###############################################################
#  Generated by:      Cadence Innovus 21.14-s109_1
#  OS:                Linux x86_64(Host ID caen-vnc-mi14.engin.umich.edu)
#  Generated on:      Mon Apr  3 20:47:09 2023
#  Design:            PE_POOL
#  Command:           write_lef_abstract /afs/umich.edu/class/eecs627/w23/groups/group4/CNN_LSTM/CNN_POOL_ReLU/apr/PE_POOL/data/PE_POOL.lef -specifyTopLayer 4 -stripePin -PGpinLayers 4
###############################################################

VERSION 5.8 ;

BUSBITCHARS "[]" ;
DIVIDERCHAR "/" ;

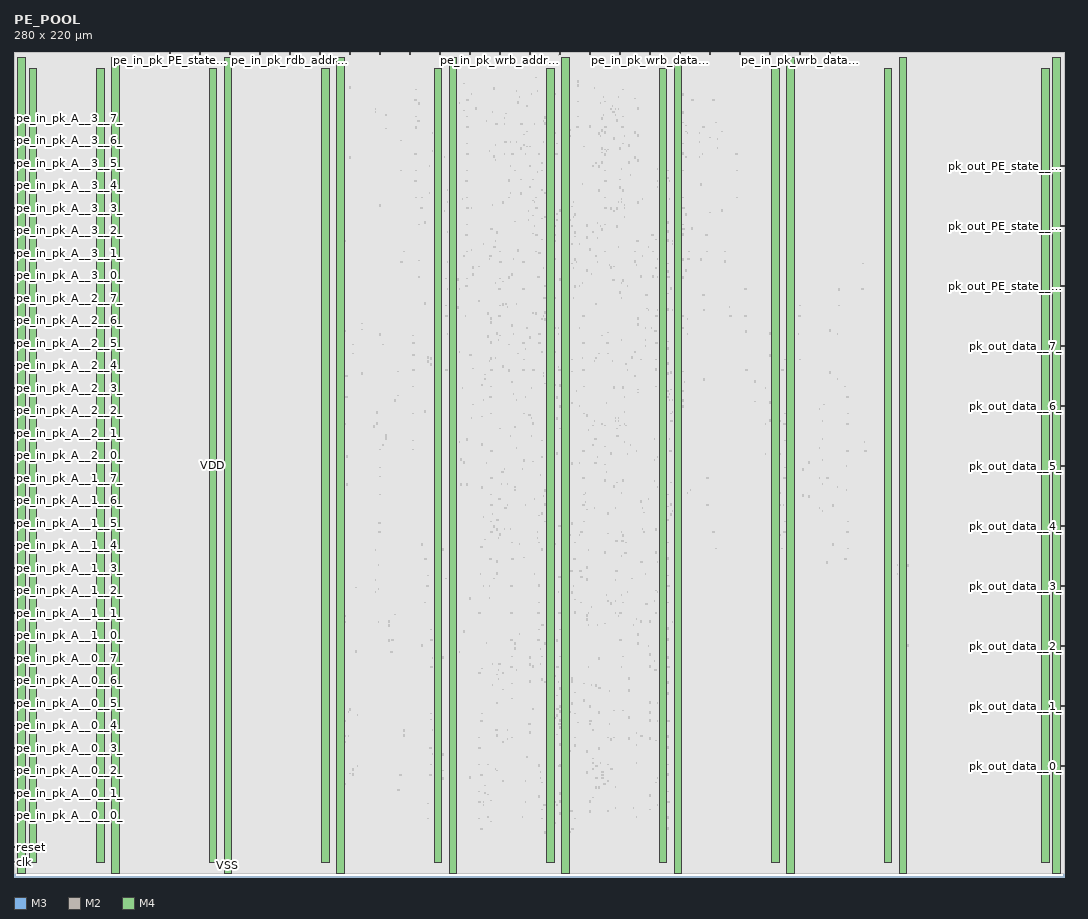
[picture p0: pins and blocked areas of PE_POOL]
MACRO PE_POOL
  CLASS BLOCK ;
  SIZE 280.000000 BY 220.000000 ;
  FOREIGN PE_POOL 0.000000 0.000000 ;
  ORIGIN 0 0 ;
  SYMMETRY X Y R90 ;
  PIN clk
    DIRECTION INPUT ;
    USE SIGNAL ;
    ANTENNAPARTIALMETALAREA 1.82 LAYER M3  ;
    ANTENNAPARTIALMETALSIDEAREA 0.0182 LAYER M3  ;
    ANTENNAPARTIALCUTAREA 0.08 LAYER V3  ;
    ANTENNAPARTIALMETALAREA 1.16 LAYER M4  ;
    ANTENNAPARTIALMETALSIDEAREA 0.012 LAYER M4  ;
    ANTENNAMODEL OXIDE1 ;
    ANTENNAGATEAREA 0.8352 LAYER M4  ;
    ANTENNAMAXAREACAR 2.23946 LAYER M4  ;
    ANTENNAMAXSIDEAREACAR 0.023683 LAYER M4  ;
    ANTENNAMAXCUTCAR 0.287356 LAYER V4  ;
    PORT
      LAYER M3 ;
        RECT 0.000000 3.900000 0.600000 4.100000 ;
    END
  END clk
  PIN reset
    DIRECTION INPUT ;
    USE SIGNAL ;
    ANTENNAPARTIALMETALAREA 1.46 LAYER M3  ;
    ANTENNAPARTIALMETALSIDEAREA 0.015 LAYER M3  ;
    ANTENNAMODEL OXIDE1 ;
    ANTENNAGATEAREA 0.408 LAYER M3  ;
    ANTENNAMAXAREACAR 7.22574 LAYER M3  ;
    ANTENNAMAXSIDEAREACAR 0.0705392 LAYER M3  ;
    ANTENNAMAXCUTCAR 0.392157 LAYER V3  ;
    PORT
      LAYER M3 ;
        RECT 0.000000 7.900000 0.600000 8.100000 ;
    END
  END reset
  PIN pe_in_pk_A__3__7_
    DIRECTION INPUT ;
    USE SIGNAL ;
    ANTENNAPARTIALMETALAREA 1.74 LAYER M3  ;
    ANTENNAPARTIALMETALSIDEAREA 0.0174 LAYER M3  ;
    ANTENNAMODEL OXIDE1 ;
    ANTENNAGATEAREA 0.0624 LAYER M3  ;
    ANTENNAMAXAREACAR 36.0897 LAYER M3  ;
    ANTENNAMAXSIDEAREACAR 0.367949 LAYER M3  ;
    ANTENNAMAXCUTCAR 1.92308 LAYER V3  ;
    PORT
      LAYER M3 ;
        RECT 0.000000 202.300000 0.600000 202.500000 ;
    END
  END pe_in_pk_A__3__7_
  PIN pe_in_pk_A__3__6_
    DIRECTION INPUT ;
    USE SIGNAL ;
    ANTENNAPARTIALMETALAREA 1.66 LAYER M3  ;
    ANTENNAPARTIALMETALSIDEAREA 0.0166 LAYER M3  ;
    ANTENNAMODEL OXIDE1 ;
    ANTENNAGATEAREA 0.0624 LAYER M3  ;
    ANTENNAMAXAREACAR 39.9359 LAYER M3  ;
    ANTENNAMAXSIDEAREACAR 0.40641 LAYER M3  ;
    ANTENNAMAXCUTCAR 1.92308 LAYER V3  ;
    PORT
      LAYER M3 ;
        RECT 0.000000 196.300000 0.600000 196.500000 ;
    END
  END pe_in_pk_A__3__6_
  PIN pe_in_pk_A__3__5_
    DIRECTION INPUT ;
    USE SIGNAL ;
    ANTENNAPARTIALMETALAREA 1.9 LAYER M3  ;
    ANTENNAPARTIALMETALSIDEAREA 0.019 LAYER M3  ;
    ANTENNAPARTIALCUTAREA 0.08 LAYER V3  ;
    ANTENNAPARTIALMETALAREA 1.32 LAYER M4  ;
    ANTENNAPARTIALMETALSIDEAREA 0.0136 LAYER M4  ;
    ANTENNAMODEL OXIDE1 ;
    ANTENNAGATEAREA 0.0624 LAYER M4  ;
    ANTENNAMAXAREACAR 27.4359 LAYER M4  ;
    ANTENNAMAXSIDEAREACAR 0.294231 LAYER M4  ;
    ANTENNAMAXCUTCAR 3.20513 LAYER V4  ;
    PORT
      LAYER M3 ;
        RECT 0.000000 190.300000 0.600000 190.500000 ;
    END
  END pe_in_pk_A__3__5_
  PIN pe_in_pk_A__3__4_
    DIRECTION INPUT ;
    USE SIGNAL ;
    ANTENNAPARTIALMETALAREA 2.02 LAYER M3  ;
    ANTENNAPARTIALMETALSIDEAREA 0.0206 LAYER M3  ;
    ANTENNAMODEL OXIDE1 ;
    ANTENNAGATEAREA 0.0624 LAYER M3  ;
    ANTENNAMAXAREACAR 38.0128 LAYER M3  ;
    ANTENNAMAXSIDEAREACAR 0.39359 LAYER M3  ;
    ANTENNAMAXCUTCAR 1.92308 LAYER V3  ;
    PORT
      LAYER M3 ;
        RECT 0.000000 184.300000 0.600000 184.500000 ;
    END
  END pe_in_pk_A__3__4_
  PIN pe_in_pk_A__3__3_
    DIRECTION INPUT ;
    USE SIGNAL ;
    ANTENNAPARTIALMETALAREA 1.66 LAYER M3  ;
    ANTENNAPARTIALMETALSIDEAREA 0.0166 LAYER M3  ;
    ANTENNAMODEL OXIDE1 ;
    ANTENNAGATEAREA 0.0624 LAYER M3  ;
    ANTENNAMAXAREACAR 51.4744 LAYER M3  ;
    ANTENNAMAXSIDEAREACAR 0.521795 LAYER M3  ;
    ANTENNAMAXCUTCAR 1.92308 LAYER V3  ;
    PORT
      LAYER M3 ;
        RECT 0.000000 178.300000 0.600000 178.500000 ;
    END
  END pe_in_pk_A__3__3_
  PIN pe_in_pk_A__3__2_
    DIRECTION INPUT ;
    USE SIGNAL ;
    ANTENNAPARTIALMETALAREA 1.82 LAYER M3  ;
    ANTENNAPARTIALMETALSIDEAREA 0.0182 LAYER M3  ;
    ANTENNAMODEL OXIDE1 ;
    ANTENNAGATEAREA 0.0624 LAYER M3  ;
    ANTENNAMAXAREACAR 50.1923 LAYER M3  ;
    ANTENNAMAXSIDEAREACAR 0.508974 LAYER M3  ;
    ANTENNAMAXCUTCAR 1.92308 LAYER V3  ;
    PORT
      LAYER M3 ;
        RECT 0.000000 172.300000 0.600000 172.500000 ;
    END
  END pe_in_pk_A__3__2_
  PIN pe_in_pk_A__3__1_
    DIRECTION INPUT ;
    USE SIGNAL ;
    ANTENNAPARTIALMETALAREA 2.38 LAYER M3  ;
    ANTENNAPARTIALMETALSIDEAREA 0.0238 LAYER M3  ;
    ANTENNAMODEL OXIDE1 ;
    ANTENNAGATEAREA 0.0624 LAYER M3  ;
    ANTENNAMAXAREACAR 68.141 LAYER M3  ;
    ANTENNAMAXSIDEAREACAR 0.688462 LAYER M3  ;
    ANTENNAMAXCUTCAR 1.92308 LAYER V3  ;
    PORT
      LAYER M3 ;
        RECT 0.000000 166.300000 0.600000 166.500000 ;
    END
  END pe_in_pk_A__3__1_
  PIN pe_in_pk_A__3__0_
    DIRECTION INPUT ;
    USE SIGNAL ;
    ANTENNAPARTIALMETALAREA 1.9 LAYER M3  ;
    ANTENNAPARTIALMETALSIDEAREA 0.019 LAYER M3  ;
    ANTENNAMODEL OXIDE1 ;
    ANTENNAGATEAREA 0.0624 LAYER M3  ;
    ANTENNAMAXAREACAR 79.6795 LAYER M3  ;
    ANTENNAMAXSIDEAREACAR 0.803846 LAYER M3  ;
    ANTENNAMAXCUTCAR 1.92308 LAYER V3  ;
    PORT
      LAYER M3 ;
        RECT 0.000000 160.300000 0.600000 160.500000 ;
    END
  END pe_in_pk_A__3__0_
  PIN pe_in_pk_A__2__7_
    DIRECTION INPUT ;
    USE SIGNAL ;
    ANTENNAPARTIALMETALAREA 1.5 LAYER M3  ;
    ANTENNAPARTIALMETALSIDEAREA 0.015 LAYER M3  ;
    ANTENNAMODEL OXIDE1 ;
    ANTENNAGATEAREA 0.0624 LAYER M3  ;
    ANTENNAMAXAREACAR 55.3205 LAYER M3  ;
    ANTENNAMAXSIDEAREACAR 0.560256 LAYER M3  ;
    ANTENNAMAXCUTCAR 1.92308 LAYER V3  ;
    PORT
      LAYER M3 ;
        RECT 0.000000 154.300000 0.600000 154.500000 ;
    END
  END pe_in_pk_A__2__7_
  PIN pe_in_pk_A__2__6_
    DIRECTION INPUT ;
    USE SIGNAL ;
    ANTENNAPARTIALMETALAREA 1.58 LAYER M3  ;
    ANTENNAPARTIALMETALSIDEAREA 0.0158 LAYER M3  ;
    ANTENNAMODEL OXIDE1 ;
    ANTENNAGATEAREA 0.0624 LAYER M3  ;
    ANTENNAMAXAREACAR 43.7821 LAYER M3  ;
    ANTENNAMAXSIDEAREACAR 0.444872 LAYER M3  ;
    ANTENNAMAXCUTCAR 1.92308 LAYER V3  ;
    PORT
      LAYER M3 ;
        RECT 0.000000 148.300000 0.600000 148.500000 ;
    END
  END pe_in_pk_A__2__6_
  PIN pe_in_pk_A__2__5_
    DIRECTION INPUT ;
    USE SIGNAL ;
    ANTENNAPARTIALMETALAREA 2.34 LAYER M3  ;
    ANTENNAPARTIALMETALSIDEAREA 0.0238 LAYER M3  ;
    ANTENNAMODEL OXIDE1 ;
    ANTENNAGATEAREA 0.0624 LAYER M3  ;
    ANTENNAMAXAREACAR 45.7051 LAYER M3  ;
    ANTENNAMAXSIDEAREACAR 0.470513 LAYER M3  ;
    ANTENNAMAXCUTCAR 1.92308 LAYER V3  ;
    PORT
      LAYER M3 ;
        RECT 0.000000 142.300000 0.600000 142.500000 ;
    END
  END pe_in_pk_A__2__5_
  PIN pe_in_pk_A__2__4_
    DIRECTION INPUT ;
    USE SIGNAL ;
    ANTENNAPARTIALMETALAREA 2.06 LAYER M3  ;
    ANTENNAPARTIALMETALSIDEAREA 0.0206 LAYER M3  ;
    ANTENNAMODEL OXIDE1 ;
    ANTENNAGATEAREA 0.0624 LAYER M3  ;
    ANTENNAMAXAREACAR 43.7821 LAYER M3  ;
    ANTENNAMAXSIDEAREACAR 0.444872 LAYER M3  ;
    ANTENNAMAXCUTCAR 1.92308 LAYER V3  ;
    PORT
      LAYER M3 ;
        RECT 0.000000 136.300000 0.600000 136.500000 ;
    END
  END pe_in_pk_A__2__4_
  PIN pe_in_pk_A__2__3_
    DIRECTION INPUT ;
    USE SIGNAL ;
    ANTENNAPARTIALMETALAREA 2.06 LAYER M3  ;
    ANTENNAPARTIALMETALSIDEAREA 0.0206 LAYER M3  ;
    ANTENNAMODEL OXIDE1 ;
    ANTENNAGATEAREA 0.0624 LAYER M3  ;
    ANTENNAMAXAREACAR 48.9103 LAYER M3  ;
    ANTENNAMAXSIDEAREACAR 0.496154 LAYER M3  ;
    ANTENNAMAXCUTCAR 1.92308 LAYER V3  ;
    PORT
      LAYER M3 ;
        RECT 0.000000 130.300000 0.600000 130.500000 ;
    END
  END pe_in_pk_A__2__3_
  PIN pe_in_pk_A__2__2_
    DIRECTION INPUT ;
    USE SIGNAL ;
    ANTENNAPARTIALMETALAREA 1.82 LAYER M3  ;
    ANTENNAPARTIALMETALSIDEAREA 0.0182 LAYER M3  ;
    ANTENNAMODEL OXIDE1 ;
    ANTENNAGATEAREA 0.0624 LAYER M3  ;
    ANTENNAMAXAREACAR 33.5256 LAYER M3  ;
    ANTENNAMAXSIDEAREACAR 0.342308 LAYER M3  ;
    ANTENNAMAXCUTCAR 1.92308 LAYER V3  ;
    PORT
      LAYER M3 ;
        RECT 0.000000 124.300000 0.600000 124.500000 ;
    END
  END pe_in_pk_A__2__2_
  PIN pe_in_pk_A__2__1_
    DIRECTION INPUT ;
    USE SIGNAL ;
    ANTENNAPARTIALMETALAREA 1.82 LAYER M3  ;
    ANTENNAPARTIALMETALSIDEAREA 0.0182 LAYER M3  ;
    ANTENNAMODEL OXIDE1 ;
    ANTENNAGATEAREA 0.0624 LAYER M3  ;
    ANTENNAMAXAREACAR 38.6538 LAYER M3  ;
    ANTENNAMAXSIDEAREACAR 0.39359 LAYER M3  ;
    ANTENNAMAXCUTCAR 1.92308 LAYER V3  ;
    PORT
      LAYER M3 ;
        RECT 0.000000 118.300000 0.600000 118.500000 ;
    END
  END pe_in_pk_A__2__1_
  PIN pe_in_pk_A__2__0_
    DIRECTION INPUT ;
    USE SIGNAL ;
    ANTENNAPARTIALMETALAREA 1.9 LAYER M3  ;
    ANTENNAPARTIALMETALSIDEAREA 0.019 LAYER M3  ;
    ANTENNAMODEL OXIDE1 ;
    ANTENNAGATEAREA 0.0624 LAYER M3  ;
    ANTENNAMAXAREACAR 36.0897 LAYER M3  ;
    ANTENNAMAXSIDEAREACAR 0.367949 LAYER M3  ;
    ANTENNAMAXCUTCAR 1.92308 LAYER V3  ;
    PORT
      LAYER M3 ;
        RECT 0.000000 112.300000 0.600000 112.500000 ;
    END
  END pe_in_pk_A__2__0_
  PIN pe_in_pk_A__1__7_
    DIRECTION INPUT ;
    USE SIGNAL ;
    ANTENNAPARTIALMETALAREA 1.82 LAYER M3  ;
    ANTENNAPARTIALMETALSIDEAREA 0.0182 LAYER M3  ;
    ANTENNAMODEL OXIDE1 ;
    ANTENNAGATEAREA 0.0624 LAYER M3  ;
    ANTENNAMAXAREACAR 36.0897 LAYER M3  ;
    ANTENNAMAXSIDEAREACAR 0.367949 LAYER M3  ;
    ANTENNAMAXCUTCAR 1.92308 LAYER V3  ;
    PORT
      LAYER M3 ;
        RECT 0.000000 106.300000 0.600000 106.500000 ;
    END
  END pe_in_pk_A__1__7_
  PIN pe_in_pk_A__1__6_
    DIRECTION INPUT ;
    USE SIGNAL ;
    ANTENNAPARTIALMETALAREA 1.9 LAYER M3  ;
    ANTENNAPARTIALMETALSIDEAREA 0.019 LAYER M3  ;
    ANTENNAMODEL OXIDE1 ;
    ANTENNAGATEAREA 0.0624 LAYER M3  ;
    ANTENNAMAXAREACAR 39.9359 LAYER M3  ;
    ANTENNAMAXSIDEAREACAR 0.40641 LAYER M3  ;
    ANTENNAMAXCUTCAR 1.92308 LAYER V3  ;
    PORT
      LAYER M3 ;
        RECT 0.000000 100.300000 0.600000 100.500000 ;
    END
  END pe_in_pk_A__1__6_
  PIN pe_in_pk_A__1__5_
    DIRECTION INPUT ;
    USE SIGNAL ;
    ANTENNAPARTIALMETALAREA 1.58 LAYER M3  ;
    ANTENNAPARTIALMETALSIDEAREA 0.0158 LAYER M3  ;
    ANTENNAMODEL OXIDE1 ;
    ANTENNAGATEAREA 0.0624 LAYER M3  ;
    ANTENNAMAXAREACAR 33.5256 LAYER M3  ;
    ANTENNAMAXSIDEAREACAR 0.342308 LAYER M3  ;
    ANTENNAMAXCUTCAR 1.92308 LAYER V3  ;
    PORT
      LAYER M3 ;
        RECT 0.000000 94.300000 0.600000 94.500000 ;
    END
  END pe_in_pk_A__1__5_
  PIN pe_in_pk_A__1__4_
    DIRECTION INPUT ;
    USE SIGNAL ;
    ANTENNAPARTIALMETALAREA 2.06 LAYER M3  ;
    ANTENNAPARTIALMETALSIDEAREA 0.0206 LAYER M3  ;
    ANTENNAMODEL OXIDE1 ;
    ANTENNAGATEAREA 0.0624 LAYER M3  ;
    ANTENNAMAXAREACAR 59.1667 LAYER M3  ;
    ANTENNAMAXSIDEAREACAR 0.598718 LAYER M3  ;
    ANTENNAMAXCUTCAR 1.92308 LAYER V3  ;
    PORT
      LAYER M3 ;
        RECT 0.000000 88.300000 0.600000 88.500000 ;
    END
  END pe_in_pk_A__1__4_
  PIN pe_in_pk_A__1__3_
    DIRECTION INPUT ;
    USE SIGNAL ;
    ANTENNAPARTIALMETALAREA 1.5 LAYER M3  ;
    ANTENNAPARTIALMETALSIDEAREA 0.015 LAYER M3  ;
    ANTENNAMODEL OXIDE1 ;
    ANTENNAGATEAREA 0.0624 LAYER M3  ;
    ANTENNAMAXAREACAR 30.9615 LAYER M3  ;
    ANTENNAMAXSIDEAREACAR 0.316667 LAYER M3  ;
    ANTENNAMAXCUTCAR 1.92308 LAYER V3  ;
    PORT
      LAYER M3 ;
        RECT 0.000000 82.300000 0.600000 82.500000 ;
    END
  END pe_in_pk_A__1__3_
  PIN pe_in_pk_A__1__2_
    DIRECTION INPUT ;
    USE SIGNAL ;
    ANTENNAPARTIALMETALAREA 1.42 LAYER M3  ;
    ANTENNAPARTIALMETALSIDEAREA 0.0142 LAYER M3  ;
    ANTENNAMODEL OXIDE1 ;
    ANTENNAGATEAREA 0.0624 LAYER M3  ;
    ANTENNAMAXAREACAR 57.8846 LAYER M3  ;
    ANTENNAMAXSIDEAREACAR 0.585897 LAYER M3  ;
    ANTENNAMAXCUTCAR 1.92308 LAYER V3  ;
    PORT
      LAYER M3 ;
        RECT 0.000000 76.300000 0.600000 76.500000 ;
    END
  END pe_in_pk_A__1__2_
  PIN pe_in_pk_A__1__1_
    DIRECTION INPUT ;
    USE SIGNAL ;
    ANTENNAPARTIALMETALAREA 1.42 LAYER M3  ;
    ANTENNAPARTIALMETALSIDEAREA 0.0142 LAYER M3  ;
    ANTENNAMODEL OXIDE1 ;
    ANTENNAGATEAREA 0.0624 LAYER M3  ;
    ANTENNAMAXAREACAR 52.7564 LAYER M3  ;
    ANTENNAMAXSIDEAREACAR 0.534615 LAYER M3  ;
    ANTENNAMAXCUTCAR 1.92308 LAYER V3  ;
    PORT
      LAYER M3 ;
        RECT 0.000000 70.300000 0.600000 70.500000 ;
    END
  END pe_in_pk_A__1__1_
  PIN pe_in_pk_A__1__0_
    DIRECTION INPUT ;
    USE SIGNAL ;
    ANTENNAPARTIALMETALAREA 0.7 LAYER M3  ;
    ANTENNAPARTIALMETALSIDEAREA 0.007 LAYER M3  ;
    ANTENNAPARTIALCUTAREA 0.08 LAYER V3  ;
    ANTENNAPARTIALMETALAREA 1.88 LAYER M4  ;
    ANTENNAPARTIALMETALSIDEAREA 0.0192 LAYER M4  ;
    ANTENNAMODEL OXIDE1 ;
    ANTENNAGATEAREA 0.0624 LAYER M4  ;
    ANTENNAMAXAREACAR 51.7949 LAYER M4  ;
    ANTENNAMAXSIDEAREACAR 0.537821 LAYER M4  ;
    ANTENNAMAXCUTCAR 3.20513 LAYER V4  ;
    PORT
      LAYER M3 ;
        RECT 0.000000 64.300000 0.600000 64.500000 ;
    END
  END pe_in_pk_A__1__0_
  PIN pe_in_pk_A__0__7_
    DIRECTION INPUT ;
    USE SIGNAL ;
    ANTENNAPARTIALMETALAREA 2.02 LAYER M3  ;
    ANTENNAPARTIALMETALSIDEAREA 0.0206 LAYER M3  ;
    ANTENNAMODEL OXIDE1 ;
    ANTENNAGATEAREA 0.0624 LAYER M3  ;
    ANTENNAMAXAREACAR 43.141 LAYER M3  ;
    ANTENNAMAXSIDEAREACAR 0.444872 LAYER M3  ;
    ANTENNAMAXCUTCAR 1.92308 LAYER V3  ;
    PORT
      LAYER M3 ;
        RECT 0.000000 58.300000 0.600000 58.500000 ;
    END
  END pe_in_pk_A__0__7_
  PIN pe_in_pk_A__0__6_
    DIRECTION INPUT ;
    USE SIGNAL ;
    ANTENNAPARTIALMETALAREA 1.98 LAYER M3  ;
    ANTENNAPARTIALMETALSIDEAREA 0.0198 LAYER M3  ;
    ANTENNAMODEL OXIDE1 ;
    ANTENNAGATEAREA 0.0624 LAYER M3  ;
    ANTENNAMAXAREACAR 51.4744 LAYER M3  ;
    ANTENNAMAXSIDEAREACAR 0.521795 LAYER M3  ;
    ANTENNAMAXCUTCAR 1.92308 LAYER V3  ;
    PORT
      LAYER M3 ;
        RECT 0.000000 52.300000 0.600000 52.500000 ;
    END
  END pe_in_pk_A__0__6_
  PIN pe_in_pk_A__0__5_
    DIRECTION INPUT ;
    USE SIGNAL ;
    ANTENNAPARTIALMETALAREA 1.74 LAYER M3  ;
    ANTENNAPARTIALMETALSIDEAREA 0.0174 LAYER M3  ;
    ANTENNAMODEL OXIDE1 ;
    ANTENNAGATEAREA 0.0624 LAYER M3  ;
    ANTENNAMAXAREACAR 34.8077 LAYER M3  ;
    ANTENNAMAXSIDEAREACAR 0.355128 LAYER M3  ;
    ANTENNAMAXCUTCAR 1.92308 LAYER V3  ;
    PORT
      LAYER M3 ;
        RECT 0.000000 46.300000 0.600000 46.500000 ;
    END
  END pe_in_pk_A__0__5_
  PIN pe_in_pk_A__0__4_
    DIRECTION INPUT ;
    USE SIGNAL ;
    ANTENNAPARTIALMETALAREA 1.74 LAYER M3  ;
    ANTENNAPARTIALMETALSIDEAREA 0.0174 LAYER M3  ;
    ANTENNAMODEL OXIDE1 ;
    ANTENNAGATEAREA 0.0624 LAYER M3  ;
    ANTENNAMAXAREACAR 38.6538 LAYER M3  ;
    ANTENNAMAXSIDEAREACAR 0.39359 LAYER M3  ;
    ANTENNAMAXCUTCAR 1.92308 LAYER V3  ;
    PORT
      LAYER M3 ;
        RECT 0.000000 40.300000 0.600000 40.500000 ;
    END
  END pe_in_pk_A__0__4_
  PIN pe_in_pk_A__0__3_
    DIRECTION INPUT ;
    USE SIGNAL ;
    ANTENNAPARTIALMETALAREA 1.74 LAYER M3  ;
    ANTENNAPARTIALMETALSIDEAREA 0.0174 LAYER M3  ;
    ANTENNAMODEL OXIDE1 ;
    ANTENNAGATEAREA 0.0624 LAYER M3  ;
    ANTENNAMAXAREACAR 33.5256 LAYER M3  ;
    ANTENNAMAXSIDEAREACAR 0.342308 LAYER M3  ;
    ANTENNAMAXCUTCAR 1.92308 LAYER V3  ;
    PORT
      LAYER M3 ;
        RECT 0.000000 34.300000 0.600000 34.500000 ;
    END
  END pe_in_pk_A__0__3_
  PIN pe_in_pk_A__0__2_
    DIRECTION INPUT ;
    USE SIGNAL ;
    ANTENNAPARTIALMETALAREA 1.74 LAYER M3  ;
    ANTENNAPARTIALMETALSIDEAREA 0.0174 LAYER M3  ;
    ANTENNAMODEL OXIDE1 ;
    ANTENNAGATEAREA 0.0624 LAYER M3  ;
    ANTENNAMAXAREACAR 37.3718 LAYER M3  ;
    ANTENNAMAXSIDEAREACAR 0.380769 LAYER M3  ;
    ANTENNAMAXCUTCAR 1.92308 LAYER V3  ;
    PORT
      LAYER M3 ;
        RECT 0.000000 28.300000 0.600000 28.500000 ;
    END
  END pe_in_pk_A__0__2_
  PIN pe_in_pk_A__0__1_
    DIRECTION INPUT ;
    USE SIGNAL ;
    ANTENNAPARTIALMETALAREA 1.74 LAYER M3  ;
    ANTENNAPARTIALMETALSIDEAREA 0.0174 LAYER M3  ;
    ANTENNAMODEL OXIDE1 ;
    ANTENNAGATEAREA 0.0624 LAYER M3  ;
    ANTENNAMAXAREACAR 34.8077 LAYER M3  ;
    ANTENNAMAXSIDEAREACAR 0.355128 LAYER M3  ;
    ANTENNAMAXCUTCAR 1.92308 LAYER V3  ;
    PORT
      LAYER M3 ;
        RECT 0.000000 22.300000 0.600000 22.500000 ;
    END
  END pe_in_pk_A__0__1_
  PIN pe_in_pk_A__0__0_
    DIRECTION INPUT ;
    USE SIGNAL ;
    ANTENNAPARTIALMETALAREA 1.66 LAYER M3  ;
    ANTENNAPARTIALMETALSIDEAREA 0.0166 LAYER M3  ;
    ANTENNAMODEL OXIDE1 ;
    ANTENNAGATEAREA 0.0624 LAYER M3  ;
    ANTENNAMAXAREACAR 30.9615 LAYER M3  ;
    ANTENNAMAXSIDEAREACAR 0.316667 LAYER M3  ;
    ANTENNAMAXCUTCAR 1.92308 LAYER V3  ;
    PORT
      LAYER M3 ;
        RECT 0.000000 16.300000 0.600000 16.500000 ;
    END
  END pe_in_pk_A__0__0_
  PIN pe_in_pk_PE_state__2_
    DIRECTION INPUT ;
    USE SIGNAL ;
    ANTENNAPARTIALMETALAREA 0.06 LAYER M2  ;
    ANTENNAPARTIALMETALSIDEAREA 0.0006 LAYER M2  ;
    ANTENNAPARTIALCUTAREA 0.04 LAYER V2  ;
    ANTENNAPARTIALMETALAREA 3.64 LAYER M3  ;
    ANTENNAPARTIALMETALSIDEAREA 0.0368 LAYER M3  ;
    ANTENNAMODEL OXIDE1 ;
    ANTENNAGATEAREA 0.0624 LAYER M3  ;
    ANTENNAMAXAREACAR 89.6154 LAYER M3  ;
    ANTENNAMAXSIDEAREACAR 0.909615 LAYER M3  ;
    ANTENNAMAXCUTCAR 1.92308 LAYER V3  ;
    PORT
      LAYER M2 ;
        RECT 57.500000 219.400000 57.700000 220.000000 ;
    END
  END pe_in_pk_PE_state__2_
  PIN pe_in_pk_PE_state__1_
    DIRECTION INPUT ;
    USE SIGNAL ;
    ANTENNAPARTIALMETALAREA 1.34 LAYER M2  ;
    ANTENNAPARTIALMETALSIDEAREA 0.0134 LAYER M2  ;
    ANTENNAPARTIALCUTAREA 0.08 LAYER V2  ;
    ANTENNAPARTIALMETALAREA 3.88 LAYER M3  ;
    ANTENNAPARTIALMETALSIDEAREA 0.0392 LAYER M3  ;
    ANTENNAMODEL OXIDE1 ;
    ANTENNAGATEAREA 0.0624 LAYER M3  ;
    ANTENNAMAXAREACAR 72.9487 LAYER M3  ;
    ANTENNAMAXSIDEAREACAR 0.742949 LAYER M3  ;
    ANTENNAMAXCUTCAR 1.92308 LAYER V3  ;
    PORT
      LAYER M2 ;
        RECT 49.500000 219.400000 49.700000 220.000000 ;
    END
  END pe_in_pk_PE_state__1_
  PIN pe_in_pk_PE_state__0_
    DIRECTION INPUT ;
    USE SIGNAL ;
    ANTENNAPARTIALMETALAREA 0.16 LAYER M2  ;
    ANTENNAPARTIALMETALSIDEAREA 0.0016 LAYER M2  ;
    ANTENNAPARTIALCUTAREA 0.08 LAYER V2  ;
    ANTENNAPARTIALMETALAREA 5.8 LAYER M3  ;
    ANTENNAPARTIALMETALSIDEAREA 0.0584 LAYER M3  ;
    ANTENNAMODEL OXIDE1 ;
    ANTENNAGATEAREA 0.0624 LAYER M3  ;
    ANTENNAMAXAREACAR 140.897 LAYER M3  ;
    ANTENNAMAXSIDEAREACAR 1.42244 LAYER M3  ;
    ANTENNAMAXCUTCAR 1.92308 LAYER V3  ;
    PORT
      LAYER M2 ;
        RECT 41.500000 219.400000 41.700000 220.000000 ;
    END
  END pe_in_pk_PE_state__0_
  PIN pe_in_pk_wrb_data__7_
    DIRECTION INPUT ;
    USE SIGNAL ;
    ANTENNAPARTIALMETALAREA 1.34 LAYER M2  ;
    ANTENNAPARTIALMETALSIDEAREA 0.0134 LAYER M2  ;
    ANTENNAPARTIALCUTAREA 0.08 LAYER V2  ;
    ANTENNAPARTIALMETALAREA 4.92 LAYER M3  ;
    ANTENNAPARTIALMETALSIDEAREA 0.0496 LAYER M3  ;
    ANTENNAMODEL OXIDE1 ;
    ANTENNAGATEAREA 0.0624 LAYER M3  ;
    ANTENNAMAXAREACAR 89.6154 LAYER M3  ;
    ANTENNAMAXSIDEAREACAR 0.909615 LAYER M3  ;
    ANTENNAMAXCUTCAR 1.92308 LAYER V3  ;
    PORT
      LAYER M2 ;
        RECT 217.500000 219.400000 217.700000 220.000000 ;
    END
  END pe_in_pk_wrb_data__7_
  PIN pe_in_pk_wrb_data__6_
    DIRECTION INPUT ;
    USE SIGNAL ;
    ANTENNAPARTIALMETALAREA 1.9 LAYER M2  ;
    ANTENNAPARTIALMETALSIDEAREA 0.019 LAYER M2  ;
    ANTENNAPARTIALCUTAREA 0.08 LAYER V2  ;
    ANTENNAPARTIALMETALAREA 3.56 LAYER M3  ;
    ANTENNAPARTIALMETALSIDEAREA 0.036 LAYER M3  ;
    ANTENNAMODEL OXIDE1 ;
    ANTENNAGATEAREA 0.0624 LAYER M3  ;
    ANTENNAMAXAREACAR 61.4103 LAYER M3  ;
    ANTENNAMAXSIDEAREACAR 0.627564 LAYER M3  ;
    ANTENNAMAXCUTCAR 1.92308 LAYER V3  ;
    PORT
      LAYER M2 ;
        RECT 209.500000 219.400000 209.700000 220.000000 ;
    END
  END pe_in_pk_wrb_data__6_
  PIN pe_in_pk_wrb_data__5_
    DIRECTION INPUT ;
    USE SIGNAL ;
    ANTENNAPARTIALMETALAREA 1.5 LAYER M2  ;
    ANTENNAPARTIALMETALSIDEAREA 0.015 LAYER M2  ;
    ANTENNAPARTIALCUTAREA 0.08 LAYER V2  ;
    ANTENNAPARTIALMETALAREA 1.24 LAYER M3  ;
    ANTENNAPARTIALMETALSIDEAREA 0.0128 LAYER M3  ;
    ANTENNAMODEL OXIDE1 ;
    ANTENNAGATEAREA 0.0624 LAYER M3  ;
    ANTENNAMAXAREACAR 28.0769 LAYER M3  ;
    ANTENNAMAXSIDEAREACAR 0.294231 LAYER M3  ;
    ANTENNAMAXCUTCAR 1.92308 LAYER V3  ;
    PORT
      LAYER M2 ;
        RECT 201.500000 219.400000 201.700000 220.000000 ;
    END
  END pe_in_pk_wrb_data__5_
  PIN pe_in_pk_wrb_data__4_
    DIRECTION INPUT ;
    USE SIGNAL ;
    ANTENNAPARTIALMETALAREA 1.5 LAYER M2  ;
    ANTENNAPARTIALMETALSIDEAREA 0.015 LAYER M2  ;
    ANTENNAPARTIALCUTAREA 0.08 LAYER V2  ;
    ANTENNAPARTIALMETALAREA 0.84 LAYER M3  ;
    ANTENNAPARTIALMETALSIDEAREA 0.0088 LAYER M3  ;
    ANTENNAMODEL OXIDE1 ;
    ANTENNAGATEAREA 0.2472 LAYER M3  ;
    ANTENNAMAXAREACAR 5.6699 LAYER M3  ;
    ANTENNAMAXSIDEAREACAR 0.0606796 LAYER M3  ;
    ANTENNAMAXCUTCAR 0.485437 LAYER V3  ;
    PORT
      LAYER M2 ;
        RECT 193.500000 219.400000 193.700000 220.000000 ;
    END
  END pe_in_pk_wrb_data__4_
  PIN pe_in_pk_wrb_data__3_
    DIRECTION INPUT ;
    USE SIGNAL ;
    ANTENNAPARTIALMETALAREA 1.42 LAYER M2  ;
    ANTENNAPARTIALMETALSIDEAREA 0.0142 LAYER M2  ;
    ANTENNAPARTIALCUTAREA 0.08 LAYER V2  ;
    ANTENNAPARTIALMETALAREA 1.4 LAYER M3  ;
    ANTENNAPARTIALMETALSIDEAREA 0.0144 LAYER M3  ;
    ANTENNAMODEL OXIDE1 ;
    ANTENNAGATEAREA 0.0624 LAYER M3  ;
    ANTENNAMAXAREACAR 31.9231 LAYER M3  ;
    ANTENNAMAXSIDEAREACAR 0.332692 LAYER M3  ;
    ANTENNAMAXCUTCAR 1.92308 LAYER V3  ;
    PORT
      LAYER M2 ;
        RECT 185.500000 219.400000 185.700000 220.000000 ;
    END
  END pe_in_pk_wrb_data__3_
  PIN pe_in_pk_wrb_data__2_
    DIRECTION INPUT ;
    USE SIGNAL ;
    ANTENNAPARTIALMETALAREA 0.06 LAYER M2  ;
    ANTENNAPARTIALMETALSIDEAREA 0.0006 LAYER M2  ;
    ANTENNAPARTIALCUTAREA 0.04 LAYER V2  ;
    ANTENNAPARTIALMETALAREA 2.2 LAYER M3  ;
    ANTENNAPARTIALMETALSIDEAREA 0.0224 LAYER M3  ;
    ANTENNAMODEL OXIDE1 ;
    ANTENNAGATEAREA 0.1272 LAYER M3  ;
    ANTENNAMAXAREACAR 33.0818 LAYER M3  ;
    ANTENNAMAXSIDEAREACAR 0.337107 LAYER M3  ;
    ANTENNAMAXCUTCAR 1.25786 LAYER V3  ;
    PORT
      LAYER M2 ;
        RECT 177.500000 219.400000 177.700000 220.000000 ;
    END
  END pe_in_pk_wrb_data__2_
  PIN pe_in_pk_wrb_data__1_
    DIRECTION INPUT ;
    USE SIGNAL ;
    ANTENNAPARTIALMETALAREA 1.5 LAYER M2  ;
    ANTENNAPARTIALMETALSIDEAREA 0.015 LAYER M2  ;
    ANTENNAPARTIALCUTAREA 0.08 LAYER V2  ;
    ANTENNAPARTIALMETALAREA 1.16 LAYER M3  ;
    ANTENNAPARTIALMETALSIDEAREA 0.012 LAYER M3  ;
    ANTENNAMODEL OXIDE1 ;
    ANTENNAGATEAREA 0.0624 LAYER M3  ;
    ANTENNAMAXAREACAR 43.4615 LAYER M3  ;
    ANTENNAMAXSIDEAREACAR 0.448077 LAYER M3  ;
    ANTENNAMAXCUTCAR 1.92308 LAYER V3  ;
    PORT
      LAYER M2 ;
        RECT 169.500000 219.400000 169.700000 220.000000 ;
    END
  END pe_in_pk_wrb_data__1_
  PIN pe_in_pk_wrb_data__0_
    DIRECTION INPUT ;
    USE SIGNAL ;
    ANTENNAPARTIALMETALAREA 1.5 LAYER M2  ;
    ANTENNAPARTIALMETALSIDEAREA 0.015 LAYER M2  ;
    ANTENNAPARTIALCUTAREA 0.08 LAYER V2  ;
    ANTENNAPARTIALMETALAREA 2.44 LAYER M3  ;
    ANTENNAPARTIALMETALSIDEAREA 0.0248 LAYER M3  ;
    ANTENNAPARTIALCUTAREA 0.08 LAYER V3  ;
    ANTENNAPARTIALMETALAREA 0.36 LAYER M4  ;
    ANTENNAPARTIALMETALSIDEAREA 0.004 LAYER M4  ;
    ANTENNAMODEL OXIDE1 ;
    ANTENNAGATEAREA 0.0624 LAYER M4  ;
    ANTENNAMAXAREACAR 24.8718 LAYER M4  ;
    ANTENNAMAXSIDEAREACAR 0.26859 LAYER M4  ;
    ANTENNAMAXCUTCAR 3.20513 LAYER V4  ;
    PORT
      LAYER M2 ;
        RECT 161.500000 219.400000 161.700000 220.000000 ;
    END
  END pe_in_pk_wrb_data__0_
  PIN pe_in_pk_wrb_addr__3_
    DIRECTION INPUT ;
    USE SIGNAL ;
    ANTENNAPARTIALMETALAREA 0.16 LAYER M2  ;
    ANTENNAPARTIALMETALSIDEAREA 0.0016 LAYER M2  ;
    ANTENNAPARTIALCUTAREA 0.08 LAYER V2  ;
    ANTENNAPARTIALMETALAREA 3.84 LAYER M3  ;
    ANTENNAPARTIALMETALSIDEAREA 0.0392 LAYER M3  ;
    ANTENNAMODEL OXIDE1 ;
    ANTENNAGATEAREA 0.564 LAYER M3  ;
    ANTENNAMAXAREACAR 15.4918 LAYER M3  ;
    ANTENNAMAXSIDEAREACAR 0.155261 LAYER M3  ;
    ANTENNAMAXCUTCAR 0.454545 LAYER V3  ;
    PORT
      LAYER M2 ;
        RECT 153.500000 219.400000 153.700000 220.000000 ;
    END
  END pe_in_pk_wrb_addr__3_
  PIN pe_in_pk_wrb_addr__2_
    DIRECTION INPUT ;
    USE SIGNAL ;
    ANTENNAPARTIALMETALAREA 0.06 LAYER M2  ;
    ANTENNAPARTIALMETALSIDEAREA 0.0006 LAYER M2  ;
    ANTENNAPARTIALCUTAREA 0.04 LAYER V2  ;
    ANTENNAPARTIALMETALAREA 2.92 LAYER M3  ;
    ANTENNAPARTIALMETALSIDEAREA 0.0296 LAYER M3  ;
    ANTENNAMODEL OXIDE1 ;
    ANTENNAGATEAREA 0.396 LAYER M3  ;
    ANTENNAMAXAREACAR 12.6061 LAYER M3  ;
    ANTENNAMAXSIDEAREACAR 0.128081 LAYER M3  ;
    ANTENNAPARTIALCUTAREA 0.04 LAYER V3  ;
    ANTENNAMAXCUTCAR 0.30303 LAYER V3  ;
    ANTENNAPARTIALMETALAREA 9.68 LAYER M4  ;
    ANTENNAPARTIALMETALSIDEAREA 0.0976 LAYER M4  ;
    ANTENNAGATEAREA 1.3896 LAYER M4  ;
    ANTENNAMAXAREACAR 19.5721 LAYER M4  ;
    ANTENNAMAXSIDEAREACAR 0.204819 LAYER M4  ;
    ANTENNAMAXCUTCAR 2.41667 LAYER V4  ;
    PORT
      LAYER M2 ;
        RECT 145.500000 219.400000 145.700000 220.000000 ;
    END
  END pe_in_pk_wrb_addr__2_
  PIN pe_in_pk_wrb_addr__1_
    DIRECTION INPUT ;
    USE SIGNAL ;
    ANTENNAPARTIALMETALAREA 0.06 LAYER M2  ;
    ANTENNAPARTIALMETALSIDEAREA 0.0006 LAYER M2  ;
    ANTENNAPARTIALCUTAREA 0.04 LAYER V2  ;
    ANTENNAPARTIALMETALAREA 2.08 LAYER M3  ;
    ANTENNAPARTIALMETALSIDEAREA 0.0216 LAYER M3  ;
    ANTENNAMODEL OXIDE1 ;
    ANTENNAGATEAREA 0.396 LAYER M3  ;
    ANTENNAMAXAREACAR 12.2343 LAYER M3  ;
    ANTENNAMAXSIDEAREACAR 0.128283 LAYER M3  ;
    ANTENNAPARTIALCUTAREA 0.04 LAYER V3  ;
    ANTENNAMAXCUTCAR 0.40404 LAYER V3  ;
    ANTENNAPARTIALMETALAREA 6.6 LAYER M4  ;
    ANTENNAPARTIALMETALSIDEAREA 0.0664 LAYER M4  ;
    ANTENNAGATEAREA 1.1496 LAYER M4  ;
    ANTENNAMAXAREACAR 17.9755 LAYER M4  ;
    ANTENNAMAXSIDEAREACAR 0.186042 LAYER M4  ;
    ANTENNAMAXCUTCAR 0.543275 LAYER V4  ;
    PORT
      LAYER M2 ;
        RECT 137.500000 219.400000 137.700000 220.000000 ;
    END
  END pe_in_pk_wrb_addr__1_
  PIN pe_in_pk_wrb_addr__0_
    DIRECTION INPUT ;
    USE SIGNAL ;
    ANTENNAPARTIALCUTAREA 0.04 LAYER V2  ;
    ANTENNAPARTIALMETALAREA 0.96 LAYER M3  ;
    ANTENNAPARTIALMETALSIDEAREA 0.0104 LAYER M3  ;
    ANTENNAMODEL OXIDE1 ;
    ANTENNAGATEAREA 0.396 LAYER M3  ;
    ANTENNAMAXAREACAR 8.57374 LAYER M3  ;
    ANTENNAMAXSIDEAREACAR 0.090101 LAYER M3  ;
    ANTENNAPARTIALCUTAREA 0.04 LAYER V3  ;
    ANTENNAMAXCUTCAR 0.40404 LAYER V3  ;
    ANTENNAPARTIALMETALAREA 7.56 LAYER M4  ;
    ANTENNAPARTIALMETALSIDEAREA 0.0768 LAYER M4  ;
    ANTENNAGATEAREA 1.1496 LAYER M4  ;
    ANTENNAMAXAREACAR 15.1499 LAYER M4  ;
    ANTENNAMAXSIDEAREACAR 0.156907 LAYER M4  ;
    ANTENNAMAXCUTCAR 1.22549 LAYER V4  ;
    PORT
      LAYER M2 ;
        RECT 129.500000 219.400000 129.700000 220.000000 ;
    END
  END pe_in_pk_wrb_addr__0_
  PIN pe_in_pk_wrb__3_
    DIRECTION INPUT ;
    USE SIGNAL ;
    ANTENNAPARTIALMETALAREA 1.74 LAYER M2  ;
    ANTENNAPARTIALMETALSIDEAREA 0.0174 LAYER M2  ;
    ANTENNAMODEL OXIDE1 ;
    ANTENNAGATEAREA 0.2952 LAYER M2  ;
    ANTENNAMAXAREACAR 6.28455 LAYER M2  ;
    ANTENNAMAXSIDEAREACAR 0.0635501 LAYER M2  ;
    ANTENNAMAXCUTCAR 0.135501 LAYER V2  ;
    PORT
      LAYER M2 ;
        RECT 121.500000 219.400000 121.700000 220.000000 ;
    END
  END pe_in_pk_wrb__3_
  PIN pe_in_pk_wrb__2_
    DIRECTION INPUT ;
    USE SIGNAL ;
    ANTENNAPARTIALMETALAREA 1.58 LAYER M2  ;
    ANTENNAPARTIALMETALSIDEAREA 0.0158 LAYER M2  ;
    ANTENNAPARTIALCUTAREA 0.04 LAYER V2  ;
    ANTENNAPARTIALMETALAREA 1 LAYER M3  ;
    ANTENNAPARTIALMETALSIDEAREA 0.0104 LAYER M3  ;
    ANTENNAMODEL OXIDE1 ;
    ANTENNAGATEAREA 0.5928 LAYER M3  ;
    ANTENNAMAXAREACAR 3.05938 LAYER M3  ;
    ANTENNAMAXSIDEAREACAR 0.0318826 LAYER M3  ;
    ANTENNAMAXCUTCAR 0.134953 LAYER V3  ;
    PORT
      LAYER M2 ;
        RECT 113.500000 219.400000 113.700000 220.000000 ;
    END
  END pe_in_pk_wrb__2_
  PIN pe_in_pk_wrb__1_
    DIRECTION INPUT ;
    USE SIGNAL ;
    ANTENNAPARTIALMETALAREA 1.26 LAYER M2  ;
    ANTENNAPARTIALMETALSIDEAREA 0.0126 LAYER M2  ;
    ANTENNAPARTIALCUTAREA 0.04 LAYER V2  ;
    ANTENNAPARTIALMETALAREA 3.88 LAYER M3  ;
    ANTENNAPARTIALMETALSIDEAREA 0.0392 LAYER M3  ;
    ANTENNAMODEL OXIDE1 ;
    ANTENNAGATEAREA 0.5928 LAYER M3  ;
    ANTENNAMAXAREACAR 8.45749 LAYER M3  ;
    ANTENNAMAXSIDEAREACAR 0.0858637 LAYER M3  ;
    ANTENNAMAXCUTCAR 0.134953 LAYER V3  ;
    PORT
      LAYER M2 ;
        RECT 105.500000 219.400000 105.700000 220.000000 ;
    END
  END pe_in_pk_wrb__1_
  PIN pe_in_pk_wrb__0_
    DIRECTION INPUT ;
    USE SIGNAL ;
    ANTENNAPARTIALMETALAREA 1.42 LAYER M2  ;
    ANTENNAPARTIALMETALSIDEAREA 0.0142 LAYER M2  ;
    ANTENNAPARTIALCUTAREA 0.08 LAYER V2  ;
    ANTENNAPARTIALMETALAREA 6.12 LAYER M3  ;
    ANTENNAPARTIALMETALSIDEAREA 0.0616 LAYER M3  ;
    ANTENNAMODEL OXIDE1 ;
    ANTENNAGATEAREA 0.2952 LAYER M3  ;
    ANTENNAMAXAREACAR 22.6125 LAYER M3  ;
    ANTENNAMAXSIDEAREACAR 0.229539 LAYER M3  ;
    ANTENNAMAXCUTCAR 0.406504 LAYER V3  ;
    PORT
      LAYER M2 ;
        RECT 97.500000 219.400000 97.700000 220.000000 ;
    END
  END pe_in_pk_wrb__0_
  PIN pe_in_pk_rdb_addr__3_
    DIRECTION INPUT ;
    USE SIGNAL ;
    ANTENNAPARTIALMETALAREA 1.82 LAYER M2  ;
    ANTENNAPARTIALMETALSIDEAREA 0.0182 LAYER M2  ;
    ANTENNAPARTIALCUTAREA 0.08 LAYER V2  ;
    ANTENNAPARTIALMETALAREA 0.12 LAYER M3  ;
    ANTENNAPARTIALMETALSIDEAREA 0.0016 LAYER M3  ;
    ANTENNAPARTIALCUTAREA 0.08 LAYER V3  ;
    ANTENNAPARTIALMETALAREA 6.8 LAYER M4  ;
    ANTENNAPARTIALMETALSIDEAREA 0.0688 LAYER M4  ;
    ANTENNAMODEL OXIDE1 ;
    ANTENNAGATEAREA 0.3192 LAYER M4  ;
    ANTENNAMAXAREACAR 57.1186 LAYER M4  ;
    ANTENNAMAXSIDEAREACAR 0.579385 LAYER M4  ;
    ANTENNAMAXCUTCAR 1.79487 LAYER V4  ;
    PORT
      LAYER M2 ;
        RECT 89.500000 219.400000 89.700000 220.000000 ;
    END
  END pe_in_pk_rdb_addr__3_
  PIN pe_in_pk_rdb_addr__2_
    DIRECTION INPUT ;
    USE SIGNAL ;
    ANTENNAPARTIALMETALAREA 2.22 LAYER M2  ;
    ANTENNAPARTIALMETALSIDEAREA 0.0222 LAYER M2  ;
    ANTENNAPARTIALCUTAREA 0.08 LAYER V2  ;
    ANTENNAPARTIALMETALAREA 0.76 LAYER M3  ;
    ANTENNAPARTIALMETALSIDEAREA 0.008 LAYER M3  ;
    ANTENNAMODEL OXIDE1 ;
    ANTENNAGATEAREA 0.8352 LAYER M3  ;
    ANTENNAMAXAREACAR 2.57471 LAYER M3  ;
    ANTENNAMAXSIDEAREACAR 0.0265565 LAYER M3  ;
    ANTENNAMAXCUTCAR 0.191571 LAYER V3  ;
    PORT
      LAYER M2 ;
        RECT 81.500000 219.400000 81.700000 220.000000 ;
    END
  END pe_in_pk_rdb_addr__2_
  PIN pe_in_pk_rdb_addr__1_
    DIRECTION INPUT ;
    USE SIGNAL ;
    ANTENNAPARTIALMETALAREA 2.62 LAYER M2  ;
    ANTENNAPARTIALMETALSIDEAREA 0.0262 LAYER M2  ;
    ANTENNAPARTIALCUTAREA 0.08 LAYER V2  ;
    ANTENNAPARTIALMETALAREA 0.36 LAYER M3  ;
    ANTENNAPARTIALMETALSIDEAREA 0.004 LAYER M3  ;
    ANTENNAMODEL OXIDE1 ;
    ANTENNAGATEAREA 0.4176 LAYER M3  ;
    ANTENNAMAXAREACAR 1.60249 LAYER M3  ;
    ANTENNAMAXSIDEAREACAR 0.0185345 LAYER M3  ;
    ANTENNAMAXCUTCAR 0.287356 LAYER V3  ;
    PORT
      LAYER M2 ;
        RECT 73.500000 219.400000 73.700000 220.000000 ;
    END
  END pe_in_pk_rdb_addr__1_
  PIN pe_in_pk_rdb_addr__0_
    DIRECTION INPUT ;
    USE SIGNAL ;
    ANTENNAPARTIALMETALAREA 1.86 LAYER M2  ;
    ANTENNAPARTIALMETALSIDEAREA 0.019 LAYER M2  ;
    ANTENNAMODEL OXIDE1 ;
    ANTENNAGATEAREA 0.6312 LAYER M2  ;
    ANTENNAMAXAREACAR 3.18124 LAYER M2  ;
    ANTENNAMAXSIDEAREACAR 0.0325412 LAYER M2  ;
    ANTENNAMAXCUTCAR 0.0633714 LAYER V2  ;
    PORT
      LAYER M2 ;
        RECT 65.500000 219.400000 65.700000 220.000000 ;
    END
  END pe_in_pk_rdb_addr__0_
  PIN pk_out_PE_state__2_
    DIRECTION OUTPUT ;
    USE SIGNAL ;
    ANTENNADIFFAREA 2.014 LAYER M3  ;
    ANTENNAPARTIALMETALAREA 9.9 LAYER M3  ;
    ANTENNAPARTIALMETALSIDEAREA 0.099 LAYER M3  ;
    PORT
      LAYER M3 ;
        RECT 279.400000 189.500000 280.000000 189.700000 ;
    END
  END pk_out_PE_state__2_
  PIN pk_out_PE_state__1_
    DIRECTION OUTPUT ;
    USE SIGNAL ;
    ANTENNADIFFAREA 2.014 LAYER M3  ;
    ANTENNAPARTIALMETALAREA 9.74 LAYER M3  ;
    ANTENNAPARTIALMETALSIDEAREA 0.0974 LAYER M3  ;
    PORT
      LAYER M3 ;
        RECT 279.400000 173.500000 280.000000 173.700000 ;
    END
  END pk_out_PE_state__1_
  PIN pk_out_PE_state__0_
    DIRECTION OUTPUT ;
    USE SIGNAL ;
    ANTENNADIFFAREA 2.014 LAYER M3  ;
    ANTENNAPARTIALMETALAREA 9.82 LAYER M3  ;
    ANTENNAPARTIALMETALSIDEAREA 0.0982 LAYER M3  ;
    PORT
      LAYER M3 ;
        RECT 279.400000 157.500000 280.000000 157.700000 ;
    END
  END pk_out_PE_state__0_
  PIN pk_out_data__7_
    DIRECTION OUTPUT ;
    USE SIGNAL ;
    PORT
      LAYER M3 ;
        RECT 279.400000 141.500000 280.000000 141.700000 ;
    END
  END pk_out_data__7_
  PIN pk_out_data__6_
    DIRECTION OUTPUT ;
    USE SIGNAL ;
    ANTENNADIFFAREA 1.76 LAYER M3  ;
    ANTENNAPARTIALMETALAREA 8.06 LAYER M3  ;
    ANTENNAPARTIALMETALSIDEAREA 0.0806 LAYER M3  ;
    PORT
      LAYER M3 ;
        RECT 279.400000 125.500000 280.000000 125.700000 ;
    END
  END pk_out_data__6_
  PIN pk_out_data__5_
    DIRECTION OUTPUT ;
    USE SIGNAL ;
    ANTENNADIFFAREA 1.76 LAYER M3  ;
    ANTENNAPARTIALMETALAREA 7.98 LAYER M3  ;
    ANTENNAPARTIALMETALSIDEAREA 0.0798 LAYER M3  ;
    PORT
      LAYER M3 ;
        RECT 279.400000 109.500000 280.000000 109.700000 ;
    END
  END pk_out_data__5_
  PIN pk_out_data__4_
    DIRECTION OUTPUT ;
    USE SIGNAL ;
    ANTENNADIFFAREA 1.76 LAYER M3  ;
    ANTENNAPARTIALMETALAREA 7.98 LAYER M3  ;
    ANTENNAPARTIALMETALSIDEAREA 0.0798 LAYER M3  ;
    PORT
      LAYER M3 ;
        RECT 279.400000 93.500000 280.000000 93.700000 ;
    END
  END pk_out_data__4_
  PIN pk_out_data__3_
    DIRECTION OUTPUT ;
    USE SIGNAL ;
    ANTENNADIFFAREA 1.76 LAYER M3  ;
    ANTENNAPARTIALMETALAREA 8.3 LAYER M3  ;
    ANTENNAPARTIALMETALSIDEAREA 0.083 LAYER M3  ;
    PORT
      LAYER M3 ;
        RECT 279.400000 77.500000 280.000000 77.700000 ;
    END
  END pk_out_data__3_
  PIN pk_out_data__2_
    DIRECTION OUTPUT ;
    USE SIGNAL ;
    ANTENNAPARTIALMETALAREA 8.3 LAYER M3  ;
    ANTENNAPARTIALMETALSIDEAREA 0.083 LAYER M3  ;
    ANTENNAPARTIALCUTAREA 0.08 LAYER V3  ;
    ANTENNADIFFAREA 1.76 LAYER M4  ;
    ANTENNAPARTIALMETALAREA 4.36 LAYER M4  ;
    ANTENNAPARTIALMETALSIDEAREA 0.044 LAYER M4  ;
    PORT
      LAYER M3 ;
        RECT 279.400000 61.500000 280.000000 61.700000 ;
    END
  END pk_out_data__2_
  PIN pk_out_data__1_
    DIRECTION OUTPUT ;
    USE SIGNAL ;
    ANTENNADIFFAREA 1.76 LAYER M3  ;
    ANTENNAPARTIALMETALAREA 8.66 LAYER M3  ;
    ANTENNAPARTIALMETALSIDEAREA 0.087 LAYER M3  ;
    PORT
      LAYER M3 ;
        RECT 279.400000 45.500000 280.000000 45.700000 ;
    END
  END pk_out_data__1_
  PIN pk_out_data__0_
    DIRECTION OUTPUT ;
    USE SIGNAL ;
    ANTENNADIFFAREA 1.76 LAYER M3  ;
    ANTENNAPARTIALMETALAREA 9.16 LAYER M3  ;
    ANTENNAPARTIALMETALSIDEAREA 0.092 LAYER M3  ;
    PORT
      LAYER M3 ;
        RECT 279.400000 29.500000 280.000000 29.700000 ;
    END
  END pk_out_data__0_
  PIN VSS
    DIRECTION INOUT ;
    USE GROUND ;

# P/G power stripe data as pin
    PORT
      LAYER M4 ;
        RECT 56.000000 1.000000 58.000000 218.600000 ;
        RECT 26.000000 1.000000 28.000000 218.600000 ;
        RECT 1.000000 1.000000 3.000000 218.600000 ;
        RECT 116.000000 1.000000 118.000000 218.600000 ;
        RECT 86.000000 1.000000 88.000000 218.600000 ;
        RECT 206.000000 1.000000 208.000000 218.600000 ;
        RECT 176.000000 1.000000 178.000000 218.600000 ;
        RECT 146.000000 1.000000 148.000000 218.600000 ;
        RECT 236.000000 1.000000 238.000000 218.600000 ;
        RECT 277.000000 1.000000 279.000000 218.600000 ;
    END
# end of P/G power stripe data as pin

  END VSS
  PIN VDD
    DIRECTION INOUT ;
    USE POWER ;

# P/G power stripe data as pin
    PORT
      LAYER M4 ;
        RECT 52.000000 4.000000 54.000000 215.600000 ;
        RECT 22.000000 4.000000 24.000000 215.600000 ;
        RECT 4.000000 4.000000 6.000000 215.600000 ;
        RECT 112.000000 4.000000 114.000000 215.600000 ;
        RECT 82.000000 4.000000 84.000000 215.600000 ;
        RECT 202.000000 4.000000 204.000000 215.600000 ;
        RECT 172.000000 4.000000 174.000000 215.600000 ;
        RECT 142.000000 4.000000 144.000000 215.600000 ;
        RECT 232.000000 4.000000 234.000000 215.600000 ;
        RECT 274.000000 4.000000 276.000000 215.600000 ;
    END
# end of P/G power stripe data as pin

  END VDD
  OBS
    LAYER M1 ;
      RECT 1 10.32 279 10.88 ;
      RECT 1 17.52 279 18.08 ;
      RECT 1 24.72 279 25.28 ;
      RECT 1 31.92 279 32.48 ;
      RECT 1 39.12 279 39.68 ;
      RECT 1 46.32 279 46.88 ;
      RECT 1 53.52 279 54.08 ;
      RECT 1 60.72 279 61.28 ;
      RECT 1 67.92 279 68.48 ;
      RECT 1 75.12 279 75.68 ;
      RECT 1 82.32 279 82.88 ;
      RECT 1 89.52 279 90.08 ;
      RECT 1 96.72 279 97.28 ;
      RECT 1 103.92 279 104.48 ;
      RECT 1 111.12 279 111.68 ;
      RECT 1 118.32 279 118.88 ;
      RECT 1 125.52 279 126.08 ;
      RECT 1 132.72 279 133.28 ;
      RECT 1 139.92 279 140.48 ;
      RECT 1 147.12 279 147.68 ;
      RECT 1 154.32 279 154.88 ;
      RECT 1 161.52 279 162.08 ;
      RECT 1 168.72 279 169.28 ;
      RECT 1 175.92 279 176.48 ;
      RECT 1 183.12 279 183.68 ;
      RECT 1 190.32 279 190.88 ;
      RECT 1 197.52 279 198.08 ;
      RECT 1 204.72 279 205.28 ;
      RECT 1 211.92 279 212.48 ;
    LAYER M1 SPACING 0.16 ;
      RECT 0 1 280 220 ;
    LAYER V1 SPACING 0.2 ;
      RECT 0 1 280 220 ;
    LAYER M2 ;
      RECT 153.5 219.4 153.7 220 ;
      RECT 152.7 219.5 153.7 219.7 ;
      RECT 70.3 219.5 70.9 219.7 ;
      RECT 70.3 206.3 70.5 219.7 ;
      RECT 41.5 219.4 41.7 220 ;
      RECT 41.5 219.5 42.5 219.7 ;
      RECT 279.5 29.9 279.7 64.9 ;
      RECT 277 1 279 218.6 ;
      RECT 275.2 1.92 276.2 3.4 ;
      RECT 273.8 1.92 274.8 3.4 ;
      RECT 272.4 1.92 273.4 3.4 ;
      RECT 271 1.92 272 3.4 ;
      RECT 269.6 1.92 270.6 3.4 ;
      RECT 268.2 1.92 269.2 3.4 ;
      RECT 266.8 1.92 267.8 3.4 ;
      RECT 265.4 1.92 266.4 3.4 ;
      RECT 264 1.92 265 3.4 ;
      RECT 262.6 1.92 263.6 3.4 ;
      RECT 261.2 1.92 262.2 3.4 ;
      RECT 259.8 1.92 260.8 3.4 ;
      RECT 258.4 1.92 259.4 3.4 ;
      RECT 257 1.92 258 3.4 ;
      RECT 255.6 1.92 256.6 3.4 ;
      RECT 254.2 1.92 255.2 3.4 ;
      RECT 252.8 1.92 253.8 3.4 ;
      RECT 251.4 1.92 252.4 3.4 ;
      RECT 248.6 1.92 249.6 3.4 ;
      RECT 247.2 1.92 248.2 3.4 ;
      RECT 245.8 1.92 246.8 3.4 ;
      RECT 244.4 1.92 245.4 3.4 ;
      RECT 243 1.92 244 3.4 ;
      RECT 241.6 1.92 242.6 3.4 ;
      RECT 240.2 1.92 241.2 3.4 ;
      RECT 238.8 1.92 239.8 3.4 ;
      RECT 237.4 1.92 238.4 3.4 ;
      RECT 234.6 1.92 235.6 3.4 ;
      RECT 233.2 1.92 234.2 3.4 ;
      RECT 231.8 1.92 232.8 3.4 ;
      RECT 230.4 1.92 231.4 3.4 ;
      RECT 229 1.92 230 3.4 ;
      RECT 227.6 1.92 228.6 3.4 ;
      RECT 226.2 1.92 227.2 3.4 ;
      RECT 224.8 1.92 225.8 3.4 ;
      RECT 223.4 1.92 224.4 3.4 ;
      RECT 222 1.92 223 3.4 ;
      RECT 220.6 1.92 221.6 3.4 ;
      RECT 219.2 1.92 220.2 3.4 ;
      RECT 217.8 1.92 218.8 3.4 ;
      RECT 217.5 212.7 217.7 220 ;
      RECT 216.4 1.92 217.4 3.4 ;
      RECT 215 1.92 216 3.4 ;
      RECT 213.6 1.92 214.6 3.4 ;
      RECT 212.2 1.92 213.2 3.4 ;
      RECT 210.8 1.92 211.8 3.4 ;
      RECT 209.4 1.92 210.4 3.4 ;
      RECT 209.5 210.7 209.7 220 ;
      RECT 206.6 1.92 207.6 3.4 ;
      RECT 205.2 1.92 206.2 3.4 ;
      RECT 203.8 1.92 204.8 3.4 ;
      RECT 202.4 1.92 203.4 3.4 ;
      RECT 201 1.92 202 3.4 ;
      RECT 201.5 211.9 201.7 220 ;
      RECT 199.6 1.92 200.6 3.4 ;
      RECT 198.2 1.92 199.2 3.4 ;
      RECT 196.8 1.92 197.8 3.4 ;
      RECT 195.4 1.92 196.4 3.4 ;
      RECT 194 1.92 195 3.4 ;
      RECT 193.5 212.3 193.7 220 ;
      RECT 192.6 1.92 193.6 3.4 ;
      RECT 191.2 1.92 192.2 3.4 ;
      RECT 189.8 1.92 190.8 3.4 ;
      RECT 188.4 1.92 189.4 3.4 ;
      RECT 187 1.92 188 3.4 ;
      RECT 185.6 1.92 186.6 3.4 ;
      RECT 185.5 212.3 185.7 220 ;
      RECT 184.2 1.92 185.2 3.4 ;
      RECT 182.8 1.92 183.8 3.4 ;
      RECT 181.4 1.92 182.4 3.4 ;
      RECT 180 1.92 181 3.4 ;
      RECT 178.6 1.92 179.6 3.4 ;
      RECT 177.2 1.92 178.2 3.4 ;
      RECT 177.5 219.1 177.7 220 ;
      RECT 175.8 1.92 176.8 3.4 ;
      RECT 174.4 1.92 175.4 3.4 ;
      RECT 173 1.92 174 3.4 ;
      RECT 171.6 1.92 172.6 3.4 ;
      RECT 170.2 1.92 171.2 3.4 ;
      RECT 168.8 1.92 169.8 3.4 ;
      RECT 169.5 211.9 169.7 220 ;
      RECT 167.4 1.92 168.4 3.4 ;
      RECT 167.1 211.5 167.3 219.7 ;
      RECT 166 1.92 167 3.4 ;
      RECT 164.6 1.92 165.6 3.4 ;
      RECT 163.2 1.92 164.2 3.4 ;
      RECT 161.8 1.92 162.8 3.4 ;
      RECT 161.5 211.9 161.7 220 ;
      RECT 160.4 1.92 161.4 3.4 ;
      RECT 159 1.92 160 3.4 ;
      RECT 157.6 1.92 158.6 3.4 ;
      RECT 156.2 1.92 157.2 3.4 ;
      RECT 154.8 1.92 155.8 3.4 ;
      RECT 153.4 1.92 154.4 3.4 ;
      RECT 152 1.92 153 3.4 ;
      RECT 150.6 1.92 151.6 3.4 ;
      RECT 149.2 1.92 150.2 3.4 ;
      RECT 146.4 1.92 147.4 3.4 ;
      RECT 145 1.92 146 3.4 ;
      RECT 145.5 219.1 145.7 220 ;
      RECT 143.6 1.92 144.6 3.4 ;
      RECT 142.2 1.92 143.2 3.4 ;
      RECT 140.8 1.92 141.8 3.4 ;
      RECT 139.4 1.92 140.4 3.4 ;
      RECT 139.1 210.7 139.3 219.7 ;
      RECT 138 1.92 139 3.4 ;
      RECT 137.5 219.1 137.7 220 ;
      RECT 136.6 1.92 137.6 3.4 ;
      RECT 135.2 1.92 136.2 3.4 ;
      RECT 133.8 1.92 134.8 3.4 ;
      RECT 132.4 1.92 133.4 3.4 ;
      RECT 132.7 210.3 132.9 219.3 ;
      RECT 131 1.92 132 3.4 ;
      RECT 131.5 210.3 131.7 219.7 ;
      RECT 130.7 210.7 130.9 219.7 ;
      RECT 129.6 1.92 130.6 3.4 ;
      RECT 129.5 219.4 129.7 220 ;
      RECT 128.2 1.92 129.2 3.4 ;
      RECT 126.8 1.92 127.8 3.4 ;
      RECT 125.4 1.92 126.4 3.4 ;
      RECT 124 1.92 125 3.4 ;
      RECT 122.6 1.92 123.6 3.4 ;
      RECT 121.2 1.92 122.2 3.4 ;
      RECT 121.5 210.7 121.7 220 ;
      RECT 119.8 1.92 120.8 3.4 ;
      RECT 118.4 1.92 119.4 3.4 ;
      RECT 117 1.92 118 3.4 ;
      RECT 115.6 1.92 116.6 3.4 ;
      RECT 114.2 1.92 115.2 3.4 ;
      RECT 112.8 1.92 113.8 3.4 ;
      RECT 113.5 211.5 113.7 220 ;
      RECT 111.4 1.92 112.4 3.4 ;
      RECT 110 1.92 111 3.4 ;
      RECT 108.6 1.92 109.6 3.4 ;
      RECT 107.2 1.92 108.2 3.4 ;
      RECT 105.8 1.92 106.8 3.4 ;
      RECT 105.5 213.1 105.7 220 ;
      RECT 104.4 1.92 105.4 3.4 ;
      RECT 103 1.92 104 3.4 ;
      RECT 101.6 1.92 102.6 3.4 ;
      RECT 100.2 1.92 101.2 3.4 ;
      RECT 98.8 1.92 99.8 3.4 ;
      RECT 97.5 212.7 97.7 220 ;
      RECT 96 1.92 97 3.4 ;
      RECT 94.6 1.92 95.6 3.4 ;
      RECT 93.2 1.92 94.2 3.4 ;
      RECT 91.8 1.92 92.8 3.4 ;
      RECT 90.4 1.92 91.4 3.4 ;
      RECT 89 1.92 90 3.4 ;
      RECT 89.5 210.3 89.7 220 ;
      RECT 87.6 1.92 88.6 3.4 ;
      RECT 86.2 1.92 87.2 3.4 ;
      RECT 84.8 1.92 85.8 3.4 ;
      RECT 83.4 1.92 84.4 3.4 ;
      RECT 82 1.92 83 3.4 ;
      RECT 81.5 208.3 81.7 220 ;
      RECT 80.6 1.92 81.6 3.4 ;
      RECT 79.2 1.92 80.2 3.4 ;
      RECT 77.8 1.92 78.8 3.4 ;
      RECT 75 1.92 76 3.4 ;
      RECT 75.1 210.7 75.3 219.7 ;
      RECT 73.6 1.92 74.6 3.4 ;
      RECT 73.5 206.7 73.7 220 ;
      RECT 72.2 1.92 73.2 3.4 ;
      RECT 70.8 1.92 71.8 3.4 ;
      RECT 69.4 1.92 70.4 3.4 ;
      RECT 68 1.92 69 3.4 ;
      RECT 66.6 1.92 67.6 3.4 ;
      RECT 65.2 1.92 66.2 3.4 ;
      RECT 65.5 214.7 65.7 220 ;
      RECT 63.8 1.92 64.8 3.4 ;
      RECT 62.4 1.92 63.4 3.4 ;
      RECT 61 1.92 62 3.4 ;
      RECT 59.6 1.92 60.6 3.4 ;
      RECT 58.2 1.92 59.2 3.4 ;
      RECT 56.8 1.92 57.8 3.4 ;
      RECT 57.5 219.1 57.7 220 ;
      RECT 55.4 1.92 56.4 3.4 ;
      RECT 54 1.92 55 3.4 ;
      RECT 52.6 1.92 53.6 3.4 ;
      RECT 51.2 1.92 52.2 3.4 ;
      RECT 49.8 1.92 50.8 3.4 ;
      RECT 49.5 213.1 49.7 220 ;
      RECT 48.4 1.92 49.4 3.4 ;
      RECT 47 1.92 48 3.4 ;
      RECT 45.6 1.92 46.6 3.4 ;
      RECT 44.2 1.92 45.2 3.4 ;
      RECT 42.8 1.92 43.8 3.4 ;
      RECT 41.4 1.92 42.4 3.4 ;
      RECT 40 1.92 41 3.4 ;
      RECT 38.6 1.92 39.6 3.4 ;
      RECT 37.2 1.92 38.2 3.4 ;
      RECT 35.8 1.92 36.8 3.4 ;
      RECT 34.4 1.92 35.4 3.4 ;
      RECT 33 1.92 34 3.4 ;
      RECT 31.6 1.92 32.6 3.4 ;
      RECT 30.2 1.92 31.2 3.4 ;
      RECT 28.8 1.92 29.8 3.4 ;
      RECT 27.4 1.92 28.4 3.4 ;
      RECT 26 1.92 27 3.4 ;
      RECT 24.6 1.92 25.6 3.4 ;
      RECT 23.2 1.92 24.2 3.4 ;
      RECT 21.8 1.92 22.8 3.4 ;
      RECT 20.4 1.92 21.4 3.4 ;
      RECT 19 1.92 20 3.4 ;
      RECT 17.6 1.92 18.6 3.4 ;
      RECT 16.2 1.92 17.2 3.4 ;
      RECT 14.8 1.92 15.8 3.4 ;
      RECT 13.4 1.92 14.4 3.4 ;
      RECT 12 1.92 13 3.4 ;
      RECT 10.6 1.92 11.6 3.4 ;
      RECT 9.2 1.92 10.2 3.4 ;
      RECT 7.8 1.92 8.8 3.4 ;
      RECT 6.4 1.92 7.4 3.4 ;
      RECT 5 1.92 6 3.4 ;
      RECT 3.6 1.92 4.6 3.4 ;
      RECT 1 1 3 218.6 ;
    LAYER M2 SPACING 0.2 ;
      RECT 0 1 280 220 ;
    LAYER V2 SPACING 0.2 ;
      RECT 0 1 280 220 ;
    LAYER M3 ;
      RECT 279.5 29.5 279.7 30.5 ;
      RECT 279.4 29.5 280 29.7 ;
      RECT 279.5 64.3 279.7 64.9 ;
      RECT 235.5 64.3 279.7 64.5 ;
      RECT 167.1 219.1 167.3 219.7 ;
      RECT 167.1 219.1 177.7 219.3 ;
      RECT 131.5 219.5 138.1 219.7 ;
      RECT 137.9 219.1 138.1 219.7 ;
      RECT 137.9 219.1 145.7 219.3 ;
      RECT 75.1 219.1 75.3 219.7 ;
      RECT 57.5 219.1 75.3 219.3 ;
      RECT 273.1 45.5 280 45.7 ;
      RECT 238.3 61.5 280 61.7 ;
      RECT 238.3 77.5 280 77.7 ;
      RECT 239.9 93.5 280 93.7 ;
      RECT 239.5 109.5 280 109.7 ;
      RECT 239.5 125.5 280 125.7 ;
      RECT 278.4 141.5 280 141.7 ;
      RECT 230.7 157.5 280 157.7 ;
      RECT 231.1 173.5 280 173.7 ;
      RECT 230.3 189.5 280 189.7 ;
      RECT 1 1 279 3 ;
      RECT 1 216.6 279 218.6 ;
      RECT 139.1 219.5 153.3 219.7 ;
      RECT 132.7 219.1 137.7 219.3 ;
      RECT 129.5 219.5 130.9 219.7 ;
      RECT 41.9 219.5 70.9 219.7 ;
      RECT 0 166.3 12.1 166.5 ;
      RECT 0 88.3 10.5 88.5 ;
      RECT 0 130.3 10.5 130.5 ;
      RECT 0 136.3 10.5 136.5 ;
      RECT 0 52.3 10.1 52.5 ;
      RECT 0 112.3 10.1 112.5 ;
      RECT 0 100.3 9.7 100.5 ;
      RECT 0 124.3 9.7 124.5 ;
      RECT 0 160.3 9.7 160.5 ;
      RECT 0 190.3 9.7 190.5 ;
      RECT 0 106.3 9.3 106.5 ;
      RECT 0 118.3 9.3 118.5 ;
      RECT 0 172.3 9.3 172.5 ;
      RECT 0 16.3 8.9 16.5 ;
      RECT 0 22.3 8.9 22.5 ;
      RECT 0 28.3 8.9 28.5 ;
      RECT 0 34.3 8.9 34.5 ;
      RECT 0 40.3 8.9 40.5 ;
      RECT 0 46.3 8.9 46.5 ;
      RECT 0 202.3 8.9 202.5 ;
      RECT 0 142.3 8.5 142.5 ;
      RECT 0 178.3 8.5 178.5 ;
      RECT 0 196.3 8.5 196.5 ;
      RECT 0 94.3 8.1 94.5 ;
      RECT 0 148.3 8.1 148.5 ;
      RECT 0 82.3 7.7 82.5 ;
      RECT 0 154.3 7.7 154.5 ;
      RECT 0 7.9 7.3 8.1 ;
      RECT 0 70.3 7.3 70.5 ;
      RECT 0 76.3 7.3 76.5 ;
      RECT 0 58.3 6.5 58.5 ;
      RECT 0 64.3 3.7 64.5 ;
      RECT 0 184.3 3.7 184.5 ;
      RECT 0 3.9 2.1 4.1 ;
    LAYER M3 SPACING 0.2 ;
      RECT 0 1 280 220 ;
    LAYER V3 ;
      RECT 279.2 141.5 279.4 141.7 ;
      RECT 278.8 1 279 1.2 ;
      RECT 278.8 1.6 279 1.8 ;
      RECT 278.8 2.2 279 2.4 ;
      RECT 278.8 2.8 279 3 ;
      RECT 278.8 141.5 279 141.7 ;
      RECT 278.8 216.6 279 216.8 ;
      RECT 278.8 217.2 279 217.4 ;
      RECT 278.8 217.8 279 218 ;
      RECT 278.8 218.4 279 218.6 ;
      RECT 278.4 141.5 278.6 141.7 ;
      RECT 278.2 1 278.4 1.2 ;
      RECT 278.2 1.6 278.4 1.8 ;
      RECT 278.2 2.2 278.4 2.4 ;
      RECT 278.2 2.8 278.4 3 ;
      RECT 278.2 216.6 278.4 216.8 ;
      RECT 278.2 217.2 278.4 217.4 ;
      RECT 278.2 217.8 278.4 218 ;
      RECT 278.2 218.4 278.4 218.6 ;
      RECT 277.6 1 277.8 1.2 ;
      RECT 277.6 1.6 277.8 1.8 ;
      RECT 277.6 2.2 277.8 2.4 ;
      RECT 277.6 2.8 277.8 3 ;
      RECT 277.6 216.6 277.8 216.8 ;
      RECT 277.6 217.2 277.8 217.4 ;
      RECT 277.6 217.8 277.8 218 ;
      RECT 277.6 218.4 277.8 218.6 ;
      RECT 277 1 277.2 1.2 ;
      RECT 277 1.6 277.2 1.8 ;
      RECT 277 2.2 277.2 2.4 ;
      RECT 277 2.8 277.2 3 ;
      RECT 277 216.6 277.2 216.8 ;
      RECT 277 217.2 277.2 217.4 ;
      RECT 277 217.8 277.2 218 ;
      RECT 277 218.4 277.2 218.6 ;
      RECT 275.8 4 276 4.2 ;
      RECT 275.8 4.6 276 4.8 ;
      RECT 275.8 5.2 276 5.4 ;
      RECT 275.8 5.8 276 6 ;
      RECT 275.8 213.6 276 213.8 ;
      RECT 275.8 214.2 276 214.4 ;
      RECT 275.8 214.8 276 215 ;
      RECT 275.8 215.4 276 215.6 ;
      RECT 275.2 4 275.4 4.2 ;
      RECT 275.2 4.6 275.4 4.8 ;
      RECT 275.2 5.2 275.4 5.4 ;
      RECT 275.2 5.8 275.4 6 ;
      RECT 275.2 213.6 275.4 213.8 ;
      RECT 275.2 214.2 275.4 214.4 ;
      RECT 275.2 214.8 275.4 215 ;
      RECT 275.2 215.4 275.4 215.6 ;
      RECT 274.6 4 274.8 4.2 ;
      RECT 274.6 4.6 274.8 4.8 ;
      RECT 274.6 5.2 274.8 5.4 ;
      RECT 274.6 5.8 274.8 6 ;
      RECT 274.6 213.6 274.8 213.8 ;
      RECT 274.6 214.2 274.8 214.4 ;
      RECT 274.6 214.8 274.8 215 ;
      RECT 274.6 215.4 274.8 215.6 ;
      RECT 274 4 274.2 4.2 ;
      RECT 274 4.6 274.2 4.8 ;
      RECT 274 5.2 274.2 5.4 ;
      RECT 274 5.8 274.2 6 ;
      RECT 274 213.6 274.2 213.8 ;
      RECT 274 214.2 274.2 214.4 ;
      RECT 274 214.8 274.2 215 ;
      RECT 274 215.4 274.2 215.6 ;
      RECT 238.3 61.5 238.5 61.7 ;
      RECT 238.3 61.9 238.5 62.1 ;
      RECT 238.3 82.7 238.5 82.9 ;
      RECT 238.3 83.1 238.5 83.3 ;
      RECT 237.8 1 238 1.2 ;
      RECT 237.8 1.6 238 1.8 ;
      RECT 237.8 2.2 238 2.4 ;
      RECT 237.8 2.8 238 3 ;
      RECT 237.8 10.5 238 10.7 ;
      RECT 237.8 17.7 238 17.9 ;
      RECT 237.8 24.9 238 25.1 ;
      RECT 237.8 32.1 238 32.3 ;
      RECT 237.8 39.3 238 39.5 ;
      RECT 237.8 46.5 238 46.7 ;
      RECT 237.8 53.7 238 53.9 ;
      RECT 237.8 60.9 238 61.1 ;
      RECT 237.8 68.1 238 68.3 ;
      RECT 237.8 75.3 238 75.5 ;
      RECT 237.8 82.5 238 82.7 ;
      RECT 237.8 89.7 238 89.9 ;
      RECT 237.8 96.9 238 97.1 ;
      RECT 237.8 104.1 238 104.3 ;
      RECT 237.8 111.3 238 111.5 ;
      RECT 237.8 118.5 238 118.7 ;
      RECT 237.8 125.7 238 125.9 ;
      RECT 237.8 132.9 238 133.1 ;
      RECT 237.8 140.1 238 140.3 ;
      RECT 237.8 147.3 238 147.5 ;
      RECT 237.8 154.5 238 154.7 ;
      RECT 237.8 161.7 238 161.9 ;
      RECT 237.8 168.9 238 169.1 ;
      RECT 237.8 176.1 238 176.3 ;
      RECT 237.8 183.3 238 183.5 ;
      RECT 237.8 190.5 238 190.7 ;
      RECT 237.8 197.7 238 197.9 ;
      RECT 237.8 204.9 238 205.1 ;
      RECT 237.8 212.1 238 212.3 ;
      RECT 237.8 216.6 238 216.8 ;
      RECT 237.8 217.2 238 217.4 ;
      RECT 237.8 217.8 238 218 ;
      RECT 237.8 218.4 238 218.6 ;
      RECT 237.2 1 237.4 1.2 ;
      RECT 237.2 1.6 237.4 1.8 ;
      RECT 237.2 2.2 237.4 2.4 ;
      RECT 237.2 2.8 237.4 3 ;
      RECT 237.2 10.5 237.4 10.7 ;
      RECT 237.2 17.7 237.4 17.9 ;
      RECT 237.2 24.9 237.4 25.1 ;
      RECT 237.2 32.1 237.4 32.3 ;
      RECT 237.2 39.3 237.4 39.5 ;
      RECT 237.2 46.5 237.4 46.7 ;
      RECT 237.2 53.7 237.4 53.9 ;
      RECT 237.2 60.9 237.4 61.1 ;
      RECT 237.2 68.1 237.4 68.3 ;
      RECT 237.2 75.3 237.4 75.5 ;
      RECT 237.2 82.5 237.4 82.7 ;
      RECT 237.2 89.7 237.4 89.9 ;
      RECT 237.2 96.9 237.4 97.1 ;
      RECT 237.2 104.1 237.4 104.3 ;
      RECT 237.2 111.3 237.4 111.5 ;
      RECT 237.2 118.5 237.4 118.7 ;
      RECT 237.2 125.7 237.4 125.9 ;
      RECT 237.2 132.9 237.4 133.1 ;
      RECT 237.2 140.1 237.4 140.3 ;
      RECT 237.2 147.3 237.4 147.5 ;
      RECT 237.2 154.5 237.4 154.7 ;
      RECT 237.2 161.7 237.4 161.9 ;
      RECT 237.2 168.9 237.4 169.1 ;
      RECT 237.2 176.1 237.4 176.3 ;
      RECT 237.2 183.3 237.4 183.5 ;
      RECT 237.2 190.5 237.4 190.7 ;
      RECT 237.2 197.7 237.4 197.9 ;
      RECT 237.2 204.9 237.4 205.1 ;
      RECT 237.2 212.1 237.4 212.3 ;
      RECT 237.2 216.6 237.4 216.8 ;
      RECT 237.2 217.2 237.4 217.4 ;
      RECT 237.2 217.8 237.4 218 ;
      RECT 237.2 218.4 237.4 218.6 ;
      RECT 236.6 1 236.8 1.2 ;
      RECT 236.6 1.6 236.8 1.8 ;
      RECT 236.6 2.2 236.8 2.4 ;
      RECT 236.6 2.8 236.8 3 ;
      RECT 236.6 10.5 236.8 10.7 ;
      RECT 236.6 17.7 236.8 17.9 ;
      RECT 236.6 24.9 236.8 25.1 ;
      RECT 236.6 32.1 236.8 32.3 ;
      RECT 236.6 39.3 236.8 39.5 ;
      RECT 236.6 46.5 236.8 46.7 ;
      RECT 236.6 53.7 236.8 53.9 ;
      RECT 236.6 60.9 236.8 61.1 ;
      RECT 236.6 68.1 236.8 68.3 ;
      RECT 236.6 75.3 236.8 75.5 ;
      RECT 236.6 82.5 236.8 82.7 ;
      RECT 236.6 89.7 236.8 89.9 ;
      RECT 236.6 96.9 236.8 97.1 ;
      RECT 236.6 104.1 236.8 104.3 ;
      RECT 236.6 111.3 236.8 111.5 ;
      RECT 236.6 118.5 236.8 118.7 ;
      RECT 236.6 125.7 236.8 125.9 ;
      RECT 236.6 132.9 236.8 133.1 ;
      RECT 236.6 140.1 236.8 140.3 ;
      RECT 236.6 147.3 236.8 147.5 ;
      RECT 236.6 154.5 236.8 154.7 ;
      RECT 236.6 161.7 236.8 161.9 ;
      RECT 236.6 168.9 236.8 169.1 ;
      RECT 236.6 176.1 236.8 176.3 ;
      RECT 236.6 183.3 236.8 183.5 ;
      RECT 236.6 190.5 236.8 190.7 ;
      RECT 236.6 197.7 236.8 197.9 ;
      RECT 236.6 204.9 236.8 205.1 ;
      RECT 236.6 212.1 236.8 212.3 ;
      RECT 236.6 216.6 236.8 216.8 ;
      RECT 236.6 217.2 236.8 217.4 ;
      RECT 236.6 217.8 236.8 218 ;
      RECT 236.6 218.4 236.8 218.6 ;
      RECT 236 1 236.2 1.2 ;
      RECT 236 1.6 236.2 1.8 ;
      RECT 236 2.2 236.2 2.4 ;
      RECT 236 2.8 236.2 3 ;
      RECT 236 10.5 236.2 10.7 ;
      RECT 236 17.7 236.2 17.9 ;
      RECT 236 24.9 236.2 25.1 ;
      RECT 236 32.1 236.2 32.3 ;
      RECT 236 39.3 236.2 39.5 ;
      RECT 236 46.5 236.2 46.7 ;
      RECT 236 53.7 236.2 53.9 ;
      RECT 236 60.9 236.2 61.1 ;
      RECT 236 68.1 236.2 68.3 ;
      RECT 236 75.3 236.2 75.5 ;
      RECT 236 82.5 236.2 82.7 ;
      RECT 236 89.7 236.2 89.9 ;
      RECT 236 96.9 236.2 97.1 ;
      RECT 236 104.1 236.2 104.3 ;
      RECT 236 111.3 236.2 111.5 ;
      RECT 236 118.5 236.2 118.7 ;
      RECT 236 125.7 236.2 125.9 ;
      RECT 236 132.9 236.2 133.1 ;
      RECT 236 140.1 236.2 140.3 ;
      RECT 236 147.3 236.2 147.5 ;
      RECT 236 154.5 236.2 154.7 ;
      RECT 236 161.7 236.2 161.9 ;
      RECT 236 168.9 236.2 169.1 ;
      RECT 236 176.1 236.2 176.3 ;
      RECT 236 183.3 236.2 183.5 ;
      RECT 236 190.5 236.2 190.7 ;
      RECT 236 197.7 236.2 197.9 ;
      RECT 236 204.9 236.2 205.1 ;
      RECT 236 212.1 236.2 212.3 ;
      RECT 236 216.6 236.2 216.8 ;
      RECT 236 217.2 236.2 217.4 ;
      RECT 236 217.8 236.2 218 ;
      RECT 236 218.4 236.2 218.6 ;
      RECT 235.5 80.7 235.7 80.9 ;
      RECT 235.5 81.1 235.7 81.3 ;
      RECT 235.5 82.7 235.7 82.9 ;
      RECT 235.5 83.1 235.7 83.3 ;
      RECT 233.8 4 234 4.2 ;
      RECT 233.8 4.6 234 4.8 ;
      RECT 233.8 5.2 234 5.4 ;
      RECT 233.8 5.8 234 6 ;
      RECT 233.8 6.9 234 7.1 ;
      RECT 233.8 14.1 234 14.3 ;
      RECT 233.8 21.3 234 21.5 ;
      RECT 233.8 28.5 234 28.7 ;
      RECT 233.8 35.7 234 35.9 ;
      RECT 233.8 42.9 234 43.1 ;
      RECT 233.8 50.1 234 50.3 ;
      RECT 233.8 57.3 234 57.5 ;
      RECT 233.8 64.5 234 64.7 ;
      RECT 233.8 71.7 234 71.9 ;
      RECT 233.8 78.9 234 79.1 ;
      RECT 233.8 86.1 234 86.3 ;
      RECT 233.8 93.3 234 93.5 ;
      RECT 233.8 100.5 234 100.7 ;
      RECT 233.8 107.7 234 107.9 ;
      RECT 233.8 114.9 234 115.1 ;
      RECT 233.8 122.1 234 122.3 ;
      RECT 233.8 129.3 234 129.5 ;
      RECT 233.8 136.5 234 136.7 ;
      RECT 233.8 143.7 234 143.9 ;
      RECT 233.8 150.9 234 151.1 ;
      RECT 233.8 158.1 234 158.3 ;
      RECT 233.8 165.3 234 165.5 ;
      RECT 233.8 172.5 234 172.7 ;
      RECT 233.8 179.7 234 179.9 ;
      RECT 233.8 186.9 234 187.1 ;
      RECT 233.8 194.1 234 194.3 ;
      RECT 233.8 201.3 234 201.5 ;
      RECT 233.8 208.5 234 208.7 ;
      RECT 233.8 213.6 234 213.8 ;
      RECT 233.8 214.2 234 214.4 ;
      RECT 233.8 214.8 234 215 ;
      RECT 233.8 215.4 234 215.6 ;
      RECT 233.2 4 233.4 4.2 ;
      RECT 233.2 4.6 233.4 4.8 ;
      RECT 233.2 5.2 233.4 5.4 ;
      RECT 233.2 5.8 233.4 6 ;
      RECT 233.2 6.9 233.4 7.1 ;
      RECT 233.2 14.1 233.4 14.3 ;
      RECT 233.2 21.3 233.4 21.5 ;
      RECT 233.2 28.5 233.4 28.7 ;
      RECT 233.2 35.7 233.4 35.9 ;
      RECT 233.2 42.9 233.4 43.1 ;
      RECT 233.2 50.1 233.4 50.3 ;
      RECT 233.2 57.3 233.4 57.5 ;
      RECT 233.2 64.5 233.4 64.7 ;
      RECT 233.2 71.7 233.4 71.9 ;
      RECT 233.2 78.9 233.4 79.1 ;
      RECT 233.2 86.1 233.4 86.3 ;
      RECT 233.2 93.3 233.4 93.5 ;
      RECT 233.2 100.5 233.4 100.7 ;
      RECT 233.2 107.7 233.4 107.9 ;
      RECT 233.2 114.9 233.4 115.1 ;
      RECT 233.2 122.1 233.4 122.3 ;
      RECT 233.2 129.3 233.4 129.5 ;
      RECT 233.2 136.5 233.4 136.7 ;
      RECT 233.2 143.7 233.4 143.9 ;
      RECT 233.2 150.9 233.4 151.1 ;
      RECT 233.2 158.1 233.4 158.3 ;
      RECT 233.2 165.3 233.4 165.5 ;
      RECT 233.2 172.5 233.4 172.7 ;
      RECT 233.2 179.7 233.4 179.9 ;
      RECT 233.2 186.9 233.4 187.1 ;
      RECT 233.2 194.1 233.4 194.3 ;
      RECT 233.2 201.3 233.4 201.5 ;
      RECT 233.2 208.5 233.4 208.7 ;
      RECT 233.2 213.6 233.4 213.8 ;
      RECT 233.2 214.2 233.4 214.4 ;
      RECT 233.2 214.8 233.4 215 ;
      RECT 233.2 215.4 233.4 215.6 ;
      RECT 232.6 4 232.8 4.2 ;
      RECT 232.6 4.6 232.8 4.8 ;
      RECT 232.6 5.2 232.8 5.4 ;
      RECT 232.6 5.8 232.8 6 ;
      RECT 232.6 6.9 232.8 7.1 ;
      RECT 232.6 14.1 232.8 14.3 ;
      RECT 232.6 21.3 232.8 21.5 ;
      RECT 232.6 28.5 232.8 28.7 ;
      RECT 232.6 35.7 232.8 35.9 ;
      RECT 232.6 42.9 232.8 43.1 ;
      RECT 232.6 50.1 232.8 50.3 ;
      RECT 232.6 57.3 232.8 57.5 ;
      RECT 232.6 64.5 232.8 64.7 ;
      RECT 232.6 71.7 232.8 71.9 ;
      RECT 232.6 78.9 232.8 79.1 ;
      RECT 232.6 86.1 232.8 86.3 ;
      RECT 232.6 93.3 232.8 93.5 ;
      RECT 232.6 100.5 232.8 100.7 ;
      RECT 232.6 107.7 232.8 107.9 ;
      RECT 232.6 114.9 232.8 115.1 ;
      RECT 232.6 122.1 232.8 122.3 ;
      RECT 232.6 129.3 232.8 129.5 ;
      RECT 232.6 136.5 232.8 136.7 ;
      RECT 232.6 143.7 232.8 143.9 ;
      RECT 232.6 150.9 232.8 151.1 ;
      RECT 232.6 158.1 232.8 158.3 ;
      RECT 232.6 165.3 232.8 165.5 ;
      RECT 232.6 172.5 232.8 172.7 ;
      RECT 232.6 179.7 232.8 179.9 ;
      RECT 232.6 186.9 232.8 187.1 ;
      RECT 232.6 194.1 232.8 194.3 ;
      RECT 232.6 201.3 232.8 201.5 ;
      RECT 232.6 208.5 232.8 208.7 ;
      RECT 232.6 213.6 232.8 213.8 ;
      RECT 232.6 214.2 232.8 214.4 ;
      RECT 232.6 214.8 232.8 215 ;
      RECT 232.6 215.4 232.8 215.6 ;
      RECT 232 4 232.2 4.2 ;
      RECT 232 4.6 232.2 4.8 ;
      RECT 232 5.2 232.2 5.4 ;
      RECT 232 5.8 232.2 6 ;
      RECT 232 6.9 232.2 7.1 ;
      RECT 232 14.1 232.2 14.3 ;
      RECT 232 21.3 232.2 21.5 ;
      RECT 232 28.5 232.2 28.7 ;
      RECT 232 35.7 232.2 35.9 ;
      RECT 232 42.9 232.2 43.1 ;
      RECT 232 50.1 232.2 50.3 ;
      RECT 232 57.3 232.2 57.5 ;
      RECT 232 64.5 232.2 64.7 ;
      RECT 232 71.7 232.2 71.9 ;
      RECT 232 78.9 232.2 79.1 ;
      RECT 232 86.1 232.2 86.3 ;
      RECT 232 93.3 232.2 93.5 ;
      RECT 232 100.5 232.2 100.7 ;
      RECT 232 107.7 232.2 107.9 ;
      RECT 232 114.9 232.2 115.1 ;
      RECT 232 122.1 232.2 122.3 ;
      RECT 232 129.3 232.2 129.5 ;
      RECT 232 136.5 232.2 136.7 ;
      RECT 232 143.7 232.2 143.9 ;
      RECT 232 150.9 232.2 151.1 ;
      RECT 232 158.1 232.2 158.3 ;
      RECT 232 165.3 232.2 165.5 ;
      RECT 232 172.5 232.2 172.7 ;
      RECT 232 179.7 232.2 179.9 ;
      RECT 232 186.9 232.2 187.1 ;
      RECT 232 194.1 232.2 194.3 ;
      RECT 232 201.3 232.2 201.5 ;
      RECT 232 208.5 232.2 208.7 ;
      RECT 232 213.6 232.2 213.8 ;
      RECT 232 214.2 232.2 214.4 ;
      RECT 232 214.8 232.2 215 ;
      RECT 232 215.4 232.2 215.6 ;
      RECT 227.1 113.5 227.3 113.7 ;
      RECT 226.7 113.5 226.9 113.7 ;
      RECT 226.7 115.9 226.9 116.1 ;
      RECT 226.7 116.3 226.9 116.5 ;
      RECT 226.7 163.5 226.9 163.7 ;
      RECT 226.3 156.7 226.5 156.9 ;
      RECT 226.3 163.5 226.5 163.7 ;
      RECT 225.9 156.7 226.1 156.9 ;
      RECT 222.3 87.5 222.5 87.7 ;
      RECT 222.3 91.9 222.5 92.1 ;
      RECT 222.3 94.7 222.5 94.9 ;
      RECT 222.3 113.5 222.5 113.7 ;
      RECT 222.3 120.7 222.5 120.9 ;
      RECT 222.3 123.5 222.5 123.7 ;
      RECT 222.3 127.9 222.5 128.1 ;
      RECT 221.9 84.7 222.1 84.9 ;
      RECT 221.9 87.5 222.1 87.7 ;
      RECT 221.9 91.9 222.1 92.1 ;
      RECT 221.9 94.7 222.1 94.9 ;
      RECT 221.9 102.7 222.1 102.9 ;
      RECT 221.9 103.1 222.1 103.3 ;
      RECT 221.9 109.1 222.1 109.3 ;
      RECT 221.9 109.5 222.1 109.7 ;
      RECT 221.9 113.5 222.1 113.7 ;
      RECT 221.9 120.7 222.1 120.9 ;
      RECT 221.9 123.5 222.1 123.7 ;
      RECT 221.9 127.9 222.1 128.1 ;
      RECT 221.9 130.7 222.1 130.9 ;
      RECT 221.5 84.7 221.7 84.9 ;
      RECT 221.5 130.7 221.7 130.9 ;
      RECT 219.9 152.3 220.1 152.5 ;
      RECT 219.9 156.3 220.1 156.5 ;
      RECT 219.9 156.7 220.1 156.9 ;
      RECT 219.5 103.9 219.7 104.1 ;
      RECT 219.5 114.7 219.7 114.9 ;
      RECT 219.5 132.3 219.7 132.5 ;
      RECT 219.5 132.7 219.7 132.9 ;
      RECT 219.5 144.3 219.7 144.5 ;
      RECT 219.5 144.7 219.7 144.9 ;
      RECT 219.5 152.3 219.7 152.5 ;
      RECT 218.3 88.3 218.5 88.5 ;
      RECT 218.3 88.7 218.5 88.9 ;
      RECT 218.3 98.7 218.5 98.9 ;
      RECT 218.3 99.1 218.5 99.3 ;
      RECT 217.5 134.3 217.7 134.5 ;
      RECT 217.5 134.7 217.7 134.9 ;
      RECT 217.5 145.5 217.7 145.7 ;
      RECT 217.5 145.9 217.7 146.1 ;
      RECT 217.1 106.3 217.3 106.5 ;
      RECT 216.7 83.5 216.9 83.7 ;
      RECT 216.7 83.9 216.9 84.1 ;
      RECT 216.7 106.3 216.9 106.5 ;
      RECT 215.9 125.9 216.1 126.1 ;
      RECT 215.5 97.1 215.7 97.3 ;
      RECT 215.5 97.5 215.7 97.7 ;
      RECT 215.5 104.7 215.7 104.9 ;
      RECT 215.5 105.1 215.7 105.3 ;
      RECT 215.5 110.7 215.7 110.9 ;
      RECT 215.5 111.1 215.7 111.3 ;
      RECT 215.5 116.3 215.7 116.5 ;
      RECT 215.5 116.7 215.7 116.9 ;
      RECT 215.5 121.5 215.7 121.7 ;
      RECT 215.5 121.9 215.7 122.1 ;
      RECT 215.5 125.9 215.7 126.1 ;
      RECT 214.7 97.9 214.9 98.1 ;
      RECT 214.7 98.3 214.9 98.5 ;
      RECT 214.7 106.3 214.9 106.5 ;
      RECT 214.7 106.7 214.9 106.9 ;
      RECT 214.7 114.3 214.9 114.5 ;
      RECT 214.7 114.7 214.9 114.9 ;
      RECT 214.7 124.7 214.9 124.9 ;
      RECT 214.7 125.1 214.9 125.3 ;
      RECT 211.9 101.1 212.1 101.3 ;
      RECT 211.9 101.5 212.1 101.7 ;
      RECT 211.9 110.3 212.1 110.5 ;
      RECT 211.9 110.7 212.1 110.9 ;
      RECT 210.3 101.5 210.5 101.7 ;
      RECT 210.3 101.9 210.5 102.1 ;
      RECT 210.3 108.3 210.5 108.5 ;
      RECT 210.3 108.7 210.5 108.9 ;
      RECT 209.5 137.9 209.7 138.1 ;
      RECT 209.5 149.5 209.7 149.7 ;
      RECT 209.5 152.3 209.7 152.5 ;
      RECT 209.1 137.9 209.3 138.1 ;
      RECT 209.1 144.7 209.3 144.9 ;
      RECT 209.1 145.1 209.3 145.3 ;
      RECT 209.1 149.5 209.3 149.7 ;
      RECT 209.1 152.3 209.3 152.5 ;
      RECT 207.8 1 208 1.2 ;
      RECT 207.8 1.6 208 1.8 ;
      RECT 207.8 2.2 208 2.4 ;
      RECT 207.8 2.8 208 3 ;
      RECT 207.8 10.5 208 10.7 ;
      RECT 207.8 17.7 208 17.9 ;
      RECT 207.8 24.9 208 25.1 ;
      RECT 207.8 32.1 208 32.3 ;
      RECT 207.8 39.3 208 39.5 ;
      RECT 207.8 46.5 208 46.7 ;
      RECT 207.8 53.7 208 53.9 ;
      RECT 207.8 60.9 208 61.1 ;
      RECT 207.8 68.1 208 68.3 ;
      RECT 207.8 75.3 208 75.5 ;
      RECT 207.8 82.5 208 82.7 ;
      RECT 207.8 89.7 208 89.9 ;
      RECT 207.8 96.9 208 97.1 ;
      RECT 207.8 104.1 208 104.3 ;
      RECT 207.8 111.3 208 111.5 ;
      RECT 207.8 118.5 208 118.7 ;
      RECT 207.8 125.7 208 125.9 ;
      RECT 207.8 132.9 208 133.1 ;
      RECT 207.8 140.1 208 140.3 ;
      RECT 207.8 147.3 208 147.5 ;
      RECT 207.8 154.5 208 154.7 ;
      RECT 207.8 161.7 208 161.9 ;
      RECT 207.8 168.9 208 169.1 ;
      RECT 207.8 176.1 208 176.3 ;
      RECT 207.8 183.3 208 183.5 ;
      RECT 207.8 190.5 208 190.7 ;
      RECT 207.8 197.7 208 197.9 ;
      RECT 207.8 204.9 208 205.1 ;
      RECT 207.8 212.1 208 212.3 ;
      RECT 207.8 216.6 208 216.8 ;
      RECT 207.8 217.2 208 217.4 ;
      RECT 207.8 217.8 208 218 ;
      RECT 207.8 218.4 208 218.6 ;
      RECT 207.2 1 207.4 1.2 ;
      RECT 207.2 1.6 207.4 1.8 ;
      RECT 207.2 2.2 207.4 2.4 ;
      RECT 207.2 2.8 207.4 3 ;
      RECT 207.2 10.5 207.4 10.7 ;
      RECT 207.2 17.7 207.4 17.9 ;
      RECT 207.2 24.9 207.4 25.1 ;
      RECT 207.2 32.1 207.4 32.3 ;
      RECT 207.2 39.3 207.4 39.5 ;
      RECT 207.2 46.5 207.4 46.7 ;
      RECT 207.2 53.7 207.4 53.9 ;
      RECT 207.2 60.9 207.4 61.1 ;
      RECT 207.2 68.1 207.4 68.3 ;
      RECT 207.2 75.3 207.4 75.5 ;
      RECT 207.2 82.5 207.4 82.7 ;
      RECT 207.2 89.7 207.4 89.9 ;
      RECT 207.2 96.9 207.4 97.1 ;
      RECT 207.2 104.1 207.4 104.3 ;
      RECT 207.2 111.3 207.4 111.5 ;
      RECT 207.2 118.5 207.4 118.7 ;
      RECT 207.2 125.7 207.4 125.9 ;
      RECT 207.2 132.9 207.4 133.1 ;
      RECT 207.2 140.1 207.4 140.3 ;
      RECT 207.2 147.3 207.4 147.5 ;
      RECT 207.2 154.5 207.4 154.7 ;
      RECT 207.2 161.7 207.4 161.9 ;
      RECT 207.2 168.9 207.4 169.1 ;
      RECT 207.2 176.1 207.4 176.3 ;
      RECT 207.2 183.3 207.4 183.5 ;
      RECT 207.2 190.5 207.4 190.7 ;
      RECT 207.2 197.7 207.4 197.9 ;
      RECT 207.2 204.9 207.4 205.1 ;
      RECT 207.2 212.1 207.4 212.3 ;
      RECT 207.2 216.6 207.4 216.8 ;
      RECT 207.2 217.2 207.4 217.4 ;
      RECT 207.2 217.8 207.4 218 ;
      RECT 207.2 218.4 207.4 218.6 ;
      RECT 206.6 1 206.8 1.2 ;
      RECT 206.6 1.6 206.8 1.8 ;
      RECT 206.6 2.2 206.8 2.4 ;
      RECT 206.6 2.8 206.8 3 ;
      RECT 206.6 10.5 206.8 10.7 ;
      RECT 206.6 17.7 206.8 17.9 ;
      RECT 206.6 24.9 206.8 25.1 ;
      RECT 206.6 32.1 206.8 32.3 ;
      RECT 206.6 39.3 206.8 39.5 ;
      RECT 206.6 46.5 206.8 46.7 ;
      RECT 206.6 53.7 206.8 53.9 ;
      RECT 206.6 60.9 206.8 61.1 ;
      RECT 206.6 68.1 206.8 68.3 ;
      RECT 206.6 75.3 206.8 75.5 ;
      RECT 206.6 82.5 206.8 82.7 ;
      RECT 206.6 89.7 206.8 89.9 ;
      RECT 206.6 96.9 206.8 97.1 ;
      RECT 206.6 104.1 206.8 104.3 ;
      RECT 206.6 111.3 206.8 111.5 ;
      RECT 206.6 118.5 206.8 118.7 ;
      RECT 206.6 125.7 206.8 125.9 ;
      RECT 206.6 132.9 206.8 133.1 ;
      RECT 206.6 140.1 206.8 140.3 ;
      RECT 206.6 147.3 206.8 147.5 ;
      RECT 206.6 154.5 206.8 154.7 ;
      RECT 206.6 161.7 206.8 161.9 ;
      RECT 206.6 168.9 206.8 169.1 ;
      RECT 206.6 176.1 206.8 176.3 ;
      RECT 206.6 183.3 206.8 183.5 ;
      RECT 206.6 190.5 206.8 190.7 ;
      RECT 206.6 197.7 206.8 197.9 ;
      RECT 206.6 204.9 206.8 205.1 ;
      RECT 206.6 212.1 206.8 212.3 ;
      RECT 206.6 216.6 206.8 216.8 ;
      RECT 206.6 217.2 206.8 217.4 ;
      RECT 206.6 217.8 206.8 218 ;
      RECT 206.6 218.4 206.8 218.6 ;
      RECT 206 1 206.2 1.2 ;
      RECT 206 1.6 206.2 1.8 ;
      RECT 206 2.2 206.2 2.4 ;
      RECT 206 2.8 206.2 3 ;
      RECT 206 10.5 206.2 10.7 ;
      RECT 206 17.7 206.2 17.9 ;
      RECT 206 24.9 206.2 25.1 ;
      RECT 206 32.1 206.2 32.3 ;
      RECT 206 39.3 206.2 39.5 ;
      RECT 206 46.5 206.2 46.7 ;
      RECT 206 53.7 206.2 53.9 ;
      RECT 206 60.9 206.2 61.1 ;
      RECT 206 68.1 206.2 68.3 ;
      RECT 206 75.3 206.2 75.5 ;
      RECT 206 82.5 206.2 82.7 ;
      RECT 206 89.7 206.2 89.9 ;
      RECT 206 96.9 206.2 97.1 ;
      RECT 206 104.1 206.2 104.3 ;
      RECT 206 111.3 206.2 111.5 ;
      RECT 206 118.5 206.2 118.7 ;
      RECT 206 125.7 206.2 125.9 ;
      RECT 206 132.9 206.2 133.1 ;
      RECT 206 140.1 206.2 140.3 ;
      RECT 206 147.3 206.2 147.5 ;
      RECT 206 154.5 206.2 154.7 ;
      RECT 206 161.7 206.2 161.9 ;
      RECT 206 168.9 206.2 169.1 ;
      RECT 206 176.1 206.2 176.3 ;
      RECT 206 183.3 206.2 183.5 ;
      RECT 206 190.5 206.2 190.7 ;
      RECT 206 197.7 206.2 197.9 ;
      RECT 206 204.9 206.2 205.1 ;
      RECT 206 212.1 206.2 212.3 ;
      RECT 206 216.6 206.2 216.8 ;
      RECT 206 217.2 206.2 217.4 ;
      RECT 206 217.8 206.2 218 ;
      RECT 206 218.4 206.2 218.6 ;
      RECT 205.5 91.9 205.7 92.1 ;
      RECT 205.5 94.7 205.7 94.9 ;
      RECT 205.5 106.3 205.7 106.5 ;
      RECT 205.5 109.1 205.7 109.3 ;
      RECT 205.5 116.3 205.7 116.5 ;
      RECT 205.5 120.7 205.7 120.9 ;
      RECT 205.5 123.5 205.7 123.7 ;
      RECT 205.5 137.9 205.7 138.1 ;
      RECT 205.1 87.5 205.3 87.7 ;
      RECT 205.1 91.9 205.3 92.1 ;
      RECT 205.1 94.7 205.3 94.9 ;
      RECT 205.1 99.1 205.3 99.3 ;
      RECT 205.1 99.5 205.3 99.7 ;
      RECT 205.1 106.3 205.3 106.5 ;
      RECT 205.1 109.1 205.3 109.3 ;
      RECT 205.1 116.3 205.3 116.5 ;
      RECT 205.1 120.7 205.3 120.9 ;
      RECT 205.1 123.5 205.3 123.7 ;
      RECT 205.1 135.1 205.3 135.3 ;
      RECT 205.1 137.9 205.3 138.1 ;
      RECT 204.7 87.5 204.9 87.7 ;
      RECT 204.7 135.1 204.9 135.3 ;
      RECT 204.3 91.1 204.5 91.3 ;
      RECT 204.3 91.5 204.5 91.7 ;
      RECT 204.3 98.7 204.5 98.9 ;
      RECT 204.3 99.1 204.5 99.3 ;
      RECT 204.3 102.3 204.5 102.5 ;
      RECT 204.3 102.7 204.5 102.9 ;
      RECT 204.3 112.7 204.5 112.9 ;
      RECT 204.3 113.1 204.5 113.3 ;
      RECT 204.3 121.1 204.5 121.3 ;
      RECT 204.3 121.5 204.5 121.7 ;
      RECT 203.8 4 204 4.2 ;
      RECT 203.8 4.6 204 4.8 ;
      RECT 203.8 5.2 204 5.4 ;
      RECT 203.8 5.8 204 6 ;
      RECT 203.8 6.9 204 7.1 ;
      RECT 203.8 14.1 204 14.3 ;
      RECT 203.8 21.3 204 21.5 ;
      RECT 203.8 28.5 204 28.7 ;
      RECT 203.8 35.7 204 35.9 ;
      RECT 203.8 42.9 204 43.1 ;
      RECT 203.8 50.1 204 50.3 ;
      RECT 203.8 57.3 204 57.5 ;
      RECT 203.8 64.5 204 64.7 ;
      RECT 203.8 71.7 204 71.9 ;
      RECT 203.8 78.9 204 79.1 ;
      RECT 203.8 86.1 204 86.3 ;
      RECT 203.8 93.3 204 93.5 ;
      RECT 203.8 100.5 204 100.7 ;
      RECT 203.8 107.7 204 107.9 ;
      RECT 203.8 114.9 204 115.1 ;
      RECT 203.8 122.1 204 122.3 ;
      RECT 203.8 129.3 204 129.5 ;
      RECT 203.8 136.5 204 136.7 ;
      RECT 203.8 143.7 204 143.9 ;
      RECT 203.8 150.9 204 151.1 ;
      RECT 203.8 158.1 204 158.3 ;
      RECT 203.8 165.3 204 165.5 ;
      RECT 203.8 172.5 204 172.7 ;
      RECT 203.8 179.7 204 179.9 ;
      RECT 203.8 186.9 204 187.1 ;
      RECT 203.8 194.1 204 194.3 ;
      RECT 203.8 201.3 204 201.5 ;
      RECT 203.8 208.5 204 208.7 ;
      RECT 203.8 213.6 204 213.8 ;
      RECT 203.8 214.2 204 214.4 ;
      RECT 203.8 214.8 204 215 ;
      RECT 203.8 215.4 204 215.6 ;
      RECT 203.2 4 203.4 4.2 ;
      RECT 203.2 4.6 203.4 4.8 ;
      RECT 203.2 5.2 203.4 5.4 ;
      RECT 203.2 5.8 203.4 6 ;
      RECT 203.2 6.9 203.4 7.1 ;
      RECT 203.2 14.1 203.4 14.3 ;
      RECT 203.2 21.3 203.4 21.5 ;
      RECT 203.2 28.5 203.4 28.7 ;
      RECT 203.2 35.7 203.4 35.9 ;
      RECT 203.2 42.9 203.4 43.1 ;
      RECT 203.2 50.1 203.4 50.3 ;
      RECT 203.2 57.3 203.4 57.5 ;
      RECT 203.2 64.5 203.4 64.7 ;
      RECT 203.2 71.7 203.4 71.9 ;
      RECT 203.2 78.9 203.4 79.1 ;
      RECT 203.2 86.1 203.4 86.3 ;
      RECT 203.2 93.3 203.4 93.5 ;
      RECT 203.2 100.5 203.4 100.7 ;
      RECT 203.2 107.7 203.4 107.9 ;
      RECT 203.2 114.9 203.4 115.1 ;
      RECT 203.2 122.1 203.4 122.3 ;
      RECT 203.2 129.3 203.4 129.5 ;
      RECT 203.2 136.5 203.4 136.7 ;
      RECT 203.2 143.7 203.4 143.9 ;
      RECT 203.2 150.9 203.4 151.1 ;
      RECT 203.2 158.1 203.4 158.3 ;
      RECT 203.2 165.3 203.4 165.5 ;
      RECT 203.2 172.5 203.4 172.7 ;
      RECT 203.2 179.7 203.4 179.9 ;
      RECT 203.2 186.9 203.4 187.1 ;
      RECT 203.2 194.1 203.4 194.3 ;
      RECT 203.2 201.3 203.4 201.5 ;
      RECT 203.2 208.5 203.4 208.7 ;
      RECT 203.2 213.6 203.4 213.8 ;
      RECT 203.2 214.2 203.4 214.4 ;
      RECT 203.2 214.8 203.4 215 ;
      RECT 203.2 215.4 203.4 215.6 ;
      RECT 202.6 4 202.8 4.2 ;
      RECT 202.6 4.6 202.8 4.8 ;
      RECT 202.6 5.2 202.8 5.4 ;
      RECT 202.6 5.8 202.8 6 ;
      RECT 202.6 6.9 202.8 7.1 ;
      RECT 202.6 14.1 202.8 14.3 ;
      RECT 202.6 21.3 202.8 21.5 ;
      RECT 202.6 28.5 202.8 28.7 ;
      RECT 202.6 35.7 202.8 35.9 ;
      RECT 202.6 42.9 202.8 43.1 ;
      RECT 202.6 50.1 202.8 50.3 ;
      RECT 202.6 57.3 202.8 57.5 ;
      RECT 202.6 64.5 202.8 64.7 ;
      RECT 202.6 71.7 202.8 71.9 ;
      RECT 202.6 78.9 202.8 79.1 ;
      RECT 202.6 86.1 202.8 86.3 ;
      RECT 202.6 93.3 202.8 93.5 ;
      RECT 202.6 100.5 202.8 100.7 ;
      RECT 202.6 107.7 202.8 107.9 ;
      RECT 202.6 114.9 202.8 115.1 ;
      RECT 202.6 122.1 202.8 122.3 ;
      RECT 202.6 129.3 202.8 129.5 ;
      RECT 202.6 136.5 202.8 136.7 ;
      RECT 202.6 143.7 202.8 143.9 ;
      RECT 202.6 150.9 202.8 151.1 ;
      RECT 202.6 158.1 202.8 158.3 ;
      RECT 202.6 165.3 202.8 165.5 ;
      RECT 202.6 172.5 202.8 172.7 ;
      RECT 202.6 179.7 202.8 179.9 ;
      RECT 202.6 186.9 202.8 187.1 ;
      RECT 202.6 194.1 202.8 194.3 ;
      RECT 202.6 201.3 202.8 201.5 ;
      RECT 202.6 208.5 202.8 208.7 ;
      RECT 202.6 213.6 202.8 213.8 ;
      RECT 202.6 214.2 202.8 214.4 ;
      RECT 202.6 214.8 202.8 215 ;
      RECT 202.6 215.4 202.8 215.6 ;
      RECT 202 4 202.2 4.2 ;
      RECT 202 4.6 202.2 4.8 ;
      RECT 202 5.2 202.2 5.4 ;
      RECT 202 5.8 202.2 6 ;
      RECT 202 6.9 202.2 7.1 ;
      RECT 202 14.1 202.2 14.3 ;
      RECT 202 21.3 202.2 21.5 ;
      RECT 202 28.5 202.2 28.7 ;
      RECT 202 35.7 202.2 35.9 ;
      RECT 202 42.9 202.2 43.1 ;
      RECT 202 50.1 202.2 50.3 ;
      RECT 202 57.3 202.2 57.5 ;
      RECT 202 64.5 202.2 64.7 ;
      RECT 202 71.7 202.2 71.9 ;
      RECT 202 78.9 202.2 79.1 ;
      RECT 202 86.1 202.2 86.3 ;
      RECT 202 93.3 202.2 93.5 ;
      RECT 202 100.5 202.2 100.7 ;
      RECT 202 107.7 202.2 107.9 ;
      RECT 202 114.9 202.2 115.1 ;
      RECT 202 122.1 202.2 122.3 ;
      RECT 202 129.3 202.2 129.5 ;
      RECT 202 136.5 202.2 136.7 ;
      RECT 202 143.7 202.2 143.9 ;
      RECT 202 150.9 202.2 151.1 ;
      RECT 202 158.1 202.2 158.3 ;
      RECT 202 165.3 202.2 165.5 ;
      RECT 202 172.5 202.2 172.7 ;
      RECT 202 179.7 202.2 179.9 ;
      RECT 202 186.9 202.2 187.1 ;
      RECT 202 194.1 202.2 194.3 ;
      RECT 202 201.3 202.2 201.5 ;
      RECT 202 208.5 202.2 208.7 ;
      RECT 202 213.6 202.2 213.8 ;
      RECT 202 214.2 202.2 214.4 ;
      RECT 202 214.8 202.2 215 ;
      RECT 202 215.4 202.2 215.6 ;
      RECT 201.5 121.5 201.7 121.7 ;
      RECT 201.5 121.9 201.7 122.1 ;
      RECT 201.5 126.3 201.7 126.5 ;
      RECT 201.5 126.7 201.7 126.9 ;
      RECT 201.5 138.7 201.7 138.9 ;
      RECT 201.5 139.1 201.7 139.3 ;
      RECT 201.5 144.7 201.7 144.9 ;
      RECT 201.5 145.1 201.7 145.3 ;
      RECT 200.3 112.7 200.5 112.9 ;
      RECT 200.3 113.1 200.5 113.3 ;
      RECT 200.3 120.7 200.5 120.9 ;
      RECT 200.3 121.1 200.5 121.3 ;
      RECT 200.3 130.3 200.5 130.5 ;
      RECT 200.3 130.7 200.5 130.9 ;
      RECT 197.9 126.7 198.1 126.9 ;
      RECT 197.5 126.7 197.7 126.9 ;
      RECT 197.5 131.9 197.7 132.1 ;
      RECT 197.5 132.3 197.7 132.5 ;
      RECT 195.5 135.1 195.7 135.3 ;
      RECT 195.1 135.1 195.3 135.3 ;
      RECT 195.1 145.1 195.3 145.3 ;
      RECT 195.1 145.5 195.3 145.7 ;
      RECT 195.1 149.5 195.3 149.7 ;
      RECT 195.1 156.7 195.3 156.9 ;
      RECT 194.7 149.5 194.9 149.7 ;
      RECT 194.7 156.7 194.9 156.9 ;
      RECT 193.1 181.1 193.3 181.3 ;
      RECT 192.7 181.1 192.9 181.3 ;
      RECT 192.7 188.3 192.9 188.5 ;
      RECT 192.7 192.7 192.9 192.9 ;
      RECT 192.3 188.3 192.5 188.5 ;
      RECT 192.3 192.7 192.5 192.9 ;
      RECT 191.1 149.5 191.3 149.7 ;
      RECT 190.7 149.5 190.9 149.7 ;
      RECT 190.7 151.9 190.9 152.1 ;
      RECT 190.7 152.3 190.9 152.5 ;
      RECT 189.9 166.7 190.1 166.9 ;
      RECT 189.5 163.9 189.7 164.1 ;
      RECT 189.5 164.3 189.7 164.5 ;
      RECT 189.5 166.7 189.7 166.9 ;
      RECT 189.1 198.7 189.3 198.9 ;
      RECT 188.7 177.5 188.9 177.7 ;
      RECT 188.7 177.9 188.9 178.1 ;
      RECT 188.7 198.7 188.9 198.9 ;
      RECT 187.5 193.9 187.7 194.1 ;
      RECT 187.5 194.3 187.7 194.5 ;
      RECT 187.5 196.3 187.7 196.5 ;
      RECT 187.5 196.7 187.7 196.9 ;
      RECT 187.1 87.5 187.3 87.7 ;
      RECT 187.1 201.1 187.3 201.3 ;
      RECT 186.7 87.5 186.9 87.7 ;
      RECT 186.7 91.9 186.9 92.1 ;
      RECT 186.7 201.1 186.9 201.3 ;
      RECT 186.7 207.1 186.9 207.3 ;
      RECT 186.3 91.9 186.5 92.1 ;
      RECT 186.3 207.1 186.5 207.3 ;
      RECT 185.5 177.1 185.7 177.3 ;
      RECT 185.5 197.1 185.7 197.3 ;
      RECT 185.1 99.1 185.3 99.3 ;
      RECT 185.1 106.3 185.3 106.5 ;
      RECT 185.1 166.7 185.3 166.9 ;
      RECT 184.7 99.1 184.9 99.3 ;
      RECT 184.7 106.3 184.9 106.5 ;
      RECT 184.7 166.7 184.9 166.9 ;
      RECT 184.7 171.1 184.9 171.3 ;
      RECT 184.3 171.1 184.5 171.3 ;
      RECT 183.9 132.3 184.1 132.5 ;
      RECT 183.9 132.7 184.1 132.9 ;
      RECT 183.9 151.1 184.1 151.3 ;
      RECT 183.9 155.1 184.1 155.3 ;
      RECT 183.9 199.9 184.1 200.1 ;
      RECT 183.5 155.1 183.7 155.3 ;
      RECT 183.5 192.3 183.7 192.5 ;
      RECT 183.5 192.7 183.7 192.9 ;
      RECT 183.5 199.9 183.7 200.1 ;
      RECT 183.1 164.3 183.3 164.5 ;
      RECT 183.1 164.7 183.3 164.9 ;
      RECT 183.1 184.3 183.3 184.5 ;
      RECT 183.1 184.7 183.3 184.9 ;
      RECT 182.7 181.1 182.9 181.3 ;
      RECT 182.7 191.9 182.9 192.1 ;
      RECT 182.7 195.5 182.9 195.7 ;
      RECT 182.7 195.9 182.9 196.1 ;
      RECT 182.7 198.3 182.9 198.5 ;
      RECT 182.7 198.7 182.9 198.9 ;
      RECT 181.9 145.9 182.1 146.1 ;
      RECT 181.9 171.5 182.1 171.7 ;
      RECT 181.1 207.1 181.3 207.3 ;
      RECT 180.7 172.7 180.9 172.9 ;
      RECT 180.7 173.1 180.9 173.3 ;
      RECT 180.7 207.1 180.9 207.3 ;
      RECT 180.3 102.7 180.5 102.9 ;
      RECT 180.3 103.1 180.5 103.3 ;
      RECT 180.3 166.7 180.5 166.9 ;
      RECT 179.9 164.7 180.1 164.9 ;
      RECT 179.9 166.7 180.1 166.9 ;
      RECT 179.5 102.3 179.7 102.5 ;
      RECT 179.5 102.7 179.7 102.9 ;
      RECT 179.5 144.3 179.7 144.5 ;
      RECT 179.5 144.7 179.7 144.9 ;
      RECT 179.5 148.3 179.7 148.5 ;
      RECT 179.5 148.7 179.7 148.9 ;
      RECT 179.5 164.7 179.7 164.9 ;
      RECT 179.5 198.3 179.7 198.5 ;
      RECT 179.5 205.1 179.7 205.3 ;
      RECT 179.1 161.5 179.3 161.7 ;
      RECT 179.1 161.9 179.3 162.1 ;
      RECT 179.1 176.3 179.3 176.5 ;
      RECT 179.1 176.7 179.3 176.9 ;
      RECT 179.1 191.9 179.3 192.1 ;
      RECT 179.1 198.7 179.3 198.9 ;
      RECT 179.1 200.3 179.3 200.5 ;
      RECT 178.7 131.5 178.9 131.7 ;
      RECT 178.7 131.9 178.9 132.1 ;
      RECT 178.7 172.7 178.9 172.9 ;
      RECT 178.7 173.9 178.9 174.1 ;
      RECT 178.7 178.3 178.9 178.5 ;
      RECT 178.7 181.1 178.9 181.3 ;
      RECT 178.7 188.3 178.9 188.5 ;
      RECT 178.7 195.5 178.9 195.7 ;
      RECT 178.7 201.1 178.9 201.3 ;
      RECT 178.3 125.1 178.5 125.3 ;
      RECT 178.3 125.5 178.5 125.7 ;
      RECT 178.3 126.7 178.5 126.9 ;
      RECT 178.3 127.1 178.5 127.3 ;
      RECT 178.3 129.5 178.5 129.7 ;
      RECT 178.3 134.7 178.5 134.9 ;
      RECT 178.3 146.3 178.5 146.5 ;
      RECT 178.3 149.5 178.5 149.7 ;
      RECT 178.3 159.5 178.5 159.7 ;
      RECT 178.3 159.9 178.5 160.1 ;
      RECT 178.3 164.3 178.5 164.5 ;
      RECT 178.3 164.7 178.5 164.9 ;
      RECT 178.3 171.1 178.5 171.3 ;
      RECT 178.3 171.5 178.5 171.7 ;
      RECT 178.3 172.7 178.5 172.9 ;
      RECT 178.3 173.9 178.5 174.1 ;
      RECT 178.3 178.3 178.5 178.5 ;
      RECT 178.3 181.1 178.5 181.3 ;
      RECT 178.3 188.3 178.5 188.5 ;
      RECT 178.3 192.7 178.5 192.9 ;
      RECT 178.3 193.1 178.5 193.3 ;
      RECT 178.3 195.5 178.5 195.7 ;
      RECT 178.3 201.1 178.5 201.3 ;
      RECT 178.3 203.5 178.5 203.7 ;
      RECT 178.3 203.9 178.5 204.1 ;
      RECT 178.3 208.3 178.5 208.5 ;
      RECT 178.3 208.7 178.5 208.9 ;
      RECT 177.8 1 178 1.2 ;
      RECT 177.8 1.6 178 1.8 ;
      RECT 177.8 2.2 178 2.4 ;
      RECT 177.8 2.8 178 3 ;
      RECT 177.8 10.5 178 10.7 ;
      RECT 177.8 17.7 178 17.9 ;
      RECT 177.8 24.9 178 25.1 ;
      RECT 177.8 32.1 178 32.3 ;
      RECT 177.8 39.3 178 39.5 ;
      RECT 177.8 46.5 178 46.7 ;
      RECT 177.8 53.7 178 53.9 ;
      RECT 177.8 60.9 178 61.1 ;
      RECT 177.8 68.1 178 68.3 ;
      RECT 177.8 75.3 178 75.5 ;
      RECT 177.8 82.5 178 82.7 ;
      RECT 177.8 89.7 178 89.9 ;
      RECT 177.8 96.9 178 97.1 ;
      RECT 177.8 104.1 178 104.3 ;
      RECT 177.8 111.3 178 111.5 ;
      RECT 177.8 118.5 178 118.7 ;
      RECT 177.8 125.7 178 125.9 ;
      RECT 177.8 132.9 178 133.1 ;
      RECT 177.8 140.1 178 140.3 ;
      RECT 177.8 147.3 178 147.5 ;
      RECT 177.8 154.5 178 154.7 ;
      RECT 177.8 161.7 178 161.9 ;
      RECT 177.8 168.9 178 169.1 ;
      RECT 177.8 176.1 178 176.3 ;
      RECT 177.8 183.3 178 183.5 ;
      RECT 177.8 190.5 178 190.7 ;
      RECT 177.8 197.7 178 197.9 ;
      RECT 177.8 204.9 178 205.1 ;
      RECT 177.8 212.1 178 212.3 ;
      RECT 177.8 216.6 178 216.8 ;
      RECT 177.8 217.2 178 217.4 ;
      RECT 177.8 217.8 178 218 ;
      RECT 177.8 218.4 178 218.6 ;
      RECT 177.2 1 177.4 1.2 ;
      RECT 177.2 1.6 177.4 1.8 ;
      RECT 177.2 2.2 177.4 2.4 ;
      RECT 177.2 2.8 177.4 3 ;
      RECT 177.2 10.5 177.4 10.7 ;
      RECT 177.2 17.7 177.4 17.9 ;
      RECT 177.2 24.9 177.4 25.1 ;
      RECT 177.2 32.1 177.4 32.3 ;
      RECT 177.2 39.3 177.4 39.5 ;
      RECT 177.2 46.5 177.4 46.7 ;
      RECT 177.2 53.7 177.4 53.9 ;
      RECT 177.2 60.9 177.4 61.1 ;
      RECT 177.2 68.1 177.4 68.3 ;
      RECT 177.2 75.3 177.4 75.5 ;
      RECT 177.2 82.5 177.4 82.7 ;
      RECT 177.2 89.7 177.4 89.9 ;
      RECT 177.2 96.9 177.4 97.1 ;
      RECT 177.2 104.1 177.4 104.3 ;
      RECT 177.2 111.3 177.4 111.5 ;
      RECT 177.2 118.5 177.4 118.7 ;
      RECT 177.2 125.7 177.4 125.9 ;
      RECT 177.2 132.9 177.4 133.1 ;
      RECT 177.2 140.1 177.4 140.3 ;
      RECT 177.2 147.3 177.4 147.5 ;
      RECT 177.2 154.5 177.4 154.7 ;
      RECT 177.2 161.7 177.4 161.9 ;
      RECT 177.2 168.9 177.4 169.1 ;
      RECT 177.2 176.1 177.4 176.3 ;
      RECT 177.2 183.3 177.4 183.5 ;
      RECT 177.2 190.5 177.4 190.7 ;
      RECT 177.2 197.7 177.4 197.9 ;
      RECT 177.2 204.9 177.4 205.1 ;
      RECT 177.2 212.1 177.4 212.3 ;
      RECT 177.2 216.6 177.4 216.8 ;
      RECT 177.2 217.2 177.4 217.4 ;
      RECT 177.2 217.8 177.4 218 ;
      RECT 177.2 218.4 177.4 218.6 ;
      RECT 176.6 1 176.8 1.2 ;
      RECT 176.6 1.6 176.8 1.8 ;
      RECT 176.6 2.2 176.8 2.4 ;
      RECT 176.6 2.8 176.8 3 ;
      RECT 176.6 10.5 176.8 10.7 ;
      RECT 176.6 17.7 176.8 17.9 ;
      RECT 176.6 24.9 176.8 25.1 ;
      RECT 176.6 32.1 176.8 32.3 ;
      RECT 176.6 39.3 176.8 39.5 ;
      RECT 176.6 46.5 176.8 46.7 ;
      RECT 176.6 53.7 176.8 53.9 ;
      RECT 176.6 60.9 176.8 61.1 ;
      RECT 176.6 68.1 176.8 68.3 ;
      RECT 176.6 75.3 176.8 75.5 ;
      RECT 176.6 82.5 176.8 82.7 ;
      RECT 176.6 89.7 176.8 89.9 ;
      RECT 176.6 96.9 176.8 97.1 ;
      RECT 176.6 104.1 176.8 104.3 ;
      RECT 176.6 111.3 176.8 111.5 ;
      RECT 176.6 118.5 176.8 118.7 ;
      RECT 176.6 125.7 176.8 125.9 ;
      RECT 176.6 132.9 176.8 133.1 ;
      RECT 176.6 140.1 176.8 140.3 ;
      RECT 176.6 147.3 176.8 147.5 ;
      RECT 176.6 154.5 176.8 154.7 ;
      RECT 176.6 161.7 176.8 161.9 ;
      RECT 176.6 168.9 176.8 169.1 ;
      RECT 176.6 176.1 176.8 176.3 ;
      RECT 176.6 183.3 176.8 183.5 ;
      RECT 176.6 190.5 176.8 190.7 ;
      RECT 176.6 197.7 176.8 197.9 ;
      RECT 176.6 204.9 176.8 205.1 ;
      RECT 176.6 212.1 176.8 212.3 ;
      RECT 176.6 216.6 176.8 216.8 ;
      RECT 176.6 217.2 176.8 217.4 ;
      RECT 176.6 217.8 176.8 218 ;
      RECT 176.6 218.4 176.8 218.6 ;
      RECT 176 1 176.2 1.2 ;
      RECT 176 1.6 176.2 1.8 ;
      RECT 176 2.2 176.2 2.4 ;
      RECT 176 2.8 176.2 3 ;
      RECT 176 10.5 176.2 10.7 ;
      RECT 176 17.7 176.2 17.9 ;
      RECT 176 24.9 176.2 25.1 ;
      RECT 176 32.1 176.2 32.3 ;
      RECT 176 39.3 176.2 39.5 ;
      RECT 176 46.5 176.2 46.7 ;
      RECT 176 53.7 176.2 53.9 ;
      RECT 176 60.9 176.2 61.1 ;
      RECT 176 68.1 176.2 68.3 ;
      RECT 176 75.3 176.2 75.5 ;
      RECT 176 82.5 176.2 82.7 ;
      RECT 176 89.7 176.2 89.9 ;
      RECT 176 96.9 176.2 97.1 ;
      RECT 176 104.1 176.2 104.3 ;
      RECT 176 111.3 176.2 111.5 ;
      RECT 176 118.5 176.2 118.7 ;
      RECT 176 125.7 176.2 125.9 ;
      RECT 176 132.9 176.2 133.1 ;
      RECT 176 140.1 176.2 140.3 ;
      RECT 176 147.3 176.2 147.5 ;
      RECT 176 154.5 176.2 154.7 ;
      RECT 176 161.7 176.2 161.9 ;
      RECT 176 168.9 176.2 169.1 ;
      RECT 176 176.1 176.2 176.3 ;
      RECT 176 183.3 176.2 183.5 ;
      RECT 176 190.5 176.2 190.7 ;
      RECT 176 197.7 176.2 197.9 ;
      RECT 176 204.9 176.2 205.1 ;
      RECT 176 212.1 176.2 212.3 ;
      RECT 176 216.6 176.2 216.8 ;
      RECT 176 217.2 176.2 217.4 ;
      RECT 176 217.8 176.2 218 ;
      RECT 176 218.4 176.2 218.6 ;
      RECT 175.5 67.9 175.7 68.1 ;
      RECT 175.5 68.3 175.7 68.5 ;
      RECT 175.5 97.5 175.7 97.7 ;
      RECT 175.5 97.9 175.7 98.1 ;
      RECT 175.5 105.1 175.7 105.3 ;
      RECT 175.5 121.5 175.7 121.7 ;
      RECT 175.5 123.9 175.7 124.1 ;
      RECT 175.5 124.3 175.7 124.5 ;
      RECT 175.5 126.7 175.7 126.9 ;
      RECT 175.5 127.1 175.7 127.3 ;
      RECT 175.5 129.9 175.7 130.1 ;
      RECT 175.5 151.1 175.7 151.3 ;
      RECT 175.5 151.5 175.7 151.7 ;
      RECT 175.5 168.3 175.7 168.5 ;
      RECT 175.5 168.7 175.7 168.9 ;
      RECT 175.5 169.1 175.7 169.3 ;
      RECT 175.5 169.5 175.7 169.7 ;
      RECT 175.1 96.3 175.3 96.5 ;
      RECT 175.1 96.7 175.3 96.9 ;
      RECT 175.1 99.1 175.3 99.3 ;
      RECT 175.1 99.5 175.3 99.7 ;
      RECT 175.1 105.1 175.3 105.3 ;
      RECT 175.1 113.5 175.3 113.7 ;
      RECT 175.1 121.5 175.3 121.7 ;
      RECT 175.1 123.5 175.3 123.7 ;
      RECT 175.1 129.9 175.3 130.1 ;
      RECT 175.1 134.3 175.3 134.5 ;
      RECT 175.1 134.7 175.3 134.9 ;
      RECT 175.1 156.7 175.3 156.9 ;
      RECT 175.1 157.1 175.3 157.3 ;
      RECT 174.7 19.9 174.9 20.1 ;
      RECT 174.7 22.7 174.9 22.9 ;
      RECT 174.7 29.9 174.9 30.1 ;
      RECT 174.7 41.5 174.9 41.7 ;
      RECT 174.7 55.9 174.9 56.1 ;
      RECT 174.7 73.1 174.9 73.3 ;
      RECT 174.7 77.5 174.9 77.7 ;
      RECT 174.7 80.3 174.9 80.5 ;
      RECT 174.7 81.1 174.9 81.3 ;
      RECT 174.7 113.5 174.9 113.7 ;
      RECT 174.7 116.3 174.9 116.5 ;
      RECT 174.7 116.7 174.9 116.9 ;
      RECT 174.7 123.5 174.9 123.7 ;
      RECT 174.7 126.7 174.9 126.9 ;
      RECT 174.7 127.1 174.9 127.3 ;
      RECT 174.7 128.3 174.9 128.5 ;
      RECT 174.7 128.7 174.9 128.9 ;
      RECT 174.7 142.7 174.9 142.9 ;
      RECT 174.7 155.5 174.9 155.7 ;
      RECT 174.7 159.9 174.9 160.1 ;
      RECT 174.7 163.5 174.9 163.7 ;
      RECT 174.7 180.3 174.9 180.5 ;
      RECT 174.7 180.7 174.9 180.9 ;
      RECT 174.7 185.5 174.9 185.7 ;
      RECT 174.7 185.9 174.9 186.1 ;
      RECT 174.3 12.7 174.5 12.9 ;
      RECT 174.3 13.1 174.5 13.3 ;
      RECT 174.3 15.5 174.5 15.7 ;
      RECT 174.3 15.9 174.5 16.1 ;
      RECT 174.3 19.9 174.5 20.1 ;
      RECT 174.3 22.7 174.5 22.9 ;
      RECT 174.3 27.1 174.5 27.3 ;
      RECT 174.3 27.5 174.5 27.7 ;
      RECT 174.3 29.9 174.5 30.1 ;
      RECT 174.3 34.3 174.5 34.5 ;
      RECT 174.3 34.7 174.5 34.9 ;
      RECT 174.3 37.1 174.5 37.3 ;
      RECT 174.3 37.5 174.5 37.7 ;
      RECT 174.3 41.5 174.5 41.7 ;
      RECT 174.3 48.7 174.5 48.9 ;
      RECT 174.3 49.1 174.5 49.3 ;
      RECT 174.3 51.5 174.5 51.7 ;
      RECT 174.3 51.9 174.5 52.1 ;
      RECT 174.3 55.9 174.5 56.1 ;
      RECT 174.3 58.3 174.5 58.5 ;
      RECT 174.3 58.7 174.5 58.9 ;
      RECT 174.3 63.1 174.5 63.3 ;
      RECT 174.3 63.5 174.5 63.7 ;
      RECT 174.3 65.9 174.5 66.1 ;
      RECT 174.3 66.3 174.5 66.5 ;
      RECT 174.3 73.1 174.5 73.3 ;
      RECT 174.3 77.5 174.5 77.7 ;
      RECT 174.3 80.3 174.5 80.5 ;
      RECT 174.3 84.7 174.5 84.9 ;
      RECT 174.3 85.1 174.5 85.3 ;
      RECT 174.3 89.1 174.5 89.3 ;
      RECT 174.3 95.1 174.5 95.3 ;
      RECT 174.3 98.7 174.5 98.9 ;
      RECT 174.3 101.9 174.5 102.1 ;
      RECT 174.3 127.9 174.5 128.1 ;
      RECT 174.3 129.5 174.5 129.7 ;
      RECT 174.3 133.9 174.5 134.1 ;
      RECT 174.3 134.3 174.5 134.5 ;
      RECT 174.3 136.7 174.5 136.9 ;
      RECT 174.3 137.1 174.5 137.3 ;
      RECT 174.3 140.7 174.5 140.9 ;
      RECT 174.3 141.1 174.5 141.3 ;
      RECT 174.3 142.7 174.5 142.9 ;
      RECT 174.3 151.1 174.5 151.3 ;
      RECT 174.3 151.5 174.5 151.7 ;
      RECT 174.3 155.5 174.5 155.7 ;
      RECT 174.3 159.9 174.5 160.1 ;
      RECT 174.3 161.1 174.5 161.3 ;
      RECT 174.3 161.5 174.5 161.7 ;
      RECT 174.3 163.5 174.5 163.7 ;
      RECT 174.3 169.5 174.5 169.7 ;
      RECT 174.3 169.9 174.5 170.1 ;
      RECT 174.3 171.9 174.5 172.1 ;
      RECT 174.3 172.3 174.5 172.5 ;
      RECT 174.3 174.3 174.5 174.5 ;
      RECT 174.3 174.7 174.5 174.9 ;
      RECT 174.3 186.3 174.5 186.5 ;
      RECT 174.3 188.3 174.5 188.5 ;
      RECT 173.8 4 174 4.2 ;
      RECT 173.8 4.6 174 4.8 ;
      RECT 173.8 5.2 174 5.4 ;
      RECT 173.8 5.8 174 6 ;
      RECT 173.8 6.9 174 7.1 ;
      RECT 173.8 14.1 174 14.3 ;
      RECT 173.8 21.3 174 21.5 ;
      RECT 173.8 28.5 174 28.7 ;
      RECT 173.8 35.7 174 35.9 ;
      RECT 173.8 42.9 174 43.1 ;
      RECT 173.8 50.1 174 50.3 ;
      RECT 173.8 57.3 174 57.5 ;
      RECT 173.8 64.5 174 64.7 ;
      RECT 173.8 71.7 174 71.9 ;
      RECT 173.8 78.9 174 79.1 ;
      RECT 173.8 86.1 174 86.3 ;
      RECT 173.8 93.3 174 93.5 ;
      RECT 173.8 100.5 174 100.7 ;
      RECT 173.8 107.7 174 107.9 ;
      RECT 173.8 114.9 174 115.1 ;
      RECT 173.8 122.1 174 122.3 ;
      RECT 173.8 129.3 174 129.5 ;
      RECT 173.8 136.5 174 136.7 ;
      RECT 173.8 143.7 174 143.9 ;
      RECT 173.8 150.9 174 151.1 ;
      RECT 173.8 158.1 174 158.3 ;
      RECT 173.8 165.3 174 165.5 ;
      RECT 173.8 172.5 174 172.7 ;
      RECT 173.8 179.7 174 179.9 ;
      RECT 173.8 186.9 174 187.1 ;
      RECT 173.8 194.1 174 194.3 ;
      RECT 173.8 201.3 174 201.5 ;
      RECT 173.8 208.5 174 208.7 ;
      RECT 173.8 213.6 174 213.8 ;
      RECT 173.8 214.2 174 214.4 ;
      RECT 173.8 214.8 174 215 ;
      RECT 173.8 215.4 174 215.6 ;
      RECT 173.2 4 173.4 4.2 ;
      RECT 173.2 4.6 173.4 4.8 ;
      RECT 173.2 5.2 173.4 5.4 ;
      RECT 173.2 5.8 173.4 6 ;
      RECT 173.2 6.9 173.4 7.1 ;
      RECT 173.2 14.1 173.4 14.3 ;
      RECT 173.2 21.3 173.4 21.5 ;
      RECT 173.2 28.5 173.4 28.7 ;
      RECT 173.2 35.7 173.4 35.9 ;
      RECT 173.2 42.9 173.4 43.1 ;
      RECT 173.2 50.1 173.4 50.3 ;
      RECT 173.2 57.3 173.4 57.5 ;
      RECT 173.2 64.5 173.4 64.7 ;
      RECT 173.2 71.7 173.4 71.9 ;
      RECT 173.2 78.9 173.4 79.1 ;
      RECT 173.2 86.1 173.4 86.3 ;
      RECT 173.2 93.3 173.4 93.5 ;
      RECT 173.2 100.5 173.4 100.7 ;
      RECT 173.2 107.7 173.4 107.9 ;
      RECT 173.2 114.9 173.4 115.1 ;
      RECT 173.2 122.1 173.4 122.3 ;
      RECT 173.2 129.3 173.4 129.5 ;
      RECT 173.2 136.5 173.4 136.7 ;
      RECT 173.2 143.7 173.4 143.9 ;
      RECT 173.2 150.9 173.4 151.1 ;
      RECT 173.2 158.1 173.4 158.3 ;
      RECT 173.2 165.3 173.4 165.5 ;
      RECT 173.2 172.5 173.4 172.7 ;
      RECT 173.2 179.7 173.4 179.9 ;
      RECT 173.2 186.9 173.4 187.1 ;
      RECT 173.2 194.1 173.4 194.3 ;
      RECT 173.2 201.3 173.4 201.5 ;
      RECT 173.2 208.5 173.4 208.7 ;
      RECT 173.2 213.6 173.4 213.8 ;
      RECT 173.2 214.2 173.4 214.4 ;
      RECT 173.2 214.8 173.4 215 ;
      RECT 173.2 215.4 173.4 215.6 ;
      RECT 172.6 4 172.8 4.2 ;
      RECT 172.6 4.6 172.8 4.8 ;
      RECT 172.6 5.2 172.8 5.4 ;
      RECT 172.6 5.8 172.8 6 ;
      RECT 172.6 6.9 172.8 7.1 ;
      RECT 172.6 14.1 172.8 14.3 ;
      RECT 172.6 21.3 172.8 21.5 ;
      RECT 172.6 28.5 172.8 28.7 ;
      RECT 172.6 35.7 172.8 35.9 ;
      RECT 172.6 42.9 172.8 43.1 ;
      RECT 172.6 50.1 172.8 50.3 ;
      RECT 172.6 57.3 172.8 57.5 ;
      RECT 172.6 64.5 172.8 64.7 ;
      RECT 172.6 71.7 172.8 71.9 ;
      RECT 172.6 78.9 172.8 79.1 ;
      RECT 172.6 86.1 172.8 86.3 ;
      RECT 172.6 93.3 172.8 93.5 ;
      RECT 172.6 100.5 172.8 100.7 ;
      RECT 172.6 107.7 172.8 107.9 ;
      RECT 172.6 114.9 172.8 115.1 ;
      RECT 172.6 122.1 172.8 122.3 ;
      RECT 172.6 129.3 172.8 129.5 ;
      RECT 172.6 136.5 172.8 136.7 ;
      RECT 172.6 143.7 172.8 143.9 ;
      RECT 172.6 150.9 172.8 151.1 ;
      RECT 172.6 158.1 172.8 158.3 ;
      RECT 172.6 165.3 172.8 165.5 ;
      RECT 172.6 172.5 172.8 172.7 ;
      RECT 172.6 179.7 172.8 179.9 ;
      RECT 172.6 186.9 172.8 187.1 ;
      RECT 172.6 194.1 172.8 194.3 ;
      RECT 172.6 201.3 172.8 201.5 ;
      RECT 172.6 208.5 172.8 208.7 ;
      RECT 172.6 213.6 172.8 213.8 ;
      RECT 172.6 214.2 172.8 214.4 ;
      RECT 172.6 214.8 172.8 215 ;
      RECT 172.6 215.4 172.8 215.6 ;
      RECT 172 4 172.2 4.2 ;
      RECT 172 4.6 172.2 4.8 ;
      RECT 172 5.2 172.2 5.4 ;
      RECT 172 5.8 172.2 6 ;
      RECT 172 6.9 172.2 7.1 ;
      RECT 172 14.1 172.2 14.3 ;
      RECT 172 21.3 172.2 21.5 ;
      RECT 172 28.5 172.2 28.7 ;
      RECT 172 35.7 172.2 35.9 ;
      RECT 172 42.9 172.2 43.1 ;
      RECT 172 50.1 172.2 50.3 ;
      RECT 172 57.3 172.2 57.5 ;
      RECT 172 64.5 172.2 64.7 ;
      RECT 172 71.7 172.2 71.9 ;
      RECT 172 78.9 172.2 79.1 ;
      RECT 172 86.1 172.2 86.3 ;
      RECT 172 93.3 172.2 93.5 ;
      RECT 172 100.5 172.2 100.7 ;
      RECT 172 107.7 172.2 107.9 ;
      RECT 172 114.9 172.2 115.1 ;
      RECT 172 122.1 172.2 122.3 ;
      RECT 172 129.3 172.2 129.5 ;
      RECT 172 136.5 172.2 136.7 ;
      RECT 172 143.7 172.2 143.9 ;
      RECT 172 150.9 172.2 151.1 ;
      RECT 172 158.1 172.2 158.3 ;
      RECT 172 165.3 172.2 165.5 ;
      RECT 172 172.5 172.2 172.7 ;
      RECT 172 179.7 172.2 179.9 ;
      RECT 172 186.9 172.2 187.1 ;
      RECT 172 194.1 172.2 194.3 ;
      RECT 172 201.3 172.2 201.5 ;
      RECT 172 208.5 172.2 208.7 ;
      RECT 172 213.6 172.2 213.8 ;
      RECT 172 214.2 172.2 214.4 ;
      RECT 172 214.8 172.2 215 ;
      RECT 172 215.4 172.2 215.6 ;
      RECT 171.5 19.1 171.7 19.3 ;
      RECT 171.5 19.5 171.7 19.7 ;
      RECT 171.5 25.1 171.7 25.3 ;
      RECT 171.5 25.9 171.7 26.1 ;
      RECT 171.5 26.3 171.7 26.5 ;
      RECT 171.5 36.3 171.7 36.5 ;
      RECT 171.5 41.1 171.7 41.3 ;
      RECT 171.5 41.5 171.7 41.7 ;
      RECT 171.5 45.9 171.7 46.1 ;
      RECT 171.5 46.3 171.7 46.5 ;
      RECT 171.5 70.7 171.7 70.9 ;
      RECT 171.5 75.9 171.7 76.1 ;
      RECT 171.5 83.9 171.7 84.1 ;
      RECT 171.5 103.9 171.7 104.1 ;
      RECT 171.5 104.3 171.7 104.5 ;
      RECT 171.5 111.5 171.7 111.7 ;
      RECT 171.5 111.9 171.7 112.1 ;
      RECT 171.5 137.9 171.7 138.1 ;
      RECT 171.5 142.3 171.7 142.5 ;
      RECT 171.5 149.5 171.7 149.7 ;
      RECT 171.5 151.1 171.7 151.3 ;
      RECT 171.5 159.9 171.7 160.1 ;
      RECT 171.5 164.7 171.7 164.9 ;
      RECT 171.5 167.5 171.7 167.7 ;
      RECT 171.5 174.7 171.7 174.9 ;
      RECT 171.5 177.1 171.7 177.3 ;
      RECT 171.5 183.9 171.7 184.1 ;
      RECT 171.5 184.3 171.7 184.5 ;
      RECT 171.5 185.5 171.7 185.7 ;
      RECT 171.5 185.9 171.7 186.1 ;
      RECT 171.5 186.7 171.7 186.9 ;
      RECT 171.5 188.7 171.7 188.9 ;
      RECT 171.1 25.1 171.3 25.3 ;
      RECT 171.1 36.3 171.3 36.5 ;
      RECT 171.1 55.1 171.3 55.3 ;
      RECT 171.1 70.3 171.3 70.5 ;
      RECT 171.1 76.3 171.3 76.5 ;
      RECT 171.1 86.3 171.3 86.5 ;
      RECT 171.1 86.7 171.3 86.9 ;
      RECT 171.1 92.3 171.3 92.5 ;
      RECT 171.1 92.7 171.3 92.9 ;
      RECT 171.1 130.7 171.3 130.9 ;
      RECT 171.1 135.1 171.3 135.3 ;
      RECT 171.1 135.5 171.3 135.7 ;
      RECT 171.1 137.9 171.3 138.1 ;
      RECT 171.1 142.3 171.3 142.5 ;
      RECT 171.1 145.5 171.3 145.7 ;
      RECT 171.1 149.5 171.3 149.7 ;
      RECT 171.1 162.3 171.3 162.5 ;
      RECT 171.1 169.9 171.3 170.1 ;
      RECT 170.7 55.1 170.9 55.3 ;
      RECT 170.7 57.5 170.9 57.7 ;
      RECT 170.7 57.9 170.9 58.1 ;
      RECT 170.7 73.5 170.9 73.7 ;
      RECT 170.7 80.3 170.9 80.5 ;
      RECT 170.7 105.5 170.9 105.7 ;
      RECT 170.7 105.9 170.9 106.1 ;
      RECT 170.7 110.7 170.9 110.9 ;
      RECT 170.7 111.1 170.9 111.3 ;
      RECT 170.7 116.3 170.9 116.5 ;
      RECT 170.7 116.7 170.9 116.9 ;
      RECT 170.7 130.7 170.9 130.9 ;
      RECT 170.7 145.5 170.9 145.7 ;
      RECT 170.3 159.9 170.5 160.1 ;
      RECT 170.3 160.3 170.5 160.5 ;
      RECT 170.3 166.7 170.5 166.9 ;
      RECT 170.3 171.1 170.5 171.3 ;
      RECT 169.9 17.9 170.1 18.1 ;
      RECT 169.9 76.3 170.1 76.5 ;
      RECT 169.9 77.9 170.1 78.1 ;
      RECT 169.9 81.9 170.1 82.1 ;
      RECT 169.9 145.9 170.1 146.1 ;
      RECT 169.9 146.3 170.1 146.5 ;
      RECT 169.9 166.7 170.1 166.9 ;
      RECT 169.9 171.1 170.1 171.3 ;
      RECT 169.5 17.9 169.7 18.1 ;
      RECT 169.5 21.5 169.7 21.7 ;
      RECT 169.5 21.9 169.7 22.1 ;
      RECT 169.5 36.7 169.7 36.9 ;
      RECT 169.5 37.1 169.7 37.3 ;
      RECT 169.5 41.5 169.7 41.7 ;
      RECT 169.5 41.9 169.7 42.1 ;
      RECT 169.5 43.5 169.7 43.7 ;
      RECT 169.5 43.9 169.7 44.1 ;
      RECT 169.5 46.3 169.7 46.5 ;
      RECT 169.5 46.7 169.7 46.9 ;
      RECT 169.5 55.9 169.7 56.1 ;
      RECT 169.5 56.3 169.7 56.5 ;
      RECT 169.5 59.1 169.7 59.3 ;
      RECT 169.5 59.5 169.7 59.7 ;
      RECT 169.5 67.9 169.7 68.1 ;
      RECT 169.5 68.3 169.7 68.5 ;
      RECT 169.1 61.5 169.3 61.7 ;
      RECT 169.1 61.9 169.3 62.1 ;
      RECT 169.1 100.7 169.3 100.9 ;
      RECT 169.1 101.1 169.3 101.3 ;
      RECT 169.1 144.3 169.3 144.5 ;
      RECT 169.1 151.1 169.3 151.3 ;
      RECT 169.1 167.9 169.3 168.1 ;
      RECT 168.7 72.7 168.9 72.9 ;
      RECT 168.7 151.5 168.9 151.7 ;
      RECT 168.7 155.1 168.9 155.3 ;
      RECT 168.3 72.7 168.5 72.9 ;
      RECT 168.3 80.7 168.5 80.9 ;
      RECT 168.3 81.1 168.5 81.3 ;
      RECT 168.3 141.1 168.5 141.3 ;
      RECT 168.3 141.5 168.5 141.7 ;
      RECT 168.3 142.7 168.5 142.9 ;
      RECT 168.3 143.1 168.5 143.3 ;
      RECT 168.3 146.3 168.5 146.5 ;
      RECT 168.3 151.5 168.5 151.7 ;
      RECT 168.3 155.1 168.5 155.3 ;
      RECT 167.9 91.9 168.1 92.1 ;
      RECT 167.9 97.1 168.1 97.3 ;
      RECT 167.5 37.5 167.7 37.7 ;
      RECT 167.5 83.9 167.7 84.1 ;
      RECT 167.5 92.7 167.7 92.9 ;
      RECT 167.5 97.9 167.7 98.1 ;
      RECT 167.5 98.3 167.7 98.5 ;
      RECT 167.5 165.5 167.7 165.7 ;
      RECT 167.5 165.9 167.7 166.1 ;
      RECT 167.5 180.7 167.7 180.9 ;
      RECT 167.5 181.1 167.7 181.3 ;
      RECT 167.1 37.5 167.3 37.7 ;
      RECT 167.1 67.9 167.3 68.1 ;
      RECT 167.1 68.3 167.3 68.5 ;
      RECT 167.1 83.9 167.3 84.1 ;
      RECT 167.1 99.9 167.3 100.1 ;
      RECT 167.1 100.3 167.3 100.5 ;
      RECT 167.1 137.9 167.3 138.1 ;
      RECT 167.1 159.9 167.3 160.1 ;
      RECT 167.1 160.3 167.3 160.5 ;
      RECT 166.7 137.9 166.9 138.1 ;
      RECT 166.3 61.9 166.5 62.1 ;
      RECT 166.3 62.3 166.5 62.5 ;
      RECT 166.3 64.3 166.5 64.5 ;
      RECT 166.3 64.7 166.5 64.9 ;
      RECT 166.3 129.1 166.5 129.3 ;
      RECT 166.3 129.9 166.5 130.1 ;
      RECT 166.3 147.1 166.5 147.3 ;
      RECT 166.3 147.5 166.5 147.7 ;
      RECT 166.3 148.7 166.5 148.9 ;
      RECT 166.3 149.1 166.5 149.3 ;
      RECT 166.3 169.5 166.5 169.7 ;
      RECT 166.3 179.5 166.5 179.7 ;
      RECT 166.3 179.9 166.5 180.1 ;
      RECT 166.3 190.7 166.5 190.9 ;
      RECT 166.3 191.1 166.5 191.3 ;
      RECT 166.3 197.5 166.5 197.7 ;
      RECT 166.3 197.9 166.5 198.1 ;
      RECT 166.3 204.7 166.5 204.9 ;
      RECT 166.3 205.1 166.5 205.3 ;
      RECT 165.9 15.5 166.1 15.7 ;
      RECT 165.9 15.9 166.1 16.1 ;
      RECT 165.9 29.9 166.1 30.1 ;
      RECT 165.9 30.3 166.1 30.5 ;
      RECT 165.9 35.1 166.1 35.3 ;
      RECT 165.9 35.5 166.1 35.7 ;
      RECT 165.9 37.9 166.1 38.1 ;
      RECT 165.9 38.3 166.1 38.5 ;
      RECT 165.9 68.3 166.1 68.5 ;
      RECT 165.9 68.7 166.1 68.9 ;
      RECT 165.9 113.5 166.1 113.7 ;
      RECT 165.9 113.9 166.1 114.1 ;
      RECT 165.9 163.1 166.1 163.3 ;
      RECT 165.9 163.5 166.1 163.7 ;
      RECT 165.9 169.5 166.1 169.7 ;
      RECT 165.9 207.5 166.1 207.7 ;
      RECT 165.5 133.5 165.7 133.7 ;
      RECT 165.5 139.9 165.7 140.1 ;
      RECT 165.5 163.9 165.7 164.1 ;
      RECT 165.5 164.3 165.7 164.5 ;
      RECT 165.5 166.7 165.7 166.9 ;
      RECT 165.5 191.5 165.7 191.7 ;
      RECT 165.5 191.9 165.7 192.1 ;
      RECT 165.5 198.3 165.7 198.5 ;
      RECT 165.5 198.7 165.7 198.9 ;
      RECT 165.5 207.5 165.7 207.7 ;
      RECT 165.1 17.9 165.3 18.1 ;
      RECT 165.1 18.3 165.3 18.5 ;
      RECT 165.1 66.7 165.3 66.9 ;
      RECT 165.1 67.1 165.3 67.3 ;
      RECT 165.1 166.7 165.3 166.9 ;
      RECT 164.7 79.5 164.9 79.7 ;
      RECT 164.7 138.3 164.9 138.5 ;
      RECT 164.7 138.7 164.9 138.9 ;
      RECT 164.3 113.1 164.5 113.3 ;
      RECT 164.3 115.1 164.5 115.3 ;
      RECT 164.3 156.3 164.5 156.5 ;
      RECT 164.3 187.1 164.5 187.3 ;
      RECT 163.9 36.7 164.1 36.9 ;
      RECT 163.9 37.1 164.1 37.3 ;
      RECT 163.9 42.3 164.1 42.5 ;
      RECT 163.9 42.7 164.1 42.9 ;
      RECT 163.9 49.5 164.1 49.7 ;
      RECT 163.9 49.9 164.1 50.1 ;
      RECT 163.9 52.7 164.1 52.9 ;
      RECT 163.9 53.1 164.1 53.3 ;
      RECT 163.9 190.3 164.1 190.5 ;
      RECT 163.9 190.7 164.1 190.9 ;
      RECT 163.9 194.7 164.1 194.9 ;
      RECT 163.9 195.1 164.1 195.3 ;
      RECT 163.5 75.5 163.7 75.7 ;
      RECT 163.5 75.9 163.7 76.1 ;
      RECT 163.5 112.7 163.7 112.9 ;
      RECT 163.5 113.1 163.7 113.3 ;
      RECT 163.5 135.1 163.7 135.3 ;
      RECT 163.5 135.5 163.7 135.7 ;
      RECT 163.5 157.1 163.7 157.3 ;
      RECT 163.5 157.5 163.7 157.7 ;
      RECT 163.1 86.3 163.3 86.5 ;
      RECT 163.1 89.1 163.3 89.3 ;
      RECT 163.1 120.3 163.3 120.5 ;
      RECT 163.1 136.7 163.3 136.9 ;
      RECT 162.7 86.3 162.9 86.5 ;
      RECT 162.7 89.1 162.9 89.3 ;
      RECT 162.7 115.5 162.9 115.7 ;
      RECT 162.7 115.9 162.9 116.1 ;
      RECT 162.7 120.7 162.9 120.9 ;
      RECT 162.7 121.1 162.9 121.3 ;
      RECT 162.7 123.5 162.9 123.7 ;
      RECT 162.7 123.9 162.9 124.1 ;
      RECT 162.7 127.5 162.9 127.7 ;
      RECT 162.7 127.9 162.9 128.1 ;
      RECT 162.7 175.9 162.9 176.1 ;
      RECT 162.7 176.3 162.9 176.5 ;
      RECT 162.7 177.9 162.9 178.1 ;
      RECT 162.7 178.3 162.9 178.5 ;
      RECT 162.7 179.1 162.9 179.3 ;
      RECT 162.7 179.5 162.9 179.7 ;
      RECT 162.7 197.1 162.9 197.3 ;
      RECT 162.7 197.5 162.9 197.7 ;
      RECT 162.3 44.3 162.5 44.5 ;
      RECT 162.3 58.7 162.5 58.9 ;
      RECT 162.3 73.1 162.5 73.3 ;
      RECT 162.3 89.5 162.5 89.7 ;
      RECT 162.3 90.7 162.5 90.9 ;
      RECT 162.3 91.1 162.5 91.3 ;
      RECT 162.3 105.5 162.5 105.7 ;
      RECT 162.3 105.9 162.5 106.1 ;
      RECT 162.3 130.3 162.5 130.5 ;
      RECT 162.3 130.7 162.5 130.9 ;
      RECT 162.3 158.7 162.5 158.9 ;
      RECT 162.3 159.1 162.5 159.3 ;
      RECT 162.3 182.7 162.5 182.9 ;
      RECT 162.3 183.1 162.5 183.3 ;
      RECT 162.3 195.5 162.5 195.7 ;
      RECT 162.3 199.9 162.5 200.1 ;
      RECT 162.3 202.7 162.5 202.9 ;
      RECT 162.3 209.9 162.5 210.1 ;
      RECT 161.9 44.3 162.1 44.5 ;
      RECT 161.9 55.9 162.1 56.1 ;
      RECT 161.9 56.3 162.1 56.5 ;
      RECT 161.9 58.7 162.1 58.9 ;
      RECT 161.9 63.1 162.1 63.3 ;
      RECT 161.9 70.3 162.1 70.5 ;
      RECT 161.9 73.1 162.1 73.3 ;
      RECT 161.9 75.1 162.1 75.3 ;
      RECT 161.9 75.5 162.1 75.7 ;
      RECT 161.9 85.1 162.1 85.3 ;
      RECT 161.9 85.5 162.1 85.7 ;
      RECT 161.9 89.5 162.1 89.7 ;
      RECT 161.9 91.5 162.1 91.7 ;
      RECT 161.9 91.9 162.1 92.1 ;
      RECT 161.9 102.3 162.1 102.5 ;
      RECT 161.9 143.1 162.1 143.3 ;
      RECT 161.9 143.5 162.1 143.7 ;
      RECT 161.9 154.3 162.1 154.5 ;
      RECT 161.9 158.3 162.1 158.5 ;
      RECT 161.9 163.5 162.1 163.7 ;
      RECT 161.9 179.5 162.1 179.7 ;
      RECT 161.9 179.9 162.1 180.1 ;
      RECT 161.9 180.7 162.1 180.9 ;
      RECT 161.9 181.1 162.1 181.3 ;
      RECT 161.9 185.9 162.1 186.1 ;
      RECT 161.9 188.3 162.1 188.5 ;
      RECT 161.9 188.7 162.1 188.9 ;
      RECT 161.9 195.5 162.1 195.7 ;
      RECT 161.9 199.9 162.1 200.1 ;
      RECT 161.9 202.7 162.1 202.9 ;
      RECT 161.9 209.9 162.1 210.1 ;
      RECT 161.5 63.1 161.7 63.3 ;
      RECT 161.5 70.3 161.7 70.5 ;
      RECT 161.5 120.3 161.7 120.5 ;
      RECT 161.5 155.5 161.7 155.7 ;
      RECT 161.5 155.9 161.7 156.1 ;
      RECT 161.5 183.5 161.7 183.7 ;
      RECT 161.5 183.9 161.7 184.1 ;
      RECT 161.5 185.9 161.7 186.1 ;
      RECT 161.5 193.9 161.7 194.1 ;
      RECT 161.5 194.3 161.7 194.5 ;
      RECT 161.1 69.5 161.3 69.7 ;
      RECT 161.1 69.9 161.3 70.1 ;
      RECT 161.1 117.5 161.3 117.7 ;
      RECT 161.1 121.5 161.3 121.7 ;
      RECT 161.1 122.3 161.3 122.5 ;
      RECT 161.1 167.9 161.3 168.1 ;
      RECT 161.1 168.3 161.3 168.5 ;
      RECT 161.1 179.9 161.3 180.1 ;
      RECT 161.1 180.3 161.3 180.5 ;
      RECT 161.1 204.7 161.3 204.9 ;
      RECT 161.1 205.1 161.3 205.3 ;
      RECT 161.1 207.5 161.3 207.7 ;
      RECT 161.1 207.9 161.3 208.1 ;
      RECT 160.7 81.5 160.9 81.7 ;
      RECT 160.7 89.5 160.9 89.7 ;
      RECT 160.7 105.1 160.9 105.3 ;
      RECT 160.7 117.5 160.9 117.7 ;
      RECT 160.7 119.5 160.9 119.7 ;
      RECT 160.7 173.1 160.9 173.3 ;
      RECT 160.7 173.5 160.9 173.7 ;
      RECT 160.7 177.9 160.9 178.1 ;
      RECT 160.7 178.3 160.9 178.5 ;
      RECT 160.7 201.5 160.9 201.7 ;
      RECT 160.7 201.9 160.9 202.1 ;
      RECT 160.3 17.9 160.5 18.1 ;
      RECT 160.3 18.3 160.5 18.5 ;
      RECT 160.3 23.5 160.5 23.7 ;
      RECT 160.3 23.9 160.5 24.1 ;
      RECT 160.3 44.3 160.5 44.5 ;
      RECT 160.3 70.3 160.5 70.5 ;
      RECT 160.3 70.7 160.5 70.9 ;
      RECT 160.3 73.5 160.5 73.7 ;
      RECT 160.3 73.9 160.5 74.1 ;
      RECT 160.3 78.7 160.5 78.9 ;
      RECT 160.3 79.1 160.5 79.3 ;
      RECT 160.3 81.5 160.5 81.7 ;
      RECT 160.3 89.5 160.5 89.7 ;
      RECT 160.3 97.9 160.5 98.1 ;
      RECT 160.3 98.3 160.5 98.5 ;
      RECT 160.3 105.1 160.5 105.3 ;
      RECT 160.3 121.5 160.5 121.7 ;
      RECT 160.3 122.3 160.5 122.5 ;
      RECT 160.3 129.1 160.5 129.3 ;
      RECT 160.3 129.9 160.5 130.1 ;
      RECT 160.3 203.1 160.5 203.3 ;
      RECT 160.3 203.5 160.5 203.7 ;
      RECT 160.3 204.7 160.5 204.9 ;
      RECT 160.3 205.1 160.5 205.3 ;
      RECT 159.9 37.1 160.1 37.3 ;
      RECT 159.9 44.3 160.1 44.5 ;
      RECT 159.9 103.9 160.1 104.1 ;
      RECT 159.9 104.3 160.1 104.5 ;
      RECT 159.9 130.3 160.1 130.5 ;
      RECT 159.9 130.7 160.1 130.9 ;
      RECT 159.9 159.1 160.1 159.3 ;
      RECT 159.9 162.7 160.1 162.9 ;
      RECT 159.9 177.5 160.1 177.7 ;
      RECT 159.9 196.7 160.1 196.9 ;
      RECT 159.9 197.1 160.1 197.3 ;
      RECT 159.9 203.9 160.1 204.1 ;
      RECT 159.5 28.7 159.7 28.9 ;
      RECT 159.5 37.1 159.7 37.3 ;
      RECT 159.5 137.5 159.7 137.7 ;
      RECT 159.5 159.1 159.7 159.3 ;
      RECT 159.5 203.9 159.7 204.1 ;
      RECT 159.5 205.5 159.7 205.7 ;
      RECT 159.1 28.7 159.3 28.9 ;
      RECT 159.1 36.3 159.3 36.5 ;
      RECT 159.1 36.7 159.3 36.9 ;
      RECT 159.1 72.7 159.3 72.9 ;
      RECT 159.1 73.1 159.3 73.3 ;
      RECT 159.1 112.7 159.3 112.9 ;
      RECT 159.1 113.1 159.3 113.3 ;
      RECT 159.1 162.3 159.3 162.5 ;
      RECT 159.1 162.7 159.3 162.9 ;
      RECT 159.1 177.9 159.3 178.1 ;
      RECT 159.1 178.3 159.3 178.5 ;
      RECT 159.1 204.7 159.3 204.9 ;
      RECT 158.7 37.1 158.9 37.3 ;
      RECT 158.7 40.7 158.9 40.9 ;
      RECT 158.7 49.1 158.9 49.3 ;
      RECT 158.7 49.5 158.9 49.7 ;
      RECT 158.7 163.1 158.9 163.3 ;
      RECT 158.3 17.5 158.5 17.7 ;
      RECT 158.3 25.5 158.5 25.7 ;
      RECT 158.3 29.9 158.5 30.1 ;
      RECT 158.3 37.1 158.5 37.3 ;
      RECT 158.3 73.5 158.5 73.7 ;
      RECT 158.3 91.5 158.5 91.7 ;
      RECT 158.3 96.7 158.5 96.9 ;
      RECT 158.3 97.1 158.5 97.3 ;
      RECT 158.3 139.5 158.5 139.7 ;
      RECT 158.3 142.3 158.5 142.5 ;
      RECT 158.3 145.1 158.5 145.3 ;
      RECT 158.3 193.9 158.5 194.1 ;
      RECT 157.9 29.9 158.1 30.1 ;
      RECT 157.9 75.1 158.1 75.3 ;
      RECT 157.9 85.9 158.1 86.1 ;
      RECT 157.9 107.9 158.1 108.1 ;
      RECT 157.9 108.3 158.1 108.5 ;
      RECT 157.9 109.9 158.1 110.1 ;
      RECT 157.9 126.3 158.1 126.5 ;
      RECT 157.9 126.7 158.1 126.9 ;
      RECT 157.9 142.3 158.1 142.5 ;
      RECT 157.9 145.1 158.1 145.3 ;
      RECT 157.9 166.7 158.1 166.9 ;
      RECT 157.9 173.9 158.1 174.1 ;
      RECT 157.9 178.3 158.1 178.5 ;
      RECT 157.9 181.1 158.1 181.3 ;
      RECT 157.9 185.5 158.1 185.7 ;
      RECT 157.9 188.3 158.1 188.5 ;
      RECT 157.9 193.1 158.1 193.3 ;
      RECT 157.9 193.5 158.1 193.7 ;
      RECT 157.9 199.9 158.1 200.1 ;
      RECT 157.5 24.7 157.7 24.9 ;
      RECT 157.5 67.5 157.7 67.7 ;
      RECT 157.5 86.3 157.7 86.5 ;
      RECT 157.5 86.7 157.7 86.9 ;
      RECT 157.5 105.5 157.7 105.7 ;
      RECT 157.5 105.9 157.7 106.1 ;
      RECT 157.5 109.9 157.7 110.1 ;
      RECT 157.5 114.7 157.7 114.9 ;
      RECT 157.5 120.3 157.7 120.5 ;
      RECT 157.5 166.7 157.7 166.9 ;
      RECT 157.5 173.9 157.7 174.1 ;
      RECT 157.5 178.3 157.7 178.5 ;
      RECT 157.5 181.1 157.7 181.3 ;
      RECT 157.5 185.5 157.7 185.7 ;
      RECT 157.5 188.3 157.7 188.5 ;
      RECT 157.5 192.3 157.7 192.5 ;
      RECT 157.5 192.7 157.7 192.9 ;
      RECT 157.5 193.9 157.7 194.1 ;
      RECT 157.5 198.3 157.7 198.5 ;
      RECT 157.5 198.7 157.7 198.9 ;
      RECT 157.5 199.9 157.7 200.1 ;
      RECT 157.5 206.7 157.7 206.9 ;
      RECT 157.1 24.7 157.3 24.9 ;
      RECT 157.1 26.3 157.3 26.5 ;
      RECT 157.1 27.1 157.3 27.3 ;
      RECT 157.1 27.9 157.3 28.1 ;
      RECT 157.1 193.1 157.3 193.3 ;
      RECT 157.1 203.1 157.3 203.3 ;
      RECT 157.1 203.5 157.3 203.7 ;
      RECT 157.1 206.7 157.3 206.9 ;
      RECT 157.1 207.9 157.3 208.1 ;
      RECT 157.1 208.3 157.3 208.5 ;
      RECT 156.7 26.3 156.9 26.5 ;
      RECT 156.7 27.1 156.9 27.3 ;
      RECT 156.7 27.9 156.9 28.1 ;
      RECT 156.7 120.7 156.9 120.9 ;
      RECT 156.7 144.3 156.9 144.5 ;
      RECT 156.7 172.3 156.9 172.5 ;
      RECT 156.7 172.7 156.9 172.9 ;
      RECT 156.7 190.3 156.9 190.5 ;
      RECT 156.7 190.7 156.9 190.9 ;
      RECT 156.7 193.1 156.9 193.3 ;
      RECT 156.7 193.9 156.9 194.1 ;
      RECT 156.7 194.3 156.9 194.5 ;
      RECT 156.7 198.7 156.9 198.9 ;
      RECT 156.7 199.1 156.9 199.3 ;
      RECT 156.7 201.9 156.9 202.1 ;
      RECT 156.7 202.3 156.9 202.5 ;
      RECT 156.3 30.3 156.5 30.5 ;
      RECT 156.3 30.7 156.5 30.9 ;
      RECT 156.3 33.1 156.5 33.3 ;
      RECT 156.3 50.3 156.5 50.5 ;
      RECT 156.3 173.5 156.5 173.7 ;
      RECT 156.3 173.9 156.5 174.1 ;
      RECT 156.3 197.1 156.5 197.3 ;
      RECT 156.3 197.5 156.5 197.7 ;
      RECT 156.3 206.3 156.5 206.5 ;
      RECT 156.3 206.7 156.5 206.9 ;
      RECT 155.9 23.5 156.1 23.7 ;
      RECT 155.9 23.9 156.1 24.1 ;
      RECT 155.9 33.9 156.1 34.1 ;
      RECT 155.9 34.3 156.1 34.5 ;
      RECT 155.9 43.5 156.1 43.7 ;
      RECT 155.9 43.9 156.1 44.1 ;
      RECT 155.9 50.3 156.1 50.5 ;
      RECT 155.9 57.9 156.1 58.1 ;
      RECT 155.9 58.3 156.1 58.5 ;
      RECT 155.9 139.5 156.1 139.7 ;
      RECT 155.9 182.7 156.1 182.9 ;
      RECT 155.9 183.1 156.1 183.3 ;
      RECT 155.9 189.1 156.1 189.3 ;
      RECT 155.9 189.5 156.1 189.7 ;
      RECT 155.9 197.9 156.1 198.1 ;
      RECT 155.9 198.3 156.1 198.5 ;
      RECT 155.5 26.3 155.7 26.5 ;
      RECT 155.5 29.5 155.7 29.7 ;
      RECT 155.5 66.7 155.7 66.9 ;
      RECT 155.5 67.1 155.7 67.3 ;
      RECT 155.5 111.5 155.7 111.7 ;
      RECT 155.5 111.9 155.7 112.1 ;
      RECT 155.5 163.9 155.7 164.1 ;
      RECT 155.5 164.3 155.7 164.5 ;
      RECT 155.5 169.9 155.7 170.1 ;
      RECT 155.5 170.3 155.7 170.5 ;
      RECT 155.5 173.9 155.7 174.1 ;
      RECT 155.5 174.3 155.7 174.5 ;
      RECT 155.1 23.5 155.3 23.7 ;
      RECT 155.1 23.9 155.3 24.1 ;
      RECT 155.1 26.3 155.3 26.5 ;
      RECT 155.1 29.5 155.3 29.7 ;
      RECT 155.1 50.7 155.3 50.9 ;
      RECT 155.1 51.1 155.3 51.3 ;
      RECT 155.1 110.3 155.3 110.5 ;
      RECT 155.1 116.7 155.3 116.9 ;
      RECT 155.1 138.3 155.3 138.5 ;
      RECT 155.1 152.7 155.3 152.9 ;
      RECT 155.1 165.5 155.3 165.7 ;
      RECT 155.1 190.3 155.3 190.5 ;
      RECT 154.7 96.3 154.9 96.5 ;
      RECT 154.7 98.3 154.9 98.5 ;
      RECT 154.7 110.3 154.9 110.5 ;
      RECT 154.7 116.7 154.9 116.9 ;
      RECT 154.7 121.5 154.9 121.7 ;
      RECT 154.7 137.5 154.9 137.7 ;
      RECT 154.7 170.7 154.9 170.9 ;
      RECT 154.7 177.1 154.9 177.3 ;
      RECT 154.7 195.5 154.9 195.7 ;
      RECT 154.7 209.9 154.9 210.1 ;
      RECT 154.7 210.3 154.9 210.5 ;
      RECT 154.3 21.1 154.5 21.3 ;
      RECT 154.3 28.7 154.5 28.9 ;
      RECT 154.3 30.3 154.5 30.5 ;
      RECT 154.3 31.5 154.5 31.7 ;
      RECT 154.3 39.1 154.5 39.3 ;
      RECT 154.3 115.1 154.5 115.3 ;
      RECT 154.3 120.3 154.5 120.5 ;
      RECT 154.3 171.9 154.5 172.1 ;
      RECT 154.3 189.5 154.5 189.7 ;
      RECT 153.9 41.5 154.1 41.7 ;
      RECT 153.9 50.7 154.1 50.9 ;
      RECT 153.9 51.1 154.1 51.3 ;
      RECT 153.9 71.9 154.1 72.1 ;
      RECT 153.9 72.3 154.1 72.5 ;
      RECT 153.9 136.3 154.1 136.5 ;
      RECT 153.9 138.7 154.1 138.9 ;
      RECT 153.9 160.7 154.1 160.9 ;
      RECT 153.9 161.1 154.1 161.3 ;
      RECT 153.5 17.1 153.7 17.3 ;
      RECT 153.5 17.5 153.7 17.7 ;
      RECT 153.5 19.9 153.7 20.1 ;
      RECT 153.5 20.3 153.7 20.5 ;
      RECT 153.5 40.7 153.7 40.9 ;
      RECT 153.5 41.5 153.7 41.7 ;
      RECT 153.5 45.1 153.7 45.3 ;
      RECT 153.5 45.5 153.7 45.7 ;
      RECT 153.5 167.1 153.7 167.3 ;
      RECT 153.5 167.5 153.7 167.7 ;
      RECT 153.5 199.9 153.7 200.1 ;
      RECT 153.5 200.3 153.7 200.5 ;
      RECT 153.1 55.9 153.3 56.1 ;
      RECT 153.1 67.1 153.3 67.3 ;
      RECT 153.1 70.3 153.3 70.5 ;
      RECT 153.1 86.7 153.3 86.9 ;
      RECT 153.1 87.1 153.3 87.3 ;
      RECT 153.1 119.1 153.3 119.3 ;
      RECT 152.7 27.5 152.9 27.7 ;
      RECT 152.7 27.9 152.9 28.1 ;
      RECT 152.7 33.1 152.9 33.3 ;
      RECT 152.7 33.5 152.9 33.7 ;
      RECT 152.7 68.3 152.9 68.5 ;
      RECT 152.7 68.7 152.9 68.9 ;
      RECT 152.7 69.5 152.9 69.7 ;
      RECT 152.7 69.9 152.9 70.1 ;
      RECT 152.7 79.1 152.9 79.3 ;
      RECT 152.7 79.5 152.9 79.7 ;
      RECT 152.7 82.3 152.9 82.5 ;
      RECT 152.7 82.7 152.9 82.9 ;
      RECT 152.7 97.9 152.9 98.1 ;
      RECT 152.7 122.7 152.9 122.9 ;
      RECT 152.7 123.1 152.9 123.3 ;
      RECT 152.7 161.5 152.9 161.7 ;
      RECT 152.7 161.9 152.9 162.1 ;
      RECT 152.7 170.3 152.9 170.5 ;
      RECT 152.7 170.7 152.9 170.9 ;
      RECT 152.7 173.5 152.9 173.7 ;
      RECT 152.7 173.9 152.9 174.1 ;
      RECT 152.3 51.5 152.5 51.7 ;
      RECT 152.3 97.9 152.5 98.1 ;
      RECT 152.3 99.5 152.5 99.7 ;
      RECT 152.3 99.9 152.5 100.1 ;
      RECT 152.3 102.3 152.5 102.5 ;
      RECT 152.3 102.7 152.5 102.9 ;
      RECT 151.9 46.7 152.1 46.9 ;
      RECT 151.9 47.1 152.1 47.3 ;
      RECT 151.9 51.5 152.1 51.7 ;
      RECT 151.9 94.7 152.1 94.9 ;
      RECT 151.9 99.1 152.1 99.3 ;
      RECT 151.9 101.9 152.1 102.1 ;
      RECT 151.9 106.3 152.1 106.5 ;
      RECT 151.9 113.5 152.1 113.7 ;
      RECT 151.9 123.5 152.1 123.7 ;
      RECT 151.9 130.7 152.1 130.9 ;
      RECT 151.9 135.1 152.1 135.3 ;
      RECT 151.9 142.3 152.1 142.5 ;
      RECT 151.9 149.5 152.1 149.7 ;
      RECT 151.9 194.7 152.1 194.9 ;
      RECT 151.5 79.9 151.7 80.1 ;
      RECT 151.5 91.9 151.7 92.1 ;
      RECT 151.5 94.7 151.7 94.9 ;
      RECT 151.5 99.1 151.7 99.3 ;
      RECT 151.5 101.9 151.7 102.1 ;
      RECT 151.5 106.3 151.7 106.5 ;
      RECT 151.5 113.5 151.7 113.7 ;
      RECT 151.5 123.5 151.7 123.7 ;
      RECT 151.5 130.7 151.7 130.9 ;
      RECT 151.5 135.1 151.7 135.3 ;
      RECT 151.5 137.9 151.7 138.1 ;
      RECT 151.5 138.3 151.7 138.5 ;
      RECT 151.5 142.3 151.7 142.5 ;
      RECT 151.5 149.5 151.7 149.7 ;
      RECT 151.5 157.9 151.7 158.1 ;
      RECT 151.5 158.3 151.7 158.5 ;
      RECT 151.5 184.7 151.7 184.9 ;
      RECT 151.5 185.1 151.7 185.3 ;
      RECT 151.5 194.7 151.7 194.9 ;
      RECT 151.1 73.1 151.3 73.3 ;
      RECT 151.1 79.9 151.3 80.1 ;
      RECT 151.1 81.5 151.3 81.7 ;
      RECT 151.1 91.9 151.3 92.1 ;
      RECT 150.7 73.1 150.9 73.3 ;
      RECT 150.7 81.5 150.9 81.7 ;
      RECT 150.7 90.7 150.9 90.9 ;
      RECT 150.7 91.1 150.9 91.3 ;
      RECT 150.7 109.9 150.9 110.1 ;
      RECT 150.7 110.3 150.9 110.5 ;
      RECT 150.7 125.5 150.9 125.7 ;
      RECT 150.7 125.9 150.9 126.1 ;
      RECT 150.7 145.9 150.9 146.1 ;
      RECT 150.7 146.3 150.9 146.5 ;
      RECT 150.7 157.5 150.9 157.7 ;
      RECT 150.7 157.9 150.9 158.1 ;
      RECT 150.7 168.7 150.9 168.9 ;
      RECT 150.7 169.1 150.9 169.3 ;
      RECT 150.3 41.1 150.5 41.3 ;
      RECT 150.3 199.9 150.5 200.1 ;
      RECT 150.3 202.7 150.5 202.9 ;
      RECT 150.3 206.7 150.5 206.9 ;
      RECT 150.3 210.7 150.5 210.9 ;
      RECT 150.3 211.1 150.5 211.3 ;
      RECT 150.3 211.9 150.5 212.1 ;
      RECT 150.3 212.3 150.5 212.5 ;
      RECT 149.9 49.1 150.1 49.3 ;
      RECT 149.9 123.5 150.1 123.7 ;
      RECT 149.9 129.5 150.1 129.7 ;
      RECT 149.9 147.5 150.1 147.7 ;
      RECT 149.9 163.5 150.1 163.7 ;
      RECT 149.9 163.9 150.1 164.1 ;
      RECT 149.9 199.9 150.1 200.1 ;
      RECT 149.9 202.7 150.1 202.9 ;
      RECT 149.9 206.7 150.1 206.9 ;
      RECT 149.5 15.5 149.7 15.7 ;
      RECT 149.5 34.7 149.7 34.9 ;
      RECT 149.5 35.1 149.7 35.3 ;
      RECT 149.5 37.1 149.7 37.3 ;
      RECT 149.5 43.5 149.7 43.7 ;
      RECT 149.5 49.1 149.7 49.3 ;
      RECT 149.5 70.3 149.7 70.5 ;
      RECT 149.5 70.7 149.7 70.9 ;
      RECT 149.5 73.9 149.7 74.1 ;
      RECT 149.5 84.7 149.7 84.9 ;
      RECT 149.5 89.1 149.7 89.3 ;
      RECT 149.5 157.1 149.7 157.3 ;
      RECT 149.5 157.5 149.7 157.7 ;
      RECT 149.5 164.3 149.7 164.5 ;
      RECT 149.5 164.7 149.7 164.9 ;
      RECT 149.5 170.7 149.7 170.9 ;
      RECT 149.5 171.5 149.7 171.7 ;
      RECT 149.5 171.9 149.7 172.1 ;
      RECT 149.5 176.3 149.7 176.5 ;
      RECT 149.5 176.7 149.7 176.9 ;
      RECT 149.1 12.7 149.3 12.9 ;
      RECT 149.1 15.5 149.3 15.7 ;
      RECT 149.1 37.1 149.3 37.3 ;
      RECT 149.1 43.5 149.3 43.7 ;
      RECT 149.1 73.9 149.3 74.1 ;
      RECT 149.1 77.5 149.3 77.7 ;
      RECT 149.1 77.9 149.3 78.1 ;
      RECT 149.1 84.7 149.3 84.9 ;
      RECT 149.1 89.1 149.3 89.3 ;
      RECT 149.1 124.3 149.3 124.5 ;
      RECT 149.1 139.5 149.3 139.7 ;
      RECT 149.1 154.3 149.3 154.5 ;
      RECT 149.1 154.7 149.3 154.9 ;
      RECT 149.1 161.9 149.3 162.1 ;
      RECT 149.1 162.3 149.3 162.5 ;
      RECT 149.1 170.7 149.3 170.9 ;
      RECT 149.1 175.9 149.3 176.1 ;
      RECT 149.1 179.9 149.3 180.1 ;
      RECT 148.7 12.7 148.9 12.9 ;
      RECT 148.7 17.5 148.9 17.7 ;
      RECT 148.7 45.9 148.9 46.1 ;
      RECT 148.7 46.3 148.9 46.5 ;
      RECT 148.7 51.9 148.9 52.1 ;
      RECT 148.7 52.3 148.9 52.5 ;
      RECT 148.7 52.7 148.9 52.9 ;
      RECT 148.7 53.1 148.9 53.3 ;
      RECT 148.7 75.5 148.9 75.7 ;
      RECT 148.7 75.9 148.9 76.1 ;
      RECT 148.7 81.5 148.9 81.7 ;
      RECT 148.7 93.9 148.9 94.1 ;
      RECT 148.7 94.3 148.9 94.5 ;
      RECT 148.7 109.9 148.9 110.1 ;
      RECT 148.7 110.3 148.9 110.5 ;
      RECT 148.7 126.3 148.9 126.5 ;
      RECT 148.7 134.7 148.9 134.9 ;
      RECT 148.7 137.9 148.9 138.1 ;
      RECT 148.7 163.5 148.9 163.7 ;
      RECT 148.7 168.7 148.9 168.9 ;
      RECT 148.7 173.5 148.9 173.7 ;
      RECT 148.7 178.7 148.9 178.9 ;
      RECT 148.3 11.5 148.5 11.7 ;
      RECT 148.3 11.9 148.5 12.1 ;
      RECT 148.3 17.5 148.5 17.7 ;
      RECT 148.3 33.5 148.5 33.7 ;
      RECT 148.3 33.9 148.5 34.1 ;
      RECT 148.3 43.9 148.5 44.1 ;
      RECT 148.3 44.3 148.5 44.5 ;
      RECT 148.3 81.5 148.5 81.7 ;
      RECT 148.3 90.7 148.5 90.9 ;
      RECT 148.3 91.1 148.5 91.3 ;
      RECT 148.3 175.1 148.5 175.3 ;
      RECT 148.3 177.9 148.5 178.1 ;
      RECT 148.3 197.5 148.5 197.7 ;
      RECT 148.3 197.9 148.5 198.1 ;
      RECT 148.3 198.7 148.5 198.9 ;
      RECT 148.3 199.1 148.5 199.3 ;
      RECT 147.8 1 148 1.2 ;
      RECT 147.8 1.6 148 1.8 ;
      RECT 147.8 2.2 148 2.4 ;
      RECT 147.8 2.8 148 3 ;
      RECT 147.8 10.5 148 10.7 ;
      RECT 147.8 17.7 148 17.9 ;
      RECT 147.8 24.9 148 25.1 ;
      RECT 147.8 32.1 148 32.3 ;
      RECT 147.8 39.3 148 39.5 ;
      RECT 147.8 46.5 148 46.7 ;
      RECT 147.8 53.7 148 53.9 ;
      RECT 147.8 60.9 148 61.1 ;
      RECT 147.8 68.1 148 68.3 ;
      RECT 147.8 75.3 148 75.5 ;
      RECT 147.8 82.5 148 82.7 ;
      RECT 147.8 89.7 148 89.9 ;
      RECT 147.8 96.9 148 97.1 ;
      RECT 147.8 104.1 148 104.3 ;
      RECT 147.8 111.3 148 111.5 ;
      RECT 147.8 118.5 148 118.7 ;
      RECT 147.8 125.7 148 125.9 ;
      RECT 147.8 132.9 148 133.1 ;
      RECT 147.8 140.1 148 140.3 ;
      RECT 147.8 147.3 148 147.5 ;
      RECT 147.8 154.5 148 154.7 ;
      RECT 147.8 161.7 148 161.9 ;
      RECT 147.8 168.9 148 169.1 ;
      RECT 147.8 176.1 148 176.3 ;
      RECT 147.8 183.3 148 183.5 ;
      RECT 147.8 190.5 148 190.7 ;
      RECT 147.8 197.7 148 197.9 ;
      RECT 147.8 204.9 148 205.1 ;
      RECT 147.8 212.1 148 212.3 ;
      RECT 147.8 216.6 148 216.8 ;
      RECT 147.8 217.2 148 217.4 ;
      RECT 147.8 217.8 148 218 ;
      RECT 147.8 218.4 148 218.6 ;
      RECT 147.2 1 147.4 1.2 ;
      RECT 147.2 1.6 147.4 1.8 ;
      RECT 147.2 2.2 147.4 2.4 ;
      RECT 147.2 2.8 147.4 3 ;
      RECT 147.2 10.5 147.4 10.7 ;
      RECT 147.2 17.7 147.4 17.9 ;
      RECT 147.2 24.9 147.4 25.1 ;
      RECT 147.2 32.1 147.4 32.3 ;
      RECT 147.2 39.3 147.4 39.5 ;
      RECT 147.2 46.5 147.4 46.7 ;
      RECT 147.2 53.7 147.4 53.9 ;
      RECT 147.2 60.9 147.4 61.1 ;
      RECT 147.2 68.1 147.4 68.3 ;
      RECT 147.2 75.3 147.4 75.5 ;
      RECT 147.2 82.5 147.4 82.7 ;
      RECT 147.2 89.7 147.4 89.9 ;
      RECT 147.2 96.9 147.4 97.1 ;
      RECT 147.2 104.1 147.4 104.3 ;
      RECT 147.2 111.3 147.4 111.5 ;
      RECT 147.2 118.5 147.4 118.7 ;
      RECT 147.2 125.7 147.4 125.9 ;
      RECT 147.2 132.9 147.4 133.1 ;
      RECT 147.2 140.1 147.4 140.3 ;
      RECT 147.2 147.3 147.4 147.5 ;
      RECT 147.2 154.5 147.4 154.7 ;
      RECT 147.2 161.7 147.4 161.9 ;
      RECT 147.2 168.9 147.4 169.1 ;
      RECT 147.2 176.1 147.4 176.3 ;
      RECT 147.2 183.3 147.4 183.5 ;
      RECT 147.2 190.5 147.4 190.7 ;
      RECT 147.2 197.7 147.4 197.9 ;
      RECT 147.2 204.9 147.4 205.1 ;
      RECT 147.2 212.1 147.4 212.3 ;
      RECT 147.2 216.6 147.4 216.8 ;
      RECT 147.2 217.2 147.4 217.4 ;
      RECT 147.2 217.8 147.4 218 ;
      RECT 147.2 218.4 147.4 218.6 ;
      RECT 146.6 1 146.8 1.2 ;
      RECT 146.6 1.6 146.8 1.8 ;
      RECT 146.6 2.2 146.8 2.4 ;
      RECT 146.6 2.8 146.8 3 ;
      RECT 146.6 10.5 146.8 10.7 ;
      RECT 146.6 17.7 146.8 17.9 ;
      RECT 146.6 24.9 146.8 25.1 ;
      RECT 146.6 32.1 146.8 32.3 ;
      RECT 146.6 39.3 146.8 39.5 ;
      RECT 146.6 46.5 146.8 46.7 ;
      RECT 146.6 53.7 146.8 53.9 ;
      RECT 146.6 60.9 146.8 61.1 ;
      RECT 146.6 68.1 146.8 68.3 ;
      RECT 146.6 75.3 146.8 75.5 ;
      RECT 146.6 82.5 146.8 82.7 ;
      RECT 146.6 89.7 146.8 89.9 ;
      RECT 146.6 96.9 146.8 97.1 ;
      RECT 146.6 104.1 146.8 104.3 ;
      RECT 146.6 111.3 146.8 111.5 ;
      RECT 146.6 118.5 146.8 118.7 ;
      RECT 146.6 125.7 146.8 125.9 ;
      RECT 146.6 132.9 146.8 133.1 ;
      RECT 146.6 140.1 146.8 140.3 ;
      RECT 146.6 147.3 146.8 147.5 ;
      RECT 146.6 154.5 146.8 154.7 ;
      RECT 146.6 161.7 146.8 161.9 ;
      RECT 146.6 168.9 146.8 169.1 ;
      RECT 146.6 176.1 146.8 176.3 ;
      RECT 146.6 183.3 146.8 183.5 ;
      RECT 146.6 190.5 146.8 190.7 ;
      RECT 146.6 197.7 146.8 197.9 ;
      RECT 146.6 204.9 146.8 205.1 ;
      RECT 146.6 212.1 146.8 212.3 ;
      RECT 146.6 216.6 146.8 216.8 ;
      RECT 146.6 217.2 146.8 217.4 ;
      RECT 146.6 217.8 146.8 218 ;
      RECT 146.6 218.4 146.8 218.6 ;
      RECT 146 1 146.2 1.2 ;
      RECT 146 1.6 146.2 1.8 ;
      RECT 146 2.2 146.2 2.4 ;
      RECT 146 2.8 146.2 3 ;
      RECT 146 10.5 146.2 10.7 ;
      RECT 146 17.7 146.2 17.9 ;
      RECT 146 24.9 146.2 25.1 ;
      RECT 146 32.1 146.2 32.3 ;
      RECT 146 39.3 146.2 39.5 ;
      RECT 146 46.5 146.2 46.7 ;
      RECT 146 53.7 146.2 53.9 ;
      RECT 146 60.9 146.2 61.1 ;
      RECT 146 68.1 146.2 68.3 ;
      RECT 146 75.3 146.2 75.5 ;
      RECT 146 82.5 146.2 82.7 ;
      RECT 146 89.7 146.2 89.9 ;
      RECT 146 96.9 146.2 97.1 ;
      RECT 146 104.1 146.2 104.3 ;
      RECT 146 111.3 146.2 111.5 ;
      RECT 146 118.5 146.2 118.7 ;
      RECT 146 125.7 146.2 125.9 ;
      RECT 146 132.9 146.2 133.1 ;
      RECT 146 140.1 146.2 140.3 ;
      RECT 146 147.3 146.2 147.5 ;
      RECT 146 154.5 146.2 154.7 ;
      RECT 146 161.7 146.2 161.9 ;
      RECT 146 168.9 146.2 169.1 ;
      RECT 146 176.1 146.2 176.3 ;
      RECT 146 183.3 146.2 183.5 ;
      RECT 146 190.5 146.2 190.7 ;
      RECT 146 197.7 146.2 197.9 ;
      RECT 146 204.9 146.2 205.1 ;
      RECT 146 212.1 146.2 212.3 ;
      RECT 146 216.6 146.2 216.8 ;
      RECT 146 217.2 146.2 217.4 ;
      RECT 146 217.8 146.2 218 ;
      RECT 146 218.4 146.2 218.6 ;
      RECT 145.5 16.7 145.7 16.9 ;
      RECT 145.5 17.1 145.7 17.3 ;
      RECT 145.5 19.9 145.7 20.1 ;
      RECT 145.5 20.3 145.7 20.5 ;
      RECT 145.5 21.9 145.7 22.1 ;
      RECT 145.5 22.3 145.7 22.5 ;
      RECT 145.5 29.5 145.7 29.7 ;
      RECT 145.5 29.9 145.7 30.1 ;
      RECT 145.5 35.1 145.7 35.3 ;
      RECT 145.5 35.5 145.7 35.7 ;
      RECT 145.5 39.5 145.7 39.7 ;
      RECT 145.5 39.9 145.7 40.1 ;
      RECT 145.5 40.7 145.7 40.9 ;
      RECT 145.5 41.5 145.7 41.7 ;
      RECT 145.5 41.9 145.7 42.1 ;
      RECT 145.5 43.9 145.7 44.1 ;
      RECT 145.5 44.3 145.7 44.5 ;
      RECT 145.5 45.1 145.7 45.3 ;
      RECT 145.5 45.5 145.7 45.7 ;
      RECT 145.5 49.9 145.7 50.1 ;
      RECT 145.5 50.3 145.7 50.5 ;
      RECT 145.5 58.7 145.7 58.9 ;
      RECT 145.5 65.9 145.7 66.1 ;
      RECT 145.5 70.3 145.7 70.5 ;
      RECT 145.5 79.9 145.7 80.1 ;
      RECT 145.5 93.5 145.7 93.7 ;
      RECT 145.5 119.5 145.7 119.7 ;
      RECT 145.5 125.1 145.7 125.3 ;
      RECT 145.5 125.5 145.7 125.7 ;
      RECT 145.5 130.7 145.7 130.9 ;
      RECT 145.5 131.1 145.7 131.3 ;
      RECT 145.5 135.1 145.7 135.3 ;
      RECT 145.5 159.1 145.7 159.3 ;
      RECT 145.5 159.5 145.7 159.7 ;
      RECT 145.5 177.5 145.7 177.7 ;
      RECT 145.5 177.9 145.7 178.1 ;
      RECT 145.1 29.5 145.3 29.7 ;
      RECT 145.1 29.9 145.3 30.1 ;
      RECT 145.1 40.7 145.3 40.9 ;
      RECT 145.1 44.7 145.3 44.9 ;
      RECT 145.1 51.5 145.3 51.7 ;
      RECT 145.1 51.9 145.3 52.1 ;
      RECT 145.1 55.9 145.3 56.1 ;
      RECT 145.1 58.7 145.3 58.9 ;
      RECT 145.1 65.9 145.3 66.1 ;
      RECT 145.1 70.3 145.3 70.5 ;
      RECT 145.1 75.5 145.3 75.7 ;
      RECT 145.1 75.9 145.3 76.1 ;
      RECT 145.1 79.9 145.3 80.1 ;
      RECT 145.1 93.5 145.3 93.7 ;
      RECT 145.1 119.5 145.3 119.7 ;
      RECT 145.1 135.1 145.3 135.3 ;
      RECT 145.1 135.9 145.3 136.1 ;
      RECT 145.1 144.7 145.3 144.9 ;
      RECT 145.1 146.3 145.3 146.5 ;
      RECT 145.1 147.5 145.3 147.7 ;
      RECT 145.1 174.7 145.3 174.9 ;
      RECT 145.1 219.1 145.3 219.3 ;
      RECT 144.7 19.1 144.9 19.3 ;
      RECT 144.7 37.9 144.9 38.1 ;
      RECT 144.7 42.7 144.9 42.9 ;
      RECT 144.7 43.1 144.9 43.3 ;
      RECT 144.7 44.7 144.9 44.9 ;
      RECT 144.7 48.3 144.9 48.5 ;
      RECT 144.7 55.9 144.9 56.1 ;
      RECT 144.7 62.7 144.9 62.9 ;
      RECT 144.7 63.1 144.9 63.3 ;
      RECT 144.7 112.7 144.9 112.9 ;
      RECT 144.7 113.1 144.9 113.3 ;
      RECT 144.7 121.9 144.9 122.1 ;
      RECT 144.7 122.3 144.9 122.5 ;
      RECT 144.7 127.5 144.9 127.7 ;
      RECT 144.7 127.9 144.9 128.1 ;
      RECT 144.7 175.1 144.9 175.3 ;
      RECT 144.7 176.7 144.9 176.9 ;
      RECT 144.7 192.7 144.9 192.9 ;
      RECT 144.7 195.5 144.9 195.7 ;
      RECT 144.3 14.3 144.5 14.5 ;
      RECT 144.3 16.3 144.5 16.5 ;
      RECT 144.3 19.9 144.5 20.1 ;
      RECT 144.3 22.7 144.5 22.9 ;
      RECT 144.3 33.9 144.5 34.1 ;
      RECT 144.3 37.9 144.5 38.1 ;
      RECT 144.3 41.9 144.5 42.1 ;
      RECT 144.3 42.3 144.5 42.5 ;
      RECT 144.3 48.3 144.5 48.5 ;
      RECT 144.3 53.5 144.5 53.7 ;
      RECT 144.3 53.9 144.5 54.1 ;
      RECT 144.3 88.3 144.5 88.5 ;
      RECT 144.3 88.7 144.5 88.9 ;
      RECT 144.3 90.7 144.5 90.9 ;
      RECT 144.3 131.1 144.5 131.3 ;
      RECT 144.3 131.5 144.5 131.7 ;
      RECT 144.3 139.5 144.5 139.7 ;
      RECT 144.3 139.9 144.5 140.1 ;
      RECT 144.3 145.9 144.5 146.1 ;
      RECT 144.3 146.3 144.5 146.5 ;
      RECT 144.3 153.9 144.5 154.1 ;
      RECT 144.3 154.3 144.5 154.5 ;
      RECT 144.3 164.3 144.5 164.5 ;
      RECT 144.3 164.7 144.5 164.9 ;
      RECT 144.3 169.1 144.5 169.3 ;
      RECT 144.3 169.5 144.5 169.7 ;
      RECT 144.3 171.1 144.5 171.3 ;
      RECT 144.3 173.5 144.5 173.7 ;
      RECT 144.3 192.7 144.5 192.9 ;
      RECT 144.3 195.5 144.5 195.7 ;
      RECT 144.3 198.3 144.5 198.5 ;
      RECT 144.3 198.7 144.5 198.9 ;
      RECT 144.3 208.3 144.5 208.5 ;
      RECT 144.3 208.7 144.5 208.9 ;
      RECT 143.8 4 144 4.2 ;
      RECT 143.8 4.6 144 4.8 ;
      RECT 143.8 5.2 144 5.4 ;
      RECT 143.8 5.8 144 6 ;
      RECT 143.8 6.9 144 7.1 ;
      RECT 143.8 14.1 144 14.3 ;
      RECT 143.8 21.3 144 21.5 ;
      RECT 143.8 28.5 144 28.7 ;
      RECT 143.8 35.7 144 35.9 ;
      RECT 143.8 42.9 144 43.1 ;
      RECT 143.8 50.1 144 50.3 ;
      RECT 143.8 57.3 144 57.5 ;
      RECT 143.8 64.5 144 64.7 ;
      RECT 143.8 71.7 144 71.9 ;
      RECT 143.8 78.9 144 79.1 ;
      RECT 143.8 86.1 144 86.3 ;
      RECT 143.8 93.3 144 93.5 ;
      RECT 143.8 100.5 144 100.7 ;
      RECT 143.8 107.7 144 107.9 ;
      RECT 143.8 114.9 144 115.1 ;
      RECT 143.8 122.1 144 122.3 ;
      RECT 143.8 129.3 144 129.5 ;
      RECT 143.8 136.5 144 136.7 ;
      RECT 143.8 143.7 144 143.9 ;
      RECT 143.8 150.9 144 151.1 ;
      RECT 143.8 158.1 144 158.3 ;
      RECT 143.8 165.3 144 165.5 ;
      RECT 143.8 172.5 144 172.7 ;
      RECT 143.8 179.7 144 179.9 ;
      RECT 143.8 186.9 144 187.1 ;
      RECT 143.8 194.1 144 194.3 ;
      RECT 143.8 201.3 144 201.5 ;
      RECT 143.8 208.5 144 208.7 ;
      RECT 143.8 213.6 144 213.8 ;
      RECT 143.8 214.2 144 214.4 ;
      RECT 143.8 214.8 144 215 ;
      RECT 143.8 215.4 144 215.6 ;
      RECT 143.2 4 143.4 4.2 ;
      RECT 143.2 4.6 143.4 4.8 ;
      RECT 143.2 5.2 143.4 5.4 ;
      RECT 143.2 5.8 143.4 6 ;
      RECT 143.2 6.9 143.4 7.1 ;
      RECT 143.2 14.1 143.4 14.3 ;
      RECT 143.2 21.3 143.4 21.5 ;
      RECT 143.2 28.5 143.4 28.7 ;
      RECT 143.2 35.7 143.4 35.9 ;
      RECT 143.2 42.9 143.4 43.1 ;
      RECT 143.2 50.1 143.4 50.3 ;
      RECT 143.2 57.3 143.4 57.5 ;
      RECT 143.2 64.5 143.4 64.7 ;
      RECT 143.2 71.7 143.4 71.9 ;
      RECT 143.2 78.9 143.4 79.1 ;
      RECT 143.2 86.1 143.4 86.3 ;
      RECT 143.2 93.3 143.4 93.5 ;
      RECT 143.2 100.5 143.4 100.7 ;
      RECT 143.2 107.7 143.4 107.9 ;
      RECT 143.2 114.9 143.4 115.1 ;
      RECT 143.2 122.1 143.4 122.3 ;
      RECT 143.2 129.3 143.4 129.5 ;
      RECT 143.2 136.5 143.4 136.7 ;
      RECT 143.2 143.7 143.4 143.9 ;
      RECT 143.2 150.9 143.4 151.1 ;
      RECT 143.2 158.1 143.4 158.3 ;
      RECT 143.2 165.3 143.4 165.5 ;
      RECT 143.2 172.5 143.4 172.7 ;
      RECT 143.2 179.7 143.4 179.9 ;
      RECT 143.2 186.9 143.4 187.1 ;
      RECT 143.2 194.1 143.4 194.3 ;
      RECT 143.2 201.3 143.4 201.5 ;
      RECT 143.2 208.5 143.4 208.7 ;
      RECT 143.2 213.6 143.4 213.8 ;
      RECT 143.2 214.2 143.4 214.4 ;
      RECT 143.2 214.8 143.4 215 ;
      RECT 143.2 215.4 143.4 215.6 ;
      RECT 142.6 4 142.8 4.2 ;
      RECT 142.6 4.6 142.8 4.8 ;
      RECT 142.6 5.2 142.8 5.4 ;
      RECT 142.6 5.8 142.8 6 ;
      RECT 142.6 6.9 142.8 7.1 ;
      RECT 142.6 14.1 142.8 14.3 ;
      RECT 142.6 21.3 142.8 21.5 ;
      RECT 142.6 28.5 142.8 28.7 ;
      RECT 142.6 35.7 142.8 35.9 ;
      RECT 142.6 42.9 142.8 43.1 ;
      RECT 142.6 50.1 142.8 50.3 ;
      RECT 142.6 57.3 142.8 57.5 ;
      RECT 142.6 64.5 142.8 64.7 ;
      RECT 142.6 71.7 142.8 71.9 ;
      RECT 142.6 78.9 142.8 79.1 ;
      RECT 142.6 86.1 142.8 86.3 ;
      RECT 142.6 93.3 142.8 93.5 ;
      RECT 142.6 100.5 142.8 100.7 ;
      RECT 142.6 107.7 142.8 107.9 ;
      RECT 142.6 114.9 142.8 115.1 ;
      RECT 142.6 122.1 142.8 122.3 ;
      RECT 142.6 129.3 142.8 129.5 ;
      RECT 142.6 136.5 142.8 136.7 ;
      RECT 142.6 143.7 142.8 143.9 ;
      RECT 142.6 150.9 142.8 151.1 ;
      RECT 142.6 158.1 142.8 158.3 ;
      RECT 142.6 165.3 142.8 165.5 ;
      RECT 142.6 172.5 142.8 172.7 ;
      RECT 142.6 179.7 142.8 179.9 ;
      RECT 142.6 186.9 142.8 187.1 ;
      RECT 142.6 194.1 142.8 194.3 ;
      RECT 142.6 201.3 142.8 201.5 ;
      RECT 142.6 208.5 142.8 208.7 ;
      RECT 142.6 213.6 142.8 213.8 ;
      RECT 142.6 214.2 142.8 214.4 ;
      RECT 142.6 214.8 142.8 215 ;
      RECT 142.6 215.4 142.8 215.6 ;
      RECT 142 4 142.2 4.2 ;
      RECT 142 4.6 142.2 4.8 ;
      RECT 142 5.2 142.2 5.4 ;
      RECT 142 5.8 142.2 6 ;
      RECT 142 6.9 142.2 7.1 ;
      RECT 142 14.1 142.2 14.3 ;
      RECT 142 21.3 142.2 21.5 ;
      RECT 142 28.5 142.2 28.7 ;
      RECT 142 35.7 142.2 35.9 ;
      RECT 142 42.9 142.2 43.1 ;
      RECT 142 50.1 142.2 50.3 ;
      RECT 142 57.3 142.2 57.5 ;
      RECT 142 64.5 142.2 64.7 ;
      RECT 142 71.7 142.2 71.9 ;
      RECT 142 78.9 142.2 79.1 ;
      RECT 142 86.1 142.2 86.3 ;
      RECT 142 93.3 142.2 93.5 ;
      RECT 142 100.5 142.2 100.7 ;
      RECT 142 107.7 142.2 107.9 ;
      RECT 142 114.9 142.2 115.1 ;
      RECT 142 122.1 142.2 122.3 ;
      RECT 142 129.3 142.2 129.5 ;
      RECT 142 136.5 142.2 136.7 ;
      RECT 142 143.7 142.2 143.9 ;
      RECT 142 150.9 142.2 151.1 ;
      RECT 142 158.1 142.2 158.3 ;
      RECT 142 165.3 142.2 165.5 ;
      RECT 142 172.5 142.2 172.7 ;
      RECT 142 179.7 142.2 179.9 ;
      RECT 142 186.9 142.2 187.1 ;
      RECT 142 194.1 142.2 194.3 ;
      RECT 142 201.3 142.2 201.5 ;
      RECT 142 208.5 142.2 208.7 ;
      RECT 142 213.6 142.2 213.8 ;
      RECT 142 214.2 142.2 214.4 ;
      RECT 142 214.8 142.2 215 ;
      RECT 142 215.4 142.2 215.6 ;
      RECT 141.5 11.5 141.7 11.7 ;
      RECT 141.5 11.9 141.7 12.1 ;
      RECT 141.5 19.1 141.7 19.3 ;
      RECT 141.5 51.9 141.7 52.1 ;
      RECT 141.5 61.9 141.7 62.1 ;
      RECT 141.5 62.3 141.7 62.5 ;
      RECT 141.5 94.7 141.7 94.9 ;
      RECT 141.5 99.1 141.7 99.3 ;
      RECT 141.5 99.5 141.7 99.7 ;
      RECT 141.5 102.7 141.7 102.9 ;
      RECT 141.5 103.1 141.7 103.3 ;
      RECT 141.5 131.5 141.7 131.7 ;
      RECT 141.5 148.3 141.7 148.5 ;
      RECT 141.5 148.7 141.7 148.9 ;
      RECT 141.5 150.3 141.7 150.5 ;
      RECT 141.5 150.7 141.7 150.9 ;
      RECT 141.5 154.3 141.7 154.5 ;
      RECT 141.5 157.5 141.7 157.7 ;
      RECT 141.5 175.9 141.7 176.1 ;
      RECT 141.5 182.3 141.7 182.5 ;
      RECT 141.5 200.7 141.7 200.9 ;
      RECT 141.5 201.1 141.7 201.3 ;
      RECT 141.5 202.3 141.7 202.5 ;
      RECT 141.5 202.7 141.7 202.9 ;
      RECT 141.1 17.1 141.3 17.3 ;
      RECT 141.1 19.1 141.3 19.3 ;
      RECT 141.1 58.7 141.3 58.9 ;
      RECT 141.1 67.1 141.3 67.3 ;
      RECT 141.1 94.7 141.3 94.9 ;
      RECT 141.1 101.5 141.3 101.7 ;
      RECT 141.1 101.9 141.3 102.1 ;
      RECT 141.1 133.5 141.3 133.7 ;
      RECT 141.1 134.3 141.3 134.5 ;
      RECT 141.1 149.5 141.3 149.7 ;
      RECT 141.1 149.9 141.3 150.1 ;
      RECT 141.1 154.3 141.3 154.5 ;
      RECT 141.1 162.3 141.3 162.5 ;
      RECT 141.1 172.3 141.3 172.5 ;
      RECT 141.1 174.7 141.3 174.9 ;
      RECT 141.1 195.9 141.3 196.1 ;
      RECT 141.1 201.5 141.3 201.7 ;
      RECT 140.7 15.5 140.9 15.7 ;
      RECT 140.7 17.9 140.9 18.1 ;
      RECT 140.7 25.1 140.9 25.3 ;
      RECT 140.7 52.3 140.9 52.5 ;
      RECT 140.7 52.7 140.9 52.9 ;
      RECT 140.7 58.7 140.9 58.9 ;
      RECT 140.7 67.1 140.9 67.3 ;
      RECT 140.7 87.1 140.9 87.3 ;
      RECT 140.7 87.5 140.9 87.7 ;
      RECT 140.7 96.7 140.9 96.9 ;
      RECT 140.7 97.1 140.9 97.3 ;
      RECT 140.7 111.9 140.9 112.1 ;
      RECT 140.7 116.3 140.9 116.5 ;
      RECT 140.7 139.9 140.9 140.1 ;
      RECT 140.7 148.7 140.9 148.9 ;
      RECT 140.7 169.9 140.9 170.1 ;
      RECT 140.7 175.5 140.9 175.7 ;
      RECT 140.7 183.1 140.9 183.3 ;
      RECT 140.7 188.3 140.9 188.5 ;
      RECT 140.7 190.3 140.9 190.5 ;
      RECT 140.3 26.3 140.5 26.5 ;
      RECT 140.3 26.7 140.5 26.9 ;
      RECT 140.3 27.9 140.5 28.1 ;
      RECT 140.3 28.3 140.5 28.5 ;
      RECT 140.3 56.7 140.5 56.9 ;
      RECT 140.3 57.1 140.5 57.3 ;
      RECT 140.3 60.7 140.5 60.9 ;
      RECT 140.3 61.1 140.5 61.3 ;
      RECT 140.3 65.9 140.5 66.1 ;
      RECT 140.3 73.1 140.5 73.3 ;
      RECT 140.3 89.1 140.5 89.3 ;
      RECT 140.3 96.3 140.5 96.5 ;
      RECT 140.3 107.1 140.5 107.3 ;
      RECT 140.3 113.1 140.5 113.3 ;
      RECT 140.3 142.3 140.5 142.5 ;
      RECT 140.3 144.7 140.5 144.9 ;
      RECT 140.3 166.3 140.5 166.5 ;
      RECT 140.3 173.1 140.5 173.3 ;
      RECT 140.3 174.7 140.5 174.9 ;
      RECT 140.3 178.7 140.5 178.9 ;
      RECT 140.3 193.1 140.5 193.3 ;
      RECT 140.3 195.5 140.5 195.7 ;
      RECT 140.3 200.3 140.5 200.5 ;
      RECT 140.3 209.1 140.5 209.3 ;
      RECT 139.9 21.1 140.1 21.3 ;
      RECT 139.9 21.5 140.1 21.7 ;
      RECT 139.9 29.5 140.1 29.7 ;
      RECT 139.9 29.9 140.1 30.1 ;
      RECT 139.9 63.1 140.1 63.3 ;
      RECT 139.9 65.9 140.1 66.1 ;
      RECT 139.9 70.3 140.1 70.5 ;
      RECT 139.9 73.1 140.1 73.3 ;
      RECT 139.9 77.5 140.1 77.7 ;
      RECT 139.9 77.9 140.1 78.1 ;
      RECT 139.9 89.1 140.1 89.3 ;
      RECT 139.9 96.3 140.1 96.5 ;
      RECT 139.9 142.3 140.1 142.5 ;
      RECT 139.9 144.7 140.1 144.9 ;
      RECT 139.9 159.9 140.1 160.1 ;
      RECT 139.9 166.3 140.1 166.5 ;
      RECT 139.9 192.7 140.1 192.9 ;
      RECT 139.5 63.1 139.7 63.3 ;
      RECT 139.5 70.3 139.7 70.5 ;
      RECT 139.5 90.3 139.7 90.5 ;
      RECT 139.5 91.9 139.7 92.1 ;
      RECT 139.5 159.9 139.7 160.1 ;
      RECT 139.5 166.7 139.7 166.9 ;
      RECT 139.5 171.1 139.7 171.3 ;
      RECT 139.5 178.3 139.7 178.5 ;
      RECT 139.5 181.1 139.7 181.3 ;
      RECT 139.5 187.9 139.7 188.1 ;
      RECT 139.5 188.3 139.7 188.5 ;
      RECT 139.5 209.1 139.7 209.3 ;
      RECT 139.5 209.5 139.7 209.7 ;
      RECT 139.5 213.1 139.7 213.3 ;
      RECT 139.1 149.9 139.3 150.1 ;
      RECT 139.1 150.3 139.3 150.5 ;
      RECT 139.1 166.7 139.3 166.9 ;
      RECT 139.1 171.1 139.3 171.3 ;
      RECT 139.1 178.3 139.3 178.5 ;
      RECT 139.1 181.1 139.3 181.3 ;
      RECT 139.1 213.1 139.3 213.3 ;
      RECT 138.7 80.7 138.9 80.9 ;
      RECT 138.7 91.5 138.9 91.7 ;
      RECT 138.7 100.7 138.9 100.9 ;
      RECT 138.7 135.1 138.9 135.3 ;
      RECT 138.7 173.1 138.9 173.3 ;
      RECT 138.7 173.5 138.9 173.7 ;
      RECT 138.7 179.9 138.9 180.1 ;
      RECT 138.7 193.9 138.9 194.1 ;
      RECT 138.7 200.7 138.9 200.9 ;
      RECT 138.3 44.7 138.5 44.9 ;
      RECT 138.3 55.9 138.5 56.1 ;
      RECT 138.3 56.3 138.5 56.5 ;
      RECT 138.3 110.7 138.5 110.9 ;
      RECT 138.3 120.7 138.5 120.9 ;
      RECT 138.3 121.1 138.5 121.3 ;
      RECT 138.3 135.1 138.5 135.3 ;
      RECT 138.3 150.3 138.5 150.5 ;
      RECT 138.3 171.5 138.5 171.7 ;
      RECT 138.3 176.3 138.5 176.5 ;
      RECT 138.3 180.3 138.5 180.5 ;
      RECT 138.3 185.9 138.5 186.1 ;
      RECT 137.9 117.5 138.1 117.7 ;
      RECT 137.9 122.3 138.1 122.5 ;
      RECT 137.9 127.5 138.1 127.7 ;
      RECT 137.9 130.3 138.1 130.5 ;
      RECT 137.9 208.7 138.1 208.9 ;
      RECT 137.9 209.9 138.1 210.1 ;
      RECT 137.9 211.5 138.1 211.7 ;
      RECT 137.5 38.3 137.7 38.5 ;
      RECT 137.5 38.7 137.7 38.9 ;
      RECT 137.5 40.7 137.7 40.9 ;
      RECT 137.5 51.9 137.7 52.1 ;
      RECT 137.5 52.3 137.7 52.5 ;
      RECT 137.5 56.3 137.7 56.5 ;
      RECT 137.5 56.7 137.7 56.9 ;
      RECT 137.5 58.3 137.7 58.5 ;
      RECT 137.5 58.7 137.7 58.9 ;
      RECT 137.5 123.1 137.7 123.3 ;
      RECT 137.5 143.5 137.7 143.7 ;
      RECT 137.5 143.9 137.7 144.1 ;
      RECT 137.5 183.9 137.7 184.1 ;
      RECT 137.5 189.5 137.7 189.7 ;
      RECT 137.5 194.7 137.7 194.9 ;
      RECT 137.1 40.7 137.3 40.9 ;
      RECT 137.1 123.1 137.3 123.3 ;
      RECT 137.1 175.1 137.3 175.3 ;
      RECT 137.1 177.5 137.3 177.7 ;
      RECT 137.1 180.3 137.3 180.5 ;
      RECT 136.7 31.9 136.9 32.1 ;
      RECT 136.7 146.3 136.9 146.5 ;
      RECT 136.7 194.7 136.9 194.9 ;
      RECT 136.7 198.7 136.9 198.9 ;
      RECT 136.7 205.5 136.9 205.7 ;
      RECT 136.3 19.9 136.5 20.1 ;
      RECT 136.3 20.3 136.5 20.5 ;
      RECT 136.3 25.1 136.5 25.3 ;
      RECT 136.3 25.5 136.5 25.7 ;
      RECT 136.3 85.1 136.5 85.3 ;
      RECT 136.3 99.1 136.5 99.3 ;
      RECT 136.3 127.9 136.5 128.1 ;
      RECT 136.3 140.7 136.5 140.9 ;
      RECT 136.3 192.7 136.5 192.9 ;
      RECT 136.3 209.1 136.5 209.3 ;
      RECT 135.9 85.1 136.1 85.3 ;
      RECT 135.9 110.7 136.1 110.9 ;
      RECT 135.9 111.1 136.1 111.3 ;
      RECT 135.9 123.5 136.1 123.7 ;
      RECT 135.9 135.1 136.1 135.3 ;
      RECT 135.9 137.9 136.1 138.1 ;
      RECT 135.9 142.3 136.1 142.5 ;
      RECT 135.9 156.7 136.1 156.9 ;
      RECT 135.9 163.9 136.1 164.1 ;
      RECT 135.9 195.1 136.1 195.3 ;
      RECT 135.9 197.9 136.1 198.1 ;
      RECT 135.5 15.9 135.7 16.1 ;
      RECT 135.5 38.7 135.7 38.9 ;
      RECT 135.5 108.7 135.7 108.9 ;
      RECT 135.5 109.1 135.7 109.3 ;
      RECT 135.5 123.5 135.7 123.7 ;
      RECT 135.5 135.1 135.7 135.3 ;
      RECT 135.5 137.9 135.7 138.1 ;
      RECT 135.5 142.3 135.7 142.5 ;
      RECT 135.5 156.7 135.7 156.9 ;
      RECT 135.5 163.9 135.7 164.1 ;
      RECT 135.5 185.9 135.7 186.1 ;
      RECT 135.5 200.7 135.7 200.9 ;
      RECT 135.1 181.9 135.3 182.1 ;
      RECT 135.1 182.3 135.3 182.5 ;
      RECT 135.1 185.9 135.3 186.1 ;
      RECT 135.1 193.9 135.3 194.1 ;
      RECT 135.1 194.3 135.3 194.5 ;
      RECT 135.1 200.7 135.3 200.9 ;
      RECT 134.7 64.7 134.9 64.9 ;
      RECT 134.7 65.1 134.9 65.3 ;
      RECT 134.7 88.3 134.9 88.5 ;
      RECT 134.7 88.7 134.9 88.9 ;
      RECT 134.7 139.5 134.9 139.7 ;
      RECT 134.7 172.3 134.9 172.5 ;
      RECT 134.7 207.5 134.9 207.7 ;
      RECT 134.7 207.9 134.9 208.1 ;
      RECT 134.3 139.5 134.5 139.7 ;
      RECT 134.3 166.7 134.5 166.9 ;
      RECT 134.3 167.1 134.5 167.3 ;
      RECT 134.3 206.3 134.5 206.5 ;
      RECT 134.3 206.7 134.5 206.9 ;
      RECT 133.9 55.1 134.1 55.3 ;
      RECT 133.9 113.9 134.1 114.1 ;
      RECT 133.9 114.3 134.1 114.5 ;
      RECT 133.9 127.1 134.1 127.3 ;
      RECT 133.9 152.3 134.1 152.5 ;
      RECT 133.9 152.7 134.1 152.9 ;
      RECT 133.9 195.9 134.1 196.1 ;
      RECT 133.9 209.5 134.1 209.7 ;
      RECT 133.5 60.7 133.7 60.9 ;
      RECT 133.5 61.1 133.7 61.3 ;
      RECT 133.5 61.9 133.7 62.1 ;
      RECT 133.5 62.3 133.7 62.5 ;
      RECT 133.5 103.1 133.7 103.3 ;
      RECT 133.5 103.9 133.7 104.1 ;
      RECT 133.5 119.9 133.7 120.1 ;
      RECT 133.5 174.7 133.7 174.9 ;
      RECT 133.5 188.3 133.7 188.5 ;
      RECT 133.1 51.5 133.3 51.7 ;
      RECT 133.1 84.7 133.3 84.9 ;
      RECT 133.1 89.1 133.3 89.3 ;
      RECT 133.1 116.3 133.3 116.5 ;
      RECT 133.1 128.7 133.3 128.9 ;
      RECT 133.1 144.3 133.3 144.5 ;
      RECT 133.1 144.7 133.3 144.9 ;
      RECT 133.1 164.7 133.3 164.9 ;
      RECT 133.1 165.1 133.3 165.3 ;
      RECT 133.1 188.3 133.3 188.5 ;
      RECT 133.1 192.7 133.3 192.9 ;
      RECT 132.7 37.1 132.9 37.3 ;
      RECT 132.7 47.5 132.9 47.7 ;
      RECT 132.7 51.5 132.9 51.7 ;
      RECT 132.7 55.9 132.9 56.1 ;
      RECT 132.7 58.7 132.9 58.9 ;
      RECT 132.7 63.1 132.9 63.3 ;
      RECT 132.7 70.3 132.9 70.5 ;
      RECT 132.7 77.5 132.9 77.7 ;
      RECT 132.7 84.7 132.9 84.9 ;
      RECT 132.7 89.1 132.9 89.3 ;
      RECT 132.7 131.9 132.9 132.1 ;
      RECT 132.7 146.7 132.9 146.9 ;
      RECT 132.7 147.1 132.9 147.3 ;
      RECT 132.7 160.3 132.9 160.5 ;
      RECT 132.7 160.7 132.9 160.9 ;
      RECT 132.7 192.7 132.9 192.9 ;
      RECT 132.3 55.9 132.5 56.1 ;
      RECT 132.3 58.7 132.5 58.9 ;
      RECT 132.3 63.1 132.5 63.3 ;
      RECT 132.3 70.3 132.5 70.5 ;
      RECT 132.3 77.5 132.5 77.7 ;
      RECT 132.3 92.3 132.5 92.5 ;
      RECT 132.3 92.7 132.5 92.9 ;
      RECT 132.3 117.5 132.5 117.7 ;
      RECT 132.3 117.9 132.5 118.1 ;
      RECT 132.3 141.9 132.5 142.1 ;
      RECT 132.3 181.1 132.5 181.3 ;
      RECT 132.3 182.3 132.5 182.5 ;
      RECT 132.3 189.1 132.5 189.3 ;
      RECT 132.3 189.5 132.5 189.7 ;
      RECT 132.3 195.9 132.5 196.1 ;
      RECT 132.3 196.3 132.5 196.5 ;
      RECT 131.9 134.7 132.1 134.9 ;
      RECT 131.9 135.1 132.1 135.3 ;
      RECT 131.9 141.9 132.1 142.1 ;
      RECT 131.9 159.5 132.1 159.7 ;
      RECT 131.9 159.9 132.1 160.1 ;
      RECT 131.9 181.1 132.1 181.3 ;
      RECT 131.9 185.5 132.1 185.7 ;
      RECT 131.9 185.9 132.1 186.1 ;
      RECT 131.5 36.3 131.7 36.5 ;
      RECT 131.5 36.7 131.7 36.9 ;
      RECT 131.5 38.7 131.7 38.9 ;
      RECT 131.5 39.1 131.7 39.3 ;
      RECT 131.5 99.1 131.7 99.3 ;
      RECT 131.5 104.3 131.7 104.5 ;
      RECT 131.5 104.7 131.7 104.9 ;
      RECT 131.5 115.5 131.7 115.7 ;
      RECT 131.5 151.9 131.7 152.1 ;
      RECT 131.1 98.3 131.3 98.5 ;
      RECT 131.1 152.7 131.3 152.9 ;
      RECT 131.1 195.9 131.3 196.1 ;
      RECT 131.1 203.5 131.3 203.7 ;
      RECT 130.7 92.3 130.9 92.5 ;
      RECT 130.7 92.7 130.9 92.9 ;
      RECT 130.7 98.3 130.9 98.5 ;
      RECT 130.7 108.7 130.9 108.9 ;
      RECT 130.7 158.7 130.9 158.9 ;
      RECT 130.7 192.3 130.9 192.5 ;
      RECT 130.7 192.7 130.9 192.9 ;
      RECT 130.7 195.9 130.9 196.1 ;
      RECT 130.7 200.3 130.9 200.5 ;
      RECT 130.7 200.7 130.9 200.9 ;
      RECT 130.7 202.3 130.9 202.5 ;
      RECT 130.7 202.7 130.9 202.9 ;
      RECT 130.7 203.5 130.9 203.7 ;
      RECT 130.3 25.5 130.5 25.7 ;
      RECT 130.3 35.9 130.5 36.1 ;
      RECT 130.3 49.9 130.5 50.1 ;
      RECT 130.3 54.3 130.5 54.5 ;
      RECT 130.3 107.9 130.5 108.1 ;
      RECT 130.3 135.9 130.5 136.1 ;
      RECT 130.3 136.3 130.5 136.5 ;
      RECT 130.3 152.3 130.5 152.5 ;
      RECT 130.3 152.7 130.5 152.9 ;
      RECT 130.3 158.7 130.5 158.9 ;
      RECT 130.3 179.5 130.5 179.7 ;
      RECT 130.3 179.9 130.5 180.1 ;
      RECT 129.9 104.3 130.1 104.5 ;
      RECT 129.9 104.7 130.1 104.9 ;
      RECT 129.9 107.9 130.1 108.1 ;
      RECT 129.9 163.9 130.1 164.1 ;
      RECT 129.9 166.7 130.1 166.9 ;
      RECT 129.5 56.7 129.7 56.9 ;
      RECT 129.5 91.1 129.7 91.3 ;
      RECT 129.5 91.5 129.7 91.7 ;
      RECT 129.5 100.7 129.7 100.9 ;
      RECT 129.5 119.5 129.7 119.7 ;
      RECT 129.5 144.3 129.7 144.5 ;
      RECT 129.5 149.5 129.7 149.7 ;
      RECT 129.5 152.3 129.7 152.5 ;
      RECT 129.5 156.7 129.7 156.9 ;
      RECT 129.5 159.5 129.7 159.7 ;
      RECT 129.5 163.9 129.7 164.1 ;
      RECT 129.5 166.7 129.7 166.9 ;
      RECT 129.1 28.3 129.3 28.5 ;
      RECT 129.1 52.3 129.3 52.5 ;
      RECT 129.1 52.7 129.3 52.9 ;
      RECT 129.1 54.7 129.3 54.9 ;
      RECT 129.1 55.1 129.3 55.3 ;
      RECT 129.1 56.7 129.3 56.9 ;
      RECT 129.1 89.9 129.3 90.1 ;
      RECT 129.1 90.3 129.3 90.5 ;
      RECT 129.1 95.1 129.3 95.3 ;
      RECT 129.1 100.7 129.3 100.9 ;
      RECT 129.1 143.1 129.3 143.3 ;
      RECT 129.1 144.3 129.3 144.5 ;
      RECT 129.1 149.5 129.3 149.7 ;
      RECT 129.1 152.3 129.3 152.5 ;
      RECT 129.1 156.7 129.3 156.9 ;
      RECT 129.1 159.5 129.3 159.7 ;
      RECT 128.7 28.3 128.9 28.5 ;
      RECT 128.7 37.5 128.9 37.7 ;
      RECT 128.7 37.9 128.9 38.1 ;
      RECT 128.7 39.1 128.9 39.3 ;
      RECT 128.7 46.3 128.9 46.5 ;
      RECT 128.7 53.9 128.9 54.1 ;
      RECT 128.7 80.7 128.9 80.9 ;
      RECT 128.7 81.1 128.9 81.3 ;
      RECT 128.7 83.9 128.9 84.1 ;
      RECT 128.7 84.3 128.9 84.5 ;
      RECT 128.7 92.3 128.9 92.5 ;
      RECT 128.7 92.7 128.9 92.9 ;
      RECT 128.7 95.1 128.9 95.3 ;
      RECT 128.7 144.7 128.9 144.9 ;
      RECT 128.7 145.1 128.9 145.3 ;
      RECT 128.7 171.5 128.9 171.7 ;
      RECT 128.7 171.9 128.9 172.1 ;
      RECT 128.7 200.7 128.9 200.9 ;
      RECT 128.3 28.7 128.5 28.9 ;
      RECT 128.3 29.1 128.5 29.3 ;
      RECT 128.3 39.1 128.5 39.3 ;
      RECT 128.3 50.7 128.5 50.9 ;
      RECT 128.3 54.7 128.5 54.9 ;
      RECT 128.3 138.3 128.5 138.5 ;
      RECT 128.3 138.7 128.5 138.9 ;
      RECT 128.3 157.9 128.5 158.1 ;
      RECT 128.3 158.3 128.5 158.5 ;
      RECT 128.3 167.9 128.5 168.1 ;
      RECT 128.3 169.5 128.5 169.7 ;
      RECT 128.3 169.9 128.5 170.1 ;
      RECT 128.3 190.7 128.5 190.9 ;
      RECT 128.3 191.1 128.5 191.3 ;
      RECT 128.3 194.7 128.5 194.9 ;
      RECT 128.3 195.1 128.5 195.3 ;
      RECT 128.3 200.7 128.5 200.9 ;
      RECT 127.9 79.5 128.1 79.7 ;
      RECT 127.9 93.1 128.1 93.3 ;
      RECT 127.9 93.5 128.1 93.7 ;
      RECT 127.9 167.9 128.1 168.1 ;
      RECT 127.9 191.9 128.1 192.1 ;
      RECT 127.9 192.3 128.1 192.5 ;
      RECT 127.9 209.9 128.1 210.1 ;
      RECT 127.9 210.3 128.1 210.5 ;
      RECT 127.5 50.7 127.7 50.9 ;
      RECT 127.5 51.1 127.7 51.3 ;
      RECT 127.5 56.3 127.7 56.5 ;
      RECT 127.5 56.7 127.7 56.9 ;
      RECT 127.5 79.5 127.7 79.7 ;
      RECT 127.5 91.9 127.7 92.1 ;
      RECT 127.5 96.7 127.7 96.9 ;
      RECT 127.5 97.1 127.7 97.3 ;
      RECT 127.5 99.1 127.7 99.3 ;
      RECT 127.5 101.9 127.7 102.1 ;
      RECT 127.5 106.3 127.7 106.5 ;
      RECT 127.5 113.5 127.7 113.7 ;
      RECT 127.5 130.7 127.7 130.9 ;
      RECT 127.5 135.1 127.7 135.3 ;
      RECT 127.5 139.5 127.7 139.7 ;
      RECT 127.5 172.7 127.7 172.9 ;
      RECT 127.5 179.1 127.7 179.3 ;
      RECT 127.5 203.9 127.7 204.1 ;
      RECT 127.1 14.7 127.3 14.9 ;
      RECT 127.1 20.3 127.3 20.5 ;
      RECT 127.1 84.7 127.3 84.9 ;
      RECT 127.1 91.9 127.3 92.1 ;
      RECT 127.1 94.7 127.3 94.9 ;
      RECT 127.1 99.1 127.3 99.3 ;
      RECT 127.1 101.9 127.3 102.1 ;
      RECT 127.1 106.3 127.3 106.5 ;
      RECT 127.1 113.5 127.3 113.7 ;
      RECT 127.1 123.5 127.3 123.7 ;
      RECT 127.1 127.9 127.3 128.1 ;
      RECT 127.1 130.7 127.3 130.9 ;
      RECT 127.1 135.1 127.3 135.3 ;
      RECT 127.1 137.9 127.3 138.1 ;
      RECT 127.1 138.3 127.3 138.5 ;
      RECT 127.1 142.3 127.3 142.5 ;
      RECT 127.1 142.7 127.3 142.9 ;
      RECT 127.1 147.5 127.3 147.7 ;
      RECT 127.1 147.9 127.3 148.1 ;
      RECT 127.1 148.7 127.3 148.9 ;
      RECT 127.1 149.1 127.3 149.3 ;
      RECT 127.1 165.5 127.3 165.7 ;
      RECT 127.1 172.7 127.3 172.9 ;
      RECT 126.7 37.1 126.9 37.3 ;
      RECT 126.7 73.9 126.9 74.1 ;
      RECT 126.7 74.3 126.9 74.5 ;
      RECT 126.7 77.5 126.9 77.7 ;
      RECT 126.7 77.9 126.9 78.1 ;
      RECT 126.7 84.7 126.9 84.9 ;
      RECT 126.7 94.7 126.9 94.9 ;
      RECT 126.7 123.5 126.9 123.7 ;
      RECT 126.7 127.9 126.9 128.1 ;
      RECT 126.7 137.1 126.9 137.3 ;
      RECT 126.7 137.5 126.9 137.7 ;
      RECT 126.7 164.7 126.9 164.9 ;
      RECT 126.7 165.5 126.9 165.7 ;
      RECT 126.7 193.1 126.9 193.3 ;
      RECT 126.7 193.5 126.9 193.7 ;
      RECT 126.3 15.9 126.5 16.1 ;
      RECT 126.3 21.9 126.5 22.1 ;
      RECT 126.3 29.9 126.5 30.1 ;
      RECT 126.3 143.9 126.5 144.1 ;
      RECT 126.3 144.3 126.5 144.5 ;
      RECT 126.3 149.9 126.5 150.1 ;
      RECT 126.3 150.3 126.5 150.5 ;
      RECT 125.9 37.1 126.1 37.3 ;
      RECT 125.9 62.3 126.1 62.5 ;
      RECT 125.9 62.7 126.1 62.9 ;
      RECT 125.9 109.9 126.1 110.1 ;
      RECT 125.9 110.3 126.1 110.5 ;
      RECT 125.9 120.3 126.1 120.5 ;
      RECT 125.9 201.1 126.1 201.3 ;
      RECT 125.9 201.5 126.1 201.7 ;
      RECT 125.5 22.3 125.7 22.5 ;
      RECT 125.5 24.3 125.7 24.5 ;
      RECT 125.5 89.9 125.7 90.1 ;
      RECT 125.5 132.7 125.7 132.9 ;
      RECT 125.5 133.9 125.7 134.1 ;
      RECT 125.1 18.7 125.3 18.9 ;
      RECT 125.1 19.1 125.3 19.3 ;
      RECT 125.1 19.9 125.3 20.1 ;
      RECT 125.1 20.3 125.3 20.5 ;
      RECT 125.1 77.5 125.3 77.7 ;
      RECT 125.1 77.9 125.3 78.1 ;
      RECT 125.1 89.9 125.3 90.1 ;
      RECT 125.1 95.9 125.3 96.1 ;
      RECT 125.1 96.3 125.3 96.5 ;
      RECT 125.1 127.1 125.3 127.3 ;
      RECT 125.1 168.3 125.3 168.5 ;
      RECT 125.1 168.7 125.3 168.9 ;
      RECT 124.7 12.7 124.9 12.9 ;
      RECT 124.7 27.1 124.9 27.3 ;
      RECT 124.7 41.5 124.9 41.7 ;
      RECT 124.7 43.5 124.9 43.7 ;
      RECT 124.7 55.5 124.9 55.7 ;
      RECT 124.7 87.9 124.9 88.1 ;
      RECT 124.7 103.5 124.9 103.7 ;
      RECT 124.7 103.9 124.9 104.1 ;
      RECT 124.7 115.1 124.9 115.3 ;
      RECT 124.7 115.5 124.9 115.7 ;
      RECT 124.7 122.7 124.9 122.9 ;
      RECT 124.7 131.1 124.9 131.3 ;
      RECT 124.3 12.7 124.5 12.9 ;
      RECT 124.3 15.5 124.5 15.7 ;
      RECT 124.3 19.9 124.5 20.1 ;
      RECT 124.3 22.7 124.5 22.9 ;
      RECT 124.3 27.1 124.5 27.3 ;
      RECT 124.3 29.9 124.5 30.1 ;
      RECT 124.3 34.3 124.5 34.5 ;
      RECT 124.3 37.1 124.5 37.3 ;
      RECT 124.3 41.5 124.5 41.7 ;
      RECT 124.3 43.5 124.5 43.7 ;
      RECT 124.3 54.3 124.5 54.5 ;
      RECT 124.3 55.5 124.5 55.7 ;
      RECT 124.3 70.3 124.5 70.5 ;
      RECT 124.3 80.3 124.5 80.5 ;
      RECT 124.3 80.7 124.5 80.9 ;
      RECT 124.3 87.9 124.5 88.1 ;
      RECT 123.9 15.5 124.1 15.7 ;
      RECT 123.9 19.9 124.1 20.1 ;
      RECT 123.9 22.7 124.1 22.9 ;
      RECT 123.9 29.9 124.1 30.1 ;
      RECT 123.9 34.3 124.1 34.5 ;
      RECT 123.9 37.1 124.1 37.3 ;
      RECT 123.9 54.3 124.1 54.5 ;
      RECT 123.9 70.3 124.1 70.5 ;
      RECT 123.9 153.5 124.1 153.7 ;
      RECT 123.9 162.7 124.1 162.9 ;
      RECT 123.5 121.1 123.7 121.3 ;
      RECT 123.1 204.7 123.3 204.9 ;
      RECT 123.1 205.1 123.3 205.3 ;
      RECT 122.3 125.9 122.5 126.1 ;
      RECT 122.3 135.5 122.5 135.7 ;
      RECT 122.3 160.3 122.5 160.5 ;
      RECT 122.3 160.7 122.5 160.9 ;
      RECT 122.3 162.3 122.5 162.5 ;
      RECT 122.3 162.7 122.5 162.9 ;
      RECT 121.9 122.3 122.1 122.5 ;
      RECT 121.9 122.7 122.1 122.9 ;
      RECT 121.9 139.1 122.1 139.3 ;
      RECT 121.9 167.1 122.1 167.3 ;
      RECT 121.9 167.5 122.1 167.7 ;
      RECT 121.9 177.9 122.1 178.1 ;
      RECT 121.9 178.3 122.1 178.5 ;
      RECT 121.9 208.3 122.1 208.5 ;
      RECT 121.9 208.7 122.1 208.9 ;
      RECT 121.5 26.3 121.7 26.5 ;
      RECT 121.5 26.7 121.7 26.9 ;
      RECT 121.5 73.9 121.7 74.1 ;
      RECT 121.5 74.3 121.7 74.5 ;
      RECT 121.5 139.1 121.7 139.3 ;
      RECT 121.1 159.5 121.3 159.7 ;
      RECT 121.1 178.3 121.3 178.5 ;
      RECT 121.1 181.1 121.3 181.3 ;
      RECT 121.1 188.3 121.3 188.5 ;
      RECT 121.1 192.7 121.3 192.9 ;
      RECT 121.1 195.5 121.3 195.7 ;
      RECT 121.1 199.9 121.3 200.1 ;
      RECT 121.1 202.7 121.3 202.9 ;
      RECT 121.1 207.1 121.3 207.3 ;
      RECT 120.7 104.3 120.9 104.5 ;
      RECT 120.7 104.7 120.9 104.9 ;
      RECT 120.7 116.3 120.9 116.5 ;
      RECT 120.7 116.7 120.9 116.9 ;
      RECT 120.7 157.5 120.9 157.7 ;
      RECT 120.7 159.5 120.9 159.7 ;
      RECT 120.7 166.7 120.9 166.9 ;
      RECT 120.7 171.1 120.9 171.3 ;
      RECT 120.7 173.9 120.9 174.1 ;
      RECT 120.7 178.3 120.9 178.5 ;
      RECT 120.7 181.1 120.9 181.3 ;
      RECT 120.7 185.5 120.9 185.7 ;
      RECT 120.7 188.3 120.9 188.5 ;
      RECT 120.7 192.7 120.9 192.9 ;
      RECT 120.7 195.5 120.9 195.7 ;
      RECT 120.7 199.9 120.9 200.1 ;
      RECT 120.7 202.7 120.9 202.9 ;
      RECT 120.7 207.1 120.9 207.3 ;
      RECT 120.3 131.5 120.5 131.7 ;
      RECT 120.3 149.5 120.5 149.7 ;
      RECT 120.3 157.5 120.5 157.7 ;
      RECT 120.3 166.7 120.5 166.9 ;
      RECT 120.3 171.1 120.5 171.3 ;
      RECT 120.3 173.9 120.5 174.1 ;
      RECT 120.3 185.5 120.5 185.7 ;
      RECT 119.9 65.1 120.1 65.3 ;
      RECT 119.9 65.5 120.1 65.7 ;
      RECT 119.9 110.3 120.1 110.5 ;
      RECT 119.9 110.7 120.1 110.9 ;
      RECT 119.9 165.5 120.1 165.7 ;
      RECT 119.9 204.3 120.1 204.5 ;
      RECT 119.9 211.5 120.1 211.7 ;
      RECT 119.5 130.3 119.7 130.5 ;
      RECT 119.5 130.7 119.7 130.9 ;
      RECT 119.5 180.3 119.7 180.5 ;
      RECT 119.5 180.7 119.7 180.9 ;
      RECT 119.1 104.3 119.3 104.5 ;
      RECT 119.1 104.7 119.3 104.9 ;
      RECT 119.1 111.1 119.3 111.3 ;
      RECT 119.1 111.5 119.3 111.7 ;
      RECT 118.7 59.9 118.9 60.1 ;
      RECT 118.7 60.3 118.9 60.5 ;
      RECT 118.7 115.9 118.9 116.1 ;
      RECT 118.7 116.3 118.9 116.5 ;
      RECT 118.7 139.5 118.9 139.7 ;
      RECT 118.7 139.9 118.9 140.1 ;
      RECT 118.7 156.3 118.9 156.5 ;
      RECT 118.7 156.7 118.9 156.9 ;
      RECT 118.7 206.3 118.9 206.5 ;
      RECT 118.7 206.7 118.9 206.9 ;
      RECT 118.3 151.5 118.5 151.7 ;
      RECT 118.3 151.9 118.5 152.1 ;
      RECT 118.3 159.1 118.5 159.3 ;
      RECT 118.3 159.5 118.5 159.7 ;
      RECT 117.8 1 118 1.2 ;
      RECT 117.8 1.6 118 1.8 ;
      RECT 117.8 2.2 118 2.4 ;
      RECT 117.8 2.8 118 3 ;
      RECT 117.8 10.5 118 10.7 ;
      RECT 117.8 17.7 118 17.9 ;
      RECT 117.8 24.9 118 25.1 ;
      RECT 117.8 32.1 118 32.3 ;
      RECT 117.8 39.3 118 39.5 ;
      RECT 117.8 46.5 118 46.7 ;
      RECT 117.8 53.7 118 53.9 ;
      RECT 117.8 60.9 118 61.1 ;
      RECT 117.8 68.1 118 68.3 ;
      RECT 117.8 75.3 118 75.5 ;
      RECT 117.8 82.5 118 82.7 ;
      RECT 117.8 89.7 118 89.9 ;
      RECT 117.8 96.9 118 97.1 ;
      RECT 117.8 104.1 118 104.3 ;
      RECT 117.8 111.3 118 111.5 ;
      RECT 117.8 118.5 118 118.7 ;
      RECT 117.8 125.7 118 125.9 ;
      RECT 117.8 132.9 118 133.1 ;
      RECT 117.8 140.1 118 140.3 ;
      RECT 117.8 147.3 118 147.5 ;
      RECT 117.8 154.5 118 154.7 ;
      RECT 117.8 161.7 118 161.9 ;
      RECT 117.8 168.9 118 169.1 ;
      RECT 117.8 176.1 118 176.3 ;
      RECT 117.8 183.3 118 183.5 ;
      RECT 117.8 190.5 118 190.7 ;
      RECT 117.8 197.7 118 197.9 ;
      RECT 117.8 204.9 118 205.1 ;
      RECT 117.8 212.1 118 212.3 ;
      RECT 117.8 216.6 118 216.8 ;
      RECT 117.8 217.2 118 217.4 ;
      RECT 117.8 217.8 118 218 ;
      RECT 117.8 218.4 118 218.6 ;
      RECT 117.2 1 117.4 1.2 ;
      RECT 117.2 1.6 117.4 1.8 ;
      RECT 117.2 2.2 117.4 2.4 ;
      RECT 117.2 2.8 117.4 3 ;
      RECT 117.2 10.5 117.4 10.7 ;
      RECT 117.2 17.7 117.4 17.9 ;
      RECT 117.2 24.9 117.4 25.1 ;
      RECT 117.2 32.1 117.4 32.3 ;
      RECT 117.2 39.3 117.4 39.5 ;
      RECT 117.2 46.5 117.4 46.7 ;
      RECT 117.2 53.7 117.4 53.9 ;
      RECT 117.2 60.9 117.4 61.1 ;
      RECT 117.2 68.1 117.4 68.3 ;
      RECT 117.2 75.3 117.4 75.5 ;
      RECT 117.2 82.5 117.4 82.7 ;
      RECT 117.2 89.7 117.4 89.9 ;
      RECT 117.2 96.9 117.4 97.1 ;
      RECT 117.2 104.1 117.4 104.3 ;
      RECT 117.2 111.3 117.4 111.5 ;
      RECT 117.2 118.5 117.4 118.7 ;
      RECT 117.2 125.7 117.4 125.9 ;
      RECT 117.2 132.9 117.4 133.1 ;
      RECT 117.2 140.1 117.4 140.3 ;
      RECT 117.2 147.3 117.4 147.5 ;
      RECT 117.2 154.5 117.4 154.7 ;
      RECT 117.2 161.7 117.4 161.9 ;
      RECT 117.2 168.9 117.4 169.1 ;
      RECT 117.2 176.1 117.4 176.3 ;
      RECT 117.2 183.3 117.4 183.5 ;
      RECT 117.2 190.5 117.4 190.7 ;
      RECT 117.2 197.7 117.4 197.9 ;
      RECT 117.2 204.9 117.4 205.1 ;
      RECT 117.2 212.1 117.4 212.3 ;
      RECT 117.2 216.6 117.4 216.8 ;
      RECT 117.2 217.2 117.4 217.4 ;
      RECT 117.2 217.8 117.4 218 ;
      RECT 117.2 218.4 117.4 218.6 ;
      RECT 116.6 1 116.8 1.2 ;
      RECT 116.6 1.6 116.8 1.8 ;
      RECT 116.6 2.2 116.8 2.4 ;
      RECT 116.6 2.8 116.8 3 ;
      RECT 116.6 10.5 116.8 10.7 ;
      RECT 116.6 17.7 116.8 17.9 ;
      RECT 116.6 24.9 116.8 25.1 ;
      RECT 116.6 32.1 116.8 32.3 ;
      RECT 116.6 39.3 116.8 39.5 ;
      RECT 116.6 46.5 116.8 46.7 ;
      RECT 116.6 53.7 116.8 53.9 ;
      RECT 116.6 60.9 116.8 61.1 ;
      RECT 116.6 68.1 116.8 68.3 ;
      RECT 116.6 75.3 116.8 75.5 ;
      RECT 116.6 82.5 116.8 82.7 ;
      RECT 116.6 89.7 116.8 89.9 ;
      RECT 116.6 96.9 116.8 97.1 ;
      RECT 116.6 104.1 116.8 104.3 ;
      RECT 116.6 111.3 116.8 111.5 ;
      RECT 116.6 118.5 116.8 118.7 ;
      RECT 116.6 125.7 116.8 125.9 ;
      RECT 116.6 132.9 116.8 133.1 ;
      RECT 116.6 140.1 116.8 140.3 ;
      RECT 116.6 147.3 116.8 147.5 ;
      RECT 116.6 154.5 116.8 154.7 ;
      RECT 116.6 161.7 116.8 161.9 ;
      RECT 116.6 168.9 116.8 169.1 ;
      RECT 116.6 176.1 116.8 176.3 ;
      RECT 116.6 183.3 116.8 183.5 ;
      RECT 116.6 190.5 116.8 190.7 ;
      RECT 116.6 197.7 116.8 197.9 ;
      RECT 116.6 204.9 116.8 205.1 ;
      RECT 116.6 212.1 116.8 212.3 ;
      RECT 116.6 216.6 116.8 216.8 ;
      RECT 116.6 217.2 116.8 217.4 ;
      RECT 116.6 217.8 116.8 218 ;
      RECT 116.6 218.4 116.8 218.6 ;
      RECT 116 1 116.2 1.2 ;
      RECT 116 1.6 116.2 1.8 ;
      RECT 116 2.2 116.2 2.4 ;
      RECT 116 2.8 116.2 3 ;
      RECT 116 10.5 116.2 10.7 ;
      RECT 116 17.7 116.2 17.9 ;
      RECT 116 24.9 116.2 25.1 ;
      RECT 116 32.1 116.2 32.3 ;
      RECT 116 39.3 116.2 39.5 ;
      RECT 116 46.5 116.2 46.7 ;
      RECT 116 53.7 116.2 53.9 ;
      RECT 116 60.9 116.2 61.1 ;
      RECT 116 68.1 116.2 68.3 ;
      RECT 116 75.3 116.2 75.5 ;
      RECT 116 82.5 116.2 82.7 ;
      RECT 116 89.7 116.2 89.9 ;
      RECT 116 96.9 116.2 97.1 ;
      RECT 116 104.1 116.2 104.3 ;
      RECT 116 111.3 116.2 111.5 ;
      RECT 116 118.5 116.2 118.7 ;
      RECT 116 125.7 116.2 125.9 ;
      RECT 116 132.9 116.2 133.1 ;
      RECT 116 140.1 116.2 140.3 ;
      RECT 116 147.3 116.2 147.5 ;
      RECT 116 154.5 116.2 154.7 ;
      RECT 116 161.7 116.2 161.9 ;
      RECT 116 168.9 116.2 169.1 ;
      RECT 116 176.1 116.2 176.3 ;
      RECT 116 183.3 116.2 183.5 ;
      RECT 116 190.5 116.2 190.7 ;
      RECT 116 197.7 116.2 197.9 ;
      RECT 116 204.9 116.2 205.1 ;
      RECT 116 212.1 116.2 212.3 ;
      RECT 116 216.6 116.2 216.8 ;
      RECT 116 217.2 116.2 217.4 ;
      RECT 116 217.8 116.2 218 ;
      RECT 116 218.4 116.2 218.6 ;
      RECT 115.5 135.1 115.7 135.3 ;
      RECT 115.5 144.7 115.7 144.9 ;
      RECT 115.5 145.1 115.7 145.3 ;
      RECT 115.5 149.5 115.7 149.7 ;
      RECT 115.5 152.3 115.7 152.5 ;
      RECT 115.5 156.7 115.7 156.9 ;
      RECT 115.5 157.1 115.7 157.3 ;
      RECT 115.5 159.5 115.7 159.7 ;
      RECT 115.5 163.9 115.7 164.1 ;
      RECT 115.5 171.9 115.7 172.1 ;
      RECT 115.5 179.5 115.7 179.7 ;
      RECT 115.5 179.9 115.7 180.1 ;
      RECT 115.5 182.7 115.7 182.9 ;
      RECT 115.5 183.1 115.7 183.3 ;
      RECT 115.1 79.5 115.3 79.7 ;
      RECT 115.1 135.1 115.3 135.3 ;
      RECT 115.1 149.5 115.3 149.7 ;
      RECT 115.1 152.3 115.3 152.5 ;
      RECT 115.1 159.5 115.3 159.7 ;
      RECT 114.7 28.3 114.9 28.5 ;
      RECT 114.7 79.5 114.9 79.7 ;
      RECT 114.7 177.5 114.9 177.7 ;
      RECT 114.7 177.9 114.9 178.1 ;
      RECT 114.7 191.5 114.9 191.7 ;
      RECT 114.7 191.9 114.9 192.1 ;
      RECT 114.3 25.9 114.5 26.1 ;
      RECT 114.3 26.3 114.5 26.5 ;
      RECT 114.3 28.3 114.5 28.5 ;
      RECT 114.3 32.3 114.5 32.5 ;
      RECT 114.3 32.7 114.5 32.9 ;
      RECT 114.3 58.3 114.5 58.5 ;
      RECT 114.3 58.7 114.5 58.9 ;
      RECT 114.3 87.1 114.5 87.3 ;
      RECT 114.3 87.5 114.5 87.7 ;
      RECT 113.8 4 114 4.2 ;
      RECT 113.8 4.6 114 4.8 ;
      RECT 113.8 5.2 114 5.4 ;
      RECT 113.8 5.8 114 6 ;
      RECT 113.8 6.9 114 7.1 ;
      RECT 113.8 14.1 114 14.3 ;
      RECT 113.8 21.3 114 21.5 ;
      RECT 113.8 28.5 114 28.7 ;
      RECT 113.8 35.7 114 35.9 ;
      RECT 113.8 42.9 114 43.1 ;
      RECT 113.8 50.1 114 50.3 ;
      RECT 113.8 57.3 114 57.5 ;
      RECT 113.8 64.5 114 64.7 ;
      RECT 113.8 71.7 114 71.9 ;
      RECT 113.8 78.9 114 79.1 ;
      RECT 113.8 86.1 114 86.3 ;
      RECT 113.8 93.3 114 93.5 ;
      RECT 113.8 100.5 114 100.7 ;
      RECT 113.8 107.7 114 107.9 ;
      RECT 113.8 114.9 114 115.1 ;
      RECT 113.8 122.1 114 122.3 ;
      RECT 113.8 129.3 114 129.5 ;
      RECT 113.8 136.5 114 136.7 ;
      RECT 113.8 143.7 114 143.9 ;
      RECT 113.8 150.9 114 151.1 ;
      RECT 113.8 158.1 114 158.3 ;
      RECT 113.8 165.3 114 165.5 ;
      RECT 113.8 172.5 114 172.7 ;
      RECT 113.8 179.7 114 179.9 ;
      RECT 113.8 186.9 114 187.1 ;
      RECT 113.8 194.1 114 194.3 ;
      RECT 113.8 201.3 114 201.5 ;
      RECT 113.8 208.5 114 208.7 ;
      RECT 113.8 213.6 114 213.8 ;
      RECT 113.8 214.2 114 214.4 ;
      RECT 113.8 214.8 114 215 ;
      RECT 113.8 215.4 114 215.6 ;
      RECT 113.2 4 113.4 4.2 ;
      RECT 113.2 4.6 113.4 4.8 ;
      RECT 113.2 5.2 113.4 5.4 ;
      RECT 113.2 5.8 113.4 6 ;
      RECT 113.2 6.9 113.4 7.1 ;
      RECT 113.2 14.1 113.4 14.3 ;
      RECT 113.2 21.3 113.4 21.5 ;
      RECT 113.2 28.5 113.4 28.7 ;
      RECT 113.2 35.7 113.4 35.9 ;
      RECT 113.2 42.9 113.4 43.1 ;
      RECT 113.2 50.1 113.4 50.3 ;
      RECT 113.2 57.3 113.4 57.5 ;
      RECT 113.2 64.5 113.4 64.7 ;
      RECT 113.2 71.7 113.4 71.9 ;
      RECT 113.2 78.9 113.4 79.1 ;
      RECT 113.2 86.1 113.4 86.3 ;
      RECT 113.2 93.3 113.4 93.5 ;
      RECT 113.2 100.5 113.4 100.7 ;
      RECT 113.2 107.7 113.4 107.9 ;
      RECT 113.2 114.9 113.4 115.1 ;
      RECT 113.2 122.1 113.4 122.3 ;
      RECT 113.2 129.3 113.4 129.5 ;
      RECT 113.2 136.5 113.4 136.7 ;
      RECT 113.2 143.7 113.4 143.9 ;
      RECT 113.2 150.9 113.4 151.1 ;
      RECT 113.2 158.1 113.4 158.3 ;
      RECT 113.2 165.3 113.4 165.5 ;
      RECT 113.2 172.5 113.4 172.7 ;
      RECT 113.2 179.7 113.4 179.9 ;
      RECT 113.2 186.9 113.4 187.1 ;
      RECT 113.2 194.1 113.4 194.3 ;
      RECT 113.2 201.3 113.4 201.5 ;
      RECT 113.2 208.5 113.4 208.7 ;
      RECT 113.2 213.6 113.4 213.8 ;
      RECT 113.2 214.2 113.4 214.4 ;
      RECT 113.2 214.8 113.4 215 ;
      RECT 113.2 215.4 113.4 215.6 ;
      RECT 112.6 4 112.8 4.2 ;
      RECT 112.6 4.6 112.8 4.8 ;
      RECT 112.6 5.2 112.8 5.4 ;
      RECT 112.6 5.8 112.8 6 ;
      RECT 112.6 6.9 112.8 7.1 ;
      RECT 112.6 14.1 112.8 14.3 ;
      RECT 112.6 21.3 112.8 21.5 ;
      RECT 112.6 28.5 112.8 28.7 ;
      RECT 112.6 35.7 112.8 35.9 ;
      RECT 112.6 42.9 112.8 43.1 ;
      RECT 112.6 50.1 112.8 50.3 ;
      RECT 112.6 57.3 112.8 57.5 ;
      RECT 112.6 64.5 112.8 64.7 ;
      RECT 112.6 71.7 112.8 71.9 ;
      RECT 112.6 78.9 112.8 79.1 ;
      RECT 112.6 86.1 112.8 86.3 ;
      RECT 112.6 93.3 112.8 93.5 ;
      RECT 112.6 100.5 112.8 100.7 ;
      RECT 112.6 107.7 112.8 107.9 ;
      RECT 112.6 114.9 112.8 115.1 ;
      RECT 112.6 122.1 112.8 122.3 ;
      RECT 112.6 129.3 112.8 129.5 ;
      RECT 112.6 136.5 112.8 136.7 ;
      RECT 112.6 143.7 112.8 143.9 ;
      RECT 112.6 150.9 112.8 151.1 ;
      RECT 112.6 158.1 112.8 158.3 ;
      RECT 112.6 165.3 112.8 165.5 ;
      RECT 112.6 172.5 112.8 172.7 ;
      RECT 112.6 179.7 112.8 179.9 ;
      RECT 112.6 186.9 112.8 187.1 ;
      RECT 112.6 194.1 112.8 194.3 ;
      RECT 112.6 201.3 112.8 201.5 ;
      RECT 112.6 208.5 112.8 208.7 ;
      RECT 112.6 213.6 112.8 213.8 ;
      RECT 112.6 214.2 112.8 214.4 ;
      RECT 112.6 214.8 112.8 215 ;
      RECT 112.6 215.4 112.8 215.6 ;
      RECT 112 4 112.2 4.2 ;
      RECT 112 4.6 112.2 4.8 ;
      RECT 112 5.2 112.2 5.4 ;
      RECT 112 5.8 112.2 6 ;
      RECT 112 6.9 112.2 7.1 ;
      RECT 112 14.1 112.2 14.3 ;
      RECT 112 21.3 112.2 21.5 ;
      RECT 112 28.5 112.2 28.7 ;
      RECT 112 35.7 112.2 35.9 ;
      RECT 112 42.9 112.2 43.1 ;
      RECT 112 50.1 112.2 50.3 ;
      RECT 112 57.3 112.2 57.5 ;
      RECT 112 64.5 112.2 64.7 ;
      RECT 112 71.7 112.2 71.9 ;
      RECT 112 78.9 112.2 79.1 ;
      RECT 112 86.1 112.2 86.3 ;
      RECT 112 93.3 112.2 93.5 ;
      RECT 112 100.5 112.2 100.7 ;
      RECT 112 107.7 112.2 107.9 ;
      RECT 112 114.9 112.2 115.1 ;
      RECT 112 122.1 112.2 122.3 ;
      RECT 112 129.3 112.2 129.5 ;
      RECT 112 136.5 112.2 136.7 ;
      RECT 112 143.7 112.2 143.9 ;
      RECT 112 150.9 112.2 151.1 ;
      RECT 112 158.1 112.2 158.3 ;
      RECT 112 165.3 112.2 165.5 ;
      RECT 112 172.5 112.2 172.7 ;
      RECT 112 179.7 112.2 179.9 ;
      RECT 112 186.9 112.2 187.1 ;
      RECT 112 194.1 112.2 194.3 ;
      RECT 112 201.3 112.2 201.5 ;
      RECT 112 208.5 112.2 208.7 ;
      RECT 112 213.6 112.2 213.8 ;
      RECT 112 214.2 112.2 214.4 ;
      RECT 112 214.8 112.2 215 ;
      RECT 112 215.4 112.2 215.6 ;
      RECT 111.5 32.3 111.7 32.5 ;
      RECT 111.5 32.7 111.7 32.9 ;
      RECT 111.5 38.7 111.7 38.9 ;
      RECT 111.5 39.1 111.7 39.3 ;
      RECT 111.5 41.9 111.7 42.1 ;
      RECT 111.5 43.5 111.7 43.7 ;
      RECT 111.5 55.9 111.7 56.1 ;
      RECT 111.5 58.3 111.7 58.5 ;
      RECT 111.5 58.7 111.7 58.9 ;
      RECT 111.5 63.1 111.7 63.3 ;
      RECT 111.5 65.9 111.7 66.1 ;
      RECT 111.5 193.1 111.7 193.3 ;
      RECT 111.5 193.5 111.7 193.7 ;
      RECT 111.5 198.3 111.7 198.5 ;
      RECT 111.5 198.7 111.7 198.9 ;
      RECT 111.1 27.1 111.3 27.3 ;
      RECT 111.1 29.9 111.3 30.1 ;
      RECT 111.1 34.3 111.3 34.5 ;
      RECT 111.1 41.9 111.3 42.1 ;
      RECT 111.1 43.5 111.3 43.7 ;
      RECT 111.1 55.9 111.3 56.1 ;
      RECT 111.1 63.1 111.3 63.3 ;
      RECT 111.1 65.9 111.3 66.1 ;
      RECT 111.1 136.3 111.3 136.5 ;
      RECT 111.1 136.7 111.3 136.9 ;
      RECT 111.1 137.9 111.3 138.1 ;
      RECT 111.1 138.3 111.3 138.5 ;
      RECT 110.7 27.1 110.9 27.3 ;
      RECT 110.7 29.9 110.9 30.1 ;
      RECT 110.7 34.3 110.9 34.5 ;
      RECT 110.7 182.3 110.9 182.5 ;
      RECT 110.7 189.5 110.9 189.7 ;
      RECT 110.3 15.5 110.5 15.7 ;
      RECT 110.3 19.5 110.5 19.7 ;
      RECT 110.3 77.5 110.5 77.7 ;
      RECT 110.3 80.3 110.5 80.5 ;
      RECT 110.3 137.1 110.5 137.3 ;
      RECT 110.3 137.5 110.5 137.7 ;
      RECT 110.3 138.3 110.5 138.5 ;
      RECT 110.3 138.7 110.5 138.9 ;
      RECT 109.9 15.5 110.1 15.7 ;
      RECT 109.9 19.5 110.1 19.7 ;
      RECT 109.9 73.1 110.1 73.3 ;
      RECT 109.9 77.5 110.1 77.7 ;
      RECT 109.9 80.3 110.1 80.5 ;
      RECT 109.9 84.7 110.1 84.9 ;
      RECT 109.5 73.1 109.7 73.3 ;
      RECT 109.5 84.7 109.7 84.9 ;
      RECT 109.5 123.9 109.7 124.1 ;
      RECT 109.5 124.3 109.7 124.5 ;
      RECT 109.5 152.7 109.7 152.9 ;
      RECT 109.5 153.1 109.7 153.3 ;
      RECT 109.5 174.3 109.7 174.5 ;
      RECT 109.5 174.7 109.7 174.9 ;
      RECT 108.7 61.5 108.9 61.7 ;
      RECT 108.7 61.9 108.9 62.1 ;
      RECT 108.7 88.3 108.9 88.5 ;
      RECT 108.7 88.7 108.9 88.9 ;
      RECT 108.7 178.3 108.9 178.5 ;
      RECT 108.7 181.1 108.9 181.3 ;
      RECT 108.3 173.9 108.5 174.1 ;
      RECT 108.3 178.3 108.5 178.5 ;
      RECT 108.3 181.1 108.5 181.3 ;
      RECT 107.9 159.9 108.1 160.1 ;
      RECT 107.9 164.3 108.1 164.5 ;
      RECT 107.9 173.9 108.1 174.1 ;
      RECT 107.9 201.5 108.1 201.7 ;
      RECT 107.9 205.9 108.1 206.1 ;
      RECT 107.9 206.3 108.1 206.5 ;
      RECT 107.5 181.1 107.7 181.3 ;
      RECT 107.5 188.3 107.7 188.5 ;
      RECT 107.5 201.5 107.7 201.7 ;
      RECT 107.1 181.1 107.3 181.3 ;
      RECT 107.1 185.5 107.3 185.7 ;
      RECT 107.1 188.3 107.3 188.5 ;
      RECT 107.1 192.7 107.3 192.9 ;
      RECT 107.1 199.5 107.3 199.7 ;
      RECT 107.1 199.9 107.3 200.1 ;
      RECT 107.1 202.7 107.3 202.9 ;
      RECT 107.1 207.1 107.3 207.3 ;
      RECT 107.1 209.9 107.3 210.1 ;
      RECT 106.7 116.3 106.9 116.5 ;
      RECT 106.7 123.5 106.9 123.7 ;
      RECT 106.7 130.7 106.9 130.9 ;
      RECT 106.7 135.1 106.9 135.3 ;
      RECT 106.7 139.1 106.9 139.3 ;
      RECT 106.7 142.3 106.9 142.5 ;
      RECT 106.7 144.3 106.9 144.5 ;
      RECT 106.7 185.5 106.9 185.7 ;
      RECT 106.7 192.7 106.9 192.9 ;
      RECT 106.7 202.7 106.9 202.9 ;
      RECT 106.7 207.1 106.9 207.3 ;
      RECT 106.7 209.9 106.9 210.1 ;
      RECT 106.3 113.9 106.5 114.1 ;
      RECT 106.3 116.3 106.5 116.5 ;
      RECT 106.3 123.5 106.5 123.7 ;
      RECT 106.3 130.7 106.5 130.9 ;
      RECT 106.3 135.1 106.5 135.3 ;
      RECT 106.3 139.1 106.5 139.3 ;
      RECT 106.3 142.3 106.5 142.5 ;
      RECT 106.3 144.3 106.5 144.5 ;
      RECT 105.9 113.9 106.1 114.1 ;
      RECT 103.9 37.5 104.1 37.7 ;
      RECT 103.9 37.9 104.1 38.1 ;
      RECT 103.9 38.7 104.1 38.9 ;
      RECT 103.9 39.1 104.1 39.3 ;
      RECT 103.9 166.7 104.1 166.9 ;
      RECT 103.5 163.9 103.7 164.1 ;
      RECT 103.5 166.7 103.7 166.9 ;
      RECT 103.1 27.1 103.3 27.3 ;
      RECT 103.1 163.9 103.3 164.1 ;
      RECT 103.1 188.3 103.3 188.5 ;
      RECT 103.1 196.3 103.3 196.5 ;
      RECT 102.7 23.1 102.9 23.3 ;
      RECT 102.7 27.1 102.9 27.3 ;
      RECT 102.3 23.1 102.5 23.3 ;
      RECT 102.3 128.3 102.5 128.5 ;
      RECT 102.3 134.7 102.5 134.9 ;
      RECT 101.9 69.9 102.1 70.1 ;
      RECT 101.9 128.3 102.1 128.5 ;
      RECT 101.9 134.7 102.1 134.9 ;
      RECT 101.5 69.9 101.7 70.1 ;
      RECT 101.5 126.7 101.7 126.9 ;
      RECT 101.5 127.1 101.7 127.3 ;
      RECT 101.1 63.1 101.3 63.3 ;
      RECT 100.7 59.9 100.9 60.1 ;
      RECT 100.7 63.1 100.9 63.3 ;
      RECT 100.3 59.9 100.5 60.1 ;
      RECT 99.9 62.7 100.1 62.9 ;
      RECT 99.9 63.1 100.1 63.3 ;
      RECT 99.9 66.7 100.1 66.9 ;
      RECT 99.9 67.1 100.1 67.3 ;
      RECT 99.9 67.9 100.1 68.1 ;
      RECT 99.9 68.3 100.1 68.5 ;
      RECT 99.1 116.7 99.3 116.9 ;
      RECT 99.1 117.1 99.3 117.3 ;
      RECT 99.1 117.5 99.3 117.7 ;
      RECT 99.1 117.9 99.3 118.1 ;
      RECT 99.1 199.5 99.3 199.7 ;
      RECT 99.1 203.1 99.3 203.3 ;
      RECT 98.3 115.1 98.5 115.3 ;
      RECT 98.3 141.9 98.5 142.1 ;
      RECT 97.5 91.9 97.7 92.1 ;
      RECT 97.5 94.3 97.7 94.5 ;
      RECT 97.5 101.9 97.7 102.1 ;
      RECT 97.5 106.7 97.7 106.9 ;
      RECT 97.5 109.1 97.7 109.3 ;
      RECT 97.5 113.9 97.7 114.1 ;
      RECT 97.5 144.3 97.7 144.5 ;
      RECT 97.5 144.7 97.7 144.9 ;
      RECT 97.5 178.7 97.7 178.9 ;
      RECT 97.5 179.1 97.7 179.3 ;
      RECT 97.1 67.9 97.3 68.1 ;
      RECT 97.1 68.3 97.3 68.5 ;
      RECT 97.1 76.3 97.3 76.5 ;
      RECT 97.1 76.7 97.3 76.9 ;
      RECT 97.1 82.7 97.3 82.9 ;
      RECT 97.1 83.1 97.3 83.3 ;
      RECT 97.1 91.9 97.3 92.1 ;
      RECT 97.1 94.3 97.3 94.5 ;
      RECT 97.1 101.9 97.3 102.1 ;
      RECT 97.1 106.7 97.3 106.9 ;
      RECT 97.1 109.1 97.3 109.3 ;
      RECT 97.1 113.9 97.3 114.1 ;
      RECT 96.7 120.7 96.9 120.9 ;
      RECT 96.7 121.1 96.9 121.3 ;
      RECT 96.7 123.5 96.9 123.7 ;
      RECT 96.7 123.9 96.9 124.1 ;
      RECT 96.3 75.9 96.5 76.1 ;
      RECT 96.3 76.3 96.5 76.5 ;
      RECT 96.3 78.7 96.5 78.9 ;
      RECT 96.3 79.1 96.5 79.3 ;
      RECT 96.3 86.7 96.5 86.9 ;
      RECT 96.3 87.1 96.5 87.3 ;
      RECT 96.3 203.5 96.5 203.7 ;
      RECT 96.3 203.9 96.5 204.1 ;
      RECT 96.3 204.7 96.5 204.9 ;
      RECT 96.3 205.1 96.5 205.3 ;
      RECT 95.9 119.9 96.1 120.1 ;
      RECT 95.9 120.3 96.1 120.5 ;
      RECT 92.7 133.9 92.9 134.1 ;
      RECT 92.7 134.3 92.9 134.5 ;
      RECT 92.7 145.9 92.9 146.1 ;
      RECT 92.7 147.5 92.9 147.7 ;
      RECT 91.5 29.1 91.7 29.3 ;
      RECT 91.5 29.5 91.7 29.7 ;
      RECT 91.5 42.7 91.7 42.9 ;
      RECT 91.5 43.1 91.7 43.3 ;
      RECT 91.5 77.1 91.7 77.3 ;
      RECT 91.1 59.9 91.3 60.1 ;
      RECT 91.1 60.3 91.3 60.5 ;
      RECT 91.1 77.1 91.3 77.3 ;
      RECT 90.3 27.1 90.5 27.3 ;
      RECT 90.3 27.5 90.5 27.7 ;
      RECT 90.3 28.3 90.5 28.5 ;
      RECT 90.3 28.7 90.5 28.9 ;
      RECT 90.3 139.5 90.5 139.7 ;
      RECT 90.3 141.9 90.5 142.1 ;
      RECT 89.9 139.5 90.1 139.7 ;
      RECT 89.9 141.9 90.1 142.1 ;
      RECT 89.5 27.5 89.7 27.7 ;
      RECT 89.5 44.3 89.7 44.5 ;
      RECT 89.5 44.7 89.7 44.9 ;
      RECT 89.5 191.5 89.7 191.7 ;
      RECT 89.5 191.9 89.7 192.1 ;
      RECT 89.5 210.3 89.7 210.5 ;
      RECT 89.5 210.7 89.7 210.9 ;
      RECT 89.1 27.5 89.3 27.7 ;
      RECT 89.1 37.1 89.3 37.3 ;
      RECT 89.1 37.5 89.3 37.7 ;
      RECT 89.1 43.5 89.3 43.7 ;
      RECT 89.1 43.9 89.3 44.1 ;
      RECT 88.7 104.3 88.9 104.5 ;
      RECT 88.7 104.7 88.9 104.9 ;
      RECT 88.7 111.9 88.9 112.1 ;
      RECT 88.7 112.3 88.9 112.5 ;
      RECT 88.7 127.9 88.9 128.1 ;
      RECT 88.7 133.5 88.9 133.7 ;
      RECT 88.3 24.3 88.5 24.5 ;
      RECT 88.3 24.7 88.5 24.9 ;
      RECT 88.3 35.9 88.5 36.1 ;
      RECT 88.3 36.3 88.5 36.5 ;
      RECT 88.3 37.1 88.5 37.3 ;
      RECT 88.3 37.5 88.5 37.7 ;
      RECT 88.3 41.5 88.5 41.7 ;
      RECT 88.3 41.9 88.5 42.1 ;
      RECT 88.3 67.5 88.5 67.7 ;
      RECT 88.3 67.9 88.5 68.1 ;
      RECT 88.3 69.1 88.5 69.3 ;
      RECT 88.3 69.5 88.5 69.7 ;
      RECT 88.3 120.7 88.5 120.9 ;
      RECT 88.3 121.1 88.5 121.3 ;
      RECT 88.3 127.9 88.5 128.1 ;
      RECT 88.3 133.5 88.5 133.7 ;
      RECT 88.3 145.5 88.5 145.7 ;
      RECT 88.3 145.9 88.5 146.1 ;
      RECT 88.3 169.1 88.5 169.3 ;
      RECT 88.3 169.5 88.5 169.7 ;
      RECT 87.8 1 88 1.2 ;
      RECT 87.8 1.6 88 1.8 ;
      RECT 87.8 2.2 88 2.4 ;
      RECT 87.8 2.8 88 3 ;
      RECT 87.8 10.5 88 10.7 ;
      RECT 87.8 17.7 88 17.9 ;
      RECT 87.8 24.9 88 25.1 ;
      RECT 87.8 32.1 88 32.3 ;
      RECT 87.8 39.3 88 39.5 ;
      RECT 87.8 46.5 88 46.7 ;
      RECT 87.8 53.7 88 53.9 ;
      RECT 87.8 60.9 88 61.1 ;
      RECT 87.8 68.1 88 68.3 ;
      RECT 87.8 75.3 88 75.5 ;
      RECT 87.8 82.5 88 82.7 ;
      RECT 87.8 89.7 88 89.9 ;
      RECT 87.8 96.9 88 97.1 ;
      RECT 87.8 104.1 88 104.3 ;
      RECT 87.8 111.3 88 111.5 ;
      RECT 87.8 118.5 88 118.7 ;
      RECT 87.8 125.7 88 125.9 ;
      RECT 87.8 132.9 88 133.1 ;
      RECT 87.8 140.1 88 140.3 ;
      RECT 87.8 147.3 88 147.5 ;
      RECT 87.8 154.5 88 154.7 ;
      RECT 87.8 161.7 88 161.9 ;
      RECT 87.8 168.9 88 169.1 ;
      RECT 87.8 176.1 88 176.3 ;
      RECT 87.8 183.3 88 183.5 ;
      RECT 87.8 190.5 88 190.7 ;
      RECT 87.8 197.7 88 197.9 ;
      RECT 87.8 204.9 88 205.1 ;
      RECT 87.8 212.1 88 212.3 ;
      RECT 87.8 216.6 88 216.8 ;
      RECT 87.8 217.2 88 217.4 ;
      RECT 87.8 217.8 88 218 ;
      RECT 87.8 218.4 88 218.6 ;
      RECT 87.2 1 87.4 1.2 ;
      RECT 87.2 1.6 87.4 1.8 ;
      RECT 87.2 2.2 87.4 2.4 ;
      RECT 87.2 2.8 87.4 3 ;
      RECT 87.2 10.5 87.4 10.7 ;
      RECT 87.2 17.7 87.4 17.9 ;
      RECT 87.2 24.9 87.4 25.1 ;
      RECT 87.2 32.1 87.4 32.3 ;
      RECT 87.2 39.3 87.4 39.5 ;
      RECT 87.2 46.5 87.4 46.7 ;
      RECT 87.2 53.7 87.4 53.9 ;
      RECT 87.2 60.9 87.4 61.1 ;
      RECT 87.2 68.1 87.4 68.3 ;
      RECT 87.2 75.3 87.4 75.5 ;
      RECT 87.2 82.5 87.4 82.7 ;
      RECT 87.2 89.7 87.4 89.9 ;
      RECT 87.2 96.9 87.4 97.1 ;
      RECT 87.2 104.1 87.4 104.3 ;
      RECT 87.2 111.3 87.4 111.5 ;
      RECT 87.2 118.5 87.4 118.7 ;
      RECT 87.2 125.7 87.4 125.9 ;
      RECT 87.2 132.9 87.4 133.1 ;
      RECT 87.2 140.1 87.4 140.3 ;
      RECT 87.2 147.3 87.4 147.5 ;
      RECT 87.2 154.5 87.4 154.7 ;
      RECT 87.2 161.7 87.4 161.9 ;
      RECT 87.2 168.9 87.4 169.1 ;
      RECT 87.2 176.1 87.4 176.3 ;
      RECT 87.2 183.3 87.4 183.5 ;
      RECT 87.2 190.5 87.4 190.7 ;
      RECT 87.2 197.7 87.4 197.9 ;
      RECT 87.2 204.9 87.4 205.1 ;
      RECT 87.2 212.1 87.4 212.3 ;
      RECT 87.2 216.6 87.4 216.8 ;
      RECT 87.2 217.2 87.4 217.4 ;
      RECT 87.2 217.8 87.4 218 ;
      RECT 87.2 218.4 87.4 218.6 ;
      RECT 86.6 1 86.8 1.2 ;
      RECT 86.6 1.6 86.8 1.8 ;
      RECT 86.6 2.2 86.8 2.4 ;
      RECT 86.6 2.8 86.8 3 ;
      RECT 86.6 10.5 86.8 10.7 ;
      RECT 86.6 17.7 86.8 17.9 ;
      RECT 86.6 24.9 86.8 25.1 ;
      RECT 86.6 32.1 86.8 32.3 ;
      RECT 86.6 39.3 86.8 39.5 ;
      RECT 86.6 46.5 86.8 46.7 ;
      RECT 86.6 53.7 86.8 53.9 ;
      RECT 86.6 60.9 86.8 61.1 ;
      RECT 86.6 68.1 86.8 68.3 ;
      RECT 86.6 75.3 86.8 75.5 ;
      RECT 86.6 82.5 86.8 82.7 ;
      RECT 86.6 89.7 86.8 89.9 ;
      RECT 86.6 96.9 86.8 97.1 ;
      RECT 86.6 104.1 86.8 104.3 ;
      RECT 86.6 111.3 86.8 111.5 ;
      RECT 86.6 118.5 86.8 118.7 ;
      RECT 86.6 125.7 86.8 125.9 ;
      RECT 86.6 132.9 86.8 133.1 ;
      RECT 86.6 140.1 86.8 140.3 ;
      RECT 86.6 147.3 86.8 147.5 ;
      RECT 86.6 154.5 86.8 154.7 ;
      RECT 86.6 161.7 86.8 161.9 ;
      RECT 86.6 168.9 86.8 169.1 ;
      RECT 86.6 176.1 86.8 176.3 ;
      RECT 86.6 183.3 86.8 183.5 ;
      RECT 86.6 190.5 86.8 190.7 ;
      RECT 86.6 197.7 86.8 197.9 ;
      RECT 86.6 204.9 86.8 205.1 ;
      RECT 86.6 212.1 86.8 212.3 ;
      RECT 86.6 216.6 86.8 216.8 ;
      RECT 86.6 217.2 86.8 217.4 ;
      RECT 86.6 217.8 86.8 218 ;
      RECT 86.6 218.4 86.8 218.6 ;
      RECT 86 1 86.2 1.2 ;
      RECT 86 1.6 86.2 1.8 ;
      RECT 86 2.2 86.2 2.4 ;
      RECT 86 2.8 86.2 3 ;
      RECT 86 10.5 86.2 10.7 ;
      RECT 86 17.7 86.2 17.9 ;
      RECT 86 24.9 86.2 25.1 ;
      RECT 86 32.1 86.2 32.3 ;
      RECT 86 39.3 86.2 39.5 ;
      RECT 86 46.5 86.2 46.7 ;
      RECT 86 53.7 86.2 53.9 ;
      RECT 86 60.9 86.2 61.1 ;
      RECT 86 68.1 86.2 68.3 ;
      RECT 86 75.3 86.2 75.5 ;
      RECT 86 82.5 86.2 82.7 ;
      RECT 86 89.7 86.2 89.9 ;
      RECT 86 96.9 86.2 97.1 ;
      RECT 86 104.1 86.2 104.3 ;
      RECT 86 111.3 86.2 111.5 ;
      RECT 86 118.5 86.2 118.7 ;
      RECT 86 125.7 86.2 125.9 ;
      RECT 86 132.9 86.2 133.1 ;
      RECT 86 140.1 86.2 140.3 ;
      RECT 86 147.3 86.2 147.5 ;
      RECT 86 154.5 86.2 154.7 ;
      RECT 86 161.7 86.2 161.9 ;
      RECT 86 168.9 86.2 169.1 ;
      RECT 86 176.1 86.2 176.3 ;
      RECT 86 183.3 86.2 183.5 ;
      RECT 86 190.5 86.2 190.7 ;
      RECT 86 197.7 86.2 197.9 ;
      RECT 86 204.9 86.2 205.1 ;
      RECT 86 212.1 86.2 212.3 ;
      RECT 86 216.6 86.2 216.8 ;
      RECT 86 217.2 86.2 217.4 ;
      RECT 86 217.8 86.2 218 ;
      RECT 86 218.4 86.2 218.6 ;
      RECT 85.5 185.5 85.7 185.7 ;
      RECT 85.5 185.9 85.7 186.1 ;
      RECT 85.5 191.1 85.7 191.3 ;
      RECT 85.5 191.5 85.7 191.7 ;
      RECT 84.7 73.1 84.9 73.3 ;
      RECT 84.7 111.9 84.9 112.1 ;
      RECT 84.7 112.3 84.9 112.5 ;
      RECT 84.7 121.5 84.9 121.7 ;
      RECT 84.7 121.9 84.9 122.1 ;
      RECT 84.7 177.1 84.9 177.3 ;
      RECT 84.7 177.5 84.9 177.7 ;
      RECT 84.7 186.7 84.9 186.9 ;
      RECT 84.7 187.1 84.9 187.3 ;
      RECT 84.7 193.5 84.9 193.7 ;
      RECT 84.7 193.9 84.9 194.1 ;
      RECT 84.3 70.7 84.5 70.9 ;
      RECT 84.3 71.1 84.5 71.3 ;
      RECT 84.3 73.1 84.5 73.3 ;
      RECT 84.3 77.5 84.5 77.7 ;
      RECT 84.3 77.9 84.5 78.1 ;
      RECT 84.3 84.3 84.5 84.5 ;
      RECT 84.3 84.7 84.5 84.9 ;
      RECT 84.3 102.3 84.5 102.5 ;
      RECT 84.3 102.7 84.5 102.9 ;
      RECT 84.3 107.9 84.5 108.1 ;
      RECT 84.3 108.3 84.5 108.5 ;
      RECT 84.3 113.9 84.5 114.1 ;
      RECT 84.3 114.3 84.5 114.5 ;
      RECT 84.3 116.7 84.5 116.9 ;
      RECT 84.3 117.1 84.5 117.3 ;
      RECT 83.8 4 84 4.2 ;
      RECT 83.8 4.6 84 4.8 ;
      RECT 83.8 5.2 84 5.4 ;
      RECT 83.8 5.8 84 6 ;
      RECT 83.8 6.9 84 7.1 ;
      RECT 83.8 14.1 84 14.3 ;
      RECT 83.8 21.3 84 21.5 ;
      RECT 83.8 28.5 84 28.7 ;
      RECT 83.8 35.7 84 35.9 ;
      RECT 83.8 42.9 84 43.1 ;
      RECT 83.8 50.1 84 50.3 ;
      RECT 83.8 57.3 84 57.5 ;
      RECT 83.8 64.5 84 64.7 ;
      RECT 83.8 71.7 84 71.9 ;
      RECT 83.8 78.9 84 79.1 ;
      RECT 83.8 86.1 84 86.3 ;
      RECT 83.8 93.3 84 93.5 ;
      RECT 83.8 100.5 84 100.7 ;
      RECT 83.8 107.7 84 107.9 ;
      RECT 83.8 114.9 84 115.1 ;
      RECT 83.8 122.1 84 122.3 ;
      RECT 83.8 129.3 84 129.5 ;
      RECT 83.8 136.5 84 136.7 ;
      RECT 83.8 143.7 84 143.9 ;
      RECT 83.8 150.9 84 151.1 ;
      RECT 83.8 158.1 84 158.3 ;
      RECT 83.8 165.3 84 165.5 ;
      RECT 83.8 172.5 84 172.7 ;
      RECT 83.8 179.7 84 179.9 ;
      RECT 83.8 186.9 84 187.1 ;
      RECT 83.8 194.1 84 194.3 ;
      RECT 83.8 201.3 84 201.5 ;
      RECT 83.8 208.5 84 208.7 ;
      RECT 83.8 213.6 84 213.8 ;
      RECT 83.8 214.2 84 214.4 ;
      RECT 83.8 214.8 84 215 ;
      RECT 83.8 215.4 84 215.6 ;
      RECT 83.2 4 83.4 4.2 ;
      RECT 83.2 4.6 83.4 4.8 ;
      RECT 83.2 5.2 83.4 5.4 ;
      RECT 83.2 5.8 83.4 6 ;
      RECT 83.2 6.9 83.4 7.1 ;
      RECT 83.2 14.1 83.4 14.3 ;
      RECT 83.2 21.3 83.4 21.5 ;
      RECT 83.2 28.5 83.4 28.7 ;
      RECT 83.2 35.7 83.4 35.9 ;
      RECT 83.2 42.9 83.4 43.1 ;
      RECT 83.2 50.1 83.4 50.3 ;
      RECT 83.2 57.3 83.4 57.5 ;
      RECT 83.2 64.5 83.4 64.7 ;
      RECT 83.2 71.7 83.4 71.9 ;
      RECT 83.2 78.9 83.4 79.1 ;
      RECT 83.2 86.1 83.4 86.3 ;
      RECT 83.2 93.3 83.4 93.5 ;
      RECT 83.2 100.5 83.4 100.7 ;
      RECT 83.2 107.7 83.4 107.9 ;
      RECT 83.2 114.9 83.4 115.1 ;
      RECT 83.2 122.1 83.4 122.3 ;
      RECT 83.2 129.3 83.4 129.5 ;
      RECT 83.2 136.5 83.4 136.7 ;
      RECT 83.2 143.7 83.4 143.9 ;
      RECT 83.2 150.9 83.4 151.1 ;
      RECT 83.2 158.1 83.4 158.3 ;
      RECT 83.2 165.3 83.4 165.5 ;
      RECT 83.2 172.5 83.4 172.7 ;
      RECT 83.2 179.7 83.4 179.9 ;
      RECT 83.2 186.9 83.4 187.1 ;
      RECT 83.2 194.1 83.4 194.3 ;
      RECT 83.2 201.3 83.4 201.5 ;
      RECT 83.2 208.5 83.4 208.7 ;
      RECT 83.2 213.6 83.4 213.8 ;
      RECT 83.2 214.2 83.4 214.4 ;
      RECT 83.2 214.8 83.4 215 ;
      RECT 83.2 215.4 83.4 215.6 ;
      RECT 82.6 4 82.8 4.2 ;
      RECT 82.6 4.6 82.8 4.8 ;
      RECT 82.6 5.2 82.8 5.4 ;
      RECT 82.6 5.8 82.8 6 ;
      RECT 82.6 6.9 82.8 7.1 ;
      RECT 82.6 14.1 82.8 14.3 ;
      RECT 82.6 21.3 82.8 21.5 ;
      RECT 82.6 28.5 82.8 28.7 ;
      RECT 82.6 35.7 82.8 35.9 ;
      RECT 82.6 42.9 82.8 43.1 ;
      RECT 82.6 50.1 82.8 50.3 ;
      RECT 82.6 57.3 82.8 57.5 ;
      RECT 82.6 64.5 82.8 64.7 ;
      RECT 82.6 71.7 82.8 71.9 ;
      RECT 82.6 78.9 82.8 79.1 ;
      RECT 82.6 86.1 82.8 86.3 ;
      RECT 82.6 93.3 82.8 93.5 ;
      RECT 82.6 100.5 82.8 100.7 ;
      RECT 82.6 107.7 82.8 107.9 ;
      RECT 82.6 114.9 82.8 115.1 ;
      RECT 82.6 122.1 82.8 122.3 ;
      RECT 82.6 129.3 82.8 129.5 ;
      RECT 82.6 136.5 82.8 136.7 ;
      RECT 82.6 143.7 82.8 143.9 ;
      RECT 82.6 150.9 82.8 151.1 ;
      RECT 82.6 158.1 82.8 158.3 ;
      RECT 82.6 165.3 82.8 165.5 ;
      RECT 82.6 172.5 82.8 172.7 ;
      RECT 82.6 179.7 82.8 179.9 ;
      RECT 82.6 186.9 82.8 187.1 ;
      RECT 82.6 194.1 82.8 194.3 ;
      RECT 82.6 201.3 82.8 201.5 ;
      RECT 82.6 208.5 82.8 208.7 ;
      RECT 82.6 213.6 82.8 213.8 ;
      RECT 82.6 214.2 82.8 214.4 ;
      RECT 82.6 214.8 82.8 215 ;
      RECT 82.6 215.4 82.8 215.6 ;
      RECT 82 4 82.2 4.2 ;
      RECT 82 4.6 82.2 4.8 ;
      RECT 82 5.2 82.2 5.4 ;
      RECT 82 5.8 82.2 6 ;
      RECT 82 6.9 82.2 7.1 ;
      RECT 82 14.1 82.2 14.3 ;
      RECT 82 21.3 82.2 21.5 ;
      RECT 82 28.5 82.2 28.7 ;
      RECT 82 35.7 82.2 35.9 ;
      RECT 82 42.9 82.2 43.1 ;
      RECT 82 50.1 82.2 50.3 ;
      RECT 82 57.3 82.2 57.5 ;
      RECT 82 64.5 82.2 64.7 ;
      RECT 82 71.7 82.2 71.9 ;
      RECT 82 78.9 82.2 79.1 ;
      RECT 82 86.1 82.2 86.3 ;
      RECT 82 93.3 82.2 93.5 ;
      RECT 82 100.5 82.2 100.7 ;
      RECT 82 107.7 82.2 107.9 ;
      RECT 82 114.9 82.2 115.1 ;
      RECT 82 122.1 82.2 122.3 ;
      RECT 82 129.3 82.2 129.5 ;
      RECT 82 136.5 82.2 136.7 ;
      RECT 82 143.7 82.2 143.9 ;
      RECT 82 150.9 82.2 151.1 ;
      RECT 82 158.1 82.2 158.3 ;
      RECT 82 165.3 82.2 165.5 ;
      RECT 82 172.5 82.2 172.7 ;
      RECT 82 179.7 82.2 179.9 ;
      RECT 82 186.9 82.2 187.1 ;
      RECT 82 194.1 82.2 194.3 ;
      RECT 82 201.3 82.2 201.5 ;
      RECT 82 208.5 82.2 208.7 ;
      RECT 82 213.6 82.2 213.8 ;
      RECT 82 214.2 82.2 214.4 ;
      RECT 82 214.8 82.2 215 ;
      RECT 82 215.4 82.2 215.6 ;
      RECT 81.5 113.9 81.7 114.1 ;
      RECT 81.5 114.3 81.7 114.5 ;
      RECT 81.5 123.1 81.7 123.3 ;
      RECT 81.5 123.5 81.7 123.7 ;
      RECT 81.1 193.5 81.3 193.7 ;
      RECT 81.1 193.9 81.3 194.1 ;
      RECT 81.1 194.7 81.3 194.9 ;
      RECT 81.1 195.1 81.3 195.3 ;
      RECT 80.7 120.3 80.9 120.5 ;
      RECT 80.7 120.7 80.9 120.9 ;
      RECT 80.7 149.1 80.9 149.3 ;
      RECT 80.7 149.5 80.9 149.7 ;
      RECT 79.1 71.9 79.3 72.1 ;
      RECT 79.1 72.3 79.3 72.5 ;
      RECT 79.1 77.5 79.3 77.7 ;
      RECT 79.1 77.9 79.3 78.1 ;
      RECT 79.1 167.1 79.3 167.3 ;
      RECT 79.1 167.9 79.3 168.1 ;
      RECT 77.9 130.7 78.1 130.9 ;
      RECT 77.9 133.5 78.1 133.7 ;
      RECT 77.9 152.3 78.1 152.5 ;
      RECT 77.5 130.7 77.7 130.9 ;
      RECT 77.5 133.5 77.7 133.7 ;
      RECT 77.5 152.3 77.7 152.5 ;
      RECT 77.5 159.9 77.7 160.1 ;
      RECT 77.5 160.3 77.7 160.5 ;
      RECT 77.5 163.9 77.7 164.1 ;
      RECT 77.5 166.7 77.7 166.9 ;
      RECT 77.5 171.1 77.7 171.3 ;
      RECT 77.1 163.9 77.3 164.1 ;
      RECT 77.1 166.7 77.3 166.9 ;
      RECT 77.1 171.1 77.3 171.3 ;
      RECT 75.5 28.7 75.7 28.9 ;
      RECT 75.1 13.9 75.3 14.1 ;
      RECT 75.1 14.3 75.3 14.5 ;
      RECT 75.1 20.7 75.3 20.9 ;
      RECT 75.1 21.1 75.3 21.3 ;
      RECT 75.1 28.7 75.3 28.9 ;
      RECT 75.1 39.1 75.3 39.3 ;
      RECT 75.1 39.5 75.3 39.7 ;
      RECT 75.1 65.9 75.3 66.1 ;
      RECT 75.1 73.1 75.3 73.3 ;
      RECT 75.1 88.7 75.3 88.9 ;
      RECT 74.7 63.1 74.9 63.3 ;
      RECT 74.7 65.9 74.9 66.1 ;
      RECT 74.7 70.3 74.9 70.5 ;
      RECT 74.7 73.1 74.9 73.3 ;
      RECT 74.7 84.7 74.9 84.9 ;
      RECT 74.7 85.1 74.9 85.3 ;
      RECT 74.7 88.7 74.9 88.9 ;
      RECT 74.7 91.9 74.9 92.1 ;
      RECT 74.7 99.1 74.9 99.3 ;
      RECT 74.3 63.1 74.5 63.3 ;
      RECT 74.3 70.3 74.5 70.5 ;
      RECT 74.3 91.9 74.5 92.1 ;
      RECT 74.3 99.1 74.5 99.3 ;
      RECT 73.1 132.7 73.3 132.9 ;
      RECT 73.1 133.1 73.3 133.3 ;
      RECT 73.1 153.9 73.3 154.1 ;
      RECT 73.1 154.3 73.3 154.5 ;
      RECT 70.7 130.7 70.9 130.9 ;
      RECT 70.3 128.3 70.5 128.5 ;
      RECT 70.3 130.7 70.5 130.9 ;
      RECT 69.9 128.3 70.1 128.5 ;
      RECT 68.7 79.9 68.9 80.1 ;
      RECT 68.7 80.3 68.9 80.5 ;
      RECT 68.7 89.9 68.9 90.1 ;
      RECT 68.7 90.3 68.9 90.5 ;
      RECT 68.7 187.5 68.9 187.7 ;
      RECT 68.7 187.9 68.9 188.1 ;
      RECT 68.7 191.9 68.9 192.1 ;
      RECT 68.7 192.3 68.9 192.5 ;
      RECT 67.1 183.5 67.3 183.7 ;
      RECT 67.1 183.9 67.3 184.1 ;
      RECT 67.1 189.9 67.3 190.1 ;
      RECT 67.1 190.3 67.3 190.5 ;
      RECT 67.1 194.3 67.3 194.5 ;
      RECT 67.1 194.7 67.3 194.9 ;
      RECT 66.7 105.9 66.9 106.1 ;
      RECT 66.7 106.3 66.9 106.5 ;
      RECT 66.7 125.1 66.9 125.3 ;
      RECT 66.7 125.5 66.9 125.7 ;
      RECT 66.3 129.5 66.5 129.7 ;
      RECT 66.3 155.5 66.5 155.7 ;
      RECT 66.3 155.9 66.5 156.1 ;
      RECT 66.3 176.3 66.5 176.5 ;
      RECT 66.3 176.7 66.5 176.9 ;
      RECT 66.3 189.9 66.5 190.1 ;
      RECT 66.3 190.3 66.5 190.5 ;
      RECT 65.1 63.1 65.3 63.3 ;
      RECT 65.1 143.5 65.3 143.7 ;
      RECT 65.1 143.9 65.3 144.1 ;
      RECT 65.1 159.5 65.3 159.7 ;
      RECT 65.1 159.9 65.3 160.1 ;
      RECT 64.7 51.5 64.9 51.7 ;
      RECT 64.7 63.1 64.9 63.3 ;
      RECT 64.7 182.3 64.9 182.5 ;
      RECT 64.7 182.7 64.9 182.9 ;
      RECT 64.7 189.9 64.9 190.1 ;
      RECT 64.7 190.3 64.9 190.5 ;
      RECT 64.3 51.5 64.5 51.7 ;
      RECT 64.3 189.1 64.5 189.3 ;
      RECT 63.9 145.1 64.1 145.3 ;
      RECT 63.9 145.5 64.1 145.7 ;
      RECT 63.9 146.7 64.1 146.9 ;
      RECT 63.9 147.1 64.1 147.3 ;
      RECT 63.9 160.3 64.1 160.5 ;
      RECT 63.9 160.7 64.1 160.9 ;
      RECT 63.9 189.1 64.1 189.3 ;
      RECT 63.9 193.1 64.1 193.3 ;
      RECT 63.9 193.5 64.1 193.7 ;
      RECT 63.1 77.5 63.3 77.7 ;
      RECT 63.1 77.9 63.3 78.1 ;
      RECT 63.1 86.3 63.3 86.5 ;
      RECT 63.1 86.7 63.3 86.9 ;
      RECT 62.7 71.9 62.9 72.1 ;
      RECT 62.7 72.3 62.9 72.5 ;
      RECT 62.7 74.3 62.9 74.5 ;
      RECT 62.7 74.7 62.9 74.9 ;
      RECT 61.5 91.9 61.7 92.1 ;
      RECT 61.5 189.5 61.7 189.7 ;
      RECT 61.5 189.9 61.7 190.1 ;
      RECT 61.5 195.5 61.7 195.7 ;
      RECT 61.5 195.9 61.7 196.1 ;
      RECT 61.1 88.3 61.3 88.5 ;
      RECT 61.1 88.7 61.3 88.9 ;
      RECT 61.1 91.9 61.3 92.1 ;
      RECT 61.1 99.1 61.3 99.3 ;
      RECT 61.1 101.9 61.3 102.1 ;
      RECT 61.1 166.7 61.3 166.9 ;
      RECT 60.7 99.1 60.9 99.3 ;
      RECT 60.7 101.9 60.9 102.1 ;
      RECT 60.7 164.3 60.9 164.5 ;
      RECT 60.7 166.7 60.9 166.9 ;
      RECT 60.3 27.9 60.5 28.1 ;
      RECT 60.3 28.3 60.5 28.5 ;
      RECT 60.3 61.1 60.5 61.3 ;
      RECT 60.3 61.5 60.5 61.7 ;
      RECT 60.3 81.5 60.5 81.7 ;
      RECT 60.3 81.9 60.5 82.1 ;
      RECT 60.3 156.3 60.5 156.5 ;
      RECT 60.3 164.3 60.5 164.5 ;
      RECT 59.9 26.7 60.1 26.9 ;
      RECT 59.9 27.1 60.1 27.3 ;
      RECT 59.9 29.5 60.1 29.7 ;
      RECT 59.9 29.9 60.1 30.1 ;
      RECT 59.9 123.9 60.1 124.1 ;
      RECT 59.9 156.3 60.1 156.5 ;
      RECT 59.9 157.1 60.1 157.3 ;
      RECT 59.9 157.5 60.1 157.7 ;
      RECT 59.5 65.5 59.7 65.7 ;
      RECT 59.5 65.9 59.7 66.1 ;
      RECT 59.5 66.7 59.7 66.9 ;
      RECT 59.5 67.1 59.7 67.3 ;
      RECT 59.5 123.9 59.7 124.1 ;
      RECT 59.5 125.9 59.7 126.1 ;
      RECT 59.5 126.3 59.7 126.5 ;
      RECT 59.5 148.3 59.7 148.5 ;
      RECT 59.5 148.7 59.7 148.9 ;
      RECT 59.5 155.5 59.7 155.7 ;
      RECT 59.5 155.9 59.7 156.1 ;
      RECT 59.1 25.5 59.3 25.7 ;
      RECT 59.1 25.9 59.3 26.1 ;
      RECT 59.1 33.5 59.3 33.7 ;
      RECT 58.7 31.1 58.9 31.3 ;
      RECT 58.7 33.5 58.9 33.7 ;
      RECT 58.7 51.5 58.9 51.7 ;
      RECT 58.7 196.7 58.9 196.9 ;
      RECT 58.3 31.1 58.5 31.3 ;
      RECT 58.3 34.3 58.5 34.5 ;
      RECT 58.3 34.7 58.5 34.9 ;
      RECT 58.3 49.1 58.5 49.3 ;
      RECT 58.3 49.5 58.5 49.7 ;
      RECT 58.3 51.5 58.5 51.7 ;
      RECT 58.3 66.7 58.5 66.9 ;
      RECT 58.3 67.1 58.5 67.3 ;
      RECT 58.3 70.7 58.5 70.9 ;
      RECT 58.3 71.1 58.5 71.3 ;
      RECT 58.3 145.5 58.5 145.7 ;
      RECT 58.3 145.9 58.5 146.1 ;
      RECT 58.3 158.7 58.5 158.9 ;
      RECT 58.3 159.1 58.5 159.3 ;
      RECT 58.3 196.7 58.5 196.9 ;
      RECT 58.3 198.3 58.5 198.5 ;
      RECT 58.3 198.7 58.5 198.9 ;
      RECT 57.8 1 58 1.2 ;
      RECT 57.8 1.6 58 1.8 ;
      RECT 57.8 2.2 58 2.4 ;
      RECT 57.8 2.8 58 3 ;
      RECT 57.8 10.5 58 10.7 ;
      RECT 57.8 17.7 58 17.9 ;
      RECT 57.8 24.9 58 25.1 ;
      RECT 57.8 32.1 58 32.3 ;
      RECT 57.8 39.3 58 39.5 ;
      RECT 57.8 46.5 58 46.7 ;
      RECT 57.8 53.7 58 53.9 ;
      RECT 57.8 60.9 58 61.1 ;
      RECT 57.8 68.1 58 68.3 ;
      RECT 57.8 75.3 58 75.5 ;
      RECT 57.8 82.5 58 82.7 ;
      RECT 57.8 89.7 58 89.9 ;
      RECT 57.8 96.9 58 97.1 ;
      RECT 57.8 104.1 58 104.3 ;
      RECT 57.8 111.3 58 111.5 ;
      RECT 57.8 118.5 58 118.7 ;
      RECT 57.8 125.7 58 125.9 ;
      RECT 57.8 132.9 58 133.1 ;
      RECT 57.8 140.1 58 140.3 ;
      RECT 57.8 147.3 58 147.5 ;
      RECT 57.8 154.5 58 154.7 ;
      RECT 57.8 161.7 58 161.9 ;
      RECT 57.8 168.9 58 169.1 ;
      RECT 57.8 176.1 58 176.3 ;
      RECT 57.8 183.3 58 183.5 ;
      RECT 57.8 190.5 58 190.7 ;
      RECT 57.8 197.7 58 197.9 ;
      RECT 57.8 204.9 58 205.1 ;
      RECT 57.8 212.1 58 212.3 ;
      RECT 57.8 216.6 58 216.8 ;
      RECT 57.8 217.2 58 217.4 ;
      RECT 57.8 217.8 58 218 ;
      RECT 57.8 218.4 58 218.6 ;
      RECT 57.2 1 57.4 1.2 ;
      RECT 57.2 1.6 57.4 1.8 ;
      RECT 57.2 2.2 57.4 2.4 ;
      RECT 57.2 2.8 57.4 3 ;
      RECT 57.2 10.5 57.4 10.7 ;
      RECT 57.2 17.7 57.4 17.9 ;
      RECT 57.2 24.9 57.4 25.1 ;
      RECT 57.2 32.1 57.4 32.3 ;
      RECT 57.2 39.3 57.4 39.5 ;
      RECT 57.2 46.5 57.4 46.7 ;
      RECT 57.2 53.7 57.4 53.9 ;
      RECT 57.2 60.9 57.4 61.1 ;
      RECT 57.2 68.1 57.4 68.3 ;
      RECT 57.2 75.3 57.4 75.5 ;
      RECT 57.2 82.5 57.4 82.7 ;
      RECT 57.2 89.7 57.4 89.9 ;
      RECT 57.2 96.9 57.4 97.1 ;
      RECT 57.2 104.1 57.4 104.3 ;
      RECT 57.2 111.3 57.4 111.5 ;
      RECT 57.2 118.5 57.4 118.7 ;
      RECT 57.2 125.7 57.4 125.9 ;
      RECT 57.2 132.9 57.4 133.1 ;
      RECT 57.2 140.1 57.4 140.3 ;
      RECT 57.2 147.3 57.4 147.5 ;
      RECT 57.2 154.5 57.4 154.7 ;
      RECT 57.2 161.7 57.4 161.9 ;
      RECT 57.2 168.9 57.4 169.1 ;
      RECT 57.2 176.1 57.4 176.3 ;
      RECT 57.2 183.3 57.4 183.5 ;
      RECT 57.2 190.5 57.4 190.7 ;
      RECT 57.2 197.7 57.4 197.9 ;
      RECT 57.2 204.9 57.4 205.1 ;
      RECT 57.2 212.1 57.4 212.3 ;
      RECT 57.2 216.6 57.4 216.8 ;
      RECT 57.2 217.2 57.4 217.4 ;
      RECT 57.2 217.8 57.4 218 ;
      RECT 57.2 218.4 57.4 218.6 ;
      RECT 56.6 1 56.8 1.2 ;
      RECT 56.6 1.6 56.8 1.8 ;
      RECT 56.6 2.2 56.8 2.4 ;
      RECT 56.6 2.8 56.8 3 ;
      RECT 56.6 10.5 56.8 10.7 ;
      RECT 56.6 17.7 56.8 17.9 ;
      RECT 56.6 24.9 56.8 25.1 ;
      RECT 56.6 32.1 56.8 32.3 ;
      RECT 56.6 39.3 56.8 39.5 ;
      RECT 56.6 46.5 56.8 46.7 ;
      RECT 56.6 53.7 56.8 53.9 ;
      RECT 56.6 60.9 56.8 61.1 ;
      RECT 56.6 68.1 56.8 68.3 ;
      RECT 56.6 75.3 56.8 75.5 ;
      RECT 56.6 82.5 56.8 82.7 ;
      RECT 56.6 89.7 56.8 89.9 ;
      RECT 56.6 96.9 56.8 97.1 ;
      RECT 56.6 104.1 56.8 104.3 ;
      RECT 56.6 111.3 56.8 111.5 ;
      RECT 56.6 118.5 56.8 118.7 ;
      RECT 56.6 125.7 56.8 125.9 ;
      RECT 56.6 132.9 56.8 133.1 ;
      RECT 56.6 140.1 56.8 140.3 ;
      RECT 56.6 147.3 56.8 147.5 ;
      RECT 56.6 154.5 56.8 154.7 ;
      RECT 56.6 161.7 56.8 161.9 ;
      RECT 56.6 168.9 56.8 169.1 ;
      RECT 56.6 176.1 56.8 176.3 ;
      RECT 56.6 183.3 56.8 183.5 ;
      RECT 56.6 190.5 56.8 190.7 ;
      RECT 56.6 197.7 56.8 197.9 ;
      RECT 56.6 204.9 56.8 205.1 ;
      RECT 56.6 212.1 56.8 212.3 ;
      RECT 56.6 216.6 56.8 216.8 ;
      RECT 56.6 217.2 56.8 217.4 ;
      RECT 56.6 217.8 56.8 218 ;
      RECT 56.6 218.4 56.8 218.6 ;
      RECT 56 1 56.2 1.2 ;
      RECT 56 1.6 56.2 1.8 ;
      RECT 56 2.2 56.2 2.4 ;
      RECT 56 2.8 56.2 3 ;
      RECT 56 10.5 56.2 10.7 ;
      RECT 56 17.7 56.2 17.9 ;
      RECT 56 24.9 56.2 25.1 ;
      RECT 56 32.1 56.2 32.3 ;
      RECT 56 39.3 56.2 39.5 ;
      RECT 56 46.5 56.2 46.7 ;
      RECT 56 53.7 56.2 53.9 ;
      RECT 56 60.9 56.2 61.1 ;
      RECT 56 68.1 56.2 68.3 ;
      RECT 56 75.3 56.2 75.5 ;
      RECT 56 82.5 56.2 82.7 ;
      RECT 56 89.7 56.2 89.9 ;
      RECT 56 96.9 56.2 97.1 ;
      RECT 56 104.1 56.2 104.3 ;
      RECT 56 111.3 56.2 111.5 ;
      RECT 56 118.5 56.2 118.7 ;
      RECT 56 125.7 56.2 125.9 ;
      RECT 56 132.9 56.2 133.1 ;
      RECT 56 140.1 56.2 140.3 ;
      RECT 56 147.3 56.2 147.5 ;
      RECT 56 154.5 56.2 154.7 ;
      RECT 56 161.7 56.2 161.9 ;
      RECT 56 168.9 56.2 169.1 ;
      RECT 56 176.1 56.2 176.3 ;
      RECT 56 183.3 56.2 183.5 ;
      RECT 56 190.5 56.2 190.7 ;
      RECT 56 197.7 56.2 197.9 ;
      RECT 56 204.9 56.2 205.1 ;
      RECT 56 212.1 56.2 212.3 ;
      RECT 56 216.6 56.2 216.8 ;
      RECT 56 217.2 56.2 217.4 ;
      RECT 56 217.8 56.2 218 ;
      RECT 56 218.4 56.2 218.6 ;
      RECT 55.5 31.9 55.7 32.1 ;
      RECT 55.5 32.3 55.7 32.5 ;
      RECT 55.5 41.1 55.7 41.3 ;
      RECT 55.5 41.5 55.7 41.7 ;
      RECT 55.5 141.1 55.7 141.3 ;
      RECT 55.5 141.5 55.7 141.7 ;
      RECT 55.5 148.3 55.7 148.5 ;
      RECT 55.5 148.7 55.7 148.9 ;
      RECT 55.5 151.1 55.7 151.3 ;
      RECT 55.5 151.5 55.7 151.7 ;
      RECT 55.5 156.3 55.7 156.5 ;
      RECT 55.5 156.7 55.7 156.9 ;
      RECT 55.5 188.7 55.7 188.9 ;
      RECT 55.5 189.1 55.7 189.3 ;
      RECT 55.5 197.5 55.7 197.7 ;
      RECT 55.5 197.9 55.7 198.1 ;
      RECT 55.1 151.9 55.3 152.1 ;
      RECT 55.1 153.9 55.3 154.1 ;
      RECT 55.1 154.3 55.3 154.5 ;
      RECT 54.7 50.3 54.9 50.5 ;
      RECT 54.7 50.7 54.9 50.9 ;
      RECT 54.7 53.9 54.9 54.1 ;
      RECT 54.7 54.3 54.9 54.5 ;
      RECT 54.7 148.3 54.9 148.5 ;
      RECT 54.7 148.7 54.9 148.9 ;
      RECT 54.7 151.9 54.9 152.1 ;
      RECT 54.3 27.1 54.5 27.3 ;
      RECT 54.3 27.5 54.5 27.7 ;
      RECT 54.3 38.3 54.5 38.5 ;
      RECT 54.3 38.7 54.5 38.9 ;
      RECT 54.3 60.7 54.5 60.9 ;
      RECT 54.3 61.1 54.5 61.3 ;
      RECT 54.3 93.5 54.5 93.7 ;
      RECT 54.3 93.9 54.5 94.1 ;
      RECT 53.8 4 54 4.2 ;
      RECT 53.8 4.6 54 4.8 ;
      RECT 53.8 5.2 54 5.4 ;
      RECT 53.8 5.8 54 6 ;
      RECT 53.8 6.9 54 7.1 ;
      RECT 53.8 14.1 54 14.3 ;
      RECT 53.8 21.3 54 21.5 ;
      RECT 53.8 28.5 54 28.7 ;
      RECT 53.8 35.7 54 35.9 ;
      RECT 53.8 42.9 54 43.1 ;
      RECT 53.8 50.1 54 50.3 ;
      RECT 53.8 57.3 54 57.5 ;
      RECT 53.8 64.5 54 64.7 ;
      RECT 53.8 71.7 54 71.9 ;
      RECT 53.8 78.9 54 79.1 ;
      RECT 53.8 86.1 54 86.3 ;
      RECT 53.8 93.3 54 93.5 ;
      RECT 53.8 100.5 54 100.7 ;
      RECT 53.8 107.7 54 107.9 ;
      RECT 53.8 114.9 54 115.1 ;
      RECT 53.8 122.1 54 122.3 ;
      RECT 53.8 129.3 54 129.5 ;
      RECT 53.8 136.5 54 136.7 ;
      RECT 53.8 143.7 54 143.9 ;
      RECT 53.8 150.9 54 151.1 ;
      RECT 53.8 158.1 54 158.3 ;
      RECT 53.8 165.3 54 165.5 ;
      RECT 53.8 172.5 54 172.7 ;
      RECT 53.8 179.7 54 179.9 ;
      RECT 53.8 186.9 54 187.1 ;
      RECT 53.8 194.1 54 194.3 ;
      RECT 53.8 201.3 54 201.5 ;
      RECT 53.8 208.5 54 208.7 ;
      RECT 53.8 213.6 54 213.8 ;
      RECT 53.8 214.2 54 214.4 ;
      RECT 53.8 214.8 54 215 ;
      RECT 53.8 215.4 54 215.6 ;
      RECT 53.2 4 53.4 4.2 ;
      RECT 53.2 4.6 53.4 4.8 ;
      RECT 53.2 5.2 53.4 5.4 ;
      RECT 53.2 5.8 53.4 6 ;
      RECT 53.2 6.9 53.4 7.1 ;
      RECT 53.2 14.1 53.4 14.3 ;
      RECT 53.2 21.3 53.4 21.5 ;
      RECT 53.2 28.5 53.4 28.7 ;
      RECT 53.2 35.7 53.4 35.9 ;
      RECT 53.2 42.9 53.4 43.1 ;
      RECT 53.2 50.1 53.4 50.3 ;
      RECT 53.2 57.3 53.4 57.5 ;
      RECT 53.2 64.5 53.4 64.7 ;
      RECT 53.2 71.7 53.4 71.9 ;
      RECT 53.2 78.9 53.4 79.1 ;
      RECT 53.2 86.1 53.4 86.3 ;
      RECT 53.2 93.3 53.4 93.5 ;
      RECT 53.2 100.5 53.4 100.7 ;
      RECT 53.2 107.7 53.4 107.9 ;
      RECT 53.2 114.9 53.4 115.1 ;
      RECT 53.2 122.1 53.4 122.3 ;
      RECT 53.2 129.3 53.4 129.5 ;
      RECT 53.2 136.5 53.4 136.7 ;
      RECT 53.2 143.7 53.4 143.9 ;
      RECT 53.2 150.9 53.4 151.1 ;
      RECT 53.2 158.1 53.4 158.3 ;
      RECT 53.2 165.3 53.4 165.5 ;
      RECT 53.2 172.5 53.4 172.7 ;
      RECT 53.2 179.7 53.4 179.9 ;
      RECT 53.2 186.9 53.4 187.1 ;
      RECT 53.2 194.1 53.4 194.3 ;
      RECT 53.2 201.3 53.4 201.5 ;
      RECT 53.2 208.5 53.4 208.7 ;
      RECT 53.2 213.6 53.4 213.8 ;
      RECT 53.2 214.2 53.4 214.4 ;
      RECT 53.2 214.8 53.4 215 ;
      RECT 53.2 215.4 53.4 215.6 ;
      RECT 52.6 4 52.8 4.2 ;
      RECT 52.6 4.6 52.8 4.8 ;
      RECT 52.6 5.2 52.8 5.4 ;
      RECT 52.6 5.8 52.8 6 ;
      RECT 52.6 6.9 52.8 7.1 ;
      RECT 52.6 14.1 52.8 14.3 ;
      RECT 52.6 21.3 52.8 21.5 ;
      RECT 52.6 28.5 52.8 28.7 ;
      RECT 52.6 35.7 52.8 35.9 ;
      RECT 52.6 42.9 52.8 43.1 ;
      RECT 52.6 50.1 52.8 50.3 ;
      RECT 52.6 57.3 52.8 57.5 ;
      RECT 52.6 64.5 52.8 64.7 ;
      RECT 52.6 71.7 52.8 71.9 ;
      RECT 52.6 78.9 52.8 79.1 ;
      RECT 52.6 86.1 52.8 86.3 ;
      RECT 52.6 93.3 52.8 93.5 ;
      RECT 52.6 100.5 52.8 100.7 ;
      RECT 52.6 107.7 52.8 107.9 ;
      RECT 52.6 114.9 52.8 115.1 ;
      RECT 52.6 122.1 52.8 122.3 ;
      RECT 52.6 129.3 52.8 129.5 ;
      RECT 52.6 136.5 52.8 136.7 ;
      RECT 52.6 143.7 52.8 143.9 ;
      RECT 52.6 150.9 52.8 151.1 ;
      RECT 52.6 158.1 52.8 158.3 ;
      RECT 52.6 165.3 52.8 165.5 ;
      RECT 52.6 172.5 52.8 172.7 ;
      RECT 52.6 179.7 52.8 179.9 ;
      RECT 52.6 186.9 52.8 187.1 ;
      RECT 52.6 194.1 52.8 194.3 ;
      RECT 52.6 201.3 52.8 201.5 ;
      RECT 52.6 208.5 52.8 208.7 ;
      RECT 52.6 213.6 52.8 213.8 ;
      RECT 52.6 214.2 52.8 214.4 ;
      RECT 52.6 214.8 52.8 215 ;
      RECT 52.6 215.4 52.8 215.6 ;
      RECT 52 4 52.2 4.2 ;
      RECT 52 4.6 52.2 4.8 ;
      RECT 52 5.2 52.2 5.4 ;
      RECT 52 5.8 52.2 6 ;
      RECT 52 6.9 52.2 7.1 ;
      RECT 52 14.1 52.2 14.3 ;
      RECT 52 21.3 52.2 21.5 ;
      RECT 52 28.5 52.2 28.7 ;
      RECT 52 35.7 52.2 35.9 ;
      RECT 52 42.9 52.2 43.1 ;
      RECT 52 50.1 52.2 50.3 ;
      RECT 52 57.3 52.2 57.5 ;
      RECT 52 64.5 52.2 64.7 ;
      RECT 52 71.7 52.2 71.9 ;
      RECT 52 78.9 52.2 79.1 ;
      RECT 52 86.1 52.2 86.3 ;
      RECT 52 93.3 52.2 93.5 ;
      RECT 52 100.5 52.2 100.7 ;
      RECT 52 107.7 52.2 107.9 ;
      RECT 52 114.9 52.2 115.1 ;
      RECT 52 122.1 52.2 122.3 ;
      RECT 52 129.3 52.2 129.5 ;
      RECT 52 136.5 52.2 136.7 ;
      RECT 52 143.7 52.2 143.9 ;
      RECT 52 150.9 52.2 151.1 ;
      RECT 52 158.1 52.2 158.3 ;
      RECT 52 165.3 52.2 165.5 ;
      RECT 52 172.5 52.2 172.7 ;
      RECT 52 179.7 52.2 179.9 ;
      RECT 52 186.9 52.2 187.1 ;
      RECT 52 194.1 52.2 194.3 ;
      RECT 52 201.3 52.2 201.5 ;
      RECT 52 208.5 52.2 208.7 ;
      RECT 52 213.6 52.2 213.8 ;
      RECT 52 214.2 52.2 214.4 ;
      RECT 52 214.8 52.2 215 ;
      RECT 52 215.4 52.2 215.6 ;
      RECT 51.5 38.3 51.7 38.5 ;
      RECT 51.5 38.7 51.7 38.9 ;
      RECT 51.5 44.3 51.7 44.5 ;
      RECT 51.5 44.7 51.7 44.9 ;
      RECT 51.5 102.7 51.7 102.9 ;
      RECT 51.5 103.1 51.7 103.3 ;
      RECT 51.5 112.3 51.7 112.5 ;
      RECT 51.5 112.7 51.7 112.9 ;
      RECT 51.5 120.3 51.7 120.5 ;
      RECT 51.5 120.7 51.7 120.9 ;
      RECT 51.5 127.9 51.7 128.1 ;
      RECT 51.5 130.7 51.7 130.9 ;
      RECT 51.5 131.1 51.7 131.3 ;
      RECT 51.5 133.1 51.7 133.3 ;
      RECT 51.5 133.5 51.7 133.7 ;
      RECT 51.5 155.9 51.7 156.1 ;
      RECT 51.5 156.3 51.7 156.5 ;
      RECT 51.5 160.3 51.7 160.5 ;
      RECT 51.5 160.7 51.7 160.9 ;
      RECT 51.5 166.7 51.7 166.9 ;
      RECT 51.5 167.1 51.7 167.3 ;
      RECT 51.5 171.1 51.7 171.3 ;
      RECT 51.5 171.5 51.7 171.7 ;
      RECT 51.5 173.9 51.7 174.1 ;
      RECT 51.5 178.3 51.7 178.5 ;
      RECT 51.5 186.3 51.7 186.5 ;
      RECT 51.5 186.7 51.7 186.9 ;
      RECT 51.5 187.1 51.7 187.3 ;
      RECT 51.5 187.5 51.7 187.7 ;
      RECT 51.1 37.5 51.3 37.7 ;
      RECT 51.1 51.5 51.3 51.7 ;
      RECT 51.1 62.3 51.3 62.5 ;
      RECT 51.1 62.7 51.3 62.9 ;
      RECT 51.1 86.3 51.3 86.5 ;
      RECT 51.1 86.7 51.3 86.9 ;
      RECT 51.1 127.9 51.3 128.1 ;
      RECT 51.1 173.9 51.3 174.1 ;
      RECT 51.1 178.3 51.3 178.5 ;
      RECT 50.7 23.9 50.9 24.1 ;
      RECT 50.7 24.3 50.9 24.5 ;
      RECT 50.7 37.5 50.9 37.7 ;
      RECT 50.7 43.9 50.9 44.1 ;
      RECT 50.7 44.3 50.9 44.5 ;
      RECT 50.7 47.5 50.9 47.7 ;
      RECT 50.7 51.5 50.9 51.7 ;
      RECT 50.3 47.5 50.5 47.7 ;
      RECT 49.9 148.7 50.1 148.9 ;
      RECT 49.9 149.1 50.1 149.3 ;
      RECT 49.9 152.3 50.1 152.5 ;
      RECT 49.9 152.7 50.1 152.9 ;
      RECT 49.9 193.1 50.1 193.3 ;
      RECT 49.9 193.5 50.1 193.7 ;
      RECT 49.9 206.7 50.1 206.9 ;
      RECT 49.9 207.1 50.1 207.3 ;
      RECT 48.7 147.9 48.9 148.1 ;
      RECT 48.7 148.3 48.9 148.5 ;
      RECT 48.7 152.3 48.9 152.5 ;
      RECT 48.7 152.7 48.9 152.9 ;
      RECT 48.3 109.1 48.5 109.3 ;
      RECT 48.3 114.7 48.5 114.9 ;
      RECT 47.9 11.9 48.1 12.1 ;
      RECT 47.9 12.3 48.1 12.5 ;
      RECT 47.9 26.7 48.1 26.9 ;
      RECT 47.9 27.1 48.1 27.3 ;
      RECT 47.9 67.1 48.1 67.3 ;
      RECT 47.9 67.5 48.1 67.7 ;
      RECT 47.9 79.1 48.1 79.3 ;
      RECT 47.9 79.5 48.1 79.7 ;
      RECT 47.9 113.1 48.1 113.3 ;
      RECT 47.5 103.5 47.7 103.7 ;
      RECT 47.5 103.9 47.7 104.1 ;
      RECT 47.5 113.1 47.7 113.3 ;
      RECT 47.1 53.5 47.3 53.7 ;
      RECT 47.1 53.9 47.3 54.1 ;
      RECT 47.1 97.1 47.3 97.3 ;
      RECT 47.1 97.5 47.3 97.7 ;
      RECT 46.7 123.9 46.9 124.1 ;
      RECT 46.7 124.3 46.9 124.5 ;
      RECT 46.7 163.9 46.9 164.1 ;
      RECT 46.7 164.3 46.9 164.5 ;
      RECT 46.3 66.3 46.5 66.5 ;
      RECT 46.3 66.7 46.5 66.9 ;
      RECT 46.3 70.3 46.5 70.5 ;
      RECT 46.3 70.7 46.5 70.9 ;
      RECT 46.3 77.1 46.5 77.3 ;
      RECT 46.3 77.5 46.5 77.7 ;
      RECT 46.3 83.1 46.5 83.3 ;
      RECT 46.3 83.5 46.5 83.7 ;
      RECT 45.9 32.7 46.1 32.9 ;
      RECT 45.9 33.1 46.1 33.3 ;
      RECT 45.9 45.1 46.1 45.3 ;
      RECT 45.9 45.5 46.1 45.7 ;
      RECT 45.9 139.9 46.1 140.1 ;
      RECT 45.9 140.3 46.1 140.5 ;
      RECT 45.9 152.7 46.1 152.9 ;
      RECT 45.9 153.1 46.1 153.3 ;
      RECT 45.9 204.7 46.1 204.9 ;
      RECT 45.5 61.1 45.7 61.3 ;
      RECT 45.5 61.5 45.7 61.7 ;
      RECT 45.5 79.9 45.7 80.1 ;
      RECT 45.5 80.3 45.7 80.5 ;
      RECT 45.5 189.1 45.7 189.3 ;
      RECT 45.5 189.5 45.7 189.7 ;
      RECT 45.5 204.7 45.7 204.9 ;
      RECT 45.1 29.9 45.3 30.1 ;
      RECT 45.1 30.3 45.3 30.5 ;
      RECT 45.1 35.1 45.3 35.3 ;
      RECT 45.1 35.5 45.3 35.7 ;
      RECT 45.1 45.9 45.3 46.1 ;
      RECT 45.1 46.3 45.3 46.5 ;
      RECT 45.1 192.3 45.3 192.5 ;
      RECT 45.1 192.7 45.3 192.9 ;
      RECT 45.1 197.5 45.3 197.7 ;
      RECT 45.1 197.9 45.3 198.1 ;
      RECT 44.7 70.3 44.9 70.5 ;
      RECT 44.7 70.7 44.9 70.9 ;
      RECT 44.7 72.3 44.9 72.5 ;
      RECT 44.7 72.7 44.9 72.9 ;
      RECT 44.7 77.5 44.9 77.7 ;
      RECT 44.7 77.9 44.9 78.1 ;
      RECT 44.7 138.7 44.9 138.9 ;
      RECT 44.7 139.1 44.9 139.3 ;
      RECT 44.7 167.1 44.9 167.3 ;
      RECT 44.7 167.5 44.9 167.7 ;
      RECT 44.3 183.9 44.5 184.1 ;
      RECT 44.3 184.3 44.5 184.5 ;
      RECT 44.3 192.3 44.5 192.5 ;
      RECT 44.3 192.7 44.5 192.9 ;
      RECT 43.5 143.9 43.7 144.1 ;
      RECT 43.5 144.3 43.7 144.5 ;
      RECT 43.5 152.7 43.7 152.9 ;
      RECT 43.5 153.1 43.7 153.3 ;
      RECT 42.7 139.1 42.9 139.3 ;
      RECT 42.7 139.5 42.9 139.7 ;
      RECT 42.7 147.5 42.9 147.7 ;
      RECT 42.7 147.9 42.9 148.1 ;
      RECT 42.7 149.1 42.9 149.3 ;
      RECT 42.7 149.5 42.9 149.7 ;
      RECT 42.7 157.9 42.9 158.1 ;
      RECT 42.7 158.3 42.9 158.5 ;
      RECT 42.3 185.9 42.5 186.1 ;
      RECT 42.3 186.3 42.5 186.5 ;
      RECT 42.3 193.9 42.5 194.1 ;
      RECT 42.3 194.3 42.5 194.5 ;
      RECT 40.3 60.7 40.5 60.9 ;
      RECT 40.3 61.1 40.5 61.3 ;
      RECT 40.3 81.5 40.5 81.7 ;
      RECT 40.3 81.9 40.5 82.1 ;
      RECT 40.3 148.7 40.5 148.9 ;
      RECT 40.3 149.1 40.5 149.3 ;
      RECT 40.3 161.1 40.5 161.3 ;
      RECT 40.3 161.5 40.5 161.7 ;
      RECT 39.9 134.7 40.1 134.9 ;
      RECT 39.9 135.1 40.1 135.3 ;
      RECT 39.9 145.1 40.1 145.3 ;
      RECT 39.9 145.5 40.1 145.7 ;
      RECT 38.3 136.7 38.5 136.9 ;
      RECT 38.3 137.1 38.5 137.3 ;
      RECT 38.3 163.9 38.5 164.1 ;
      RECT 38.3 164.3 38.5 164.5 ;
      RECT 36.3 101.9 36.5 102.1 ;
      RECT 35.9 101.9 36.1 102.1 ;
      RECT 35.9 108.3 36.1 108.5 ;
      RECT 35.5 108.3 35.7 108.5 ;
      RECT 35.1 73.5 35.3 73.7 ;
      RECT 35.1 73.9 35.3 74.1 ;
      RECT 35.1 83.9 35.3 84.1 ;
      RECT 35.1 84.3 35.3 84.5 ;
      RECT 34.7 154.3 34.9 154.5 ;
      RECT 34.7 154.7 34.9 154.9 ;
      RECT 34.7 169.1 34.9 169.3 ;
      RECT 34.7 169.5 34.9 169.7 ;
      RECT 34.3 181.9 34.5 182.1 ;
      RECT 34.3 182.3 34.5 182.5 ;
      RECT 34.3 204.7 34.5 204.9 ;
      RECT 34.3 205.1 34.5 205.3 ;
      RECT 33.1 115.1 33.3 115.3 ;
      RECT 33.1 115.5 33.3 115.7 ;
      RECT 33.1 117.9 33.3 118.1 ;
      RECT 33.1 118.3 33.3 118.5 ;
      RECT 33.1 147.1 33.3 147.3 ;
      RECT 33.1 147.5 33.3 147.7 ;
      RECT 33.1 149.5 33.3 149.7 ;
      RECT 33.1 149.9 33.3 150.1 ;
      RECT 32.7 173.9 32.9 174.1 ;
      RECT 32.3 173.9 32.5 174.1 ;
      RECT 32.3 178.3 32.5 178.5 ;
      RECT 32.3 181.1 32.5 181.3 ;
      RECT 31.9 178.3 32.1 178.5 ;
      RECT 31.9 181.1 32.1 181.3 ;
      RECT 31.5 144.7 31.7 144.9 ;
      RECT 31.5 156.3 31.7 156.5 ;
      RECT 30.7 155.5 30.9 155.7 ;
      RECT 30.7 155.9 30.9 156.1 ;
      RECT 30.7 156.3 30.9 156.5 ;
      RECT 30.7 156.7 30.9 156.9 ;
      RECT 29.5 64.3 29.7 64.5 ;
      RECT 29.5 74.7 29.7 74.9 ;
      RECT 29.5 80.7 29.7 80.9 ;
      RECT 29.5 81.1 29.7 81.3 ;
      RECT 29.5 82.3 29.7 82.5 ;
      RECT 29.5 82.7 29.7 82.9 ;
      RECT 27.8 1 28 1.2 ;
      RECT 27.8 1.6 28 1.8 ;
      RECT 27.8 2.2 28 2.4 ;
      RECT 27.8 2.8 28 3 ;
      RECT 27.8 10.5 28 10.7 ;
      RECT 27.8 17.7 28 17.9 ;
      RECT 27.8 24.9 28 25.1 ;
      RECT 27.8 32.1 28 32.3 ;
      RECT 27.8 39.3 28 39.5 ;
      RECT 27.8 46.5 28 46.7 ;
      RECT 27.8 53.7 28 53.9 ;
      RECT 27.8 60.9 28 61.1 ;
      RECT 27.8 68.1 28 68.3 ;
      RECT 27.8 75.3 28 75.5 ;
      RECT 27.8 82.5 28 82.7 ;
      RECT 27.8 89.7 28 89.9 ;
      RECT 27.8 96.9 28 97.1 ;
      RECT 27.8 104.1 28 104.3 ;
      RECT 27.8 111.3 28 111.5 ;
      RECT 27.8 118.5 28 118.7 ;
      RECT 27.8 125.7 28 125.9 ;
      RECT 27.8 132.9 28 133.1 ;
      RECT 27.8 140.1 28 140.3 ;
      RECT 27.8 147.3 28 147.5 ;
      RECT 27.8 154.5 28 154.7 ;
      RECT 27.8 161.7 28 161.9 ;
      RECT 27.8 168.9 28 169.1 ;
      RECT 27.8 176.1 28 176.3 ;
      RECT 27.8 183.3 28 183.5 ;
      RECT 27.8 190.5 28 190.7 ;
      RECT 27.8 197.7 28 197.9 ;
      RECT 27.8 204.9 28 205.1 ;
      RECT 27.8 212.1 28 212.3 ;
      RECT 27.8 216.6 28 216.8 ;
      RECT 27.8 217.2 28 217.4 ;
      RECT 27.8 217.8 28 218 ;
      RECT 27.8 218.4 28 218.6 ;
      RECT 27.2 1 27.4 1.2 ;
      RECT 27.2 1.6 27.4 1.8 ;
      RECT 27.2 2.2 27.4 2.4 ;
      RECT 27.2 2.8 27.4 3 ;
      RECT 27.2 10.5 27.4 10.7 ;
      RECT 27.2 17.7 27.4 17.9 ;
      RECT 27.2 24.9 27.4 25.1 ;
      RECT 27.2 32.1 27.4 32.3 ;
      RECT 27.2 39.3 27.4 39.5 ;
      RECT 27.2 46.5 27.4 46.7 ;
      RECT 27.2 53.7 27.4 53.9 ;
      RECT 27.2 60.9 27.4 61.1 ;
      RECT 27.2 68.1 27.4 68.3 ;
      RECT 27.2 75.3 27.4 75.5 ;
      RECT 27.2 82.5 27.4 82.7 ;
      RECT 27.2 89.7 27.4 89.9 ;
      RECT 27.2 96.9 27.4 97.1 ;
      RECT 27.2 104.1 27.4 104.3 ;
      RECT 27.2 111.3 27.4 111.5 ;
      RECT 27.2 118.5 27.4 118.7 ;
      RECT 27.2 125.7 27.4 125.9 ;
      RECT 27.2 132.9 27.4 133.1 ;
      RECT 27.2 140.1 27.4 140.3 ;
      RECT 27.2 147.3 27.4 147.5 ;
      RECT 27.2 154.5 27.4 154.7 ;
      RECT 27.2 161.7 27.4 161.9 ;
      RECT 27.2 168.9 27.4 169.1 ;
      RECT 27.2 176.1 27.4 176.3 ;
      RECT 27.2 183.3 27.4 183.5 ;
      RECT 27.2 190.5 27.4 190.7 ;
      RECT 27.2 197.7 27.4 197.9 ;
      RECT 27.2 204.9 27.4 205.1 ;
      RECT 27.2 212.1 27.4 212.3 ;
      RECT 27.2 216.6 27.4 216.8 ;
      RECT 27.2 217.2 27.4 217.4 ;
      RECT 27.2 217.8 27.4 218 ;
      RECT 27.2 218.4 27.4 218.6 ;
      RECT 26.6 1 26.8 1.2 ;
      RECT 26.6 1.6 26.8 1.8 ;
      RECT 26.6 2.2 26.8 2.4 ;
      RECT 26.6 2.8 26.8 3 ;
      RECT 26.6 10.5 26.8 10.7 ;
      RECT 26.6 17.7 26.8 17.9 ;
      RECT 26.6 24.9 26.8 25.1 ;
      RECT 26.6 32.1 26.8 32.3 ;
      RECT 26.6 39.3 26.8 39.5 ;
      RECT 26.6 46.5 26.8 46.7 ;
      RECT 26.6 53.7 26.8 53.9 ;
      RECT 26.6 60.9 26.8 61.1 ;
      RECT 26.6 68.1 26.8 68.3 ;
      RECT 26.6 75.3 26.8 75.5 ;
      RECT 26.6 82.5 26.8 82.7 ;
      RECT 26.6 89.7 26.8 89.9 ;
      RECT 26.6 96.9 26.8 97.1 ;
      RECT 26.6 104.1 26.8 104.3 ;
      RECT 26.6 111.3 26.8 111.5 ;
      RECT 26.6 118.5 26.8 118.7 ;
      RECT 26.6 125.7 26.8 125.9 ;
      RECT 26.6 132.9 26.8 133.1 ;
      RECT 26.6 140.1 26.8 140.3 ;
      RECT 26.6 147.3 26.8 147.5 ;
      RECT 26.6 154.5 26.8 154.7 ;
      RECT 26.6 161.7 26.8 161.9 ;
      RECT 26.6 168.9 26.8 169.1 ;
      RECT 26.6 176.1 26.8 176.3 ;
      RECT 26.6 183.3 26.8 183.5 ;
      RECT 26.6 190.5 26.8 190.7 ;
      RECT 26.6 197.7 26.8 197.9 ;
      RECT 26.6 204.9 26.8 205.1 ;
      RECT 26.6 212.1 26.8 212.3 ;
      RECT 26.6 216.6 26.8 216.8 ;
      RECT 26.6 217.2 26.8 217.4 ;
      RECT 26.6 217.8 26.8 218 ;
      RECT 26.6 218.4 26.8 218.6 ;
      RECT 26 1 26.2 1.2 ;
      RECT 26 1.6 26.2 1.8 ;
      RECT 26 2.2 26.2 2.4 ;
      RECT 26 2.8 26.2 3 ;
      RECT 26 10.5 26.2 10.7 ;
      RECT 26 17.7 26.2 17.9 ;
      RECT 26 24.9 26.2 25.1 ;
      RECT 26 32.1 26.2 32.3 ;
      RECT 26 39.3 26.2 39.5 ;
      RECT 26 46.5 26.2 46.7 ;
      RECT 26 53.7 26.2 53.9 ;
      RECT 26 60.9 26.2 61.1 ;
      RECT 26 68.1 26.2 68.3 ;
      RECT 26 75.3 26.2 75.5 ;
      RECT 26 82.5 26.2 82.7 ;
      RECT 26 89.7 26.2 89.9 ;
      RECT 26 96.9 26.2 97.1 ;
      RECT 26 104.1 26.2 104.3 ;
      RECT 26 111.3 26.2 111.5 ;
      RECT 26 118.5 26.2 118.7 ;
      RECT 26 125.7 26.2 125.9 ;
      RECT 26 132.9 26.2 133.1 ;
      RECT 26 140.1 26.2 140.3 ;
      RECT 26 147.3 26.2 147.5 ;
      RECT 26 154.5 26.2 154.7 ;
      RECT 26 161.7 26.2 161.9 ;
      RECT 26 168.9 26.2 169.1 ;
      RECT 26 176.1 26.2 176.3 ;
      RECT 26 183.3 26.2 183.5 ;
      RECT 26 190.5 26.2 190.7 ;
      RECT 26 197.7 26.2 197.9 ;
      RECT 26 204.9 26.2 205.1 ;
      RECT 26 212.1 26.2 212.3 ;
      RECT 26 216.6 26.2 216.8 ;
      RECT 26 217.2 26.2 217.4 ;
      RECT 26 217.8 26.2 218 ;
      RECT 26 218.4 26.2 218.6 ;
      RECT 25.5 72.7 25.7 72.9 ;
      RECT 25.5 73.1 25.7 73.3 ;
      RECT 25.5 99.5 25.7 99.7 ;
      RECT 25.1 99.5 25.3 99.7 ;
      RECT 25.1 133.9 25.3 134.1 ;
      RECT 25.1 134.3 25.3 134.5 ;
      RECT 25.1 161.9 25.3 162.1 ;
      RECT 25.1 162.3 25.3 162.5 ;
      RECT 24.7 64.3 24.9 64.5 ;
      RECT 24.7 64.7 24.9 64.9 ;
      RECT 24.7 73.9 24.9 74.1 ;
      RECT 24.7 74.3 24.9 74.5 ;
      RECT 24.7 123.5 24.9 123.7 ;
      RECT 24.7 127.9 24.9 128.1 ;
      RECT 24.7 191.9 24.9 192.1 ;
      RECT 24.7 192.3 24.9 192.5 ;
      RECT 24.7 195.5 24.9 195.7 ;
      RECT 24.7 195.9 24.9 196.1 ;
      RECT 24.3 75.5 24.5 75.7 ;
      RECT 24.3 75.9 24.5 76.1 ;
      RECT 24.3 78.3 24.5 78.5 ;
      RECT 24.3 78.7 24.5 78.9 ;
      RECT 24.3 80.7 24.5 80.9 ;
      RECT 24.3 81.1 24.5 81.3 ;
      RECT 24.3 113.9 24.5 114.1 ;
      RECT 24.3 114.3 24.5 114.5 ;
      RECT 24.3 116.3 24.5 116.5 ;
      RECT 24.3 116.7 24.5 116.9 ;
      RECT 24.3 123.5 24.5 123.7 ;
      RECT 24.3 127.9 24.5 128.1 ;
      RECT 24.3 155.9 24.5 156.1 ;
      RECT 24.3 156.3 24.5 156.5 ;
      RECT 24.3 159.9 24.5 160.1 ;
      RECT 24.3 160.3 24.5 160.5 ;
      RECT 23.8 4 24 4.2 ;
      RECT 23.8 4.6 24 4.8 ;
      RECT 23.8 5.2 24 5.4 ;
      RECT 23.8 5.8 24 6 ;
      RECT 23.8 6.9 24 7.1 ;
      RECT 23.8 14.1 24 14.3 ;
      RECT 23.8 21.3 24 21.5 ;
      RECT 23.8 28.5 24 28.7 ;
      RECT 23.8 35.7 24 35.9 ;
      RECT 23.8 42.9 24 43.1 ;
      RECT 23.8 50.1 24 50.3 ;
      RECT 23.8 57.3 24 57.5 ;
      RECT 23.8 64.5 24 64.7 ;
      RECT 23.8 71.7 24 71.9 ;
      RECT 23.8 78.9 24 79.1 ;
      RECT 23.8 86.1 24 86.3 ;
      RECT 23.8 93.3 24 93.5 ;
      RECT 23.8 100.5 24 100.7 ;
      RECT 23.8 107.7 24 107.9 ;
      RECT 23.8 114.9 24 115.1 ;
      RECT 23.8 122.1 24 122.3 ;
      RECT 23.8 129.3 24 129.5 ;
      RECT 23.8 136.5 24 136.7 ;
      RECT 23.8 143.7 24 143.9 ;
      RECT 23.8 150.9 24 151.1 ;
      RECT 23.8 158.1 24 158.3 ;
      RECT 23.8 165.3 24 165.5 ;
      RECT 23.8 172.5 24 172.7 ;
      RECT 23.8 179.7 24 179.9 ;
      RECT 23.8 186.9 24 187.1 ;
      RECT 23.8 194.1 24 194.3 ;
      RECT 23.8 201.3 24 201.5 ;
      RECT 23.8 208.5 24 208.7 ;
      RECT 23.8 213.6 24 213.8 ;
      RECT 23.8 214.2 24 214.4 ;
      RECT 23.8 214.8 24 215 ;
      RECT 23.8 215.4 24 215.6 ;
      RECT 23.2 4 23.4 4.2 ;
      RECT 23.2 4.6 23.4 4.8 ;
      RECT 23.2 5.2 23.4 5.4 ;
      RECT 23.2 5.8 23.4 6 ;
      RECT 23.2 6.9 23.4 7.1 ;
      RECT 23.2 14.1 23.4 14.3 ;
      RECT 23.2 21.3 23.4 21.5 ;
      RECT 23.2 28.5 23.4 28.7 ;
      RECT 23.2 35.7 23.4 35.9 ;
      RECT 23.2 42.9 23.4 43.1 ;
      RECT 23.2 50.1 23.4 50.3 ;
      RECT 23.2 57.3 23.4 57.5 ;
      RECT 23.2 64.5 23.4 64.7 ;
      RECT 23.2 71.7 23.4 71.9 ;
      RECT 23.2 78.9 23.4 79.1 ;
      RECT 23.2 86.1 23.4 86.3 ;
      RECT 23.2 93.3 23.4 93.5 ;
      RECT 23.2 100.5 23.4 100.7 ;
      RECT 23.2 107.7 23.4 107.9 ;
      RECT 23.2 114.9 23.4 115.1 ;
      RECT 23.2 122.1 23.4 122.3 ;
      RECT 23.2 129.3 23.4 129.5 ;
      RECT 23.2 136.5 23.4 136.7 ;
      RECT 23.2 143.7 23.4 143.9 ;
      RECT 23.2 150.9 23.4 151.1 ;
      RECT 23.2 158.1 23.4 158.3 ;
      RECT 23.2 165.3 23.4 165.5 ;
      RECT 23.2 172.5 23.4 172.7 ;
      RECT 23.2 179.7 23.4 179.9 ;
      RECT 23.2 186.9 23.4 187.1 ;
      RECT 23.2 194.1 23.4 194.3 ;
      RECT 23.2 201.3 23.4 201.5 ;
      RECT 23.2 208.5 23.4 208.7 ;
      RECT 23.2 213.6 23.4 213.8 ;
      RECT 23.2 214.2 23.4 214.4 ;
      RECT 23.2 214.8 23.4 215 ;
      RECT 23.2 215.4 23.4 215.6 ;
      RECT 22.6 4 22.8 4.2 ;
      RECT 22.6 4.6 22.8 4.8 ;
      RECT 22.6 5.2 22.8 5.4 ;
      RECT 22.6 5.8 22.8 6 ;
      RECT 22.6 6.9 22.8 7.1 ;
      RECT 22.6 14.1 22.8 14.3 ;
      RECT 22.6 21.3 22.8 21.5 ;
      RECT 22.6 28.5 22.8 28.7 ;
      RECT 22.6 35.7 22.8 35.9 ;
      RECT 22.6 42.9 22.8 43.1 ;
      RECT 22.6 50.1 22.8 50.3 ;
      RECT 22.6 57.3 22.8 57.5 ;
      RECT 22.6 64.5 22.8 64.7 ;
      RECT 22.6 71.7 22.8 71.9 ;
      RECT 22.6 78.9 22.8 79.1 ;
      RECT 22.6 86.1 22.8 86.3 ;
      RECT 22.6 93.3 22.8 93.5 ;
      RECT 22.6 100.5 22.8 100.7 ;
      RECT 22.6 107.7 22.8 107.9 ;
      RECT 22.6 114.9 22.8 115.1 ;
      RECT 22.6 122.1 22.8 122.3 ;
      RECT 22.6 129.3 22.8 129.5 ;
      RECT 22.6 136.5 22.8 136.7 ;
      RECT 22.6 143.7 22.8 143.9 ;
      RECT 22.6 150.9 22.8 151.1 ;
      RECT 22.6 158.1 22.8 158.3 ;
      RECT 22.6 165.3 22.8 165.5 ;
      RECT 22.6 172.5 22.8 172.7 ;
      RECT 22.6 179.7 22.8 179.9 ;
      RECT 22.6 186.9 22.8 187.1 ;
      RECT 22.6 194.1 22.8 194.3 ;
      RECT 22.6 201.3 22.8 201.5 ;
      RECT 22.6 208.5 22.8 208.7 ;
      RECT 22.6 213.6 22.8 213.8 ;
      RECT 22.6 214.2 22.8 214.4 ;
      RECT 22.6 214.8 22.8 215 ;
      RECT 22.6 215.4 22.8 215.6 ;
      RECT 22 4 22.2 4.2 ;
      RECT 22 4.6 22.2 4.8 ;
      RECT 22 5.2 22.2 5.4 ;
      RECT 22 5.8 22.2 6 ;
      RECT 22 6.9 22.2 7.1 ;
      RECT 22 14.1 22.2 14.3 ;
      RECT 22 21.3 22.2 21.5 ;
      RECT 22 28.5 22.2 28.7 ;
      RECT 22 35.7 22.2 35.9 ;
      RECT 22 42.9 22.2 43.1 ;
      RECT 22 50.1 22.2 50.3 ;
      RECT 22 57.3 22.2 57.5 ;
      RECT 22 64.5 22.2 64.7 ;
      RECT 22 71.7 22.2 71.9 ;
      RECT 22 78.9 22.2 79.1 ;
      RECT 22 86.1 22.2 86.3 ;
      RECT 22 93.3 22.2 93.5 ;
      RECT 22 100.5 22.2 100.7 ;
      RECT 22 107.7 22.2 107.9 ;
      RECT 22 114.9 22.2 115.1 ;
      RECT 22 122.1 22.2 122.3 ;
      RECT 22 129.3 22.2 129.5 ;
      RECT 22 136.5 22.2 136.7 ;
      RECT 22 143.7 22.2 143.9 ;
      RECT 22 150.9 22.2 151.1 ;
      RECT 22 158.1 22.2 158.3 ;
      RECT 22 165.3 22.2 165.5 ;
      RECT 22 172.5 22.2 172.7 ;
      RECT 22 179.7 22.2 179.9 ;
      RECT 22 186.9 22.2 187.1 ;
      RECT 22 194.1 22.2 194.3 ;
      RECT 22 201.3 22.2 201.5 ;
      RECT 22 208.5 22.2 208.7 ;
      RECT 22 213.6 22.2 213.8 ;
      RECT 22 214.2 22.2 214.4 ;
      RECT 22 214.8 22.2 215 ;
      RECT 22 215.4 22.2 215.6 ;
      RECT 21.5 131.5 21.7 131.7 ;
      RECT 21.5 131.9 21.7 132.1 ;
      RECT 21.5 145.9 21.7 146.1 ;
      RECT 21.5 146.3 21.7 146.5 ;
      RECT 21.1 44.3 21.3 44.5 ;
      RECT 21.1 47.5 21.3 47.7 ;
      RECT 20.7 19.9 20.9 20.1 ;
      RECT 20.7 22.7 20.9 22.9 ;
      RECT 20.7 27.1 20.9 27.3 ;
      RECT 20.7 33.1 20.9 33.3 ;
      RECT 20.7 37.1 20.9 37.3 ;
      RECT 20.7 37.5 20.9 37.7 ;
      RECT 20.7 41.5 20.9 41.7 ;
      RECT 20.7 41.9 20.9 42.1 ;
      RECT 20.7 44.3 20.9 44.5 ;
      RECT 20.7 47.5 20.9 47.7 ;
      RECT 20.7 55.9 20.9 56.1 ;
      RECT 20.7 58.7 20.9 58.9 ;
      RECT 20.7 65.9 20.9 66.1 ;
      RECT 20.7 83.5 20.9 83.7 ;
      RECT 20.7 83.9 20.9 84.1 ;
      RECT 20.7 106.3 20.9 106.5 ;
      RECT 20.7 106.7 20.9 106.9 ;
      RECT 20.3 19.9 20.5 20.1 ;
      RECT 20.3 22.7 20.5 22.9 ;
      RECT 20.3 27.1 20.5 27.3 ;
      RECT 20.3 33.1 20.5 33.3 ;
      RECT 20.3 55.9 20.5 56.1 ;
      RECT 20.3 58.7 20.5 58.9 ;
      RECT 20.3 65.9 20.5 66.1 ;
      RECT 19.5 142.7 19.7 142.9 ;
      RECT 19.5 143.1 19.7 143.3 ;
      RECT 19.5 163.9 19.7 164.1 ;
      RECT 19.5 164.3 19.7 164.5 ;
      RECT 15.5 65.9 15.7 66.1 ;
      RECT 15.5 181.1 15.7 181.3 ;
      RECT 15.5 188.3 15.7 188.5 ;
      RECT 15.5 192.7 15.7 192.9 ;
      RECT 15.5 199.9 15.7 200.1 ;
      RECT 15.1 63.5 15.3 63.7 ;
      RECT 15.1 65.9 15.3 66.1 ;
      RECT 15.1 181.1 15.3 181.3 ;
      RECT 15.1 188.3 15.3 188.5 ;
      RECT 15.1 192.7 15.3 192.9 ;
      RECT 15.1 199.9 15.3 200.1 ;
      RECT 14.7 63.5 14.9 63.7 ;
      RECT 13.5 108.3 13.7 108.5 ;
      RECT 13.1 91.9 13.3 92.1 ;
      RECT 13.1 99.1 13.3 99.3 ;
      RECT 13.1 99.5 13.3 99.7 ;
      RECT 13.1 108.3 13.3 108.5 ;
      RECT 12.7 13.1 12.9 13.3 ;
      RECT 12.7 69.9 12.9 70.1 ;
      RECT 12.7 91.9 12.9 92.1 ;
      RECT 12.3 13.1 12.5 13.3 ;
      RECT 12.3 69.9 12.5 70.1 ;
      RECT 11.1 120.7 11.3 120.9 ;
      RECT 11.1 127.9 11.3 128.1 ;
      RECT 10.7 120.7 10.9 120.9 ;
      RECT 10.7 127.9 10.9 128.1 ;
      RECT 10.7 141.9 10.9 142.1 ;
      RECT 10.7 142.3 10.9 142.5 ;
      RECT 10.7 144.7 10.9 144.9 ;
      RECT 10.7 145.1 10.9 145.3 ;
      RECT 10.7 156.7 10.9 156.9 ;
      RECT 10.7 159.5 10.9 159.7 ;
      RECT 10.7 169.5 10.9 169.7 ;
      RECT 10.7 169.9 10.9 170.1 ;
      RECT 10.3 65.9 10.5 66.1 ;
      RECT 10.3 156.7 10.5 156.9 ;
      RECT 10.3 159.5 10.5 159.7 ;
      RECT 9.9 65.9 10.1 66.1 ;
      RECT 9.9 72.3 10.1 72.5 ;
      RECT 9.9 72.7 10.1 72.9 ;
      RECT 9.9 77.1 10.1 77.3 ;
      RECT 9.5 8.3 9.7 8.5 ;
      RECT 9.5 77.1 9.7 77.3 ;
      RECT 9.5 190.3 9.7 190.5 ;
      RECT 9.5 190.7 9.7 190.9 ;
      RECT 9.5 196.3 9.7 196.5 ;
      RECT 9.5 196.7 9.7 196.9 ;
      RECT 9.1 3.5 9.3 3.7 ;
      RECT 9.1 8.3 9.3 8.5 ;
      RECT 8.7 3.5 8.9 3.7 ;
      RECT 5.8 4 6 4.2 ;
      RECT 5.8 4.6 6 4.8 ;
      RECT 5.8 5.2 6 5.4 ;
      RECT 5.8 5.8 6 6 ;
      RECT 5.8 213.6 6 213.8 ;
      RECT 5.8 214.2 6 214.4 ;
      RECT 5.8 214.8 6 215 ;
      RECT 5.8 215.4 6 215.6 ;
      RECT 5.2 4 5.4 4.2 ;
      RECT 5.2 4.6 5.4 4.8 ;
      RECT 5.2 5.2 5.4 5.4 ;
      RECT 5.2 5.8 5.4 6 ;
      RECT 5.2 213.6 5.4 213.8 ;
      RECT 5.2 214.2 5.4 214.4 ;
      RECT 5.2 214.8 5.4 215 ;
      RECT 5.2 215.4 5.4 215.6 ;
      RECT 4.6 4 4.8 4.2 ;
      RECT 4.6 4.6 4.8 4.8 ;
      RECT 4.6 5.2 4.8 5.4 ;
      RECT 4.6 5.8 4.8 6 ;
      RECT 4.6 213.6 4.8 213.8 ;
      RECT 4.6 214.2 4.8 214.4 ;
      RECT 4.6 214.8 4.8 215 ;
      RECT 4.6 215.4 4.8 215.6 ;
      RECT 4 4 4.2 4.2 ;
      RECT 4 4.6 4.2 4.8 ;
      RECT 4 5.2 4.2 5.4 ;
      RECT 4 5.8 4.2 6 ;
      RECT 4 213.6 4.2 213.8 ;
      RECT 4 214.2 4.2 214.4 ;
      RECT 4 214.8 4.2 215 ;
      RECT 4 215.4 4.2 215.6 ;
      RECT 3.5 55.1 3.7 55.3 ;
      RECT 3.5 55.5 3.7 55.7 ;
      RECT 3.5 63.9 3.7 64.1 ;
      RECT 3.5 64.3 3.7 64.5 ;
      RECT 2.8 1 3 1.2 ;
      RECT 2.8 1.6 3 1.8 ;
      RECT 2.8 2.2 3 2.4 ;
      RECT 2.8 2.8 3 3 ;
      RECT 2.8 216.6 3 216.8 ;
      RECT 2.8 217.2 3 217.4 ;
      RECT 2.8 217.8 3 218 ;
      RECT 2.8 218.4 3 218.6 ;
      RECT 2.2 1 2.4 1.2 ;
      RECT 2.2 1.6 2.4 1.8 ;
      RECT 2.2 2.2 2.4 2.4 ;
      RECT 2.2 2.8 2.4 3 ;
      RECT 2.2 216.6 2.4 216.8 ;
      RECT 2.2 217.2 2.4 217.4 ;
      RECT 2.2 217.8 2.4 218 ;
      RECT 2.2 218.4 2.4 218.6 ;
      RECT 1.6 1 1.8 1.2 ;
      RECT 1.6 1.6 1.8 1.8 ;
      RECT 1.6 2.2 1.8 2.4 ;
      RECT 1.6 2.8 1.8 3 ;
      RECT 1.6 216.6 1.8 216.8 ;
      RECT 1.6 217.2 1.8 217.4 ;
      RECT 1.6 217.8 1.8 218 ;
      RECT 1.6 218.4 1.8 218.6 ;
      RECT 1 1 1.2 1.2 ;
      RECT 1 1.6 1.2 1.8 ;
      RECT 1 2.2 1.2 2.4 ;
      RECT 1 2.8 1.2 3 ;
      RECT 1 216.6 1.2 216.8 ;
      RECT 1 217.2 1.2 217.4 ;
      RECT 1 217.8 1.2 218 ;
      RECT 1 218.4 1.2 218.6 ;
    LAYER M4 ;
      RECT 277 1 279 218.6 ;
      RECT 277 141.5 279.4 141.7 ;
      RECT 226.7 113.5 226.9 116.5 ;
      RECT 226.7 113.5 227.3 113.7 ;
      RECT 226.3 163.5 226.9 163.7 ;
      RECT 226.3 156.7 226.5 163.7 ;
      RECT 225.9 156.7 226.5 156.9 ;
      RECT 221.5 130.7 222.1 130.9 ;
      RECT 221.9 84.7 222.1 130.9 ;
      RECT 221.9 127.9 222.5 128.1 ;
      RECT 221.9 123.5 222.5 123.7 ;
      RECT 221.9 120.7 222.5 120.9 ;
      RECT 221.9 113.5 222.5 113.7 ;
      RECT 221.9 94.7 222.5 94.9 ;
      RECT 221.9 91.9 222.5 92.1 ;
      RECT 221.9 87.5 222.5 87.7 ;
      RECT 221.5 84.7 222.1 84.9 ;
      RECT 219.9 152.3 220.1 156.9 ;
      RECT 219.5 152.3 220.1 152.5 ;
      RECT 216.7 106.3 217.3 106.5 ;
      RECT 216.7 83.5 216.9 106.5 ;
      RECT 215.5 125.9 216.1 126.1 ;
      RECT 215.5 121.5 215.7 126.1 ;
      RECT 209.1 152.3 209.7 152.5 ;
      RECT 209.1 137.9 209.3 152.5 ;
      RECT 209.1 149.5 209.7 149.7 ;
      RECT 209.1 137.9 209.7 138.1 ;
      RECT 205.1 137.9 205.7 138.1 ;
      RECT 205.1 87.5 205.3 138.1 ;
      RECT 204.7 135.1 205.3 135.3 ;
      RECT 205.1 123.5 205.7 123.7 ;
      RECT 205.1 120.7 205.7 120.9 ;
      RECT 205.1 116.3 205.7 116.5 ;
      RECT 205.1 109.1 205.7 109.3 ;
      RECT 205.1 106.3 205.7 106.5 ;
      RECT 205.1 94.7 205.7 94.9 ;
      RECT 205.1 91.9 205.7 92.1 ;
      RECT 204.7 87.5 205.3 87.7 ;
      RECT 197.5 126.7 197.7 132.5 ;
      RECT 197.5 126.7 198.1 126.9 ;
      RECT 194.7 156.7 195.3 156.9 ;
      RECT 195.1 135.1 195.3 156.9 ;
      RECT 194.7 149.5 195.3 149.7 ;
      RECT 195.1 135.1 195.7 135.3 ;
      RECT 192.3 192.7 192.9 192.9 ;
      RECT 192.7 181.1 192.9 192.9 ;
      RECT 192.3 188.3 192.9 188.5 ;
      RECT 192.7 181.1 193.3 181.3 ;
      RECT 190.7 149.5 190.9 152.5 ;
      RECT 190.7 149.5 191.3 149.7 ;
      RECT 189.5 166.7 190.1 166.9 ;
      RECT 189.5 163.9 189.7 166.9 ;
      RECT 188.7 198.7 189.3 198.9 ;
      RECT 188.7 177.5 188.9 198.9 ;
      RECT 186.3 91.9 186.9 92.1 ;
      RECT 186.7 87.5 186.9 92.1 ;
      RECT 186.7 87.5 187.3 87.7 ;
      RECT 186.3 207.1 186.9 207.3 ;
      RECT 186.7 201.1 186.9 207.3 ;
      RECT 186.7 201.1 187.3 201.3 ;
      RECT 184.7 106.3 185.3 106.5 ;
      RECT 185.1 99.1 185.3 106.5 ;
      RECT 184.7 99.1 185.3 99.3 ;
      RECT 184.3 171.1 184.9 171.3 ;
      RECT 184.7 166.7 184.9 171.3 ;
      RECT 184.7 166.7 185.3 166.9 ;
      RECT 183.5 199.9 184.1 200.1 ;
      RECT 183.5 192.3 183.7 200.1 ;
      RECT 180.7 207.1 181.3 207.3 ;
      RECT 180.7 172.7 180.9 207.3 ;
      RECT 180.3 102.7 180.5 103.3 ;
      RECT 179.5 102.7 180.5 102.9 ;
      RECT 179.5 102.3 179.7 102.9 ;
      RECT 179.9 166.7 180.5 166.9 ;
      RECT 179.9 164.7 180.1 166.9 ;
      RECT 179.5 164.7 180.1 164.9 ;
      RECT 178.3 172.7 178.9 172.9 ;
      RECT 178.7 131.5 178.9 172.9 ;
      RECT 178.3 201.1 178.9 201.3 ;
      RECT 178.3 173.9 178.5 201.3 ;
      RECT 178.3 195.5 178.9 195.7 ;
      RECT 178.3 188.3 178.9 188.5 ;
      RECT 178.3 181.1 178.9 181.3 ;
      RECT 178.3 178.3 178.9 178.5 ;
      RECT 178.3 173.9 178.9 174.1 ;
      RECT 174.7 123.5 175.3 123.7 ;
      RECT 174.7 113.5 174.9 123.7 ;
      RECT 174.7 113.5 175.3 113.7 ;
      RECT 174.3 12.7 174.5 89.3 ;
      RECT 174.3 80.3 174.9 80.5 ;
      RECT 174.3 77.5 174.9 77.7 ;
      RECT 174.3 73.1 174.9 73.3 ;
      RECT 174.3 55.9 174.9 56.1 ;
      RECT 174.3 41.5 174.9 41.7 ;
      RECT 174.3 29.9 174.9 30.1 ;
      RECT 174.3 22.7 174.9 22.9 ;
      RECT 174.3 19.9 174.9 20.1 ;
      RECT 174.3 89.5 174.5 102.1 ;
      RECT 174.3 89.5 174.9 89.7 ;
      RECT 174.7 81.1 174.9 89.7 ;
      RECT 174.3 142.7 174.9 142.9 ;
      RECT 174.3 140.7 174.5 142.9 ;
      RECT 174.3 159.9 174.9 160.1 ;
      RECT 174.3 155.5 174.5 160.1 ;
      RECT 174.3 155.5 174.9 155.7 ;
      RECT 174.3 161.1 174.5 170.1 ;
      RECT 174.3 163.5 174.9 163.7 ;
      RECT 171.1 25.1 171.7 25.3 ;
      RECT 171.5 19.1 171.7 25.3 ;
      RECT 171.5 25.9 171.7 46.5 ;
      RECT 171.1 36.3 171.7 36.5 ;
      RECT 171.1 149.5 171.7 149.7 ;
      RECT 171.1 130.7 171.3 149.7 ;
      RECT 170.7 145.5 171.3 145.7 ;
      RECT 171.1 142.3 171.7 142.5 ;
      RECT 171.1 137.9 171.7 138.1 ;
      RECT 170.7 130.7 171.3 130.9 ;
      RECT 170.7 55.1 170.9 58.1 ;
      RECT 170.7 55.1 171.3 55.3 ;
      RECT 170.3 153.9 170.5 160.5 ;
      RECT 169.9 153.9 170.5 154.1 ;
      RECT 169.9 81.9 170.1 154.1 ;
      RECT 169.9 171.1 170.5 171.3 ;
      RECT 169.9 166.7 170.1 171.3 ;
      RECT 169.9 166.7 170.5 166.9 ;
      RECT 169.5 17.9 169.7 22.1 ;
      RECT 169.5 17.9 170.1 18.1 ;
      RECT 168.3 72.7 168.5 81.3 ;
      RECT 168.3 72.7 168.9 72.9 ;
      RECT 166.3 135.1 166.5 149.3 ;
      RECT 166.3 135.1 168.1 135.3 ;
      RECT 167.9 91.9 168.1 135.3 ;
      RECT 167.5 92.7 168.1 92.9 ;
      RECT 167.1 37.5 167.3 68.5 ;
      RECT 167.1 37.5 167.7 37.7 ;
      RECT 167.1 83.9 167.3 100.5 ;
      RECT 167.1 83.9 167.7 84.1 ;
      RECT 167.1 137.9 167.3 160.5 ;
      RECT 166.7 137.9 167.3 138.1 ;
      RECT 165.9 169.5 166.5 169.7 ;
      RECT 165.9 163.1 166.1 169.7 ;
      RECT 165.5 207.5 166.1 207.7 ;
      RECT 165.5 191.5 165.7 207.7 ;
      RECT 165.1 166.7 165.7 166.9 ;
      RECT 165.5 163.9 165.7 166.9 ;
      RECT 162.7 89.1 163.3 89.3 ;
      RECT 162.7 86.3 162.9 89.3 ;
      RECT 162.7 86.3 163.3 86.5 ;
      RECT 161.9 73.1 162.5 73.3 ;
      RECT 161.9 44.3 162.1 73.3 ;
      RECT 161.5 70.3 162.1 70.5 ;
      RECT 161.5 63.1 162.1 63.3 ;
      RECT 161.9 58.7 162.5 58.9 ;
      RECT 161.9 44.3 162.5 44.5 ;
      RECT 162.3 89.5 162.5 91.3 ;
      RECT 161.9 89.5 162.5 89.7 ;
      RECT 161.9 209.9 162.5 210.1 ;
      RECT 161.9 188.3 162.1 210.1 ;
      RECT 161.9 202.7 162.5 202.9 ;
      RECT 161.9 199.9 162.5 200.1 ;
      RECT 161.9 195.5 162.5 195.7 ;
      RECT 161.5 183.5 161.7 194.5 ;
      RECT 161.5 185.9 162.1 186.1 ;
      RECT 161.1 122.7 161.3 168.5 ;
      RECT 161.1 122.7 161.7 122.9 ;
      RECT 161.5 120.3 161.7 122.9 ;
      RECT 161.1 168.7 161.3 180.5 ;
      RECT 161.1 168.7 161.7 168.9 ;
      RECT 161.5 155.5 161.7 168.9 ;
      RECT 160.7 117.5 161.3 117.7 ;
      RECT 161.1 69.5 161.3 117.7 ;
      RECT 160.3 89.5 160.9 89.7 ;
      RECT 160.3 78.7 160.5 89.7 ;
      RECT 160.3 81.5 160.9 81.7 ;
      RECT 159.9 44.3 160.5 44.5 ;
      RECT 159.9 41.5 160.1 44.5 ;
      RECT 159.5 41.5 160.1 41.7 ;
      RECT 159.5 37.1 159.7 41.7 ;
      RECT 159.5 37.1 160.1 37.3 ;
      RECT 159.5 159.1 160.1 159.3 ;
      RECT 159.5 137.5 159.7 159.3 ;
      RECT 159.5 203.9 160.1 204.1 ;
      RECT 159.9 196.7 160.1 204.1 ;
      RECT 159.1 28.7 159.3 36.9 ;
      RECT 159.1 28.7 159.7 28.9 ;
      RECT 159.5 204.7 159.7 205.7 ;
      RECT 159.1 204.7 159.7 204.9 ;
      RECT 158.3 37.1 158.9 37.3 ;
      RECT 158.3 29.9 158.5 37.3 ;
      RECT 157.9 29.9 158.5 30.1 ;
      RECT 157.5 193.9 158.5 194.1 ;
      RECT 158.3 165.1 158.5 194.1 ;
      RECT 158.3 165.1 158.9 165.3 ;
      RECT 158.7 163.1 158.9 165.3 ;
      RECT 157.9 145.1 158.5 145.3 ;
      RECT 157.9 142.3 158.1 145.3 ;
      RECT 157.9 142.3 158.5 142.5 ;
      RECT 157.9 107.9 158.1 126.9 ;
      RECT 157.5 109.9 158.1 110.1 ;
      RECT 157.5 166.7 157.7 192.9 ;
      RECT 157.5 188.3 158.1 188.5 ;
      RECT 157.5 185.5 158.1 185.7 ;
      RECT 157.5 181.1 158.1 181.3 ;
      RECT 157.5 178.3 158.1 178.5 ;
      RECT 157.5 173.9 158.1 174.1 ;
      RECT 157.5 166.7 158.1 166.9 ;
      RECT 157.1 203.9 157.3 208.5 ;
      RECT 157.1 206.7 157.7 206.9 ;
      RECT 157.1 203.9 157.7 204.1 ;
      RECT 157.5 200.3 157.7 204.1 ;
      RECT 157.1 200.3 157.7 200.5 ;
      RECT 157.1 193.1 157.3 200.5 ;
      RECT 157.1 193.5 158.1 193.7 ;
      RECT 157.9 193.1 158.1 193.7 ;
      RECT 156.7 193.1 157.3 193.3 ;
      RECT 157.5 199.9 158.1 200.1 ;
      RECT 157.5 198.3 157.7 200.1 ;
      RECT 157.5 24.7 157.7 67.7 ;
      RECT 157.1 24.7 157.7 24.9 ;
      RECT 156.7 27.9 157.3 28.1 ;
      RECT 156.7 26.3 156.9 28.1 ;
      RECT 156.7 27.1 157.3 27.3 ;
      RECT 156.7 26.3 157.3 26.5 ;
      RECT 156.3 197.1 156.5 206.9 ;
      RECT 156.3 203.5 157.3 203.7 ;
      RECT 157.1 203.1 157.3 203.7 ;
      RECT 155.9 50.3 156.1 58.5 ;
      RECT 155.9 50.3 156.5 50.5 ;
      RECT 156.3 168.3 156.5 174.1 ;
      RECT 155.9 168.3 156.5 168.5 ;
      RECT 155.9 139.5 156.1 168.5 ;
      RECT 155.1 23.5 155.3 51.3 ;
      RECT 155.1 29.5 155.7 29.7 ;
      RECT 155.1 26.3 155.7 26.5 ;
      RECT 154.7 116.7 155.3 116.9 ;
      RECT 154.7 96.3 154.9 116.9 ;
      RECT 154.7 110.3 155.3 110.5 ;
      RECT 153.5 31.1 153.7 40.9 ;
      RECT 153.5 31.1 154.5 31.3 ;
      RECT 154.3 21.1 154.5 31.3 ;
      RECT 153.5 41.5 153.7 45.7 ;
      RECT 153.5 41.5 154.1 41.7 ;
      RECT 151.9 51.5 152.5 51.7 ;
      RECT 151.9 46.7 152.1 51.7 ;
      RECT 151.5 149.5 152.1 149.7 ;
      RECT 151.5 91.9 151.7 149.7 ;
      RECT 151.5 142.3 152.1 142.5 ;
      RECT 151.5 135.1 152.1 135.3 ;
      RECT 151.5 130.7 152.1 130.9 ;
      RECT 151.5 123.5 152.1 123.7 ;
      RECT 151.5 113.5 152.1 113.7 ;
      RECT 151.5 106.3 152.1 106.5 ;
      RECT 151.5 101.9 152.1 102.1 ;
      RECT 151.5 99.1 152.1 99.3 ;
      RECT 151.5 94.7 152.1 94.9 ;
      RECT 151.1 91.9 151.7 92.1 ;
      RECT 150.7 81.5 151.3 81.7 ;
      RECT 151.1 73.1 151.3 81.7 ;
      RECT 151.1 79.9 151.7 80.1 ;
      RECT 150.7 73.1 151.3 73.3 ;
      RECT 150.7 86.3 150.9 91.3 ;
      RECT 150.3 86.3 150.9 86.5 ;
      RECT 150.3 41.1 150.5 86.5 ;
      RECT 149.9 206.7 150.5 206.9 ;
      RECT 149.9 199.9 150.1 206.9 ;
      RECT 149.9 202.7 150.5 202.9 ;
      RECT 149.9 199.9 150.5 200.1 ;
      RECT 149.5 49.1 150.1 49.3 ;
      RECT 149.5 34.7 149.7 49.3 ;
      RECT 149.1 43.5 149.7 43.7 ;
      RECT 149.1 37.1 149.7 37.3 ;
      RECT 149.1 15.5 149.7 15.7 ;
      RECT 149.1 12.7 149.3 15.7 ;
      RECT 148.7 12.7 149.3 12.9 ;
      RECT 149.1 73.9 149.7 74.1 ;
      RECT 149.5 70.3 149.7 74.1 ;
      RECT 149.1 89.1 149.7 89.3 ;
      RECT 149.1 77.5 149.3 89.3 ;
      RECT 149.1 84.7 149.7 84.9 ;
      RECT 149.5 170.7 149.7 176.9 ;
      RECT 149.1 170.7 149.7 170.9 ;
      RECT 149.1 171.1 149.3 180.1 ;
      RECT 148.7 171.1 149.3 171.3 ;
      RECT 148.7 168.7 148.9 171.3 ;
      RECT 148.3 17.5 148.9 17.7 ;
      RECT 148.3 11.5 148.5 17.7 ;
      RECT 148.3 81.5 148.5 91.3 ;
      RECT 148.3 81.5 148.9 81.7 ;
      RECT 145.1 40.7 145.7 40.9 ;
      RECT 145.1 29.5 145.3 40.9 ;
      RECT 145.1 65.9 145.7 66.1 ;
      RECT 145.1 55.9 145.3 66.1 ;
      RECT 145.1 58.7 145.7 58.9 ;
      RECT 144.7 55.9 145.3 56.1 ;
      RECT 145.1 93.5 145.7 93.7 ;
      RECT 145.1 70.3 145.3 93.7 ;
      RECT 145.1 79.9 145.7 80.1 ;
      RECT 145.1 70.3 145.7 70.5 ;
      RECT 145.5 119.5 145.7 125.7 ;
      RECT 145.1 119.5 145.7 119.7 ;
      RECT 145.1 135.1 145.7 135.3 ;
      RECT 145.5 130.7 145.7 135.3 ;
      RECT 145.1 44.7 145.3 52.1 ;
      RECT 144.7 44.7 145.3 44.9 ;
      RECT 144.3 19.1 144.9 19.3 ;
      RECT 144.3 14.3 144.5 19.3 ;
      RECT 144.7 37.9 144.9 43.3 ;
      RECT 144.3 37.9 144.9 38.1 ;
      RECT 144.3 41.9 144.5 54.1 ;
      RECT 144.3 48.3 144.9 48.5 ;
      RECT 144.3 195.5 144.9 195.7 ;
      RECT 144.3 192.7 144.5 195.7 ;
      RECT 144.3 192.7 144.9 192.9 ;
      RECT 141.1 19.1 141.7 19.3 ;
      RECT 141.5 11.5 141.7 19.3 ;
      RECT 141.1 94.7 141.3 102.1 ;
      RECT 141.1 94.7 141.7 94.9 ;
      RECT 141.1 154.3 141.7 154.5 ;
      RECT 141.1 149.5 141.3 154.5 ;
      RECT 141.1 200.3 141.3 201.7 ;
      RECT 141.1 200.3 141.7 200.5 ;
      RECT 141.5 182.3 141.7 200.5 ;
      RECT 140.7 18.3 140.9 25.3 ;
      RECT 140.7 18.3 141.3 18.5 ;
      RECT 141.1 17.1 141.3 18.5 ;
      RECT 140.7 67.1 141.3 67.3 ;
      RECT 140.7 52.3 140.9 67.3 ;
      RECT 140.7 58.7 141.3 58.9 ;
      RECT 139.9 89.1 140.5 89.3 ;
      RECT 139.9 63.1 140.1 89.3 ;
      RECT 139.9 73.1 140.5 73.3 ;
      RECT 139.5 70.3 140.1 70.5 ;
      RECT 139.9 65.9 140.5 66.1 ;
      RECT 139.5 63.1 140.1 63.3 ;
      RECT 140.3 96.3 140.5 113.3 ;
      RECT 139.9 96.3 140.5 96.5 ;
      RECT 139.9 144.7 140.5 144.9 ;
      RECT 140.3 142.3 140.5 144.9 ;
      RECT 139.9 142.3 140.5 142.5 ;
      RECT 139.9 166.3 140.5 166.5 ;
      RECT 139.9 159.9 140.1 166.5 ;
      RECT 139.5 159.9 140.1 160.1 ;
      RECT 140.3 200.7 140.5 209.3 ;
      RECT 139.9 200.7 140.5 200.9 ;
      RECT 139.9 192.7 140.1 200.9 ;
      RECT 139.5 166.7 139.7 188.5 ;
      RECT 139.1 181.1 139.7 181.3 ;
      RECT 139.1 178.3 139.7 178.5 ;
      RECT 139.1 171.1 139.7 171.3 ;
      RECT 139.1 166.7 139.7 166.9 ;
      RECT 139.1 213.1 139.7 213.3 ;
      RECT 139.5 209.1 139.7 213.3 ;
      RECT 138.7 166.3 138.9 173.7 ;
      RECT 138.7 166.3 139.3 166.5 ;
      RECT 139.1 149.9 139.3 166.5 ;
      RECT 138.3 135.1 138.9 135.3 ;
      RECT 138.3 120.7 138.5 135.3 ;
      RECT 137.9 176.3 138.1 208.9 ;
      RECT 137.9 176.3 138.5 176.5 ;
      RECT 137.1 40.7 137.7 40.9 ;
      RECT 137.5 38.3 137.7 40.9 ;
      RECT 137.5 123.1 137.7 144.1 ;
      RECT 137.1 123.1 137.7 123.3 ;
      RECT 137.1 179.5 137.3 180.5 ;
      RECT 136.7 179.5 137.3 179.7 ;
      RECT 136.7 146.3 136.9 179.7 ;
      RECT 136.3 98.7 136.5 99.3 ;
      RECT 136.3 98.7 136.9 98.9 ;
      RECT 136.7 31.9 136.9 98.9 ;
      RECT 135.9 85.1 136.1 111.3 ;
      RECT 135.9 85.1 136.5 85.3 ;
      RECT 135.5 163.9 136.1 164.1 ;
      RECT 135.5 108.7 135.7 164.1 ;
      RECT 135.5 156.7 136.1 156.9 ;
      RECT 135.5 142.3 136.1 142.5 ;
      RECT 135.5 137.9 136.1 138.1 ;
      RECT 135.5 135.1 136.1 135.3 ;
      RECT 135.5 123.5 136.1 123.7 ;
      RECT 135.1 200.7 135.7 200.9 ;
      RECT 135.1 181.9 135.3 200.9 ;
      RECT 135.1 185.9 135.7 186.1 ;
      RECT 134.3 139.5 134.5 167.3 ;
      RECT 134.3 139.5 134.9 139.7 ;
      RECT 132.3 182.3 134.9 182.5 ;
      RECT 134.7 172.3 134.9 182.5 ;
      RECT 134.7 206.3 134.9 208.1 ;
      RECT 134.3 206.3 134.5 206.9 ;
      RECT 134.3 206.3 134.9 206.5 ;
      RECT 132.7 192.7 133.3 192.9 ;
      RECT 133.1 188.3 133.3 192.9 ;
      RECT 133.1 188.3 133.7 188.5 ;
      RECT 132.7 89.1 133.3 89.3 ;
      RECT 132.7 51.5 132.9 89.3 ;
      RECT 132.7 84.7 133.3 84.9 ;
      RECT 132.3 77.5 132.9 77.7 ;
      RECT 132.3 70.3 132.9 70.5 ;
      RECT 132.3 63.1 132.9 63.3 ;
      RECT 132.3 58.7 132.9 58.9 ;
      RECT 132.3 55.9 132.9 56.1 ;
      RECT 132.7 51.5 133.3 51.7 ;
      RECT 131.9 134.7 132.1 160.1 ;
      RECT 131.9 141.9 132.5 142.1 ;
      RECT 131.9 181.1 132.1 186.1 ;
      RECT 131.9 181.1 132.5 181.3 ;
      RECT 131.1 152.3 131.3 152.9 ;
      RECT 130.7 152.3 131.3 152.5 ;
      RECT 130.7 92.3 130.9 152.5 ;
      RECT 130.7 98.3 131.3 98.5 ;
      RECT 130.7 195.9 131.3 196.1 ;
      RECT 130.7 192.3 130.9 196.1 ;
      RECT 130.7 203.5 131.3 203.7 ;
      RECT 130.7 200.3 130.9 203.7 ;
      RECT 130.3 158.7 130.5 180.1 ;
      RECT 130.3 158.7 130.9 158.9 ;
      RECT 129.9 107.9 130.5 108.1 ;
      RECT 129.9 104.3 130.1 108.1 ;
      RECT 129.5 166.7 130.1 166.9 ;
      RECT 129.5 149.5 129.7 166.9 ;
      RECT 129.5 163.9 130.1 164.1 ;
      RECT 129.1 159.5 129.7 159.7 ;
      RECT 129.1 156.7 129.7 156.9 ;
      RECT 129.1 152.3 129.7 152.5 ;
      RECT 129.1 149.5 129.7 149.7 ;
      RECT 129.1 56.7 129.7 56.9 ;
      RECT 129.1 52.3 129.3 56.9 ;
      RECT 129.5 91.1 129.7 119.7 ;
      RECT 129.1 100.7 129.7 100.9 ;
      RECT 129.1 144.3 129.7 144.5 ;
      RECT 129.1 143.1 129.3 144.5 ;
      RECT 128.3 28.3 128.5 29.3 ;
      RECT 128.3 28.3 129.3 28.5 ;
      RECT 128.7 95.1 129.3 95.3 ;
      RECT 129.1 89.9 129.3 95.3 ;
      RECT 128.3 39.1 128.9 39.3 ;
      RECT 128.7 37.5 128.9 39.3 ;
      RECT 128.3 200.7 128.9 200.9 ;
      RECT 128.3 194.7 128.5 200.9 ;
      RECT 128.3 167.9 128.5 191.3 ;
      RECT 127.9 167.9 128.5 168.1 ;
      RECT 127.5 96.7 127.7 97.3 ;
      RECT 127.5 96.7 128.1 96.9 ;
      RECT 127.9 93.1 128.1 96.9 ;
      RECT 127.1 84.7 127.3 142.9 ;
      RECT 127.1 135.1 127.7 135.3 ;
      RECT 127.1 130.7 127.7 130.9 ;
      RECT 126.7 127.9 127.3 128.1 ;
      RECT 126.7 123.5 127.3 123.7 ;
      RECT 127.1 113.5 127.7 113.7 ;
      RECT 127.1 106.3 127.7 106.5 ;
      RECT 127.1 101.9 127.7 102.1 ;
      RECT 127.1 99.1 127.7 99.3 ;
      RECT 126.7 94.7 127.3 94.9 ;
      RECT 127.1 91.9 127.7 92.1 ;
      RECT 126.7 84.7 127.3 84.9 ;
      RECT 127.1 172.7 127.7 172.9 ;
      RECT 127.5 139.5 127.7 172.9 ;
      RECT 126.7 165.5 126.9 193.7 ;
      RECT 126.7 165.5 127.3 165.7 ;
      RECT 125.1 77.5 125.3 96.5 ;
      RECT 125.1 89.9 125.7 90.1 ;
      RECT 123.9 54.3 124.5 54.5 ;
      RECT 124.3 12.7 124.5 54.5 ;
      RECT 124.3 43.5 124.9 43.7 ;
      RECT 124.3 41.5 124.9 41.7 ;
      RECT 123.9 37.1 124.5 37.3 ;
      RECT 123.9 34.3 124.5 34.5 ;
      RECT 123.9 29.9 124.5 30.1 ;
      RECT 124.3 27.1 124.9 27.3 ;
      RECT 123.9 22.7 124.5 22.9 ;
      RECT 123.9 19.9 124.5 20.1 ;
      RECT 123.9 15.5 124.5 15.7 ;
      RECT 124.3 12.7 124.9 12.9 ;
      RECT 124.3 87.9 124.9 88.1 ;
      RECT 124.3 55.5 124.5 88.1 ;
      RECT 123.9 70.3 124.5 70.5 ;
      RECT 124.3 55.5 124.9 55.7 ;
      RECT 123.1 140.7 123.3 205.3 ;
      RECT 123.1 140.7 123.7 140.9 ;
      RECT 123.5 121.1 123.7 140.9 ;
      RECT 121.9 122.3 122.1 208.9 ;
      RECT 121.5 139.1 122.1 139.3 ;
      RECT 120.7 207.1 121.3 207.3 ;
      RECT 120.7 157.5 120.9 207.3 ;
      RECT 120.7 202.7 121.3 202.9 ;
      RECT 120.7 199.9 121.3 200.1 ;
      RECT 120.7 195.5 121.3 195.7 ;
      RECT 120.7 192.7 121.3 192.9 ;
      RECT 120.7 188.3 121.3 188.5 ;
      RECT 120.3 185.5 120.9 185.7 ;
      RECT 120.7 181.1 121.3 181.3 ;
      RECT 120.7 178.3 121.3 178.5 ;
      RECT 120.3 173.9 120.9 174.1 ;
      RECT 120.3 171.1 120.9 171.3 ;
      RECT 120.3 166.7 120.9 166.9 ;
      RECT 120.7 159.5 121.3 159.7 ;
      RECT 120.3 157.5 120.9 157.7 ;
      RECT 115.1 159.5 115.7 159.7 ;
      RECT 115.5 135.1 115.7 159.7 ;
      RECT 115.1 152.3 115.7 152.5 ;
      RECT 115.1 149.5 115.7 149.7 ;
      RECT 115.1 135.1 115.7 135.3 ;
      RECT 114.3 25.9 114.5 32.9 ;
      RECT 114.3 28.3 114.9 28.5 ;
      RECT 111.1 43.5 111.7 43.7 ;
      RECT 111.5 41.9 111.7 43.7 ;
      RECT 111.1 41.9 111.7 42.1 ;
      RECT 111.1 65.9 111.7 66.1 ;
      RECT 111.5 55.9 111.7 66.1 ;
      RECT 111.1 63.1 111.7 63.3 ;
      RECT 111.1 55.9 111.7 56.1 ;
      RECT 110.7 34.3 111.3 34.5 ;
      RECT 111.1 27.1 111.3 34.5 ;
      RECT 110.7 29.9 111.3 30.1 ;
      RECT 110.7 27.1 111.3 27.3 ;
      RECT 109.9 19.5 110.5 19.7 ;
      RECT 109.9 15.5 110.1 19.7 ;
      RECT 109.9 15.5 110.5 15.7 ;
      RECT 109.5 84.7 110.1 84.9 ;
      RECT 109.9 73.1 110.1 84.9 ;
      RECT 109.9 80.3 110.5 80.5 ;
      RECT 109.9 77.5 110.5 77.7 ;
      RECT 109.5 73.1 110.1 73.3 ;
      RECT 108.3 181.1 108.9 181.3 ;
      RECT 108.3 173.9 108.5 181.3 ;
      RECT 108.3 178.3 108.9 178.5 ;
      RECT 107.9 173.9 108.5 174.1 ;
      RECT 107.9 201.5 108.1 206.5 ;
      RECT 107.5 201.5 108.1 201.7 ;
      RECT 106.7 185.5 107.3 185.7 ;
      RECT 107.1 181.1 107.3 185.7 ;
      RECT 107.1 181.1 107.7 181.3 ;
      RECT 106.7 209.9 107.3 210.1 ;
      RECT 107.1 188.3 107.3 210.1 ;
      RECT 106.7 207.1 107.3 207.3 ;
      RECT 106.7 202.7 107.3 202.9 ;
      RECT 106.7 192.7 107.3 192.9 ;
      RECT 107.1 188.3 107.7 188.5 ;
      RECT 106.3 144.3 106.9 144.5 ;
      RECT 106.3 113.9 106.5 144.5 ;
      RECT 106.3 142.3 106.9 142.5 ;
      RECT 106.3 139.1 106.9 139.3 ;
      RECT 106.3 135.1 106.9 135.3 ;
      RECT 106.3 130.7 106.9 130.9 ;
      RECT 106.3 123.5 106.9 123.7 ;
      RECT 106.3 116.3 106.9 116.5 ;
      RECT 105.9 113.9 106.5 114.1 ;
      RECT 103.5 166.7 104.1 166.9 ;
      RECT 103.5 163.9 103.7 166.9 ;
      RECT 103.1 163.9 103.7 164.1 ;
      RECT 102.7 27.1 103.3 27.3 ;
      RECT 102.7 23.1 102.9 27.3 ;
      RECT 102.3 23.1 102.9 23.3 ;
      RECT 101.9 134.7 102.5 134.9 ;
      RECT 101.9 128.3 102.1 134.9 ;
      RECT 101.9 128.3 102.5 128.5 ;
      RECT 101.5 69.9 101.7 127.3 ;
      RECT 101.5 69.9 102.1 70.1 ;
      RECT 100.7 63.1 101.3 63.3 ;
      RECT 100.7 59.9 100.9 63.3 ;
      RECT 100.3 59.9 100.9 60.1 ;
      RECT 97.1 113.9 97.7 114.1 ;
      RECT 97.1 91.9 97.3 114.1 ;
      RECT 97.1 109.1 97.7 109.3 ;
      RECT 97.1 106.7 97.7 106.9 ;
      RECT 97.1 101.9 97.7 102.1 ;
      RECT 97.1 94.3 97.7 94.5 ;
      RECT 97.1 91.9 97.7 92.1 ;
      RECT 95.9 119.9 96.1 120.5 ;
      RECT 95.9 119.9 96.5 120.1 ;
      RECT 96.3 86.7 96.5 120.1 ;
      RECT 91.1 77.1 91.7 77.3 ;
      RECT 91.1 59.9 91.3 77.3 ;
      RECT 89.9 141.9 90.5 142.1 ;
      RECT 89.9 139.5 90.1 142.1 ;
      RECT 89.9 139.5 90.5 139.7 ;
      RECT 89.5 27.5 89.7 44.9 ;
      RECT 89.1 27.5 89.7 27.7 ;
      RECT 88.3 133.5 88.9 133.7 ;
      RECT 88.3 120.7 88.5 133.7 ;
      RECT 88.3 127.9 88.9 128.1 ;
      RECT 84.3 73.1 84.9 73.3 ;
      RECT 84.3 70.7 84.5 73.3 ;
      RECT 77.1 171.1 77.7 171.3 ;
      RECT 77.5 130.7 77.7 171.3 ;
      RECT 77.1 166.7 77.7 166.9 ;
      RECT 77.1 163.9 77.7 164.1 ;
      RECT 77.5 152.3 78.1 152.5 ;
      RECT 77.5 133.5 78.1 133.7 ;
      RECT 77.5 130.7 78.1 130.9 ;
      RECT 75.1 28.7 75.3 39.7 ;
      RECT 75.1 28.7 75.7 28.9 ;
      RECT 74.3 99.1 74.9 99.3 ;
      RECT 74.7 63.1 74.9 99.3 ;
      RECT 74.3 91.9 74.9 92.1 ;
      RECT 74.7 88.7 75.3 88.9 ;
      RECT 74.7 73.1 75.3 73.3 ;
      RECT 74.3 70.3 74.9 70.5 ;
      RECT 74.7 65.9 75.3 66.1 ;
      RECT 74.3 63.1 74.9 63.3 ;
      RECT 70.3 130.7 70.9 130.9 ;
      RECT 70.3 128.3 70.5 130.9 ;
      RECT 69.9 128.3 70.5 128.5 ;
      RECT 64.7 63.1 65.3 63.3 ;
      RECT 64.7 51.5 64.9 63.3 ;
      RECT 64.3 51.5 64.9 51.7 ;
      RECT 63.9 189.1 64.1 193.7 ;
      RECT 63.9 189.1 64.5 189.3 ;
      RECT 60.7 101.9 61.3 102.1 ;
      RECT 61.1 88.3 61.3 102.1 ;
      RECT 60.7 99.1 61.3 99.3 ;
      RECT 61.1 91.9 61.7 92.1 ;
      RECT 60.7 166.7 61.3 166.9 ;
      RECT 60.7 164.3 60.9 166.9 ;
      RECT 60.3 164.3 60.9 164.5 ;
      RECT 59.9 26.7 60.1 30.1 ;
      RECT 59.9 28.3 60.5 28.5 ;
      RECT 60.3 27.9 60.5 28.5 ;
      RECT 59.9 156.3 60.1 157.7 ;
      RECT 59.9 156.3 60.5 156.5 ;
      RECT 59.5 123.9 59.7 126.5 ;
      RECT 59.5 123.9 60.1 124.1 ;
      RECT 58.7 33.5 59.3 33.7 ;
      RECT 59.1 25.5 59.3 33.7 ;
      RECT 58.3 31.1 58.5 34.9 ;
      RECT 58.3 31.1 58.9 31.3 ;
      RECT 58.3 51.5 58.9 51.7 ;
      RECT 58.3 49.1 58.5 51.7 ;
      RECT 58.3 196.7 58.5 198.9 ;
      RECT 58.3 196.7 58.9 196.9 ;
      RECT 55.1 149.9 55.3 154.5 ;
      RECT 54.7 151.9 55.3 152.1 ;
      RECT 54.7 149.9 55.3 150.1 ;
      RECT 54.7 148.3 54.9 150.1 ;
      RECT 51.5 127.9 51.7 133.7 ;
      RECT 51.1 127.9 51.7 128.1 ;
      RECT 51.1 178.3 51.7 178.5 ;
      RECT 51.5 166.7 51.7 178.5 ;
      RECT 51.1 173.9 51.7 174.1 ;
      RECT 50.7 37.5 51.3 37.7 ;
      RECT 50.7 23.9 50.9 37.7 ;
      RECT 50.7 51.5 51.3 51.7 ;
      RECT 50.7 43.9 50.9 51.7 ;
      RECT 50.3 47.5 50.9 47.7 ;
      RECT 47.5 113.1 48.1 113.3 ;
      RECT 47.5 103.5 47.7 113.3 ;
      RECT 45.5 204.7 46.1 204.9 ;
      RECT 45.5 189.1 45.7 204.9 ;
      RECT 35.5 108.3 36.1 108.5 ;
      RECT 35.9 101.9 36.1 108.5 ;
      RECT 35.9 101.9 36.5 102.1 ;
      RECT 31.9 181.1 32.5 181.3 ;
      RECT 32.3 173.9 32.5 181.3 ;
      RECT 31.9 178.3 32.5 178.5 ;
      RECT 32.3 173.9 32.9 174.1 ;
      RECT 25.1 99.5 25.7 99.7 ;
      RECT 25.5 72.7 25.7 99.7 ;
      RECT 24.3 127.9 24.9 128.1 ;
      RECT 24.3 113.9 24.5 128.1 ;
      RECT 24.3 123.5 24.9 123.7 ;
      RECT 20.3 65.9 20.9 66.1 ;
      RECT 20.7 19.9 20.9 66.1 ;
      RECT 20.3 58.7 20.9 58.9 ;
      RECT 20.3 55.9 20.9 56.1 ;
      RECT 20.7 47.5 21.3 47.7 ;
      RECT 20.7 44.3 21.3 44.5 ;
      RECT 20.3 33.1 20.9 33.3 ;
      RECT 20.3 27.1 20.9 27.3 ;
      RECT 20.3 22.7 20.9 22.9 ;
      RECT 20.3 19.9 20.9 20.1 ;
      RECT 15.1 65.9 15.7 66.1 ;
      RECT 15.1 63.5 15.3 66.1 ;
      RECT 14.7 63.5 15.3 63.7 ;
      RECT 15.1 199.9 15.7 200.1 ;
      RECT 15.5 188.3 15.7 200.1 ;
      RECT 15.1 192.7 15.7 192.9 ;
      RECT 15.1 188.3 15.7 188.5 ;
      RECT 15.1 181.1 15.3 188.5 ;
      RECT 15.1 181.1 15.7 181.3 ;
      RECT 13.1 108.3 13.7 108.5 ;
      RECT 13.1 91.9 13.3 108.5 ;
      RECT 12.7 91.9 13.3 92.1 ;
      RECT 12.3 69.9 12.9 70.1 ;
      RECT 12.3 13.1 12.5 70.1 ;
      RECT 12.3 13.1 12.9 13.3 ;
      RECT 10.7 120.7 10.9 170.1 ;
      RECT 10.3 159.5 10.9 159.7 ;
      RECT 10.3 156.7 10.9 156.9 ;
      RECT 10.7 127.9 11.3 128.1 ;
      RECT 10.7 120.7 11.3 120.9 ;
      RECT 9.5 77.1 10.1 77.3 ;
      RECT 9.9 65.9 10.1 77.3 ;
      RECT 9.9 65.9 10.5 66.1 ;
      RECT 9.1 8.3 9.7 8.5 ;
      RECT 9.1 3.5 9.3 8.5 ;
      RECT 8.7 3.5 9.3 3.7 ;
      RECT 275 1.92 276 3.4 ;
      RECT 274 4 276 215.6 ;
      RECT 275 216.2 276 218.08 ;
      RECT 273.6 1.92 274.6 3.4 ;
      RECT 273.6 216.2 274.6 218.08 ;
      RECT 272.7 61.3 273.3 65.3 ;
      RECT 272.7 65.7 273.3 69.7 ;
      RECT 272.7 70.1 273.3 74.1 ;
      RECT 272.7 74.5 273.3 78.5 ;
      RECT 272.7 78.9 273.3 82.1 ;
      RECT 272.7 82.5 273.3 83.5 ;
      RECT 269.4 1.92 270.4 5.92 ;
      RECT 269.4 6.32 270.4 10.32 ;
      RECT 269.4 10.72 270.4 14.72 ;
      RECT 269.4 15.12 270.4 19.12 ;
      RECT 269.4 19.52 270.4 23.52 ;
      RECT 269.4 23.92 270.4 27.92 ;
      RECT 269.4 28.32 270.4 32.32 ;
      RECT 269.4 32.72 270.4 36.72 ;
      RECT 269.4 37.12 270.4 41.12 ;
      RECT 269.4 41.52 270.4 45.52 ;
      RECT 269.4 45.92 270.4 49.92 ;
      RECT 269.4 50.32 270.4 54.32 ;
      RECT 269.4 54.72 270.4 58.72 ;
      RECT 269.4 59.12 270.4 60.9 ;
      RECT 269.4 83.9 270.4 87.9 ;
      RECT 269.4 88.3 270.4 92.3 ;
      RECT 269.4 92.7 270.4 96.7 ;
      RECT 269.4 97.1 270.4 101.1 ;
      RECT 269.4 101.5 270.4 105.5 ;
      RECT 269.4 105.9 270.4 109.9 ;
      RECT 269.4 110.3 270.4 114.3 ;
      RECT 269.4 114.7 270.4 118.7 ;
      RECT 269.4 119.1 270.4 123.1 ;
      RECT 269.4 123.5 270.4 127.5 ;
      RECT 269.4 127.9 270.4 131.9 ;
      RECT 269.4 132.3 270.4 136.3 ;
      RECT 269.4 136.7 270.4 140.7 ;
      RECT 269.4 141.1 270.4 145.1 ;
      RECT 269.4 145.5 270.4 149.5 ;
      RECT 269.4 149.9 270.4 153.9 ;
      RECT 269.4 154.3 270.4 158.3 ;
      RECT 269.4 158.7 270.4 162.7 ;
      RECT 269.4 163.1 270.4 167.1 ;
      RECT 269.4 167.5 270.4 171.5 ;
      RECT 269.4 171.9 270.4 175.9 ;
      RECT 269.4 176.3 270.4 180.3 ;
      RECT 269.4 180.7 270.4 184.7 ;
      RECT 269.4 185.1 270.4 189.1 ;
      RECT 269.4 189.5 270.4 193.5 ;
      RECT 269.4 193.9 270.4 197.9 ;
      RECT 269.4 198.3 270.4 202.3 ;
      RECT 269.4 202.7 270.4 206.7 ;
      RECT 269.4 207.1 270.4 211.1 ;
      RECT 269.4 211.5 270.4 215.5 ;
      RECT 269.4 215.9 270.4 218.08 ;
      RECT 268.5 61.3 269.5 63.5 ;
      RECT 268.5 63.9 269.5 67.9 ;
      RECT 268.5 68.3 269.5 72.3 ;
      RECT 268.5 72.7 269.5 76.7 ;
      RECT 268.5 77.1 269.5 81.1 ;
      RECT 268.5 81.5 269.5 83.5 ;
      RECT 267.1 61.3 268.1 65.3 ;
      RECT 267.1 65.7 268.1 69.7 ;
      RECT 267.1 70.1 268.1 74.1 ;
      RECT 267.1 74.5 268.1 78.5 ;
      RECT 267.1 78.9 268.1 82.1 ;
      RECT 267.1 82.5 268.1 83.5 ;
      RECT 263.8 1.92 264.8 5.92 ;
      RECT 263.8 6.32 264.8 10.32 ;
      RECT 263.8 10.72 264.8 14.72 ;
      RECT 263.8 15.12 264.8 19.12 ;
      RECT 263.8 19.52 264.8 23.52 ;
      RECT 263.8 23.92 264.8 27.92 ;
      RECT 263.8 28.32 264.8 32.32 ;
      RECT 263.8 32.72 264.8 36.72 ;
      RECT 263.8 37.12 264.8 41.12 ;
      RECT 263.8 41.52 264.8 45.52 ;
      RECT 263.8 45.92 264.8 49.92 ;
      RECT 263.8 50.32 264.8 54.32 ;
      RECT 263.8 54.72 264.8 58.72 ;
      RECT 263.8 59.12 264.8 60.9 ;
      RECT 263.8 83.9 264.8 87.9 ;
      RECT 263.8 88.3 264.8 92.3 ;
      RECT 263.8 92.7 264.8 96.7 ;
      RECT 263.8 97.1 264.8 101.1 ;
      RECT 263.8 101.5 264.8 105.5 ;
      RECT 263.8 105.9 264.8 109.9 ;
      RECT 263.8 110.3 264.8 114.3 ;
      RECT 263.8 114.7 264.8 118.7 ;
      RECT 263.8 119.1 264.8 123.1 ;
      RECT 263.8 123.5 264.8 127.5 ;
      RECT 263.8 127.9 264.8 131.9 ;
      RECT 263.8 132.3 264.8 136.3 ;
      RECT 263.8 136.7 264.8 140.7 ;
      RECT 263.8 141.1 264.8 145.1 ;
      RECT 263.8 145.5 264.8 149.5 ;
      RECT 263.8 149.9 264.8 153.9 ;
      RECT 263.8 154.3 264.8 158.3 ;
      RECT 263.8 158.7 264.8 162.7 ;
      RECT 263.8 163.1 264.8 167.1 ;
      RECT 263.8 167.5 264.8 171.5 ;
      RECT 263.8 171.9 264.8 175.9 ;
      RECT 263.8 176.3 264.8 180.3 ;
      RECT 263.8 180.7 264.8 184.7 ;
      RECT 263.8 185.1 264.8 189.1 ;
      RECT 263.8 189.5 264.8 193.5 ;
      RECT 263.8 193.9 264.8 197.9 ;
      RECT 263.8 198.3 264.8 202.3 ;
      RECT 263.8 202.7 264.8 206.7 ;
      RECT 263.8 207.1 264.8 211.1 ;
      RECT 263.8 211.5 264.8 215.5 ;
      RECT 263.8 215.9 264.8 218.08 ;
      RECT 262.9 61.3 263.9 63.5 ;
      RECT 262.9 63.9 263.9 67.9 ;
      RECT 262.9 68.3 263.9 72.3 ;
      RECT 262.9 72.7 263.9 76.7 ;
      RECT 262.9 77.1 263.9 81.1 ;
      RECT 262.9 81.5 263.9 83.5 ;
      RECT 261.5 61.3 262.5 65.3 ;
      RECT 261.5 65.7 262.5 69.7 ;
      RECT 261.5 70.1 262.5 74.1 ;
      RECT 261.5 74.5 262.5 78.5 ;
      RECT 261.5 78.9 262.5 82.1 ;
      RECT 261.5 82.5 262.5 83.5 ;
      RECT 258.2 1.92 259.2 5.92 ;
      RECT 258.2 6.32 259.2 10.32 ;
      RECT 258.2 10.72 259.2 14.72 ;
      RECT 258.2 15.12 259.2 19.12 ;
      RECT 258.2 19.52 259.2 23.52 ;
      RECT 258.2 23.92 259.2 27.92 ;
      RECT 258.2 28.32 259.2 32.32 ;
      RECT 258.2 32.72 259.2 36.72 ;
      RECT 258.2 37.12 259.2 41.12 ;
      RECT 258.2 41.52 259.2 45.52 ;
      RECT 258.2 45.92 259.2 49.92 ;
      RECT 258.2 50.32 259.2 54.32 ;
      RECT 258.2 54.72 259.2 58.72 ;
      RECT 258.2 59.12 259.2 60.9 ;
      RECT 258.2 83.9 259.2 87.9 ;
      RECT 258.2 88.3 259.2 92.3 ;
      RECT 258.2 92.7 259.2 96.7 ;
      RECT 258.2 97.1 259.2 101.1 ;
      RECT 258.2 101.5 259.2 105.5 ;
      RECT 258.2 105.9 259.2 109.9 ;
      RECT 258.2 110.3 259.2 114.3 ;
      RECT 258.2 114.7 259.2 118.7 ;
      RECT 258.2 119.1 259.2 123.1 ;
      RECT 258.2 123.5 259.2 127.5 ;
      RECT 258.2 127.9 259.2 131.9 ;
      RECT 258.2 132.3 259.2 136.3 ;
      RECT 258.2 136.7 259.2 140.7 ;
      RECT 258.2 141.1 259.2 145.1 ;
      RECT 258.2 145.5 259.2 149.5 ;
      RECT 258.2 149.9 259.2 153.9 ;
      RECT 258.2 154.3 259.2 158.3 ;
      RECT 258.2 158.7 259.2 162.7 ;
      RECT 258.2 163.1 259.2 167.1 ;
      RECT 258.2 167.5 259.2 171.5 ;
      RECT 258.2 171.9 259.2 175.9 ;
      RECT 258.2 176.3 259.2 180.3 ;
      RECT 258.2 180.7 259.2 184.7 ;
      RECT 258.2 185.1 259.2 189.1 ;
      RECT 258.2 189.5 259.2 193.5 ;
      RECT 258.2 193.9 259.2 197.9 ;
      RECT 258.2 198.3 259.2 202.3 ;
      RECT 258.2 202.7 259.2 206.7 ;
      RECT 258.2 207.1 259.2 211.1 ;
      RECT 258.2 211.5 259.2 215.5 ;
      RECT 258.2 215.9 259.2 218.08 ;
      RECT 257.3 61.3 258.3 63.5 ;
      RECT 257.3 63.9 258.3 67.9 ;
      RECT 257.3 68.3 258.3 72.3 ;
      RECT 257.3 72.7 258.3 76.7 ;
      RECT 257.3 77.1 258.3 81.1 ;
      RECT 257.3 81.5 258.3 83.5 ;
      RECT 254 1.92 255 4.12 ;
      RECT 254 4.52 255 8.52 ;
      RECT 254 8.92 255 12.92 ;
      RECT 254 13.32 255 17.32 ;
      RECT 254 17.72 255 21.72 ;
      RECT 254 22.12 255 26.12 ;
      RECT 254 26.52 255 30.52 ;
      RECT 254 30.92 255 34.92 ;
      RECT 254 35.32 255 39.32 ;
      RECT 254 39.72 255 43.72 ;
      RECT 254 44.12 255 48.12 ;
      RECT 254 48.52 255 52.52 ;
      RECT 254 52.92 255 56.92 ;
      RECT 254 57.32 255 60.9 ;
      RECT 254 83.9 255 86.1 ;
      RECT 254 86.5 255 90.5 ;
      RECT 254 90.9 255 94.9 ;
      RECT 254 95.3 255 99.3 ;
      RECT 254 99.7 255 103.7 ;
      RECT 254 104.1 255 108.1 ;
      RECT 254 108.5 255 112.5 ;
      RECT 254 112.9 255 116.9 ;
      RECT 254 117.3 255 121.3 ;
      RECT 254 121.7 255 125.7 ;
      RECT 254 126.1 255 130.1 ;
      RECT 254 130.5 255 134.5 ;
      RECT 254 134.9 255 138.9 ;
      RECT 254 139.3 255 143.3 ;
      RECT 254 143.7 255 147.7 ;
      RECT 254 148.1 255 152.1 ;
      RECT 254 152.5 255 156.5 ;
      RECT 254 156.9 255 160.9 ;
      RECT 254 161.3 255 165.3 ;
      RECT 254 165.7 255 169.7 ;
      RECT 254 170.1 255 174.1 ;
      RECT 254 174.5 255 178.5 ;
      RECT 254 178.9 255 182.9 ;
      RECT 254 183.3 255 187.3 ;
      RECT 254 187.7 255 191.7 ;
      RECT 254 192.1 255 196.1 ;
      RECT 254 196.5 255 200.5 ;
      RECT 254 200.9 255 204.9 ;
      RECT 254 205.3 255 209.3 ;
      RECT 254 209.7 255 213.7 ;
      RECT 254 214.1 255 218.08 ;
      RECT 253.1 61.3 254.1 65.3 ;
      RECT 253.1 65.7 254.1 69.7 ;
      RECT 253.1 70.1 254.1 74.1 ;
      RECT 253.1 74.5 254.1 78.5 ;
      RECT 253.1 78.9 254.1 82.1 ;
      RECT 253.1 82.5 254.1 83.5 ;
      RECT 248.4 1.92 249.4 4.12 ;
      RECT 248.4 4.52 249.4 8.52 ;
      RECT 248.4 8.92 249.4 12.92 ;
      RECT 248.4 13.32 249.4 17.32 ;
      RECT 248.4 17.72 249.4 21.72 ;
      RECT 248.4 22.12 249.4 26.12 ;
      RECT 248.4 26.52 249.4 30.52 ;
      RECT 248.4 30.92 249.4 34.92 ;
      RECT 248.4 35.32 249.4 39.32 ;
      RECT 248.4 39.72 249.4 43.72 ;
      RECT 248.4 44.12 249.4 48.12 ;
      RECT 248.4 48.52 249.4 52.52 ;
      RECT 248.4 52.92 249.4 56.92 ;
      RECT 248.4 57.32 249.4 60.9 ;
      RECT 248.4 83.9 249.4 86.1 ;
      RECT 248.4 86.5 249.4 90.5 ;
      RECT 248.4 90.9 249.4 94.9 ;
      RECT 248.4 95.3 249.4 99.3 ;
      RECT 248.4 99.7 249.4 103.7 ;
      RECT 248.4 104.1 249.4 108.1 ;
      RECT 248.4 108.5 249.4 112.5 ;
      RECT 248.4 112.9 249.4 116.9 ;
      RECT 248.4 117.3 249.4 121.3 ;
      RECT 248.4 121.7 249.4 125.7 ;
      RECT 248.4 126.1 249.4 130.1 ;
      RECT 248.4 130.5 249.4 134.5 ;
      RECT 248.4 134.9 249.4 138.9 ;
      RECT 248.4 139.3 249.4 143.3 ;
      RECT 248.4 143.7 249.4 147.7 ;
      RECT 248.4 148.1 249.4 152.1 ;
      RECT 248.4 152.5 249.4 156.5 ;
      RECT 248.4 156.9 249.4 160.9 ;
      RECT 248.4 161.3 249.4 165.3 ;
      RECT 248.4 165.7 249.4 169.7 ;
      RECT 248.4 170.1 249.4 174.1 ;
      RECT 248.4 174.5 249.4 178.5 ;
      RECT 248.4 178.9 249.4 182.9 ;
      RECT 248.4 183.3 249.4 187.3 ;
      RECT 248.4 187.7 249.4 191.7 ;
      RECT 248.4 192.1 249.4 196.1 ;
      RECT 248.4 196.5 249.4 200.5 ;
      RECT 248.4 200.9 249.4 204.9 ;
      RECT 248.4 205.3 249.4 209.3 ;
      RECT 248.4 209.7 249.4 213.7 ;
      RECT 248.4 214.1 249.4 218.08 ;
      RECT 247.5 61.3 248.5 65.3 ;
      RECT 247.5 65.7 248.5 69.7 ;
      RECT 247.5 70.1 248.5 74.1 ;
      RECT 247.5 74.5 248.5 78.5 ;
      RECT 247.5 78.9 248.5 82.1 ;
      RECT 247.5 82.5 248.5 83.5 ;
      RECT 244.2 1.92 245.2 5.92 ;
      RECT 244.2 6.32 245.2 10.32 ;
      RECT 244.2 10.72 245.2 14.72 ;
      RECT 244.2 15.12 245.2 19.12 ;
      RECT 244.2 19.52 245.2 23.52 ;
      RECT 244.2 23.92 245.2 27.92 ;
      RECT 244.2 28.32 245.2 32.32 ;
      RECT 244.2 32.72 245.2 36.72 ;
      RECT 244.2 37.12 245.2 41.12 ;
      RECT 244.2 41.52 245.2 45.52 ;
      RECT 244.2 45.92 245.2 49.92 ;
      RECT 244.2 50.32 245.2 54.32 ;
      RECT 244.2 54.72 245.2 58.72 ;
      RECT 244.2 59.12 245.2 60.9 ;
      RECT 244.2 83.9 245.2 87.9 ;
      RECT 244.2 88.3 245.2 92.3 ;
      RECT 244.2 92.7 245.2 96.7 ;
      RECT 244.2 97.1 245.2 101.1 ;
      RECT 244.2 101.5 245.2 105.5 ;
      RECT 244.2 105.9 245.2 109.9 ;
      RECT 244.2 110.3 245.2 114.3 ;
      RECT 244.2 114.7 245.2 118.7 ;
      RECT 244.2 119.1 245.2 123.1 ;
      RECT 244.2 123.5 245.2 127.5 ;
      RECT 244.2 127.9 245.2 131.9 ;
      RECT 244.2 132.3 245.2 136.3 ;
      RECT 244.2 136.7 245.2 140.7 ;
      RECT 244.2 141.1 245.2 145.1 ;
      RECT 244.2 145.5 245.2 149.5 ;
      RECT 244.2 149.9 245.2 153.9 ;
      RECT 244.2 154.3 245.2 158.3 ;
      RECT 244.2 158.7 245.2 162.7 ;
      RECT 244.2 163.1 245.2 167.1 ;
      RECT 244.2 167.5 245.2 171.5 ;
      RECT 244.2 171.9 245.2 175.9 ;
      RECT 244.2 176.3 245.2 180.3 ;
      RECT 244.2 180.7 245.2 184.7 ;
      RECT 244.2 185.1 245.2 189.1 ;
      RECT 244.2 189.5 245.2 193.5 ;
      RECT 244.2 193.9 245.2 197.9 ;
      RECT 244.2 198.3 245.2 202.3 ;
      RECT 244.2 202.7 245.2 206.7 ;
      RECT 244.2 207.1 245.2 211.1 ;
      RECT 244.2 211.5 245.2 215.5 ;
      RECT 244.2 215.9 245.2 218.08 ;
      RECT 243.3 61.3 244.3 63.5 ;
      RECT 243.3 63.9 244.3 67.9 ;
      RECT 243.3 68.3 244.3 72.3 ;
      RECT 243.3 72.7 244.3 76.7 ;
      RECT 243.3 77.1 244.3 81.1 ;
      RECT 243.3 81.5 244.3 83.5 ;
      RECT 241.9 61.3 242.9 65.3 ;
      RECT 241.9 65.7 242.9 69.7 ;
      RECT 241.9 70.1 242.9 74.1 ;
      RECT 241.9 74.5 242.9 78.5 ;
      RECT 241.9 78.9 242.9 82.1 ;
      RECT 241.9 82.5 242.9 83.5 ;
      RECT 238.6 1.92 239.6 5.92 ;
      RECT 238.6 6.32 239.6 10.32 ;
      RECT 238.6 10.72 239.6 14.72 ;
      RECT 238.6 15.12 239.6 19.12 ;
      RECT 238.6 19.52 239.6 23.52 ;
      RECT 238.6 23.92 239.6 27.92 ;
      RECT 238.6 28.32 239.6 32.32 ;
      RECT 238.6 32.72 239.6 36.72 ;
      RECT 238.6 37.12 239.6 41.12 ;
      RECT 238.6 41.52 239.6 45.52 ;
      RECT 238.6 45.92 239.6 49.92 ;
      RECT 238.6 50.32 239.6 54.32 ;
      RECT 238.6 54.72 239.6 58.72 ;
      RECT 238.6 88.3 239.6 92.3 ;
      RECT 238.6 92.7 239.6 96.7 ;
      RECT 238.6 97.1 239.6 101.1 ;
      RECT 238.6 101.5 239.6 105.5 ;
      RECT 238.6 105.9 239.6 109.9 ;
      RECT 238.6 110.3 239.6 114.3 ;
      RECT 238.6 114.7 239.6 118.7 ;
      RECT 238.6 119.1 239.6 123.1 ;
      RECT 238.6 123.5 239.6 127.5 ;
      RECT 238.6 127.9 239.6 131.9 ;
      RECT 238.6 132.3 239.6 136.3 ;
      RECT 238.6 136.7 239.6 140.7 ;
      RECT 238.6 141.1 239.6 145.1 ;
      RECT 238.6 145.5 239.6 149.5 ;
      RECT 238.6 149.9 239.6 153.9 ;
      RECT 238.6 154.3 239.6 158.3 ;
      RECT 238.6 158.7 239.6 162.7 ;
      RECT 238.6 163.1 239.6 167.1 ;
      RECT 238.6 167.5 239.6 171.5 ;
      RECT 238.6 171.9 239.6 175.9 ;
      RECT 238.6 176.3 239.6 180.3 ;
      RECT 238.6 180.7 239.6 184.7 ;
      RECT 238.6 185.1 239.6 189.1 ;
      RECT 238.6 189.5 239.6 193.5 ;
      RECT 238.6 193.9 239.6 197.9 ;
      RECT 238.6 198.3 239.6 202.3 ;
      RECT 238.6 202.7 239.6 206.7 ;
      RECT 238.6 207.1 239.6 211.1 ;
      RECT 238.6 211.5 239.6 215.5 ;
      RECT 238.6 215.9 239.6 218.08 ;
      RECT 238.3 61.5 238.5 83.3 ;
      RECT 236 1 238 218.6 ;
      RECT 235.5 80.7 235.7 83.3 ;
      RECT 232 4 234 215.6 ;
      RECT 230 83.3 231 86.6 ;
      RECT 230 88.6 231 91 ;
      RECT 230 95.8 231 98 ;
      RECT 230 98.4 231 102.4 ;
      RECT 230 102.8 231 106.8 ;
      RECT 230 107.2 231 111.2 ;
      RECT 230 111.6 231 112.6 ;
      RECT 230 117.4 231 119.8 ;
      RECT 230 124.6 231 127 ;
      RECT 230 129 231 131.4 ;
      RECT 230 164.6 231 166.8 ;
      RECT 230 167.2 231 171.2 ;
      RECT 230 171.6 231 175.6 ;
      RECT 230 176 231 180 ;
      RECT 230 180.4 231 184.4 ;
      RECT 230 184.8 231 188.8 ;
      RECT 230 189.2 231 193.2 ;
      RECT 230 193.6 231 197.6 ;
      RECT 230 198 231 202 ;
      RECT 230 202.4 231 206.4 ;
      RECT 230 206.8 231 210.8 ;
      RECT 230 211.2 231 215.2 ;
      RECT 230 215.6 231 218.08 ;
      RECT 229.8 146.7 230.8 150 ;
      RECT 229.8 150.4 230.8 151.4 ;
      RECT 229.2 114.6 230.2 117 ;
      RECT 229.2 131.8 230.2 135.8 ;
      RECT 229.2 136.2 230.2 140.2 ;
      RECT 229.2 140.6 230.2 144.6 ;
      RECT 229.2 145 230.2 146.3 ;
      RECT 229.2 163 230.2 164.2 ;
      RECT 228.8 156.2 229.8 160.2 ;
      RECT 228.8 160.6 229.8 162.6 ;
      RECT 227.2 83.3 228.2 86.6 ;
      RECT 227.2 88.6 228.2 91 ;
      RECT 227.2 95.8 228.2 98 ;
      RECT 227.2 98.4 228.2 102.4 ;
      RECT 227.2 102.8 228.2 106.8 ;
      RECT 227.2 107.2 228.2 111.2 ;
      RECT 227.2 111.6 228.2 112.6 ;
      RECT 227.2 117.4 228.2 119.8 ;
      RECT 227.2 124.6 228.2 127 ;
      RECT 227.2 129 228.2 131.4 ;
      RECT 227.2 164.6 228.2 166.8 ;
      RECT 227.2 167.2 228.2 171.2 ;
      RECT 227.2 171.6 228.2 175.6 ;
      RECT 227.2 176 228.2 180 ;
      RECT 227.2 180.4 228.2 184.4 ;
      RECT 227.2 184.8 228.2 188.8 ;
      RECT 227.2 189.2 228.2 193.2 ;
      RECT 227.2 193.6 228.2 197.6 ;
      RECT 227.2 198 228.2 202 ;
      RECT 227.2 202.4 228.2 206.4 ;
      RECT 227.2 206.8 228.2 210.8 ;
      RECT 227.2 211.2 228.2 215.2 ;
      RECT 227.2 215.6 228.2 218.08 ;
      RECT 227 146.7 228 150 ;
      RECT 227 150.4 228 151.4 ;
      RECT 225.4 1.92 226.4 5.92 ;
      RECT 225.4 6.32 226.4 10.32 ;
      RECT 225.4 10.72 226.4 14.72 ;
      RECT 225.4 15.12 226.4 19.12 ;
      RECT 225.4 19.52 226.4 23.52 ;
      RECT 225.4 23.92 226.4 27.92 ;
      RECT 225.4 28.32 226.4 32.32 ;
      RECT 225.4 32.72 226.4 36.72 ;
      RECT 225.4 37.12 226.4 41.12 ;
      RECT 225.4 41.52 226.4 45.52 ;
      RECT 225.4 45.92 226.4 49.92 ;
      RECT 225.4 50.32 226.4 54.32 ;
      RECT 225.4 54.72 226.4 58.72 ;
      RECT 225.4 59.12 226.4 63.12 ;
      RECT 225.4 63.52 226.4 67.52 ;
      RECT 225.4 67.92 226.4 71.92 ;
      RECT 225.4 72.32 226.4 76.32 ;
      RECT 225.4 76.72 226.4 80.72 ;
      RECT 225.4 81.12 226.4 82.9 ;
      RECT 225.2 151.8 226.2 155.8 ;
      RECT 224.8 87 225.8 88.2 ;
      RECT 224.8 91.4 225.8 95.4 ;
      RECT 224.8 120.2 225.8 124.2 ;
      RECT 224.8 127.4 225.8 128.6 ;
      RECT 224.2 146.7 225.2 150 ;
      RECT 224.2 150.4 225.2 151.4 ;
      RECT 222.6 1.92 223.6 5.92 ;
      RECT 222.6 6.32 223.6 10.32 ;
      RECT 222.6 10.72 223.6 14.72 ;
      RECT 222.6 15.12 223.6 19.12 ;
      RECT 222.6 19.52 223.6 23.52 ;
      RECT 222.6 23.92 223.6 27.92 ;
      RECT 222.6 28.32 223.6 32.32 ;
      RECT 222.6 32.72 223.6 36.72 ;
      RECT 222.6 37.12 223.6 41.12 ;
      RECT 222.6 41.52 223.6 45.52 ;
      RECT 222.6 45.92 223.6 49.92 ;
      RECT 222.6 50.32 223.6 54.32 ;
      RECT 222.6 54.72 223.6 58.72 ;
      RECT 222.6 59.12 223.6 63.12 ;
      RECT 222.6 63.52 223.6 67.52 ;
      RECT 222.6 67.92 223.6 71.92 ;
      RECT 222.6 72.32 223.6 76.32 ;
      RECT 222.6 76.72 223.6 80.72 ;
      RECT 222.6 81.12 223.6 82.9 ;
      RECT 222.4 151.8 223.4 155.8 ;
      RECT 222.4 156.2 223.4 157.4 ;
      RECT 220.8 157.8 221.8 160 ;
      RECT 220.8 160.4 221.8 164.4 ;
      RECT 220.8 164.8 221.8 168.8 ;
      RECT 220.8 169.2 221.8 173.2 ;
      RECT 220.8 173.6 221.8 177.6 ;
      RECT 220.8 178 221.8 182 ;
      RECT 220.8 182.4 221.8 186.4 ;
      RECT 220.8 186.8 221.8 190.8 ;
      RECT 220.8 191.2 221.8 195.2 ;
      RECT 220.8 195.6 221.8 199.6 ;
      RECT 220.8 200 221.8 204 ;
      RECT 220.8 204.4 221.8 208.4 ;
      RECT 220.8 208.8 221.8 212.8 ;
      RECT 220.8 213.2 221.8 216.68 ;
      RECT 220.8 217.08 221.8 218.08 ;
      RECT 220 146.7 221 150 ;
      RECT 220 150.4 221 151.4 ;
      RECT 219.5 103.9 219.7 114.9 ;
      RECT 219.5 132.3 219.7 144.9 ;
      RECT 218.3 88.3 218.5 99.3 ;
      RECT 217 1.92 218 5.92 ;
      RECT 217 6.32 218 10.32 ;
      RECT 217 10.72 218 14.72 ;
      RECT 217 15.12 218 19.12 ;
      RECT 217 19.52 218 23.52 ;
      RECT 217 23.92 218 27.92 ;
      RECT 217 28.32 218 32.32 ;
      RECT 217 32.72 218 36.72 ;
      RECT 217 37.12 218 41.12 ;
      RECT 217 41.52 218 45.52 ;
      RECT 217 45.92 218 49.92 ;
      RECT 217 50.32 218 54.32 ;
      RECT 217 54.72 218 58.72 ;
      RECT 217 59.12 218 63.12 ;
      RECT 217 63.52 218 67.52 ;
      RECT 217 67.92 218 71.92 ;
      RECT 217 72.32 218 76.32 ;
      RECT 217 76.72 218 80.72 ;
      RECT 217 81.12 218 82.9 ;
      RECT 217 153.4 218 157.4 ;
      RECT 217 157.8 218 161.8 ;
      RECT 217 162.2 218 166.2 ;
      RECT 217 166.6 218 170.6 ;
      RECT 217 171 218 175 ;
      RECT 217 175.4 218 179.4 ;
      RECT 217 179.8 218 183.8 ;
      RECT 217 184.2 218 188.2 ;
      RECT 217 188.6 218 192.6 ;
      RECT 217 193 218 197 ;
      RECT 217 197.4 218 201.4 ;
      RECT 217 201.8 218 205.8 ;
      RECT 217 206.2 218 210.2 ;
      RECT 217 210.6 218 214.6 ;
      RECT 217 215 218 218.08 ;
      RECT 216.9 117.5 217.9 120.9 ;
      RECT 217.5 134.3 217.7 146.1 ;
      RECT 216.2 150.6 216.8 153 ;
      RECT 214.8 140 215.8 144 ;
      RECT 214.8 144.4 215.8 148.4 ;
      RECT 214.8 148.8 215.8 152.8 ;
      RECT 215.5 97.1 215.7 116.9 ;
      RECT 214.7 97.9 214.9 125.3 ;
      RECT 211.4 1.92 212.4 5.92 ;
      RECT 211.4 6.32 212.4 10.32 ;
      RECT 211.4 10.72 212.4 14.72 ;
      RECT 211.4 15.12 212.4 19.12 ;
      RECT 211.4 19.52 212.4 23.52 ;
      RECT 211.4 23.92 212.4 27.92 ;
      RECT 211.4 28.32 212.4 32.32 ;
      RECT 211.4 32.72 212.4 36.72 ;
      RECT 211.4 37.12 212.4 41.12 ;
      RECT 211.4 41.52 212.4 45.52 ;
      RECT 211.4 45.92 212.4 49.92 ;
      RECT 211.4 50.32 212.4 54.32 ;
      RECT 211.4 54.72 212.4 58.72 ;
      RECT 211.4 59.12 212.4 63.12 ;
      RECT 211.4 63.52 212.4 67.52 ;
      RECT 211.4 67.92 212.4 71.92 ;
      RECT 211.4 72.32 212.4 76.32 ;
      RECT 211.4 76.72 212.4 80.72 ;
      RECT 211.4 81.12 212.4 82.9 ;
      RECT 211.4 83.3 212.4 87.3 ;
      RECT 211.4 87.7 212.4 91.7 ;
      RECT 211.4 92.1 212.4 96.1 ;
      RECT 211.4 115.9 212.4 119.9 ;
      RECT 211.4 120.3 212.4 124.3 ;
      RECT 211.4 124.7 212.4 128.7 ;
      RECT 211.4 129.1 212.4 133.1 ;
      RECT 211.4 133.5 212.4 137 ;
      RECT 211.4 153.4 212.4 157.4 ;
      RECT 211.4 157.8 212.4 161.8 ;
      RECT 211.4 162.2 212.4 166.2 ;
      RECT 211.4 166.6 212.4 170.6 ;
      RECT 211.4 171 212.4 175 ;
      RECT 211.4 175.4 212.4 179.4 ;
      RECT 211.4 179.8 212.4 183.8 ;
      RECT 211.4 184.2 212.4 188.2 ;
      RECT 211.4 188.6 212.4 192.6 ;
      RECT 211.4 193 212.4 197 ;
      RECT 211.4 197.4 212.4 201.4 ;
      RECT 211.4 201.8 212.4 205.8 ;
      RECT 211.4 206.2 212.4 210.2 ;
      RECT 211.4 210.6 212.4 214.6 ;
      RECT 211.4 215 212.4 218.08 ;
      RECT 211.9 101.1 212.1 110.9 ;
      RECT 210.3 101.5 210.5 108.9 ;
      RECT 206 1 208 218.6 ;
      RECT 204.6 1.92 205.4 3.4 ;
      RECT 204.6 4.2 205.4 8.2 ;
      RECT 204.6 8.6 205.4 12.6 ;
      RECT 204.6 13 205.4 17 ;
      RECT 204.6 17.4 205.4 21.4 ;
      RECT 204.6 21.8 205.4 25.8 ;
      RECT 204.6 26.2 205.4 30.2 ;
      RECT 204.6 30.6 205.4 34.6 ;
      RECT 204.6 35 205.4 39 ;
      RECT 204.6 39.4 205.4 43.4 ;
      RECT 204.6 43.8 205.4 47.8 ;
      RECT 204.6 48.2 205.4 52.2 ;
      RECT 204.6 52.6 205.4 56.6 ;
      RECT 204.6 57 205.4 61 ;
      RECT 204.6 61.4 205.4 65.4 ;
      RECT 204.6 65.8 205.4 69.8 ;
      RECT 204.6 70.2 205.4 74.2 ;
      RECT 204.6 74.6 205.4 78.6 ;
      RECT 204.6 79 205.4 83 ;
      RECT 204.6 143.6 205.4 147.6 ;
      RECT 204.6 148 205.4 152 ;
      RECT 204.6 152.4 205.4 156.4 ;
      RECT 204.6 156.8 205.4 160.8 ;
      RECT 204.6 161.2 205.4 165.2 ;
      RECT 204.6 165.6 205.4 169.6 ;
      RECT 204.6 170 205.4 174 ;
      RECT 204.6 174.4 205.4 178.4 ;
      RECT 204.6 178.8 205.4 182.8 ;
      RECT 204.6 183.2 205.4 187.2 ;
      RECT 204.6 187.6 205.4 191.6 ;
      RECT 204.6 192 205.4 196 ;
      RECT 204.6 196.4 205.4 200.4 ;
      RECT 204.6 200.8 205.4 204.8 ;
      RECT 204.6 205.2 205.4 209.2 ;
      RECT 204.6 209.6 205.4 213.6 ;
      RECT 204.6 214 205.4 215.4 ;
      RECT 204.6 216.2 205.4 218.08 ;
      RECT 204.3 91.1 204.5 102.9 ;
      RECT 204.3 112.7 204.5 121.7 ;
      RECT 203.2 1.92 204.2 3.4 ;
      RECT 203.2 216.2 204.2 218.08 ;
      RECT 202 4 204 215.6 ;
      RECT 201.8 1.92 202.8 3.4 ;
      RECT 201.8 216.2 202.8 218.08 ;
      RECT 201.5 121.5 201.7 145.3 ;
      RECT 200.4 88.6 201.4 92.6 ;
      RECT 200.4 163.4 201.4 165.8 ;
      RECT 200.4 202.2 201.4 204.4 ;
      RECT 200.4 204.8 201.4 208.8 ;
      RECT 200.9 157.8 201.3 161.6 ;
      RECT 200.9 162 201.3 163 ;
      RECT 200.7 172.2 201.3 176.2 ;
      RECT 200.7 176.6 201.3 180.2 ;
      RECT 200.2 98.6 201.2 102.6 ;
      RECT 200.2 103 201.2 107 ;
      RECT 200.1 193.8 201.1 197.7 ;
      RECT 200.1 198.1 201.1 199.1 ;
      RECT 200.4 152 200.8 156 ;
      RECT 200.4 156.4 200.8 157.4 ;
      RECT 199.8 167.8 200.8 171.8 ;
      RECT 199.8 180.6 200.8 181.8 ;
      RECT 200.3 112.7 200.5 130.9 ;
      RECT 199 88.6 200 92.6 ;
      RECT 199 140.6 200 144.6 ;
      RECT 199 145 200 149 ;
      RECT 199 149.4 200 153.4 ;
      RECT 199 153.8 200 157.4 ;
      RECT 199 163.4 200 165.8 ;
      RECT 199 202.2 200 206.2 ;
      RECT 199 206.6 200 209.1 ;
      RECT 198.8 98.6 199.8 100.8 ;
      RECT 198.8 101.2 199.8 105.2 ;
      RECT 198.8 105.6 199.8 107 ;
      RECT 198.7 193.8 199.7 197.7 ;
      RECT 198.7 198.1 199.7 199.1 ;
      RECT 198.4 167.8 199.4 171.8 ;
      RECT 198.4 180.6 199.4 181.8 ;
      RECT 197.6 88.6 198.6 92.6 ;
      RECT 197.6 136.2 198.6 138.4 ;
      RECT 197.6 138.8 198.6 142.8 ;
      RECT 197.6 143.2 198.6 147.2 ;
      RECT 197.6 147.6 198.6 151.6 ;
      RECT 197.6 152 198.6 156 ;
      RECT 197.6 156.4 198.6 157.4 ;
      RECT 197.6 163.4 198.6 165.8 ;
      RECT 197.6 202.2 198.6 204.4 ;
      RECT 197.6 204.8 198.6 208.8 ;
      RECT 197.4 98.6 198.4 102.6 ;
      RECT 197.4 103 198.4 107 ;
      RECT 197.3 193.8 198.3 197.7 ;
      RECT 197.3 198.1 198.3 199.1 ;
      RECT 197 167.8 198 171.8 ;
      RECT 197 180.6 198 181.8 ;
      RECT 196.6 87 197.6 88.2 ;
      RECT 196.6 166.2 197.6 167.4 ;
      RECT 196.6 182.2 197.6 186.2 ;
      RECT 196.6 186.6 197.6 190.6 ;
      RECT 196.6 191 197.6 193.4 ;
      RECT 196.6 199.5 197.6 201.8 ;
      RECT 196.2 88.6 197.2 92.6 ;
      RECT 196.2 163.4 197.2 165.8 ;
      RECT 196.2 202.2 197.2 206.2 ;
      RECT 196.2 206.6 197.2 209.1 ;
      RECT 196 98.6 197 100.8 ;
      RECT 196 101.2 197 105.2 ;
      RECT 196 105.6 197 107 ;
      RECT 195.9 193.8 196.9 197.7 ;
      RECT 195.9 198.1 196.9 199.1 ;
      RECT 195.6 167.8 196.6 171.8 ;
      RECT 195.6 180.6 196.6 181.8 ;
      RECT 195.2 87 196.2 88.2 ;
      RECT 195.2 166.2 196.2 167.4 ;
      RECT 195.2 182.2 196.2 184.4 ;
      RECT 195.2 184.8 196.2 188.8 ;
      RECT 195.2 189.2 196.2 193.2 ;
      RECT 195.2 199.5 196.2 201.8 ;
      RECT 195.1 172.2 196.1 176.2 ;
      RECT 195.1 176.6 196.1 180.2 ;
      RECT 194.8 88.6 195.8 92.6 ;
      RECT 194.8 163.4 195.8 165.8 ;
      RECT 194.8 202.2 195.8 204.4 ;
      RECT 194.8 204.8 195.8 208.8 ;
      RECT 194.6 98.6 195.6 102.6 ;
      RECT 194.6 103 195.6 107 ;
      RECT 194.5 124.9 195.5 127.5 ;
      RECT 194.5 129.3 195.5 130.9 ;
      RECT 194.5 193.8 195.5 197.7 ;
      RECT 194.5 198.1 195.5 199.1 ;
      RECT 194.2 167.8 195.2 171.8 ;
      RECT 193.4 88.6 194.4 92.6 ;
      RECT 193.4 163.4 194.4 165.8 ;
      RECT 193.4 202.2 194.4 206.2 ;
      RECT 193.4 206.6 194.4 209.1 ;
      RECT 193.2 98.6 194.2 100.8 ;
      RECT 193.2 101.2 194.2 105.2 ;
      RECT 193.2 105.6 194.2 107 ;
      RECT 193.1 124.9 194.1 127.5 ;
      RECT 193.1 129.3 194.1 130.9 ;
      RECT 193.1 131.3 194.1 135.3 ;
      RECT 193.1 135.7 194.1 139.7 ;
      RECT 193.1 140.1 194.1 144.1 ;
      RECT 193.1 144.5 194.1 148.5 ;
      RECT 193.1 193.8 194.1 197.7 ;
      RECT 193.1 198.1 194.1 199.1 ;
      RECT 192.8 167.8 193.8 171.8 ;
      RECT 192 88.6 193 92.6 ;
      RECT 192 163.4 193 165.8 ;
      RECT 192 202.2 193 204.4 ;
      RECT 192 204.8 193 208.8 ;
      RECT 191.8 98.6 192.8 102.6 ;
      RECT 191.8 103 192.8 107 ;
      RECT 191.7 124.9 192.7 127.5 ;
      RECT 191.7 129.3 192.7 130.9 ;
      RECT 191.7 131.3 192.7 133.5 ;
      RECT 191.7 133.9 192.7 137.9 ;
      RECT 191.7 138.3 192.7 142.3 ;
      RECT 191.7 142.7 192.7 146.7 ;
      RECT 191.7 147.1 192.7 148.6 ;
      RECT 191.7 193.8 192.7 197.7 ;
      RECT 191.7 198.1 192.7 199.1 ;
      RECT 191.4 167.8 192.4 171.8 ;
      RECT 191.1 155.9 192.1 159.9 ;
      RECT 191.1 160.3 192.1 163 ;
      RECT 190.6 88.6 191.6 92.6 ;
      RECT 190.6 202.2 191.6 206.2 ;
      RECT 190.6 206.6 191.6 209.1 ;
      RECT 190.4 98.6 191.4 100.8 ;
      RECT 190.4 101.2 191.4 105.2 ;
      RECT 190.4 105.6 191.4 107 ;
      RECT 190.3 124.9 191.3 127.5 ;
      RECT 190.3 129.3 191.3 130.9 ;
      RECT 190.3 131.3 191.3 135.3 ;
      RECT 190.3 135.7 191.3 139.7 ;
      RECT 190.3 140.1 191.3 144.1 ;
      RECT 190.3 144.5 191.3 148.5 ;
      RECT 190 167.8 191 171.8 ;
      RECT 189.7 155.9 190.7 158.1 ;
      RECT 189.7 158.5 190.7 161.6 ;
      RECT 189.7 162 190.7 163 ;
      RECT 189.2 88.6 190.2 92.6 ;
      RECT 189.2 202.2 190.2 204.4 ;
      RECT 189.2 204.8 190.2 208.8 ;
      RECT 189 98.6 190 102.6 ;
      RECT 189 103 190 107 ;
      RECT 188.9 124.9 189.9 127.5 ;
      RECT 188.9 129.3 189.9 130.9 ;
      RECT 188.9 131.3 189.9 133.5 ;
      RECT 188.9 133.9 189.9 137.9 ;
      RECT 188.9 138.3 189.9 142.3 ;
      RECT 188.9 142.7 189.9 146.7 ;
      RECT 188.9 147.1 189.9 148.6 ;
      RECT 188.6 167.8 189.6 171.8 ;
      RECT 188.3 155.9 189.3 159.9 ;
      RECT 188.3 160.3 189.3 163 ;
      RECT 187.6 98.6 188.6 100.8 ;
      RECT 187.6 101.2 188.6 105.2 ;
      RECT 187.6 105.6 188.6 107 ;
      RECT 187.5 124.9 188.5 127.5 ;
      RECT 187.5 129.3 188.5 130.9 ;
      RECT 187.5 131.3 188.5 135.3 ;
      RECT 187.5 135.7 188.5 139.7 ;
      RECT 187.5 140.1 188.5 144.1 ;
      RECT 187.5 144.5 188.5 148.5 ;
      RECT 187.5 149 188.5 151.5 ;
      RECT 187.2 167.8 188.2 171.8 ;
      RECT 187.5 193.9 187.7 196.9 ;
      RECT 185.5 177.1 185.7 197.3 ;
      RECT 184.2 1.92 185.2 5.92 ;
      RECT 184.2 6.32 185.2 10.32 ;
      RECT 184.2 10.72 185.2 14.72 ;
      RECT 184.2 15.12 185.2 19.12 ;
      RECT 184.2 19.52 185.2 23.52 ;
      RECT 184.2 23.92 185.2 27.92 ;
      RECT 184.2 28.32 185.2 32.32 ;
      RECT 184.2 32.72 185.2 36.72 ;
      RECT 184.2 37.12 185.2 41.12 ;
      RECT 184.2 41.52 185.2 45.52 ;
      RECT 184.2 45.92 185.2 49.92 ;
      RECT 184.2 50.32 185.2 54.32 ;
      RECT 184.2 54.72 185.2 58.72 ;
      RECT 184.2 59.12 185.2 63.12 ;
      RECT 184.2 63.52 185.2 67.52 ;
      RECT 184.2 67.92 185.2 71.92 ;
      RECT 184.2 72.32 185.2 76.32 ;
      RECT 184.2 76.72 185.2 80.72 ;
      RECT 184.2 81.12 185.2 85.12 ;
      RECT 184.2 85.52 185.2 86.6 ;
      RECT 184.2 87 185.2 91 ;
      RECT 184.2 91.4 185.2 95.4 ;
      RECT 184.2 111.8 185.2 115.8 ;
      RECT 184.2 116.2 185.2 120.2 ;
      RECT 184.2 120.6 185.2 124.5 ;
      RECT 184.2 127.9 185.2 128.9 ;
      RECT 184.2 209.5 185.2 213.5 ;
      RECT 184.2 213.9 185.2 217.9 ;
      RECT 184.1 158.5 185.1 161.6 ;
      RECT 183.3 124.9 184.3 127.5 ;
      RECT 183.3 129.3 184.3 130.9 ;
      RECT 183.3 205.1 184.3 207.5 ;
      RECT 183.9 132.3 184.1 151.3 ;
      RECT 183.5 155.1 184.1 155.3 ;
      RECT 183.1 164.3 183.3 184.9 ;
      RECT 182.7 181.1 182.9 192.1 ;
      RECT 182.7 195.5 182.9 198.9 ;
      RECT 181.9 145.9 182.1 171.7 ;
      RECT 181.5 176.7 182.1 180.7 ;
      RECT 181.5 181.1 182.1 185.1 ;
      RECT 181.5 185.5 182.1 189.5 ;
      RECT 181.5 189.9 182.1 193.9 ;
      RECT 181.5 194.3 182.1 198.3 ;
      RECT 181.5 198.7 182.1 202.7 ;
      RECT 179.5 144.3 179.7 148.9 ;
      RECT 179.5 198.3 179.7 205.3 ;
      RECT 178.6 1.92 179.6 5.92 ;
      RECT 178.6 6.32 179.6 10.32 ;
      RECT 178.6 10.72 179.6 14.72 ;
      RECT 178.6 15.12 179.6 19.12 ;
      RECT 178.6 19.52 179.6 23.52 ;
      RECT 178.6 23.92 179.6 27.92 ;
      RECT 178.6 28.32 179.6 32.32 ;
      RECT 178.6 32.72 179.6 36.72 ;
      RECT 178.6 37.12 179.6 41.12 ;
      RECT 178.6 41.52 179.6 45.52 ;
      RECT 178.6 45.92 179.6 49.92 ;
      RECT 178.6 50.32 179.6 54.32 ;
      RECT 178.6 54.72 179.6 58.72 ;
      RECT 178.6 59.12 179.6 63.12 ;
      RECT 178.6 63.52 179.6 67.52 ;
      RECT 178.6 67.92 179.6 71.92 ;
      RECT 178.6 72.32 179.6 76.32 ;
      RECT 178.6 76.72 179.6 80.72 ;
      RECT 178.6 81.12 179.6 85.12 ;
      RECT 178.6 85.52 179.6 86.6 ;
      RECT 178.6 87 179.6 91 ;
      RECT 178.6 91.4 179.6 95.4 ;
      RECT 178.6 95.8 179.6 98.2 ;
      RECT 178.6 98.6 179.6 101.7 ;
      RECT 178.6 107.9 179.6 111.9 ;
      RECT 178.6 112.3 179.6 116.3 ;
      RECT 178.6 116.7 179.6 120.7 ;
      RECT 178.6 213.9 179.6 217.9 ;
      RECT 179.1 161.5 179.3 176.9 ;
      RECT 179.1 191.9 179.3 200.5 ;
      RECT 178.3 125.1 178.5 127.3 ;
      RECT 178.3 129.5 178.5 149.7 ;
      RECT 178.3 159.5 178.5 171.7 ;
      RECT 178.3 203.5 178.5 208.9 ;
      RECT 176 1 178 218.6 ;
      RECT 175.5 67.9 175.7 98.1 ;
      RECT 175.1 105.1 175.7 105.3 ;
      RECT 175.1 121.5 175.7 121.7 ;
      RECT 175.5 123.9 175.7 127.3 ;
      RECT 175.1 129.9 175.7 130.1 ;
      RECT 175.5 151.1 175.7 151.7 ;
      RECT 175.5 168.3 175.7 169.7 ;
      RECT 175.1 96.3 175.3 99.7 ;
      RECT 175.1 134.3 175.3 157.3 ;
      RECT 174.7 126.7 174.9 128.9 ;
      RECT 174.7 180.3 174.9 186.1 ;
      RECT 174.3 127.9 174.5 129.7 ;
      RECT 174.3 133.9 174.5 137.3 ;
      RECT 174.3 151.1 174.5 151.7 ;
      RECT 174.3 171.9 174.5 174.9 ;
      RECT 174.3 186.3 174.5 188.5 ;
      RECT 172 4 174 215.6 ;
      RECT 171.8 1.92 172.8 3.4 ;
      RECT 171.8 216.2 172.8 218.08 ;
      RECT 171.5 70.7 171.7 84.1 ;
      RECT 171.5 103.9 171.7 112.1 ;
      RECT 171.5 151.1 171.7 160.1 ;
      RECT 171.5 164.7 171.7 177.3 ;
      RECT 171.5 183.9 171.7 186.1 ;
      RECT 171.5 186.7 171.7 188.9 ;
      RECT 171.1 70.3 171.3 76.5 ;
      RECT 171.1 86.3 171.3 92.9 ;
      RECT 171.1 162.3 171.3 170.1 ;
      RECT 170.9 205.9 171.3 209 ;
      RECT 170.7 73.5 170.9 80.5 ;
      RECT 170.7 105.5 170.9 116.9 ;
      RECT 169.9 197.3 170.9 201.3 ;
      RECT 169.9 201.7 170.9 205.5 ;
      RECT 169.9 76.3 170.1 78.1 ;
      RECT 168.7 31.1 169.7 34.5 ;
      RECT 169.5 36.7 169.7 46.9 ;
      RECT 169.5 55.9 169.7 68.5 ;
      RECT 168.4 11.3 169.4 14.9 ;
      RECT 169.1 61.5 169.3 101.3 ;
      RECT 168.7 106.3 169.3 110.3 ;
      RECT 168.7 110.7 169.3 114.7 ;
      RECT 168.7 115.1 169.3 119.1 ;
      RECT 168.7 119.5 169.3 123.5 ;
      RECT 168.7 123.9 169.3 127.9 ;
      RECT 168.7 128.3 169.3 132.3 ;
      RECT 169.1 144.3 169.3 168.1 ;
      RECT 168.1 205.9 169.1 209 ;
      RECT 168.3 151.5 168.9 151.7 ;
      RECT 168.3 155.1 168.9 155.3 ;
      RECT 167.6 209.4 168.6 210.7 ;
      RECT 167.6 213.1 168.6 216.68 ;
      RECT 167.6 217.08 168.6 218.08 ;
      RECT 168.3 141.1 168.5 146.5 ;
      RECT 167.1 135.9 168.1 137.3 ;
      RECT 167.5 97.9 167.7 98.5 ;
      RECT 167.5 165.5 167.7 181.3 ;
      RECT 166.3 191.9 167.3 195.5 ;
      RECT 166.3 195.9 167.3 196.9 ;
      RECT 166.3 61.9 166.5 64.9 ;
      RECT 166.3 129.1 166.5 130.1 ;
      RECT 166.3 179.5 166.5 191.3 ;
      RECT 166.3 197.5 166.5 205.3 ;
      RECT 165.4 1.92 166.4 5.92 ;
      RECT 165.4 6.32 166.4 9.5 ;
      RECT 165.4 9.9 166.4 10.9 ;
      RECT 165.9 15.5 166.1 30.5 ;
      RECT 165.9 35.1 166.1 38.5 ;
      RECT 165.9 68.3 166.1 114.1 ;
      RECT 165.1 211.1 166.1 212.7 ;
      RECT 165.5 133.5 165.7 140.1 ;
      RECT 165.1 17.9 165.3 67.3 ;
      RECT 164.7 79.5 164.9 138.9 ;
      RECT 164.3 113.1 164.5 115.3 ;
      RECT 164.3 156.3 164.5 187.3 ;
      RECT 163.4 213.1 164.4 216.68 ;
      RECT 163.4 217.08 164.4 218.08 ;
      RECT 163.9 36.7 164.1 53.3 ;
      RECT 163.9 190.3 164.1 195.3 ;
      RECT 163.5 75.5 163.7 113.3 ;
      RECT 163.5 135.1 163.7 157.7 ;
      RECT 162.6 1.92 163.6 5.92 ;
      RECT 162.6 6.32 163.6 9.5 ;
      RECT 162.6 9.9 163.6 10.9 ;
      RECT 163.1 120.3 163.3 136.9 ;
      RECT 162.7 115.5 162.9 121.3 ;
      RECT 162.7 123.5 162.9 128.1 ;
      RECT 162.7 175.9 162.9 178.5 ;
      RECT 162.7 179.1 162.9 197.7 ;
      RECT 162.3 105.5 162.5 130.9 ;
      RECT 162.3 158.7 162.5 183.3 ;
      RECT 161.2 1.92 162.2 4.12 ;
      RECT 161.2 4.52 162.2 8.52 ;
      RECT 161.2 8.92 162.2 10.9 ;
      RECT 161.9 75.1 162.1 85.7 ;
      RECT 161.9 91.5 162.1 102.5 ;
      RECT 161.9 143.1 162.1 154.5 ;
      RECT 161.9 158.3 162.1 163.7 ;
      RECT 161.9 179.5 162.1 181.3 ;
      RECT 161.1 121.5 161.3 122.5 ;
      RECT 161.1 204.7 161.3 208.1 ;
      RECT 159.9 29.5 160.9 33.5 ;
      RECT 159.9 33.9 160.9 36.1 ;
      RECT 160.3 105.1 160.9 105.3 ;
      RECT 160.7 119.5 160.9 173.7 ;
      RECT 160.7 177.9 160.9 202.1 ;
      RECT 160.3 17.9 160.5 24.1 ;
      RECT 160.3 70.3 160.5 74.1 ;
      RECT 160.3 97.9 160.5 98.5 ;
      RECT 160.3 121.5 160.5 122.5 ;
      RECT 160.3 129.1 160.5 130.1 ;
      RECT 160.3 203.1 160.5 205.3 ;
      RECT 159.9 103.9 160.1 130.9 ;
      RECT 159.9 162.7 160.1 177.7 ;
      RECT 159.1 183.5 160.1 187.5 ;
      RECT 159.1 187.9 160.1 191.9 ;
      RECT 159.1 72.7 159.3 113.3 ;
      RECT 159.1 162.3 159.3 178.5 ;
      RECT 158.7 40.7 158.9 49.7 ;
      RECT 158.3 17.5 158.5 25.7 ;
      RECT 158.3 73.5 158.5 91.7 ;
      RECT 158.3 96.7 158.5 139.7 ;
      RECT 157.9 75.1 158.1 86.1 ;
      RECT 157 1.92 158 5.92 ;
      RECT 157 6.32 158 9.5 ;
      RECT 157 9.9 158 10.9 ;
      RECT 157.5 86.3 157.7 106.1 ;
      RECT 157.5 114.7 157.7 120.5 ;
      RECT 156.7 211.1 157.7 212.7 ;
      RECT 156.7 120.7 156.9 144.5 ;
      RECT 156.7 172.3 156.9 190.9 ;
      RECT 156.7 193.9 156.9 202.5 ;
      RECT 155.7 16.6 156.7 20.5 ;
      RECT 156.3 30.3 156.5 33.3 ;
      RECT 155.3 211.1 156.3 212.7 ;
      RECT 155.9 23.5 156.1 44.1 ;
      RECT 155.9 182.7 156.1 198.5 ;
      RECT 154.8 11.3 155.8 14.8 ;
      RECT 154.8 15.2 155.8 16.2 ;
      RECT 155.5 66.7 155.7 112.1 ;
      RECT 155.5 163.9 155.7 174.5 ;
      RECT 155.1 138.3 155.3 152.9 ;
      RECT 155.1 165.5 155.3 190.5 ;
      RECT 154.7 121.5 154.9 137.7 ;
      RECT 154.7 170.7 154.9 177.3 ;
      RECT 154.7 195.5 154.9 210.5 ;
      RECT 154.3 31.5 154.5 39.3 ;
      RECT 154.3 115.1 154.5 120.5 ;
      RECT 154.3 171.9 154.5 189.7 ;
      RECT 153.9 50.7 154.1 72.5 ;
      RECT 153.9 136.3 154.1 161.3 ;
      RECT 153.5 17.1 153.7 20.5 ;
      RECT 153.5 167.1 153.7 200.5 ;
      RECT 153.1 55.9 153.3 70.5 ;
      RECT 153.1 86.7 153.3 119.3 ;
      RECT 152.7 27.5 152.9 33.7 ;
      RECT 152.7 68.3 152.9 70.1 ;
      RECT 152.7 79.1 152.9 82.9 ;
      RECT 152.3 97.9 152.9 98.1 ;
      RECT 152.7 122.7 152.9 162.1 ;
      RECT 152.7 170.3 152.9 174.1 ;
      RECT 152.3 99.5 152.5 102.9 ;
      RECT 151.5 194.7 152.1 194.9 ;
      RECT 151.5 157.9 151.7 185.3 ;
      RECT 150 1.92 151 4.12 ;
      RECT 150 4.52 151 8.52 ;
      RECT 150 8.92 151 10.9 ;
      RECT 150 18.3 151 20.5 ;
      RECT 150 20.9 151 24.9 ;
      RECT 150 25.3 151 26.9 ;
      RECT 150 27.3 151 31.3 ;
      RECT 150 31.7 151 32.9 ;
      RECT 150.7 109.9 150.9 126.1 ;
      RECT 150.7 145.9 150.9 169.3 ;
      RECT 150.3 210.7 150.5 212.5 ;
      RECT 149.4 207.8 150.4 210.1 ;
      RECT 149.4 213.1 150.4 216.68 ;
      RECT 149.4 217.08 150.4 218.08 ;
      RECT 149.9 123.5 150.1 129.7 ;
      RECT 149.9 147.5 150.1 164.1 ;
      RECT 149.6 115.5 150 119.5 ;
      RECT 149.5 157.1 149.7 164.9 ;
      RECT 149.1 124.3 149.3 139.7 ;
      RECT 149.1 154.3 149.3 162.5 ;
      RECT 148.7 45.9 148.9 76.1 ;
      RECT 148.7 93.9 148.9 110.5 ;
      RECT 148.7 126.3 148.9 134.9 ;
      RECT 148.7 137.9 148.9 163.7 ;
      RECT 148.7 173.5 148.9 178.9 ;
      RECT 148.3 33.5 148.5 44.5 ;
      RECT 148.3 175.1 148.5 178.1 ;
      RECT 148.3 197.5 148.5 199.3 ;
      RECT 146 1 148 218.6 ;
      RECT 145.5 16.7 145.7 20.5 ;
      RECT 145.5 21.9 145.7 30.1 ;
      RECT 145.5 35.1 145.7 40.1 ;
      RECT 145.5 41.5 145.7 44.5 ;
      RECT 145.5 45.1 145.7 50.5 ;
      RECT 145.5 159.1 145.7 178.1 ;
      RECT 145.1 135.9 145.3 144.9 ;
      RECT 145.1 146.3 145.3 147.7 ;
      RECT 145.1 174.7 145.3 219.3 ;
      RECT 144.7 62.7 144.9 113.3 ;
      RECT 144.7 121.9 144.9 128.1 ;
      RECT 144.7 175.1 144.9 176.9 ;
      RECT 144.3 19.9 144.5 34.1 ;
      RECT 144.3 88.3 144.5 90.9 ;
      RECT 144.3 131.1 144.5 140.1 ;
      RECT 144.3 145.9 144.5 154.5 ;
      RECT 144.3 164.3 144.5 169.7 ;
      RECT 144.3 171.1 144.5 173.7 ;
      RECT 144.3 198.3 144.5 208.9 ;
      RECT 142 4 144 215.6 ;
      RECT 141 1.92 142 3.4 ;
      RECT 141.5 51.9 141.7 62.5 ;
      RECT 141.5 99.1 141.7 131.7 ;
      RECT 141.5 148.3 141.7 150.9 ;
      RECT 141.5 157.5 141.7 176.1 ;
      RECT 141.5 200.7 141.7 202.9 ;
      RECT 141 3.8 141.4 7.8 ;
      RECT 141 74.2 141.4 78.2 ;
      RECT 141 78.6 141.4 82.6 ;
      RECT 141 83 141.4 86.5 ;
      RECT 141.1 133.5 141.3 134.5 ;
      RECT 141.1 162.3 141.3 172.5 ;
      RECT 141.1 174.7 141.3 196.1 ;
      RECT 140.7 15.5 140.9 18.1 ;
      RECT 140.7 87.1 140.9 97.3 ;
      RECT 140.7 111.9 140.9 116.5 ;
      RECT 140.7 139.9 140.9 148.9 ;
      RECT 140.7 169.9 140.9 175.7 ;
      RECT 140.7 183.1 140.9 190.5 ;
      RECT 139.6 1.92 140.6 4.12 ;
      RECT 139.6 4.52 140.6 8.52 ;
      RECT 140.3 26.3 140.5 28.5 ;
      RECT 140.3 56.7 140.5 61.3 ;
      RECT 140.3 173.1 140.5 174.9 ;
      RECT 140.3 178.7 140.5 193.3 ;
      RECT 140.3 195.5 140.5 200.5 ;
      RECT 139.9 21.1 140.1 30.1 ;
      RECT 138.9 41.5 139.9 44.1 ;
      RECT 139.5 90.3 139.7 92.1 ;
      RECT 138.7 80.7 138.9 100.9 ;
      RECT 138.7 179.9 138.9 200.9 ;
      RECT 137.6 31.7 138.6 35.7 ;
      RECT 138.3 44.7 138.5 110.9 ;
      RECT 138.3 150.3 138.5 171.7 ;
      RECT 138.3 180.3 138.5 186.1 ;
      RECT 137.9 117.5 138.1 130.5 ;
      RECT 137.9 209.9 138.1 211.7 ;
      RECT 137 12.2 138 13.4 ;
      RECT 137.5 51.9 137.7 58.9 ;
      RECT 137.5 183.9 137.7 189.7 ;
      RECT 136.7 194.7 137.7 194.9 ;
      RECT 136.3 26.3 137.3 29.9 ;
      RECT 137.1 175.1 137.3 177.7 ;
      RECT 136.7 198.7 136.9 205.7 ;
      RECT 136.3 19.9 136.5 25.7 ;
      RECT 136.3 127.9 136.5 140.9 ;
      RECT 136.3 192.7 136.5 209.3 ;
      RECT 135.9 195.1 136.1 198.1 ;
      RECT 135.5 15.9 135.7 38.9 ;
      RECT 134.7 93.9 135.3 97.9 ;
      RECT 134.7 98.3 135.3 102.3 ;
      RECT 134.7 64.7 134.9 88.9 ;
      RECT 133.9 55.1 134.1 114.5 ;
      RECT 133.9 127.1 134.1 152.9 ;
      RECT 133.9 195.9 134.1 209.7 ;
      RECT 133.5 60.7 133.7 62.5 ;
      RECT 133.5 103.1 133.7 104.1 ;
      RECT 133.5 119.9 133.7 174.9 ;
      RECT 132.5 25.3 133.5 27.5 ;
      RECT 132.5 27.9 133.5 31.9 ;
      RECT 132.5 32.3 133.5 35.7 ;
      RECT 133.1 116.3 133.3 128.9 ;
      RECT 133.1 144.3 133.3 165.3 ;
      RECT 132.7 37.1 132.9 47.7 ;
      RECT 132.7 131.9 132.9 160.9 ;
      RECT 132.3 92.3 132.5 118.1 ;
      RECT 132.3 189.1 132.5 196.5 ;
      RECT 131.2 1.92 132.2 4.12 ;
      RECT 131.2 4.52 132.2 8.52 ;
      RECT 131.2 8.92 132.2 11.8 ;
      RECT 130.8 216.7 131.8 218.08 ;
      RECT 131.5 36.3 131.7 39.3 ;
      RECT 131.5 99.1 131.7 104.9 ;
      RECT 131.5 115.5 131.7 152.1 ;
      RECT 129.6 44.6 130.6 45.7 ;
      RECT 129.6 61.9 130.6 65.9 ;
      RECT 129.6 66.3 130.6 70.3 ;
      RECT 129.6 70.7 130.6 73.3 ;
      RECT 130.3 25.5 130.5 36.1 ;
      RECT 130.3 49.9 130.5 54.5 ;
      RECT 130.3 135.9 130.5 152.9 ;
      RECT 129.4 216.7 130.4 218.08 ;
      RECT 128.6 12.2 129.6 13.4 ;
      RECT 128.6 41 129.6 44.2 ;
      RECT 128.7 46.3 128.9 54.1 ;
      RECT 128.7 80.7 128.9 92.9 ;
      RECT 128.7 144.7 128.9 172.1 ;
      RECT 128.3 50.7 128.5 54.9 ;
      RECT 128.3 138.3 128.5 158.5 ;
      RECT 127.5 79.5 128.1 79.7 ;
      RECT 127.9 191.9 128.1 210.5 ;
      RECT 126.8 30.7 127.8 34.7 ;
      RECT 126.8 35.1 127.8 36.5 ;
      RECT 126.8 61.9 127.8 65.9 ;
      RECT 126.8 66.3 127.8 70.3 ;
      RECT 127.5 50.7 127.7 56.9 ;
      RECT 127.5 179.1 127.7 204.1 ;
      RECT 126.6 216.7 127.6 218.08 ;
      RECT 127.1 14.7 127.3 20.5 ;
      RECT 127.1 147.5 127.3 149.3 ;
      RECT 125.9 37.1 126.9 37.3 ;
      RECT 126.7 73.9 126.9 78.1 ;
      RECT 126.7 137.1 126.9 164.9 ;
      RECT 126.3 15.9 126.5 30.1 ;
      RECT 126.3 143.9 126.5 150.5 ;
      RECT 125.4 30.7 126.4 34.7 ;
      RECT 125.2 216.7 126.2 218.08 ;
      RECT 125.9 62.3 126.1 110.5 ;
      RECT 125.9 120.3 126.1 201.7 ;
      RECT 125.5 22.3 125.7 24.5 ;
      RECT 125.5 132.7 125.7 134.1 ;
      RECT 124.4 209.5 125.4 211.9 ;
      RECT 125.1 18.7 125.3 20.5 ;
      RECT 125.1 127.1 125.3 168.9 ;
      RECT 124.1 205.9 125.1 209.1 ;
      RECT 124.7 103.5 124.9 115.7 ;
      RECT 124.7 122.7 124.9 131.3 ;
      RECT 123.5 93.4 124.5 97.4 ;
      RECT 123.5 97.8 124.5 101.5 ;
      RECT 123.9 153.5 124.1 162.9 ;
      RECT 123 209.5 124 211.9 ;
      RECT 122.3 125.9 122.5 135.7 ;
      RECT 122.3 160.3 122.5 162.9 ;
      RECT 121.5 26.3 121.7 74.5 ;
      RECT 120.7 104.3 120.9 116.9 ;
      RECT 120.3 131.5 120.5 149.7 ;
      RECT 119.9 65.1 120.1 110.9 ;
      RECT 119.9 165.5 120.1 211.7 ;
      RECT 119.5 130.3 119.7 180.9 ;
      RECT 118.6 1.92 119.6 5.92 ;
      RECT 118.6 6.32 119.6 10.32 ;
      RECT 118.6 10.72 119.6 11.8 ;
      RECT 118.6 12.2 119.6 16.2 ;
      RECT 118.6 16.6 119.6 20.6 ;
      RECT 118.6 21 119.6 24.3 ;
      RECT 118.6 24.7 119.6 25.7 ;
      RECT 118.6 26.1 119.6 30.1 ;
      RECT 118.6 30.5 119.6 34.5 ;
      RECT 118.6 34.9 119.6 38.9 ;
      RECT 118.6 39.3 119.6 43.3 ;
      RECT 118.6 43.7 119.6 47.7 ;
      RECT 118.6 48.1 119.6 52.1 ;
      RECT 118.6 52.5 119.6 56.5 ;
      RECT 118.6 121.9 119.6 125.9 ;
      RECT 118.6 126.3 119.6 129.7 ;
      RECT 119.1 104.3 119.3 111.7 ;
      RECT 118.6 211.9 119.2 215.9 ;
      RECT 118.6 216.3 119.2 218.08 ;
      RECT 118.7 59.9 118.9 116.5 ;
      RECT 118.7 139.5 118.9 206.9 ;
      RECT 118.3 151.5 118.5 159.7 ;
      RECT 116 1 118 218.6 ;
      RECT 115.5 163.9 115.7 172.1 ;
      RECT 115.5 179.5 115.7 183.3 ;
      RECT 114.7 79.5 115.3 79.7 ;
      RECT 114.7 177.5 114.9 192.1 ;
      RECT 114.3 58.3 114.5 87.7 ;
      RECT 112 4 114 215.6 ;
      RECT 111.8 1.92 112.8 3.4 ;
      RECT 111.8 216.2 112.8 218.08 ;
      RECT 111.5 32.3 111.7 39.3 ;
      RECT 111.5 193.1 111.7 198.9 ;
      RECT 110.8 1.92 111.4 4.12 ;
      RECT 110.8 4.52 111.4 8.52 ;
      RECT 110.8 8.92 111.4 12.92 ;
      RECT 110.8 13.32 111.4 14.6 ;
      RECT 110.8 20.6 111.4 22.2 ;
      RECT 111.1 136.3 111.3 138.5 ;
      RECT 110.7 182.3 110.9 189.7 ;
      RECT 110.3 137.1 110.5 138.9 ;
      RECT 109.5 123.9 109.7 174.9 ;
      RECT 108.2 43.9 109.2 45.1 ;
      RECT 108.2 45.5 109.2 49.5 ;
      RECT 108.2 49.9 109.2 53.9 ;
      RECT 108.2 54.3 109.2 57.6 ;
      RECT 108.2 58 109.2 59 ;
      RECT 108.2 89.5 109.2 93.5 ;
      RECT 108.2 93.9 109.2 97.9 ;
      RECT 108.2 98.3 109.2 102.3 ;
      RECT 108.2 102.7 109.2 106.7 ;
      RECT 108.2 107.1 109.2 111.1 ;
      RECT 108.2 111.5 109.2 112.8 ;
      RECT 108.2 211.5 109.2 215.5 ;
      RECT 108.2 215.9 109.2 218.08 ;
      RECT 108.2 1.92 109 5.92 ;
      RECT 108.2 6.32 109 10.32 ;
      RECT 108.7 61.5 108.9 88.9 ;
      RECT 107.7 28.2 108.7 30.4 ;
      RECT 107.7 30.8 108.7 34.8 ;
      RECT 107.7 35.2 108.7 36.9 ;
      RECT 107.7 39.9 108.7 43.5 ;
      RECT 107.5 37.3 108.5 39.5 ;
      RECT 107.4 117.4 108.4 121.2 ;
      RECT 107.4 121.6 108.4 122.6 ;
      RECT 107.9 159.9 108.1 164.5 ;
      RECT 107 26.6 108 27.8 ;
      RECT 106.3 28.2 107.3 32.2 ;
      RECT 106.3 32.6 107.3 36.6 ;
      RECT 106.3 39.9 107.3 43.5 ;
      RECT 106.1 37.3 107.1 39.5 ;
      RECT 106 59.4 107 62.2 ;
      RECT 105.6 26.6 106.6 27.8 ;
      RECT 105.3 145.4 106.3 149.4 ;
      RECT 105.3 149.8 106.3 153.8 ;
      RECT 105.3 154.2 106.3 157.9 ;
      RECT 105.3 158.3 106.3 159.3 ;
      RECT 105.3 167.8 106.3 171.6 ;
      RECT 105.3 172 106.3 173 ;
      RECT 105.3 177.8 106.3 179.5 ;
      RECT 104.9 30.8 105.9 34.8 ;
      RECT 104.6 59.4 105.6 62.2 ;
      RECT 104.4 69.4 105.4 70.6 ;
      RECT 104.1 199.3 105.1 203.3 ;
      RECT 104.1 203.9 105.1 205.6 ;
      RECT 103.9 148.5 104.9 152.5 ;
      RECT 103.9 152.9 104.9 156.9 ;
      RECT 103.9 157.3 104.9 161.3 ;
      RECT 103.9 161.7 104.9 163 ;
      RECT 103.9 167.8 104.9 171.6 ;
      RECT 103.9 172 104.9 173 ;
      RECT 103.9 173.4 104.9 177.4 ;
      RECT 103.9 177.8 104.9 179.5 ;
      RECT 103.9 37.5 104.1 39.3 ;
      RECT 102.9 206 103.9 209.6 ;
      RECT 102.9 210 103.9 211 ;
      RECT 103.1 188.3 103.3 196.5 ;
      RECT 101.2 1.92 102.2 4.12 ;
      RECT 101.2 4.52 102.2 8.52 ;
      RECT 101.2 8.92 102.2 12.92 ;
      RECT 101.2 13.32 102.2 17.32 ;
      RECT 101.2 17.72 102.2 20.8 ;
      RECT 101.2 21.2 102.2 22.2 ;
      RECT 101.2 43.9 102.2 45.1 ;
      RECT 101.2 45.5 102.2 47.7 ;
      RECT 101.2 48.1 102.2 52.1 ;
      RECT 101.2 52.5 102.2 56.5 ;
      RECT 101.2 56.9 102.2 59 ;
      RECT 101.2 179.9 102.2 182.1 ;
      RECT 101.2 182.5 102.2 186.3 ;
      RECT 101.2 211.5 102.2 215.5 ;
      RECT 101.2 215.9 102.2 218.08 ;
      RECT 101 140.2 102 142.3 ;
      RECT 99.7 144.1 100.7 146.3 ;
      RECT 99.7 146.7 100.7 150.7 ;
      RECT 99.7 151.1 100.7 155.1 ;
      RECT 99.7 155.5 100.7 159.5 ;
      RECT 99.7 159.9 100.7 163 ;
      RECT 99.7 163.4 100.7 165.6 ;
      RECT 99.7 166 100.7 170 ;
      RECT 99.7 170.4 100.7 174.4 ;
      RECT 99.7 174.8 100.7 178.1 ;
      RECT 99.7 178.5 100.7 179.5 ;
      RECT 99.5 26.9 100.5 28.5 ;
      RECT 99.9 62.7 100.1 68.5 ;
      RECT 98.9 24.1 99.9 26.5 ;
      RECT 98.7 206 99.7 209.6 ;
      RECT 98.7 210 99.7 211 ;
      RECT 98.5 86.5 99.5 89.6 ;
      RECT 98.5 90 99.5 91 ;
      RECT 99.1 116.7 99.3 118.1 ;
      RECT 99.1 199.5 99.3 203.3 ;
      RECT 97.9 28.9 98.9 32.9 ;
      RECT 97.9 33.3 98.9 37.3 ;
      RECT 97.9 37.7 98.9 41.7 ;
      RECT 97.9 42.1 98.9 43.5 ;
      RECT 97.5 24.1 98.5 26.5 ;
      RECT 97.5 59.4 98.5 63.4 ;
      RECT 97.5 63.8 98.5 67.3 ;
      RECT 98.3 115.1 98.5 142.1 ;
      RECT 97.3 191.3 98.3 193.5 ;
      RECT 97.3 210 98.3 211 ;
      RECT 97.5 144.3 97.7 179.3 ;
      RECT 97.1 67.9 97.3 83.3 ;
      RECT 96.7 120.7 96.9 124.1 ;
      RECT 96.3 75.9 96.5 79.3 ;
      RECT 96.3 203.5 96.5 205.3 ;
      RECT 94.2 1.92 95.2 5.92 ;
      RECT 94.2 6.32 95.2 10.32 ;
      RECT 94.2 10.72 95.2 14.72 ;
      RECT 94.2 15.12 95.2 19.12 ;
      RECT 94.2 19.52 95.2 22.2 ;
      RECT 94.2 22.6 95.2 23.7 ;
      RECT 94.2 43.9 95.2 45.1 ;
      RECT 94.2 45.5 95.2 49.5 ;
      RECT 94.2 49.9 95.2 53.9 ;
      RECT 94.2 54.3 95.2 57.6 ;
      RECT 94.2 58 95.2 59 ;
      RECT 94.2 113.1 95.2 117.1 ;
      RECT 94.2 170.3 95.2 174.3 ;
      RECT 94.2 174.7 95.2 178.7 ;
      RECT 94.2 179.1 95.2 183.1 ;
      RECT 94.2 183.5 95.2 187.5 ;
      RECT 94.2 187.9 95.2 190.9 ;
      RECT 94.2 211.5 95.2 215.5 ;
      RECT 94.2 215.9 95.2 218.08 ;
      RECT 94 127.4 95 128.6 ;
      RECT 93.9 26.9 94.9 28.5 ;
      RECT 93.7 28.9 94.7 31.1 ;
      RECT 93.7 31.5 94.7 35.5 ;
      RECT 93.7 35.9 94.7 39.9 ;
      RECT 93.7 40.3 94.7 43.5 ;
      RECT 92.2 77.9 93.2 80.1 ;
      RECT 92.2 80.5 93.2 84.5 ;
      RECT 92.2 84.9 93.2 88.9 ;
      RECT 92.2 89.3 93.2 93.3 ;
      RECT 92.2 93.7 93.2 97.7 ;
      RECT 92.2 98.1 93.2 101.9 ;
      RECT 92.2 120.2 93.2 124.2 ;
      RECT 92.2 124.6 93.2 127 ;
      RECT 92.2 129 93.2 132.6 ;
      RECT 92.2 148.3 93.2 152.3 ;
      RECT 92.2 152.7 93.2 156.7 ;
      RECT 92.2 157.1 93.2 161.1 ;
      RECT 92.2 161.5 93.2 165.5 ;
      RECT 91.9 24.1 92.9 26.5 ;
      RECT 92.7 133.9 92.9 147.7 ;
      RECT 91.7 191.3 92.7 193.5 ;
      RECT 91.7 193.9 92.7 197.9 ;
      RECT 91.7 198.3 92.7 201.5 ;
      RECT 91.7 201.9 92.7 202.9 ;
      RECT 91.7 205.9 92.7 209.7 ;
      RECT 91.5 29.1 91.7 43.3 ;
      RECT 90.3 27.1 90.5 28.9 ;
      RECT 89.5 191.5 89.7 210.9 ;
      RECT 88.6 1.92 89.6 5.92 ;
      RECT 88.6 6.32 89.6 10.32 ;
      RECT 88.6 10.72 89.6 14.72 ;
      RECT 88.6 15.12 89.6 19.12 ;
      RECT 88.6 19.52 89.6 22.2 ;
      RECT 88.6 45.5 89.6 49.5 ;
      RECT 88.6 49.9 89.6 53.9 ;
      RECT 88.6 54.3 89.6 57.6 ;
      RECT 88.6 58 89.6 59 ;
      RECT 88.6 59.4 89.6 63.4 ;
      RECT 88.6 70.3 89.6 74.3 ;
      RECT 88.6 74.7 89.6 78.7 ;
      RECT 88.6 79.1 89.6 83.1 ;
      RECT 88.6 83.5 89.6 87.5 ;
      RECT 88.6 87.9 89.6 91.9 ;
      RECT 88.6 92.3 89.6 96.3 ;
      RECT 88.6 96.7 89.6 100.7 ;
      RECT 88.6 101.1 89.6 103.7 ;
      RECT 88.6 117.5 89.6 119.8 ;
      RECT 88.6 174.7 89.6 178.7 ;
      RECT 88.6 179.1 89.6 183.1 ;
      RECT 88.6 183.5 89.6 187.5 ;
      RECT 88.6 187.9 89.6 190.9 ;
      RECT 88.6 211.5 89.6 215.5 ;
      RECT 88.6 215.9 89.6 218.08 ;
      RECT 89.1 37.1 89.3 44.1 ;
      RECT 88.6 139 89 143 ;
      RECT 88.7 104.3 88.9 112.5 ;
      RECT 88.3 24.3 88.5 36.5 ;
      RECT 88.3 37.1 88.5 42.1 ;
      RECT 88.3 67.5 88.5 69.7 ;
      RECT 88.3 145.5 88.5 169.7 ;
      RECT 86 1 88 218.6 ;
      RECT 85.5 185.5 85.7 191.7 ;
      RECT 84.7 111.9 84.9 122.1 ;
      RECT 84.7 177.1 84.9 194.1 ;
      RECT 84.3 77.5 84.5 84.9 ;
      RECT 84.3 102.3 84.5 108.5 ;
      RECT 84.3 113.9 84.5 117.3 ;
      RECT 82 4 84 215.6 ;
      RECT 81.5 113.9 81.7 123.7 ;
      RECT 80.4 1.92 81.4 5.92 ;
      RECT 80.4 6.32 81.4 10.32 ;
      RECT 80.4 10.72 81.4 13.3 ;
      RECT 80.4 40.3 81.4 44.3 ;
      RECT 80.4 44.7 81.4 48.2 ;
      RECT 80.4 48.6 81.4 50.6 ;
      RECT 80.4 62.6 81.4 64.8 ;
      RECT 80.4 65.2 81.4 69.2 ;
      RECT 80.4 69.6 81.4 71.3 ;
      RECT 80.4 100.2 81.4 102.6 ;
      RECT 80.4 151.8 81.4 153 ;
      RECT 81.1 193.5 81.3 195.3 ;
      RECT 80 153.4 81 155.6 ;
      RECT 80 156 81 160 ;
      RECT 80 160.4 81 164.4 ;
      RECT 80 164.8 81 166.5 ;
      RECT 80 168.7 81 171.8 ;
      RECT 80.7 120.3 80.9 149.7 ;
      RECT 79.7 176.1 80.7 178.3 ;
      RECT 79.7 178.7 80.7 182.7 ;
      RECT 79.4 172.2 80.4 175.7 ;
      RECT 78.8 13.7 79.8 17.7 ;
      RECT 78.8 18.1 79.8 21.5 ;
      RECT 78.8 83.1 79.8 87.1 ;
      RECT 78.8 87.5 79.8 91.5 ;
      RECT 78.8 91.9 79.8 95.9 ;
      RECT 78.8 96.3 79.8 99.8 ;
      RECT 78.6 153.4 79.6 157.4 ;
      RECT 78.6 157.8 79.6 161.8 ;
      RECT 79.1 71.9 79.3 78.1 ;
      RECT 79.1 167.1 79.3 168.1 ;
      RECT 78.3 176.1 79.3 180.1 ;
      RECT 78.3 180.5 79.3 182.9 ;
      RECT 78 172.2 79 175.7 ;
      RECT 77.3 29.5 78.3 31.7 ;
      RECT 77.3 32.1 78.3 36.1 ;
      RECT 77.3 36.5 78.3 39.9 ;
      RECT 77.3 105.7 78.3 107.9 ;
      RECT 77.3 108.3 78.3 112.3 ;
      RECT 77.3 112.7 78.3 116.7 ;
      RECT 77.3 117.1 78.3 119.7 ;
      RECT 77.3 120.1 78.3 124.1 ;
      RECT 77.3 124.5 78.3 125.9 ;
      RECT 77.3 197.5 78.3 199.1 ;
      RECT 77.1 126.3 78.1 127.4 ;
      RECT 76.2 1.92 77.2 4.12 ;
      RECT 76.2 4.52 77.2 8.52 ;
      RECT 76.2 8.92 77.2 12.92 ;
      RECT 76.2 40.3 77.2 42.5 ;
      RECT 76.2 42.9 77.2 46.8 ;
      RECT 76.2 47.2 77.2 48.2 ;
      RECT 76.2 48.6 77.2 50.6 ;
      RECT 76.2 93.4 77.2 97.4 ;
      RECT 76.2 100.2 77.2 102.6 ;
      RECT 76.2 195.5 77.2 197.1 ;
      RECT 74.8 1.92 75.8 5.92 ;
      RECT 74.8 6.32 75.8 10.32 ;
      RECT 74.8 10.72 75.8 13.3 ;
      RECT 74.8 40.3 75.8 44.3 ;
      RECT 74.8 44.7 75.8 48.2 ;
      RECT 74.8 48.6 75.8 50.6 ;
      RECT 74.8 100.2 75.8 102.6 ;
      RECT 74.8 195.5 75.8 197.1 ;
      RECT 74.6 130.2 75.6 131.4 ;
      RECT 75.1 13.9 75.3 21.3 ;
      RECT 74.2 51 75.2 55 ;
      RECT 74.2 55.4 75.2 59.4 ;
      RECT 74.2 59.8 75.2 62.2 ;
      RECT 74.2 127.8 75.2 129.8 ;
      RECT 74.1 176.1 75.1 178.3 ;
      RECT 74.1 178.7 75.1 182.7 ;
      RECT 73.5 103 74.5 105.3 ;
      RECT 73.5 183.3 74.5 186.9 ;
      RECT 73.4 48.6 74.4 50.6 ;
      RECT 73.4 161.5 74.4 163.4 ;
      RECT 73.4 166.2 74.4 167.4 ;
      RECT 73.4 195.5 74.4 197.1 ;
      RECT 73 163.8 74 165.8 ;
      RECT 72.8 51 73.8 53.2 ;
      RECT 72.8 53.6 73.8 57.6 ;
      RECT 72.8 58 73.8 62 ;
      RECT 72.8 127.8 73.8 129.8 ;
      RECT 72.7 176.1 73.7 180.1 ;
      RECT 72.7 180.5 73.7 182.9 ;
      RECT 72.4 167.8 73.4 170 ;
      RECT 72.4 170.4 73.4 174.3 ;
      RECT 72.4 174.7 73.4 175.7 ;
      RECT 73.1 132.7 73.3 154.5 ;
      RECT 72 48.6 73 50.6 ;
      RECT 72 161.5 73 163.4 ;
      RECT 72 166.2 73 167.4 ;
      RECT 72 195.5 73 197.1 ;
      RECT 71.9 71.7 72.9 75.1 ;
      RECT 71.5 126.3 72.5 127.4 ;
      RECT 71.5 156.7 72.5 160.7 ;
      RECT 71.4 51 72.4 55 ;
      RECT 71.4 55.4 72.4 59.4 ;
      RECT 71.4 59.8 72.4 62.2 ;
      RECT 71.3 176.1 72.3 178.3 ;
      RECT 71.3 178.7 72.3 182.7 ;
      RECT 71.1 30.7 72.1 34.7 ;
      RECT 71 91.4 72 92.6 ;
      RECT 71 167.8 72 171.8 ;
      RECT 71 172.2 72 175.7 ;
      RECT 70.7 103 71.7 105.3 ;
      RECT 70.7 183.3 71.7 186.9 ;
      RECT 70.5 71.7 71.5 75.1 ;
      RECT 70.4 62.6 71.4 63.8 ;
      RECT 70 51 71 53.2 ;
      RECT 70 53.6 71 57.6 ;
      RECT 70 58 71 62 ;
      RECT 69.7 30.7 70.7 34.7 ;
      RECT 69.7 136.2 70.7 140.2 ;
      RECT 69.7 140.6 70.7 144.6 ;
      RECT 69.7 145 70.7 149 ;
      RECT 69.7 149.4 70.7 153.4 ;
      RECT 69.7 153.8 70.7 156.3 ;
      RECT 68.9 108.3 69.9 112.3 ;
      RECT 68.9 112.7 69.9 116.7 ;
      RECT 68.9 117.1 69.9 119.7 ;
      RECT 68.9 120.1 69.9 124.1 ;
      RECT 68.9 124.5 69.9 125.9 ;
      RECT 68.9 197.5 69.9 199.1 ;
      RECT 68.5 176.1 69.5 178.3 ;
      RECT 68.5 178.7 69.5 182.7 ;
      RECT 68.5 132 69.3 136 ;
      RECT 68.5 136.4 69.3 140.4 ;
      RECT 68.5 140.8 69.3 144.8 ;
      RECT 68.5 145.2 69.3 149.2 ;
      RECT 68.5 149.6 69.3 153.6 ;
      RECT 68.5 154 69.3 156.3 ;
      RECT 68.1 25.3 69.1 28.9 ;
      RECT 68.1 29.3 69.1 30.3 ;
      RECT 68.1 66.8 69.1 69.9 ;
      RECT 68.1 70.3 69.1 71.3 ;
      RECT 68.1 75.5 69.1 76.9 ;
      RECT 68.7 79.9 68.9 90.5 ;
      RECT 67.9 103 68.9 105.3 ;
      RECT 68.7 187.5 68.9 192.5 ;
      RECT 67.3 156.7 68.3 160.7 ;
      RECT 67.2 51 68.2 53.2 ;
      RECT 67.2 53.6 68.2 57.6 ;
      RECT 67.2 58 68.2 62 ;
      RECT 67.1 176.1 68.1 180.1 ;
      RECT 66.8 91.4 67.8 92.6 ;
      RECT 66.8 167.8 67.8 170 ;
      RECT 66.8 170.4 67.8 174.3 ;
      RECT 66.4 48.6 67.4 50.6 ;
      RECT 66.4 93 67.4 95.2 ;
      RECT 66.4 95.6 67.4 99.6 ;
      RECT 66.4 100 67.4 102.6 ;
      RECT 66.4 161.5 67.4 163.4 ;
      RECT 66.4 166.2 67.4 167.4 ;
      RECT 66.3 71.7 67.3 75.1 ;
      RECT 67.1 183.5 67.3 194.9 ;
      RECT 66.1 197.5 67.1 199.1 ;
      RECT 66 163.8 67 165.8 ;
      RECT 66.7 105.9 66.9 125.7 ;
      RECT 66.3 129.5 66.5 156.1 ;
      RECT 66.3 176.3 66.5 190.5 ;
      RECT 65 48.6 66 50.6 ;
      RECT 65 87.8 66 91 ;
      RECT 65 93 66 97 ;
      RECT 65 97.4 66 101.2 ;
      RECT 65 101.6 66 102.6 ;
      RECT 65 166.2 66 167.4 ;
      RECT 64.7 197.5 65.7 199.1 ;
      RECT 64.3 103 65.3 105.2 ;
      RECT 64.3 105.6 65.3 109.6 ;
      RECT 64.3 110 65.3 114 ;
      RECT 64.3 114.4 65.3 118.4 ;
      RECT 64.3 118.8 65.3 121.9 ;
      RECT 65.1 143.5 65.3 160.1 ;
      RECT 63.9 25.3 64.9 28.9 ;
      RECT 63.9 29.3 64.9 30.3 ;
      RECT 63.9 68.6 64.9 71.3 ;
      RECT 64.7 182.3 64.9 190.5 ;
      RECT 63.6 48.6 64.6 50.6 ;
      RECT 63.6 95.6 64.6 99.6 ;
      RECT 63.3 197.5 64.3 199.1 ;
      RECT 63.1 124.7 64.1 126.7 ;
      RECT 63.9 145.1 64.1 160.9 ;
      RECT 62.9 107.4 63.9 111.4 ;
      RECT 62.9 111.8 63.9 115.8 ;
      RECT 62.9 116.2 63.9 120.2 ;
      RECT 62.9 120.6 63.9 123.3 ;
      RECT 62.7 30.7 63.7 34.7 ;
      RECT 62.5 25.3 63.5 28.9 ;
      RECT 62.5 29.3 63.5 30.3 ;
      RECT 62.5 67.9 63.5 71.3 ;
      RECT 63.1 77.5 63.3 86.9 ;
      RECT 62.2 48.6 63.2 50.6 ;
      RECT 62.7 71.9 62.9 74.9 ;
      RECT 61.9 197.5 62.9 199.1 ;
      RECT 61.7 124.7 62.7 126.7 ;
      RECT 61.5 105.6 62.5 109.6 ;
      RECT 61.5 110 62.5 114 ;
      RECT 61.5 114.4 62.5 118.4 ;
      RECT 61.5 118.8 62.5 121.9 ;
      RECT 61.5 122.3 62.5 123.3 ;
      RECT 61.3 30.7 62.3 34.7 ;
      RECT 61.5 189.5 61.7 196.1 ;
      RECT 60.3 61.1 60.5 82.1 ;
      RECT 59.5 65.5 59.7 67.3 ;
      RECT 59.5 148.3 59.7 156.1 ;
      RECT 58.3 66.7 58.5 71.3 ;
      RECT 58.3 145.5 58.5 159.3 ;
      RECT 56 1 58 218.6 ;
      RECT 55.5 31.9 55.7 41.7 ;
      RECT 55.5 141.1 55.7 148.9 ;
      RECT 55.5 151.1 55.7 156.9 ;
      RECT 55.5 188.7 55.7 198.1 ;
      RECT 54.6 1.92 55.4 3.4 ;
      RECT 54.6 4.2 55.4 8.2 ;
      RECT 54.6 8.6 55.4 12.6 ;
      RECT 54.6 13 55.4 17 ;
      RECT 54.6 17.4 55.4 21.4 ;
      RECT 54.6 21.8 55.4 25 ;
      RECT 54.6 25.4 55.4 26.4 ;
      RECT 54.6 47 55.4 49.2 ;
      RECT 54.6 55.2 55.4 58.6 ;
      RECT 54.6 59 55.4 60 ;
      RECT 54.6 94.8 55.4 98.8 ;
      RECT 54.6 99.2 55.4 103.2 ;
      RECT 54.6 103.6 55.4 107.6 ;
      RECT 54.6 108 55.4 112 ;
      RECT 54.6 112.4 55.4 116.4 ;
      RECT 54.6 116.8 55.4 120.8 ;
      RECT 54.6 121.2 55.4 125.2 ;
      RECT 54.6 125.6 55.4 129.6 ;
      RECT 54.6 130 55.4 134 ;
      RECT 54.6 134.4 55.4 138.4 ;
      RECT 54.6 157.8 55.4 161.8 ;
      RECT 54.6 162.2 55.4 166.2 ;
      RECT 54.6 166.6 55.4 170.6 ;
      RECT 54.6 171 55.4 175 ;
      RECT 54.6 175.4 55.4 179.4 ;
      RECT 54.6 179.8 55.4 183.8 ;
      RECT 54.6 184.2 55.4 187.8 ;
      RECT 54.6 203.6 55.4 207.6 ;
      RECT 54.6 208 55.4 212 ;
      RECT 54.6 212.4 55.4 215.4 ;
      RECT 54.6 216.2 55.4 218.08 ;
      RECT 54.7 50.3 54.9 54.5 ;
      RECT 54.3 27.1 54.5 38.9 ;
      RECT 54.3 60.7 54.5 94.1 ;
      RECT 52 4 54 215.6 ;
      RECT 51.5 38.3 51.7 44.9 ;
      RECT 51.5 102.7 51.7 120.9 ;
      RECT 51.5 155.9 51.7 160.9 ;
      RECT 51.5 186.3 51.7 187.7 ;
      RECT 50.4 1.92 51.4 5.92 ;
      RECT 50.4 6.32 51.4 9.9 ;
      RECT 50.4 10.3 51.4 11.3 ;
      RECT 50.4 181.7 51.4 183.3 ;
      RECT 51.1 62.3 51.3 86.9 ;
      RECT 49.6 98.3 50.6 101 ;
      RECT 49.9 137.8 50.5 141.8 ;
      RECT 49.9 142.2 50.5 146.2 ;
      RECT 49.9 148.7 50.1 152.9 ;
      RECT 49.9 193.1 50.1 207.3 ;
      RECT 49 1.92 50 4.12 ;
      RECT 49 4.52 50 8.52 ;
      RECT 49 8.92 50 11.3 ;
      RECT 49 181.7 50 183.3 ;
      RECT 48.1 32.5 49.1 34.7 ;
      RECT 48.1 35.1 49.1 39.1 ;
      RECT 48.1 39.5 49.1 43.5 ;
      RECT 48.1 43.9 49.1 46.6 ;
      RECT 48.7 147.9 48.9 152.9 ;
      RECT 47.8 188.9 48.8 192.5 ;
      RECT 48.3 109.1 48.5 114.9 ;
      RECT 47.9 11.9 48.1 27.3 ;
      RECT 47.9 67.1 48.1 79.7 ;
      RECT 46.6 205.9 47.6 208.1 ;
      RECT 46.6 208.5 47.6 212.5 ;
      RECT 46.6 212.9 47.6 216.68 ;
      RECT 46.6 217.08 47.6 218.08 ;
      RECT 47.1 53.5 47.3 97.7 ;
      RECT 46.2 181.7 47.2 183.3 ;
      RECT 46 175 47 179 ;
      RECT 46 179.4 47 181.3 ;
      RECT 46.7 123.9 46.9 164.5 ;
      RECT 46.2 117.7 46.8 118.7 ;
      RECT 46.3 66.3 46.5 70.9 ;
      RECT 46.3 77.1 46.5 83.7 ;
      RECT 45.2 205.9 46.2 209.9 ;
      RECT 45.2 210.3 46.2 214.3 ;
      RECT 45.2 214.7 46.2 218.08 ;
      RECT 45.9 32.7 46.1 45.7 ;
      RECT 45.9 139.9 46.1 153.3 ;
      RECT 44.8 112 45.8 116 ;
      RECT 44.8 116.4 45.8 118.7 ;
      RECT 44.8 181.7 45.8 183.3 ;
      RECT 45.5 61.1 45.7 80.5 ;
      RECT 44.6 175 45.6 179 ;
      RECT 44.6 179.4 45.6 181.3 ;
      RECT 45.1 29.9 45.3 46.5 ;
      RECT 45.1 192.3 45.3 198.1 ;
      RECT 43.9 60.5 44.9 64.5 ;
      RECT 43.9 64.9 44.9 68.3 ;
      RECT 44.7 70.3 44.9 78.1 ;
      RECT 44.7 138.7 44.9 167.7 ;
      RECT 43.8 205.9 44.8 208.1 ;
      RECT 43.8 208.5 44.8 212.5 ;
      RECT 43.8 212.9 44.8 216.68 ;
      RECT 43.8 217.08 44.8 218.08 ;
      RECT 43.5 134.5 44.5 138.1 ;
      RECT 44.3 183.9 44.5 192.9 ;
      RECT 43.4 109.4 44.4 113.4 ;
      RECT 43.4 113.8 44.4 117.3 ;
      RECT 43.4 117.7 44.4 118.7 ;
      RECT 43.2 175 44.2 179 ;
      RECT 43.2 179.4 44.2 181.3 ;
      RECT 42.7 82.7 43.7 84.7 ;
      RECT 43.5 143.9 43.7 153.3 ;
      RECT 42.5 60.5 43.5 62.7 ;
      RECT 42.5 63.1 43.5 67.1 ;
      RECT 42.5 67.5 43.5 69.7 ;
      RECT 42.1 134.5 43.1 138.1 ;
      RECT 42 109.4 43 111.6 ;
      RECT 42 112 43 116 ;
      RECT 42 116.4 43 118.7 ;
      RECT 42.7 139.1 42.9 148.1 ;
      RECT 42.7 149.1 42.9 158.5 ;
      RECT 41.9 195.2 42.9 199.2 ;
      RECT 41.9 199.6 42.9 203.6 ;
      RECT 41.9 204 42.9 205.5 ;
      RECT 41.8 175 42.8 179 ;
      RECT 41.8 179.4 42.8 181.3 ;
      RECT 41.5 162.3 42.5 164.7 ;
      RECT 42.3 185.9 42.5 194.5 ;
      RECT 41.3 82.7 42.3 84.7 ;
      RECT 41 205.9 42 208.1 ;
      RECT 41 208.5 42 212.5 ;
      RECT 41 212.9 42 216.68 ;
      RECT 41 217.08 42 218.08 ;
      RECT 40.8 165.1 41.8 168.5 ;
      RECT 40.8 168.9 41.8 169.9 ;
      RECT 40.6 109.4 41.6 113.4 ;
      RECT 40.6 113.8 41.6 117.3 ;
      RECT 40.6 117.7 41.6 118.7 ;
      RECT 40.7 199.3 41.5 203.3 ;
      RECT 40.7 203.7 41.5 205.5 ;
      RECT 40.4 175 41.4 179 ;
      RECT 40.4 179.4 41.4 181.3 ;
      RECT 40.1 162.3 41.1 164.7 ;
      RECT 39.9 82.7 40.9 84.7 ;
      RECT 40.3 60.7 40.5 82.1 ;
      RECT 40.3 148.7 40.5 161.7 ;
      RECT 39.3 181.7 40.3 183.9 ;
      RECT 39.3 184.3 40.3 188.3 ;
      RECT 39.3 188.7 40.3 192.7 ;
      RECT 39.3 193.1 40.3 197.1 ;
      RECT 39.3 197.5 40.3 201.5 ;
      RECT 39.3 201.9 40.3 205.5 ;
      RECT 39.2 109.4 40.2 111.6 ;
      RECT 39.2 112 40.2 116 ;
      RECT 39.2 116.4 40.2 118.7 ;
      RECT 39.9 134.7 40.1 145.7 ;
      RECT 39 175 40 179 ;
      RECT 39 179.4 40 181.3 ;
      RECT 38.2 205.9 39.2 208.1 ;
      RECT 38.2 208.5 39.2 212.5 ;
      RECT 38.2 212.9 39.2 216.68 ;
      RECT 38.2 217.08 39.2 218.08 ;
      RECT 38 168.9 39 169.9 ;
      RECT 37.8 109.4 38.8 113.4 ;
      RECT 37.8 113.8 38.8 117.3 ;
      RECT 37.8 117.7 38.8 118.7 ;
      RECT 37.6 175 38.6 179 ;
      RECT 37.6 179.4 38.6 181.3 ;
      RECT 38.3 136.7 38.5 164.5 ;
      RECT 37.3 66.7 38.3 70.7 ;
      RECT 37.3 71.1 38.3 72.9 ;
      RECT 37.1 73.4 38.1 77.4 ;
      RECT 37.1 77.8 38.1 81.8 ;
      RECT 37.1 82.2 38.1 84.7 ;
      RECT 35.1 73.5 35.3 84.5 ;
      RECT 34.2 1.92 35.2 5.92 ;
      RECT 34.2 6.32 35.2 10.32 ;
      RECT 34.2 10.72 35.2 14.72 ;
      RECT 34.2 15.12 35.2 19.12 ;
      RECT 34.2 19.52 35.2 23.52 ;
      RECT 34.2 23.92 35.2 27.9 ;
      RECT 34.2 28.3 35.2 29.3 ;
      RECT 34.2 29.7 35.2 33.7 ;
      RECT 34.2 34.1 35.2 38.1 ;
      RECT 34.2 38.5 35.2 42.5 ;
      RECT 34.2 42.9 35.2 46.9 ;
      RECT 34.2 47.3 35.2 51.3 ;
      RECT 34.2 51.7 35.2 55.7 ;
      RECT 34.2 56.1 35.2 60.1 ;
      RECT 34.2 60.5 35.2 63.7 ;
      RECT 34.2 85.1 35.2 89.1 ;
      RECT 34.2 89.5 35.2 93.5 ;
      RECT 34.2 93.9 35.2 97.9 ;
      RECT 34.2 121.7 35.2 125.7 ;
      RECT 34.2 126.1 35.2 130.1 ;
      RECT 34.2 130.5 35.2 134.1 ;
      RECT 34.2 134.5 35.2 136.7 ;
      RECT 34.2 137.1 35.2 141.1 ;
      RECT 34 205.9 35 209.9 ;
      RECT 34 210.3 35 214.3 ;
      RECT 34 214.7 35 218.08 ;
      RECT 34.7 154.3 34.9 169.7 ;
      RECT 33.7 144.5 34.7 146.5 ;
      RECT 33.7 150.7 34.7 153.7 ;
      RECT 34.3 181.9 34.5 205.3 ;
      RECT 33.1 68.5 34.1 72.5 ;
      RECT 33.1 115.1 33.3 118.5 ;
      RECT 33.1 147.1 33.3 150.1 ;
      RECT 31.5 144.7 31.7 156.5 ;
      RECT 30.7 155.5 30.9 156.9 ;
      RECT 29.5 64.3 29.7 74.9 ;
      RECT 29.5 80.7 29.7 82.9 ;
      RECT 28.6 1.92 29.6 5.92 ;
      RECT 28.6 6.32 29.6 10.32 ;
      RECT 28.6 10.72 29.6 14.72 ;
      RECT 28.6 15.12 29.6 19.12 ;
      RECT 28.6 19.52 29.6 23.52 ;
      RECT 28.6 23.92 29.6 27.9 ;
      RECT 28.6 28.3 29.6 29.3 ;
      RECT 28.6 29.7 29.6 33.7 ;
      RECT 28.6 34.1 29.6 38.1 ;
      RECT 28.6 38.5 29.6 42.5 ;
      RECT 28.6 42.9 29.6 46.9 ;
      RECT 28.6 47.3 29.6 51.3 ;
      RECT 28.6 51.7 29.6 55.7 ;
      RECT 28.6 56.1 29.6 60.1 ;
      RECT 28.6 60.5 29.6 63.7 ;
      RECT 28.6 75.5 29.6 78.7 ;
      RECT 28.6 79.1 29.6 80.1 ;
      RECT 28.6 83.5 29.6 87.5 ;
      RECT 28.6 87.9 29.6 91.9 ;
      RECT 28.6 92.3 29.6 96.3 ;
      RECT 28.6 96.7 29.6 100.7 ;
      RECT 28.6 101.1 29.6 105.1 ;
      RECT 28.6 105.5 29.6 109.5 ;
      RECT 28.6 109.9 29.6 113.1 ;
      RECT 28.6 113.5 29.6 114.5 ;
      RECT 28.6 114.9 29.6 118.9 ;
      RECT 28.6 119.3 29.6 123.3 ;
      RECT 28.6 123.7 29.6 127.7 ;
      RECT 28.6 128.1 29.6 132.1 ;
      RECT 28.6 132.5 29.6 136.5 ;
      RECT 28.6 136.9 29.6 140.9 ;
      RECT 28.6 141.3 29.6 144.1 ;
      RECT 28.6 144.5 29.6 148.5 ;
      RECT 28.6 148.9 29.6 152.9 ;
      RECT 28.6 153.3 29.6 154.9 ;
      RECT 28.6 159.7 29.6 163.7 ;
      RECT 28.6 164.1 29.6 168.1 ;
      RECT 28.6 168.5 29.6 172.5 ;
      RECT 28.6 172.9 29.6 176.9 ;
      RECT 28.6 177.3 29.6 181.3 ;
      RECT 28.6 181.7 29.6 185.7 ;
      RECT 28.6 186.1 29.6 190.1 ;
      RECT 28.6 190.5 29.6 194.5 ;
      RECT 28.6 194.9 29.6 198.9 ;
      RECT 28.6 199.3 29.6 203.3 ;
      RECT 28.6 203.7 29.6 207.7 ;
      RECT 28.6 208.1 29.6 212.1 ;
      RECT 28.6 212.5 29.6 216.5 ;
      RECT 28.6 216.9 29.6 218.08 ;
      RECT 26 1 28 218.6 ;
      RECT 25.1 133.9 25.3 162.5 ;
      RECT 24.2 1.92 25.2 3.4 ;
      RECT 24.7 64.3 24.9 74.5 ;
      RECT 24.7 191.9 24.9 196.1 ;
      RECT 24.3 75.5 24.5 81.3 ;
      RECT 24.3 155.9 24.5 160.5 ;
      RECT 22 4 24 215.6 ;
      RECT 21.5 131.5 21.7 146.5 ;
      RECT 20.4 7.8 21.4 9 ;
      RECT 20.8 12.6 21.4 13.8 ;
      RECT 20.8 69.4 21.4 70.6 ;
      RECT 20.6 127.4 21.4 128.6 ;
      RECT 20.8 180.6 21.4 181.8 ;
      RECT 20.4 182.2 21.4 186 ;
      RECT 20.4 186.4 21.4 187.4 ;
      RECT 20.8 187.8 21.4 190 ;
      RECT 20.8 190.4 21.4 194.4 ;
      RECT 20.8 194.8 21.4 198.8 ;
      RECT 20.8 199.2 21.4 200.6 ;
      RECT 20.4 216.2 21.4 218.08 ;
      RECT 20 1.92 21 5.92 ;
      RECT 20 6.32 21 7.4 ;
      RECT 20.7 83.5 20.9 106.9 ;
      RECT 19.4 12.6 20.4 13.8 ;
      RECT 19.4 69.4 20.4 70.6 ;
      RECT 19.4 180.6 20.4 181.8 ;
      RECT 19.4 187.8 20.4 191.8 ;
      RECT 19.4 192.2 20.4 196.2 ;
      RECT 19.4 196.6 20.4 200.6 ;
      RECT 19.2 127.4 20.2 128.6 ;
      RECT 19 7.8 20 9 ;
      RECT 19 182.2 20 186 ;
      RECT 19 186.4 20 187.4 ;
      RECT 19 216.2 20 218.08 ;
      RECT 19.5 142.7 19.7 164.5 ;
      RECT 18.6 1.92 19.6 5.92 ;
      RECT 18.6 6.32 19.6 7.4 ;
      RECT 17 14.2 18 18.2 ;
      RECT 17 18.6 18 22.6 ;
      RECT 17 23 18 27 ;
      RECT 17 27.4 18 31.4 ;
      RECT 17 31.8 18 35.8 ;
      RECT 17 36.2 18 40.2 ;
      RECT 17 40.6 18 44.6 ;
      RECT 17 45 18 49 ;
      RECT 17 49.4 18 53.4 ;
      RECT 17 53.8 18 57.8 ;
      RECT 17 67 18 69 ;
      RECT 17 91.4 18 95.4 ;
      RECT 17 95.8 18 99.8 ;
      RECT 17 100.2 18 104.2 ;
      RECT 17 104.6 18 107.4 ;
      RECT 16.6 12.6 17.6 13.8 ;
      RECT 16.6 69.4 17.6 70.6 ;
      RECT 16.4 127.4 17.4 128.6 ;
      RECT 14.6 9.4 15.6 12.2 ;
      RECT 14.6 71 15.6 75 ;
      RECT 14.6 75.4 15.6 77.8 ;
      RECT 14.6 78.2 15.6 82.2 ;
      RECT 14.6 82.6 15.6 86.6 ;
      RECT 14.6 87 15.6 91 ;
      RECT 14.6 121.8 15.6 125.6 ;
      RECT 14.6 126 15.6 127 ;
      RECT 14.6 129 15.6 133 ;
      RECT 14.6 133.4 15.6 137.4 ;
      RECT 14.6 137.8 15.6 141.8 ;
      RECT 14.6 142.5 15.6 144.7 ;
      RECT 14.6 145.1 15.6 149.1 ;
      RECT 14.6 149.5 15.6 153.5 ;
      RECT 14.6 153.9 15.6 157.9 ;
      RECT 14.6 158.3 15.6 162.3 ;
      RECT 14.6 162.7 15.6 166.7 ;
      RECT 14.6 167.1 15.6 170.6 ;
      RECT 14.6 201 15.6 205 ;
      RECT 14.6 205.4 15.6 209.4 ;
      RECT 14.6 209.8 15.6 213.8 ;
      RECT 14.6 214.2 15.6 215.8 ;
      RECT 14.4 1.92 15.4 5.92 ;
      RECT 14.4 6.32 15.4 7.4 ;
      RECT 9 13.8 10 17.8 ;
      RECT 9 18.2 10 22.2 ;
      RECT 9 22.6 10 26.6 ;
      RECT 9 27 10 31 ;
      RECT 9 31.4 10 35.4 ;
      RECT 9 35.8 10 39.8 ;
      RECT 9 40.2 10 44.2 ;
      RECT 9 44.6 10 48.6 ;
      RECT 9 49 10 53 ;
      RECT 9 53.4 10 57.4 ;
      RECT 9 57.8 10 61.8 ;
      RECT 9 82.6 10 86.6 ;
      RECT 9 87 10 91 ;
      RECT 9 91.4 10 95.4 ;
      RECT 9 95.8 10 99.8 ;
      RECT 9 100.2 10 104.2 ;
      RECT 9 104.6 10 108.6 ;
      RECT 9 109 10 113 ;
      RECT 9 113.4 10 117.4 ;
      RECT 9 201.9 10 205.9 ;
      RECT 9 206.3 10 210.3 ;
      RECT 9 210.7 10 214.4 ;
      RECT 9 214.8 10 215.8 ;
      RECT 9.5 190.3 9.7 196.9 ;
      RECT 9 160.2 9.4 164.2 ;
      RECT 9 164.6 9.4 168.6 ;
      RECT 9 169 9.4 173 ;
      RECT 9 173.4 9.4 177.4 ;
      RECT 9 177.8 9.4 181.8 ;
      RECT 9 182.2 9.4 186.2 ;
      RECT 7.8 216.2 8.8 218.08 ;
      RECT 8 207.4 8.6 211.4 ;
      RECT 8 211.8 8.6 215.8 ;
      RECT 6.4 216.2 7.4 218.08 ;
      RECT 5 1.92 6 3.4 ;
      RECT 4 4 6 215.6 ;
      RECT 5 216.2 6 218.08 ;
      RECT 3.6 1.92 4.6 3.4 ;
      RECT 3.6 216.2 4.6 218.08 ;
      RECT 3.5 55.1 3.7 64.5 ;
      RECT 1 1 3 218.6 ;
  END
END PE_POOL

END LIBRARY
